VERSION 5.8 ;
BUSBITCHARS "[]" ;
DIVIDERCHAR "/" ;
UNITS
    DATABASE MICRONS 1000 ;
END UNITS

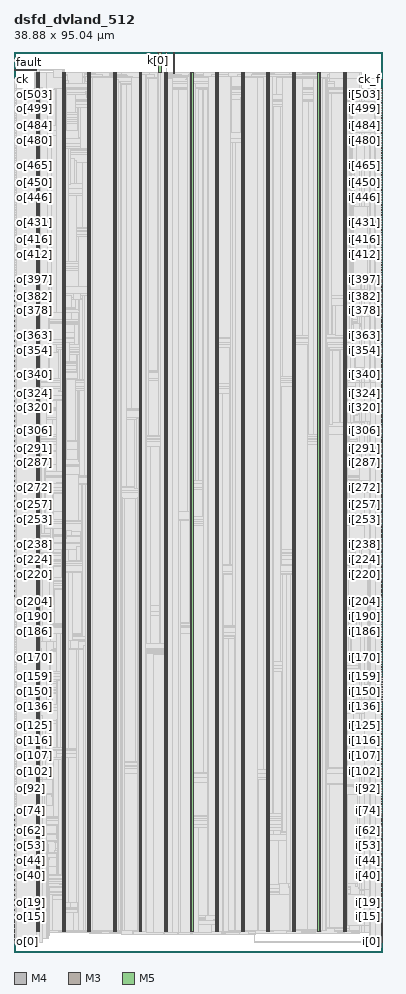
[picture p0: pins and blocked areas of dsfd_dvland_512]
MACRO dsfd_dvland_512
  FOREIGN dsfd_dvland_512 0 0 ;
  CLASS BLOCK ;
  SIZE 38.88 BY 95.04 ;
  PIN ck
    DIRECTION INPUT ;
    USE SIGNAL ;
    PORT
      LAYER M4 ;
        RECT  0 92.112 0.084 92.136 ;
    END
  END ck
  PIN ck_f
    DIRECTION INPUT ;
    USE SIGNAL ;
    PORT
      LAYER M4 ;
        RECT  38.796 92.112 38.88 92.136 ;
    END
  END ck_f
  PIN fault
    DIRECTION OUTPUT ;
    USE SIGNAL ;
    PORT
      LAYER M4 ;
        RECT  0 93.12 0.084 93.144 ;
    END
    PORT
      LAYER M4 ;
        RECT  0.06 93.12 2.408 93.144 ;
    END
  END fault
  PIN i[0]
    DIRECTION INPUT ;
    USE SIGNAL ;
    PORT
      LAYER M4 ;
        RECT  38.796 1.056 38.88 1.08 ;
    END
  END i[0]
  PIN i[100]
    DIRECTION INPUT ;
    USE SIGNAL ;
    PORT
      LAYER M4 ;
        RECT  38.796 18.72 38.88 18.744 ;
    END
  END i[100]
  PIN i[101]
    DIRECTION INPUT ;
    USE SIGNAL ;
    PORT
      LAYER M4 ;
        RECT  38.796 18.864 38.88 18.888 ;
    END
  END i[101]
  PIN i[102]
    DIRECTION INPUT ;
    USE SIGNAL ;
    PORT
      LAYER M4 ;
        RECT  38.796 19.056 38.88 19.08 ;
    END
  END i[102]
  PIN i[103]
    DIRECTION INPUT ;
    USE SIGNAL ;
    PORT
      LAYER M4 ;
        RECT  38.796 19.248 38.88 19.272 ;
    END
  END i[103]
  PIN i[104]
    DIRECTION INPUT ;
    USE SIGNAL ;
    PORT
      LAYER M4 ;
        RECT  38.796 19.392 38.88 19.416 ;
    END
  END i[104]
  PIN i[105]
    DIRECTION INPUT ;
    USE SIGNAL ;
    PORT
      LAYER M4 ;
        RECT  38.796 19.584 38.88 19.608 ;
    END
  END i[105]
  PIN i[106]
    DIRECTION INPUT ;
    USE SIGNAL ;
    PORT
      LAYER M4 ;
        RECT  38.796 19.776 38.88 19.8 ;
    END
  END i[106]
  PIN i[107]
    DIRECTION INPUT ;
    USE SIGNAL ;
    PORT
      LAYER M4 ;
        RECT  38.796 19.92 38.88 19.944 ;
    END
  END i[107]
  PIN i[108]
    DIRECTION INPUT ;
    USE SIGNAL ;
    PORT
      LAYER M4 ;
        RECT  38.796 20.112 38.88 20.136 ;
    END
  END i[108]
  PIN i[109]
    DIRECTION INPUT ;
    USE SIGNAL ;
    PORT
      LAYER M4 ;
        RECT  38.796 20.304 38.88 20.328 ;
    END
  END i[109]
  PIN i[10]
    DIRECTION INPUT ;
    USE SIGNAL ;
    PORT
      LAYER M4 ;
        RECT  38.796 2.832 38.88 2.856 ;
    END
  END i[10]
  PIN i[110]
    DIRECTION INPUT ;
    USE SIGNAL ;
    PORT
      LAYER M4 ;
        RECT  38.796 20.448 38.88 20.472 ;
    END
  END i[110]
  PIN i[111]
    DIRECTION INPUT ;
    USE SIGNAL ;
    PORT
      LAYER M4 ;
        RECT  38.796 20.64 38.88 20.664 ;
    END
  END i[111]
  PIN i[112]
    DIRECTION INPUT ;
    USE SIGNAL ;
    PORT
      LAYER M4 ;
        RECT  38.796 20.832 38.88 20.856 ;
    END
  END i[112]
  PIN i[113]
    DIRECTION INPUT ;
    USE SIGNAL ;
    PORT
      LAYER M4 ;
        RECT  38.796 20.976 38.88 21 ;
    END
  END i[113]
  PIN i[114]
    DIRECTION INPUT ;
    USE SIGNAL ;
    PORT
      LAYER M4 ;
        RECT  38.796 21.168 38.88 21.192 ;
    END
  END i[114]
  PIN i[115]
    DIRECTION INPUT ;
    USE SIGNAL ;
    PORT
      LAYER M4 ;
        RECT  38.796 21.36 38.88 21.384 ;
    END
  END i[115]
  PIN i[116]
    DIRECTION INPUT ;
    USE SIGNAL ;
    PORT
      LAYER M4 ;
        RECT  38.796 21.504 38.88 21.528 ;
    END
  END i[116]
  PIN i[117]
    DIRECTION INPUT ;
    USE SIGNAL ;
    PORT
      LAYER M4 ;
        RECT  38.796 21.696 38.88 21.72 ;
    END
  END i[117]
  PIN i[118]
    DIRECTION INPUT ;
    USE SIGNAL ;
    PORT
      LAYER M4 ;
        RECT  38.796 21.888 38.88 21.912 ;
    END
  END i[118]
  PIN i[119]
    DIRECTION INPUT ;
    USE SIGNAL ;
    PORT
      LAYER M4 ;
        RECT  38.796 22.032 38.88 22.056 ;
    END
  END i[119]
  PIN i[11]
    DIRECTION INPUT ;
    USE SIGNAL ;
    PORT
      LAYER M4 ;
        RECT  38.796 3.024 38.88 3.048 ;
    END
  END i[11]
  PIN i[120]
    DIRECTION INPUT ;
    USE SIGNAL ;
    PORT
      LAYER M4 ;
        RECT  38.796 22.224 38.88 22.248 ;
    END
  END i[120]
  PIN i[121]
    DIRECTION INPUT ;
    USE SIGNAL ;
    PORT
      LAYER M4 ;
        RECT  38.796 22.416 38.88 22.44 ;
    END
  END i[121]
  PIN i[122]
    DIRECTION INPUT ;
    USE SIGNAL ;
    PORT
      LAYER M4 ;
        RECT  38.796 22.56 38.88 22.584 ;
    END
  END i[122]
  PIN i[123]
    DIRECTION INPUT ;
    USE SIGNAL ;
    PORT
      LAYER M4 ;
        RECT  38.796 22.752 38.88 22.776 ;
    END
  END i[123]
  PIN i[124]
    DIRECTION INPUT ;
    USE SIGNAL ;
    PORT
      LAYER M4 ;
        RECT  38.796 22.944 38.88 22.968 ;
    END
  END i[124]
  PIN i[125]
    DIRECTION INPUT ;
    USE SIGNAL ;
    PORT
      LAYER M4 ;
        RECT  38.796 23.088 38.88 23.112 ;
    END
  END i[125]
  PIN i[126]
    DIRECTION INPUT ;
    USE SIGNAL ;
    PORT
      LAYER M4 ;
        RECT  38.796 23.28 38.88 23.304 ;
    END
  END i[126]
  PIN i[127]
    DIRECTION INPUT ;
    USE SIGNAL ;
    PORT
      LAYER M4 ;
        RECT  38.796 23.472 38.88 23.496 ;
    END
  END i[127]
  PIN i[128]
    DIRECTION INPUT ;
    USE SIGNAL ;
    PORT
      LAYER M4 ;
        RECT  38.796 23.616 38.88 23.64 ;
    END
  END i[128]
  PIN i[129]
    DIRECTION INPUT ;
    USE SIGNAL ;
    PORT
      LAYER M4 ;
        RECT  38.796 23.808 38.88 23.832 ;
    END
  END i[129]
  PIN i[12]
    DIRECTION INPUT ;
    USE SIGNAL ;
    PORT
      LAYER M4 ;
        RECT  38.796 3.168 38.88 3.192 ;
    END
  END i[12]
  PIN i[130]
    DIRECTION INPUT ;
    USE SIGNAL ;
    PORT
      LAYER M4 ;
        RECT  38.796 24 38.88 24.024 ;
    END
  END i[130]
  PIN i[131]
    DIRECTION INPUT ;
    USE SIGNAL ;
    PORT
      LAYER M4 ;
        RECT  38.796 24.144 38.88 24.168 ;
    END
  END i[131]
  PIN i[132]
    DIRECTION INPUT ;
    USE SIGNAL ;
    PORT
      LAYER M4 ;
        RECT  38.796 24.336 38.88 24.36 ;
    END
  END i[132]
  PIN i[133]
    DIRECTION INPUT ;
    USE SIGNAL ;
    PORT
      LAYER M4 ;
        RECT  38.796 24.528 38.88 24.552 ;
    END
  END i[133]
  PIN i[134]
    DIRECTION INPUT ;
    USE SIGNAL ;
    PORT
      LAYER M4 ;
        RECT  38.796 24.672 38.88 24.696 ;
    END
  END i[134]
  PIN i[135]
    DIRECTION INPUT ;
    USE SIGNAL ;
    PORT
      LAYER M4 ;
        RECT  38.796 24.864 38.88 24.888 ;
    END
  END i[135]
  PIN i[136]
    DIRECTION INPUT ;
    USE SIGNAL ;
    PORT
      LAYER M4 ;
        RECT  38.796 25.056 38.88 25.08 ;
    END
  END i[136]
  PIN i[137]
    DIRECTION INPUT ;
    USE SIGNAL ;
    PORT
      LAYER M4 ;
        RECT  38.796 25.2 38.88 25.224 ;
    END
  END i[137]
  PIN i[138]
    DIRECTION INPUT ;
    USE SIGNAL ;
    PORT
      LAYER M4 ;
        RECT  38.796 25.392 38.88 25.416 ;
    END
  END i[138]
  PIN i[139]
    DIRECTION INPUT ;
    USE SIGNAL ;
    PORT
      LAYER M4 ;
        RECT  38.796 25.584 38.88 25.608 ;
    END
  END i[139]
  PIN i[13]
    DIRECTION INPUT ;
    USE SIGNAL ;
    PORT
      LAYER M4 ;
        RECT  38.796 3.36 38.88 3.384 ;
    END
  END i[13]
  PIN i[140]
    DIRECTION INPUT ;
    USE SIGNAL ;
    PORT
      LAYER M4 ;
        RECT  38.796 25.728 38.88 25.752 ;
    END
  END i[140]
  PIN i[141]
    DIRECTION INPUT ;
    USE SIGNAL ;
    PORT
      LAYER M4 ;
        RECT  38.796 25.92 38.88 25.944 ;
    END
  END i[141]
  PIN i[142]
    DIRECTION INPUT ;
    USE SIGNAL ;
    PORT
      LAYER M4 ;
        RECT  38.796 26.112 38.88 26.136 ;
    END
  END i[142]
  PIN i[143]
    DIRECTION INPUT ;
    USE SIGNAL ;
    PORT
      LAYER M4 ;
        RECT  38.796 26.304 38.88 26.328 ;
    END
  END i[143]
  PIN i[144]
    DIRECTION INPUT ;
    USE SIGNAL ;
    PORT
      LAYER M4 ;
        RECT  38.796 26.448 38.88 26.472 ;
    END
  END i[144]
  PIN i[145]
    DIRECTION INPUT ;
    USE SIGNAL ;
    PORT
      LAYER M4 ;
        RECT  38.796 26.64 38.88 26.664 ;
    END
  END i[145]
  PIN i[146]
    DIRECTION INPUT ;
    USE SIGNAL ;
    PORT
      LAYER M4 ;
        RECT  38.796 26.832 38.88 26.856 ;
    END
  END i[146]
  PIN i[147]
    DIRECTION INPUT ;
    USE SIGNAL ;
    PORT
      LAYER M4 ;
        RECT  38.796 26.976 38.88 27 ;
    END
  END i[147]
  PIN i[148]
    DIRECTION INPUT ;
    USE SIGNAL ;
    PORT
      LAYER M4 ;
        RECT  38.796 27.168 38.88 27.192 ;
    END
  END i[148]
  PIN i[149]
    DIRECTION INPUT ;
    USE SIGNAL ;
    PORT
      LAYER M4 ;
        RECT  38.796 27.36 38.88 27.384 ;
    END
  END i[149]
  PIN i[14]
    DIRECTION INPUT ;
    USE SIGNAL ;
    PORT
      LAYER M4 ;
        RECT  38.796 3.552 38.88 3.576 ;
    END
  END i[14]
  PIN i[150]
    DIRECTION INPUT ;
    USE SIGNAL ;
    PORT
      LAYER M4 ;
        RECT  38.796 27.504 38.88 27.528 ;
    END
  END i[150]
  PIN i[151]
    DIRECTION INPUT ;
    USE SIGNAL ;
    PORT
      LAYER M4 ;
        RECT  38.796 27.696 38.88 27.72 ;
    END
  END i[151]
  PIN i[152]
    DIRECTION INPUT ;
    USE SIGNAL ;
    PORT
      LAYER M4 ;
        RECT  38.796 27.888 38.88 27.912 ;
    END
  END i[152]
  PIN i[153]
    DIRECTION INPUT ;
    USE SIGNAL ;
    PORT
      LAYER M4 ;
        RECT  38.796 28.032 38.88 28.056 ;
    END
  END i[153]
  PIN i[154]
    DIRECTION INPUT ;
    USE SIGNAL ;
    PORT
      LAYER M4 ;
        RECT  38.796 28.224 38.88 28.248 ;
    END
  END i[154]
  PIN i[155]
    DIRECTION INPUT ;
    USE SIGNAL ;
    PORT
      LAYER M4 ;
        RECT  38.796 28.416 38.88 28.44 ;
    END
  END i[155]
  PIN i[156]
    DIRECTION INPUT ;
    USE SIGNAL ;
    PORT
      LAYER M4 ;
        RECT  38.796 28.56 38.88 28.584 ;
    END
  END i[156]
  PIN i[157]
    DIRECTION INPUT ;
    USE SIGNAL ;
    PORT
      LAYER M4 ;
        RECT  38.796 28.752 38.88 28.776 ;
    END
  END i[157]
  PIN i[158]
    DIRECTION INPUT ;
    USE SIGNAL ;
    PORT
      LAYER M4 ;
        RECT  38.796 28.944 38.88 28.968 ;
    END
  END i[158]
  PIN i[159]
    DIRECTION INPUT ;
    USE SIGNAL ;
    PORT
      LAYER M4 ;
        RECT  38.796 29.088 38.88 29.112 ;
    END
  END i[159]
  PIN i[15]
    DIRECTION INPUT ;
    USE SIGNAL ;
    PORT
      LAYER M4 ;
        RECT  38.796 3.744 38.88 3.768 ;
    END
  END i[15]
  PIN i[160]
    DIRECTION INPUT ;
    USE SIGNAL ;
    PORT
      LAYER M4 ;
        RECT  38.796 29.28 38.88 29.304 ;
    END
  END i[160]
  PIN i[161]
    DIRECTION INPUT ;
    USE SIGNAL ;
    PORT
      LAYER M4 ;
        RECT  38.796 29.472 38.88 29.496 ;
    END
  END i[161]
  PIN i[162]
    DIRECTION INPUT ;
    USE SIGNAL ;
    PORT
      LAYER M4 ;
        RECT  38.796 29.616 38.88 29.64 ;
    END
  END i[162]
  PIN i[163]
    DIRECTION INPUT ;
    USE SIGNAL ;
    PORT
      LAYER M4 ;
        RECT  38.796 29.808 38.88 29.832 ;
    END
  END i[163]
  PIN i[164]
    DIRECTION INPUT ;
    USE SIGNAL ;
    PORT
      LAYER M4 ;
        RECT  38.796 30 38.88 30.024 ;
    END
  END i[164]
  PIN i[165]
    DIRECTION INPUT ;
    USE SIGNAL ;
    PORT
      LAYER M4 ;
        RECT  38.796 30.144 38.88 30.168 ;
    END
  END i[165]
  PIN i[166]
    DIRECTION INPUT ;
    USE SIGNAL ;
    PORT
      LAYER M4 ;
        RECT  38.796 30.336 38.88 30.36 ;
    END
  END i[166]
  PIN i[167]
    DIRECTION INPUT ;
    USE SIGNAL ;
    PORT
      LAYER M4 ;
        RECT  38.796 30.528 38.88 30.552 ;
    END
  END i[167]
  PIN i[168]
    DIRECTION INPUT ;
    USE SIGNAL ;
    PORT
      LAYER M4 ;
        RECT  38.796 30.672 38.88 30.696 ;
    END
  END i[168]
  PIN i[169]
    DIRECTION INPUT ;
    USE SIGNAL ;
    PORT
      LAYER M4 ;
        RECT  38.796 30.864 38.88 30.888 ;
    END
  END i[169]
  PIN i[16]
    DIRECTION INPUT ;
    USE SIGNAL ;
    PORT
      LAYER M4 ;
        RECT  38.796 3.888 38.88 3.912 ;
    END
  END i[16]
  PIN i[170]
    DIRECTION INPUT ;
    USE SIGNAL ;
    PORT
      LAYER M4 ;
        RECT  38.796 31.056 38.88 31.08 ;
    END
  END i[170]
  PIN i[171]
    DIRECTION INPUT ;
    USE SIGNAL ;
    PORT
      LAYER M4 ;
        RECT  38.796 31.2 38.88 31.224 ;
    END
  END i[171]
  PIN i[172]
    DIRECTION INPUT ;
    USE SIGNAL ;
    PORT
      LAYER M4 ;
        RECT  38.796 31.392 38.88 31.416 ;
    END
  END i[172]
  PIN i[173]
    DIRECTION INPUT ;
    USE SIGNAL ;
    PORT
      LAYER M4 ;
        RECT  38.796 31.584 38.88 31.608 ;
    END
  END i[173]
  PIN i[174]
    DIRECTION INPUT ;
    USE SIGNAL ;
    PORT
      LAYER M4 ;
        RECT  38.796 31.728 38.88 31.752 ;
    END
  END i[174]
  PIN i[175]
    DIRECTION INPUT ;
    USE SIGNAL ;
    PORT
      LAYER M4 ;
        RECT  38.796 31.92 38.88 31.944 ;
    END
  END i[175]
  PIN i[176]
    DIRECTION INPUT ;
    USE SIGNAL ;
    PORT
      LAYER M4 ;
        RECT  38.796 32.112 38.88 32.136 ;
    END
  END i[176]
  PIN i[177]
    DIRECTION INPUT ;
    USE SIGNAL ;
    PORT
      LAYER M4 ;
        RECT  38.796 32.256 38.88 32.28 ;
    END
  END i[177]
  PIN i[178]
    DIRECTION INPUT ;
    USE SIGNAL ;
    PORT
      LAYER M4 ;
        RECT  38.796 32.448 38.88 32.472 ;
    END
  END i[178]
  PIN i[179]
    DIRECTION INPUT ;
    USE SIGNAL ;
    PORT
      LAYER M4 ;
        RECT  38.796 32.64 38.88 32.664 ;
    END
  END i[179]
  PIN i[17]
    DIRECTION INPUT ;
    USE SIGNAL ;
    PORT
      LAYER M4 ;
        RECT  38.796 4.08 38.88 4.104 ;
    END
  END i[17]
  PIN i[180]
    DIRECTION INPUT ;
    USE SIGNAL ;
    PORT
      LAYER M4 ;
        RECT  38.796 32.784 38.88 32.808 ;
    END
  END i[180]
  PIN i[181]
    DIRECTION INPUT ;
    USE SIGNAL ;
    PORT
      LAYER M4 ;
        RECT  38.796 32.976 38.88 33 ;
    END
  END i[181]
  PIN i[182]
    DIRECTION INPUT ;
    USE SIGNAL ;
    PORT
      LAYER M4 ;
        RECT  38.796 33.168 38.88 33.192 ;
    END
  END i[182]
  PIN i[183]
    DIRECTION INPUT ;
    USE SIGNAL ;
    PORT
      LAYER M4 ;
        RECT  38.796 33.312 38.88 33.336 ;
    END
  END i[183]
  PIN i[184]
    DIRECTION INPUT ;
    USE SIGNAL ;
    PORT
      LAYER M4 ;
        RECT  38.796 33.504 38.88 33.528 ;
    END
  END i[184]
  PIN i[185]
    DIRECTION INPUT ;
    USE SIGNAL ;
    PORT
      LAYER M4 ;
        RECT  38.796 33.696 38.88 33.72 ;
    END
  END i[185]
  PIN i[186]
    DIRECTION INPUT ;
    USE SIGNAL ;
    PORT
      LAYER M4 ;
        RECT  38.796 33.84 38.88 33.864 ;
    END
  END i[186]
  PIN i[187]
    DIRECTION INPUT ;
    USE SIGNAL ;
    PORT
      LAYER M4 ;
        RECT  38.796 34.032 38.88 34.056 ;
    END
  END i[187]
  PIN i[188]
    DIRECTION INPUT ;
    USE SIGNAL ;
    PORT
      LAYER M4 ;
        RECT  38.796 34.224 38.88 34.248 ;
    END
  END i[188]
  PIN i[189]
    DIRECTION INPUT ;
    USE SIGNAL ;
    PORT
      LAYER M4 ;
        RECT  38.796 34.368 38.88 34.392 ;
    END
  END i[189]
  PIN i[18]
    DIRECTION INPUT ;
    USE SIGNAL ;
    PORT
      LAYER M4 ;
        RECT  38.796 4.272 38.88 4.296 ;
    END
  END i[18]
  PIN i[190]
    DIRECTION INPUT ;
    USE SIGNAL ;
    PORT
      LAYER M4 ;
        RECT  38.796 34.56 38.88 34.584 ;
    END
  END i[190]
  PIN i[191]
    DIRECTION INPUT ;
    USE SIGNAL ;
    PORT
      LAYER M4 ;
        RECT  38.796 34.752 38.88 34.776 ;
    END
  END i[191]
  PIN i[192]
    DIRECTION INPUT ;
    USE SIGNAL ;
    PORT
      LAYER M4 ;
        RECT  38.796 34.896 38.88 34.92 ;
    END
  END i[192]
  PIN i[193]
    DIRECTION INPUT ;
    USE SIGNAL ;
    PORT
      LAYER M4 ;
        RECT  38.796 35.088 38.88 35.112 ;
    END
  END i[193]
  PIN i[194]
    DIRECTION INPUT ;
    USE SIGNAL ;
    PORT
      LAYER M4 ;
        RECT  38.796 35.28 38.88 35.304 ;
    END
  END i[194]
  PIN i[195]
    DIRECTION INPUT ;
    USE SIGNAL ;
    PORT
      LAYER M4 ;
        RECT  38.796 35.424 38.88 35.448 ;
    END
  END i[195]
  PIN i[196]
    DIRECTION INPUT ;
    USE SIGNAL ;
    PORT
      LAYER M4 ;
        RECT  38.796 35.616 38.88 35.64 ;
    END
  END i[196]
  PIN i[197]
    DIRECTION INPUT ;
    USE SIGNAL ;
    PORT
      LAYER M4 ;
        RECT  38.796 35.808 38.88 35.832 ;
    END
  END i[197]
  PIN i[198]
    DIRECTION INPUT ;
    USE SIGNAL ;
    PORT
      LAYER M4 ;
        RECT  38.796 35.952 38.88 35.976 ;
    END
  END i[198]
  PIN i[199]
    DIRECTION INPUT ;
    USE SIGNAL ;
    PORT
      LAYER M4 ;
        RECT  38.796 36.144 38.88 36.168 ;
    END
  END i[199]
  PIN i[19]
    DIRECTION INPUT ;
    USE SIGNAL ;
    PORT
      LAYER M4 ;
        RECT  38.796 4.416 38.88 4.44 ;
    END
  END i[19]
  PIN i[1]
    DIRECTION INPUT ;
    USE SIGNAL ;
    PORT
      LAYER M4 ;
        RECT  38.796 1.248 38.88 1.272 ;
    END
  END i[1]
  PIN i[200]
    DIRECTION INPUT ;
    USE SIGNAL ;
    PORT
      LAYER M4 ;
        RECT  38.796 36.336 38.88 36.36 ;
    END
  END i[200]
  PIN i[201]
    DIRECTION INPUT ;
    USE SIGNAL ;
    PORT
      LAYER M4 ;
        RECT  38.796 36.48 38.88 36.504 ;
    END
  END i[201]
  PIN i[202]
    DIRECTION INPUT ;
    USE SIGNAL ;
    PORT
      LAYER M4 ;
        RECT  38.796 36.672 38.88 36.696 ;
    END
  END i[202]
  PIN i[203]
    DIRECTION INPUT ;
    USE SIGNAL ;
    PORT
      LAYER M4 ;
        RECT  38.796 36.864 38.88 36.888 ;
    END
  END i[203]
  PIN i[204]
    DIRECTION INPUT ;
    USE SIGNAL ;
    PORT
      LAYER M4 ;
        RECT  38.796 37.008 38.88 37.032 ;
    END
  END i[204]
  PIN i[205]
    DIRECTION INPUT ;
    USE SIGNAL ;
    PORT
      LAYER M4 ;
        RECT  38.796 37.2 38.88 37.224 ;
    END
  END i[205]
  PIN i[206]
    DIRECTION INPUT ;
    USE SIGNAL ;
    PORT
      LAYER M4 ;
        RECT  38.796 37.392 38.88 37.416 ;
    END
  END i[206]
  PIN i[207]
    DIRECTION INPUT ;
    USE SIGNAL ;
    PORT
      LAYER M4 ;
        RECT  38.796 37.584 38.88 37.608 ;
    END
  END i[207]
  PIN i[208]
    DIRECTION INPUT ;
    USE SIGNAL ;
    PORT
      LAYER M4 ;
        RECT  38.796 37.728 38.88 37.752 ;
    END
  END i[208]
  PIN i[209]
    DIRECTION INPUT ;
    USE SIGNAL ;
    PORT
      LAYER M4 ;
        RECT  38.796 37.92 38.88 37.944 ;
    END
  END i[209]
  PIN i[20]
    DIRECTION INPUT ;
    USE SIGNAL ;
    PORT
      LAYER M4 ;
        RECT  38.796 4.608 38.88 4.632 ;
    END
  END i[20]
  PIN i[210]
    DIRECTION INPUT ;
    USE SIGNAL ;
    PORT
      LAYER M4 ;
        RECT  38.796 38.112 38.88 38.136 ;
    END
  END i[210]
  PIN i[211]
    DIRECTION INPUT ;
    USE SIGNAL ;
    PORT
      LAYER M4 ;
        RECT  38.796 38.256 38.88 38.28 ;
    END
  END i[211]
  PIN i[212]
    DIRECTION INPUT ;
    USE SIGNAL ;
    PORT
      LAYER M4 ;
        RECT  38.796 38.448 38.88 38.472 ;
    END
  END i[212]
  PIN i[213]
    DIRECTION INPUT ;
    USE SIGNAL ;
    PORT
      LAYER M4 ;
        RECT  38.796 38.64 38.88 38.664 ;
    END
  END i[213]
  PIN i[214]
    DIRECTION INPUT ;
    USE SIGNAL ;
    PORT
      LAYER M4 ;
        RECT  38.796 38.784 38.88 38.808 ;
    END
  END i[214]
  PIN i[215]
    DIRECTION INPUT ;
    USE SIGNAL ;
    PORT
      LAYER M4 ;
        RECT  38.796 38.976 38.88 39 ;
    END
  END i[215]
  PIN i[216]
    DIRECTION INPUT ;
    USE SIGNAL ;
    PORT
      LAYER M4 ;
        RECT  38.796 39.168 38.88 39.192 ;
    END
  END i[216]
  PIN i[217]
    DIRECTION INPUT ;
    USE SIGNAL ;
    PORT
      LAYER M4 ;
        RECT  38.796 39.312 38.88 39.336 ;
    END
  END i[217]
  PIN i[218]
    DIRECTION INPUT ;
    USE SIGNAL ;
    PORT
      LAYER M4 ;
        RECT  38.796 39.504 38.88 39.528 ;
    END
  END i[218]
  PIN i[219]
    DIRECTION INPUT ;
    USE SIGNAL ;
    PORT
      LAYER M4 ;
        RECT  38.796 39.696 38.88 39.72 ;
    END
  END i[219]
  PIN i[21]
    DIRECTION INPUT ;
    USE SIGNAL ;
    PORT
      LAYER M4 ;
        RECT  38.796 4.8 38.88 4.824 ;
    END
  END i[21]
  PIN i[220]
    DIRECTION INPUT ;
    USE SIGNAL ;
    PORT
      LAYER M4 ;
        RECT  38.796 39.84 38.88 39.864 ;
    END
  END i[220]
  PIN i[221]
    DIRECTION INPUT ;
    USE SIGNAL ;
    PORT
      LAYER M4 ;
        RECT  38.796 40.032 38.88 40.056 ;
    END
  END i[221]
  PIN i[222]
    DIRECTION INPUT ;
    USE SIGNAL ;
    PORT
      LAYER M4 ;
        RECT  38.796 40.224 38.88 40.248 ;
    END
  END i[222]
  PIN i[223]
    DIRECTION INPUT ;
    USE SIGNAL ;
    PORT
      LAYER M4 ;
        RECT  38.796 40.368 38.88 40.392 ;
    END
  END i[223]
  PIN i[224]
    DIRECTION INPUT ;
    USE SIGNAL ;
    PORT
      LAYER M4 ;
        RECT  38.796 40.56 38.88 40.584 ;
    END
  END i[224]
  PIN i[225]
    DIRECTION INPUT ;
    USE SIGNAL ;
    PORT
      LAYER M4 ;
        RECT  38.796 40.752 38.88 40.776 ;
    END
  END i[225]
  PIN i[226]
    DIRECTION INPUT ;
    USE SIGNAL ;
    PORT
      LAYER M4 ;
        RECT  38.796 40.896 38.88 40.92 ;
    END
  END i[226]
  PIN i[227]
    DIRECTION INPUT ;
    USE SIGNAL ;
    PORT
      LAYER M4 ;
        RECT  38.796 41.088 38.88 41.112 ;
    END
  END i[227]
  PIN i[228]
    DIRECTION INPUT ;
    USE SIGNAL ;
    PORT
      LAYER M4 ;
        RECT  38.796 41.28 38.88 41.304 ;
    END
  END i[228]
  PIN i[229]
    DIRECTION INPUT ;
    USE SIGNAL ;
    PORT
      LAYER M4 ;
        RECT  38.796 41.424 38.88 41.448 ;
    END
  END i[229]
  PIN i[22]
    DIRECTION INPUT ;
    USE SIGNAL ;
    PORT
      LAYER M4 ;
        RECT  38.796 4.944 38.88 4.968 ;
    END
  END i[22]
  PIN i[230]
    DIRECTION INPUT ;
    USE SIGNAL ;
    PORT
      LAYER M4 ;
        RECT  38.796 41.616 38.88 41.64 ;
    END
  END i[230]
  PIN i[231]
    DIRECTION INPUT ;
    USE SIGNAL ;
    PORT
      LAYER M4 ;
        RECT  38.796 41.808 38.88 41.832 ;
    END
  END i[231]
  PIN i[232]
    DIRECTION INPUT ;
    USE SIGNAL ;
    PORT
      LAYER M4 ;
        RECT  38.796 41.952 38.88 41.976 ;
    END
  END i[232]
  PIN i[233]
    DIRECTION INPUT ;
    USE SIGNAL ;
    PORT
      LAYER M4 ;
        RECT  38.796 42.144 38.88 42.168 ;
    END
  END i[233]
  PIN i[234]
    DIRECTION INPUT ;
    USE SIGNAL ;
    PORT
      LAYER M4 ;
        RECT  38.796 42.336 38.88 42.36 ;
    END
  END i[234]
  PIN i[235]
    DIRECTION INPUT ;
    USE SIGNAL ;
    PORT
      LAYER M4 ;
        RECT  38.796 42.48 38.88 42.504 ;
    END
  END i[235]
  PIN i[236]
    DIRECTION INPUT ;
    USE SIGNAL ;
    PORT
      LAYER M4 ;
        RECT  38.796 42.672 38.88 42.696 ;
    END
  END i[236]
  PIN i[237]
    DIRECTION INPUT ;
    USE SIGNAL ;
    PORT
      LAYER M4 ;
        RECT  38.796 42.864 38.88 42.888 ;
    END
  END i[237]
  PIN i[238]
    DIRECTION INPUT ;
    USE SIGNAL ;
    PORT
      LAYER M4 ;
        RECT  38.796 43.008 38.88 43.032 ;
    END
  END i[238]
  PIN i[239]
    DIRECTION INPUT ;
    USE SIGNAL ;
    PORT
      LAYER M4 ;
        RECT  38.796 43.2 38.88 43.224 ;
    END
  END i[239]
  PIN i[23]
    DIRECTION INPUT ;
    USE SIGNAL ;
    PORT
      LAYER M4 ;
        RECT  38.796 5.136 38.88 5.16 ;
    END
  END i[23]
  PIN i[240]
    DIRECTION INPUT ;
    USE SIGNAL ;
    PORT
      LAYER M4 ;
        RECT  38.796 43.392 38.88 43.416 ;
    END
  END i[240]
  PIN i[241]
    DIRECTION INPUT ;
    USE SIGNAL ;
    PORT
      LAYER M4 ;
        RECT  38.796 43.536 38.88 43.56 ;
    END
  END i[241]
  PIN i[242]
    DIRECTION INPUT ;
    USE SIGNAL ;
    PORT
      LAYER M4 ;
        RECT  38.796 43.728 38.88 43.752 ;
    END
  END i[242]
  PIN i[243]
    DIRECTION INPUT ;
    USE SIGNAL ;
    PORT
      LAYER M4 ;
        RECT  38.796 43.92 38.88 43.944 ;
    END
  END i[243]
  PIN i[244]
    DIRECTION INPUT ;
    USE SIGNAL ;
    PORT
      LAYER M4 ;
        RECT  38.796 44.064 38.88 44.088 ;
    END
  END i[244]
  PIN i[245]
    DIRECTION INPUT ;
    USE SIGNAL ;
    PORT
      LAYER M4 ;
        RECT  38.796 44.256 38.88 44.28 ;
    END
  END i[245]
  PIN i[246]
    DIRECTION INPUT ;
    USE SIGNAL ;
    PORT
      LAYER M4 ;
        RECT  38.796 44.448 38.88 44.472 ;
    END
  END i[246]
  PIN i[247]
    DIRECTION INPUT ;
    USE SIGNAL ;
    PORT
      LAYER M4 ;
        RECT  38.796 44.592 38.88 44.616 ;
    END
  END i[247]
  PIN i[248]
    DIRECTION INPUT ;
    USE SIGNAL ;
    PORT
      LAYER M4 ;
        RECT  38.796 44.784 38.88 44.808 ;
    END
  END i[248]
  PIN i[249]
    DIRECTION INPUT ;
    USE SIGNAL ;
    PORT
      LAYER M4 ;
        RECT  38.796 44.976 38.88 45 ;
    END
  END i[249]
  PIN i[24]
    DIRECTION INPUT ;
    USE SIGNAL ;
    PORT
      LAYER M4 ;
        RECT  38.796 5.328 38.88 5.352 ;
    END
  END i[24]
  PIN i[250]
    DIRECTION INPUT ;
    USE SIGNAL ;
    PORT
      LAYER M4 ;
        RECT  38.796 45.12 38.88 45.144 ;
    END
  END i[250]
  PIN i[251]
    DIRECTION INPUT ;
    USE SIGNAL ;
    PORT
      LAYER M4 ;
        RECT  38.796 45.312 38.88 45.336 ;
    END
  END i[251]
  PIN i[252]
    DIRECTION INPUT ;
    USE SIGNAL ;
    PORT
      LAYER M4 ;
        RECT  38.796 45.504 38.88 45.528 ;
    END
  END i[252]
  PIN i[253]
    DIRECTION INPUT ;
    USE SIGNAL ;
    PORT
      LAYER M4 ;
        RECT  38.796 45.648 38.88 45.672 ;
    END
  END i[253]
  PIN i[254]
    DIRECTION INPUT ;
    USE SIGNAL ;
    PORT
      LAYER M4 ;
        RECT  38.796 45.84 38.88 45.864 ;
    END
  END i[254]
  PIN i[255]
    DIRECTION INPUT ;
    USE SIGNAL ;
    PORT
      LAYER M4 ;
        RECT  38.796 46.032 38.88 46.056 ;
    END
  END i[255]
  PIN i[256]
    DIRECTION INPUT ;
    USE SIGNAL ;
    PORT
      LAYER M4 ;
        RECT  38.796 46.176 38.88 46.2 ;
    END
  END i[256]
  PIN i[257]
    DIRECTION INPUT ;
    USE SIGNAL ;
    PORT
      LAYER M4 ;
        RECT  38.796 46.368 38.88 46.392 ;
    END
  END i[257]
  PIN i[258]
    DIRECTION INPUT ;
    USE SIGNAL ;
    PORT
      LAYER M4 ;
        RECT  38.796 46.56 38.88 46.584 ;
    END
  END i[258]
  PIN i[259]
    DIRECTION INPUT ;
    USE SIGNAL ;
    PORT
      LAYER M4 ;
        RECT  38.796 46.704 38.88 46.728 ;
    END
  END i[259]
  PIN i[25]
    DIRECTION INPUT ;
    USE SIGNAL ;
    PORT
      LAYER M4 ;
        RECT  38.796 5.472 38.88 5.496 ;
    END
  END i[25]
  PIN i[260]
    DIRECTION INPUT ;
    USE SIGNAL ;
    PORT
      LAYER M4 ;
        RECT  38.796 46.896 38.88 46.92 ;
    END
  END i[260]
  PIN i[261]
    DIRECTION INPUT ;
    USE SIGNAL ;
    PORT
      LAYER M4 ;
        RECT  38.796 47.088 38.88 47.112 ;
    END
  END i[261]
  PIN i[262]
    DIRECTION INPUT ;
    USE SIGNAL ;
    PORT
      LAYER M4 ;
        RECT  38.796 47.232 38.88 47.256 ;
    END
  END i[262]
  PIN i[263]
    DIRECTION INPUT ;
    USE SIGNAL ;
    PORT
      LAYER M4 ;
        RECT  38.796 47.424 38.88 47.448 ;
    END
  END i[263]
  PIN i[264]
    DIRECTION INPUT ;
    USE SIGNAL ;
    PORT
      LAYER M4 ;
        RECT  38.796 47.616 38.88 47.64 ;
    END
  END i[264]
  PIN i[265]
    DIRECTION INPUT ;
    USE SIGNAL ;
    PORT
      LAYER M4 ;
        RECT  38.796 47.76 38.88 47.784 ;
    END
  END i[265]
  PIN i[266]
    DIRECTION INPUT ;
    USE SIGNAL ;
    PORT
      LAYER M4 ;
        RECT  38.796 47.952 38.88 47.976 ;
    END
  END i[266]
  PIN i[267]
    DIRECTION INPUT ;
    USE SIGNAL ;
    PORT
      LAYER M4 ;
        RECT  38.796 48.144 38.88 48.168 ;
    END
  END i[267]
  PIN i[268]
    DIRECTION INPUT ;
    USE SIGNAL ;
    PORT
      LAYER M4 ;
        RECT  38.796 48.288 38.88 48.312 ;
    END
  END i[268]
  PIN i[269]
    DIRECTION INPUT ;
    USE SIGNAL ;
    PORT
      LAYER M4 ;
        RECT  38.796 48.48 38.88 48.504 ;
    END
  END i[269]
  PIN i[26]
    DIRECTION INPUT ;
    USE SIGNAL ;
    PORT
      LAYER M4 ;
        RECT  38.796 5.664 38.88 5.688 ;
    END
  END i[26]
  PIN i[270]
    DIRECTION INPUT ;
    USE SIGNAL ;
    PORT
      LAYER M4 ;
        RECT  38.796 48.672 38.88 48.696 ;
    END
  END i[270]
  PIN i[271]
    DIRECTION INPUT ;
    USE SIGNAL ;
    PORT
      LAYER M4 ;
        RECT  38.796 48.864 38.88 48.888 ;
    END
  END i[271]
  PIN i[272]
    DIRECTION INPUT ;
    USE SIGNAL ;
    PORT
      LAYER M4 ;
        RECT  38.796 49.008 38.88 49.032 ;
    END
  END i[272]
  PIN i[273]
    DIRECTION INPUT ;
    USE SIGNAL ;
    PORT
      LAYER M4 ;
        RECT  38.796 49.2 38.88 49.224 ;
    END
  END i[273]
  PIN i[274]
    DIRECTION INPUT ;
    USE SIGNAL ;
    PORT
      LAYER M4 ;
        RECT  38.796 49.392 38.88 49.416 ;
    END
  END i[274]
  PIN i[275]
    DIRECTION INPUT ;
    USE SIGNAL ;
    PORT
      LAYER M4 ;
        RECT  38.796 49.536 38.88 49.56 ;
    END
  END i[275]
  PIN i[276]
    DIRECTION INPUT ;
    USE SIGNAL ;
    PORT
      LAYER M4 ;
        RECT  38.796 49.728 38.88 49.752 ;
    END
  END i[276]
  PIN i[277]
    DIRECTION INPUT ;
    USE SIGNAL ;
    PORT
      LAYER M4 ;
        RECT  38.796 49.92 38.88 49.944 ;
    END
  END i[277]
  PIN i[278]
    DIRECTION INPUT ;
    USE SIGNAL ;
    PORT
      LAYER M4 ;
        RECT  38.796 50.064 38.88 50.088 ;
    END
  END i[278]
  PIN i[279]
    DIRECTION INPUT ;
    USE SIGNAL ;
    PORT
      LAYER M4 ;
        RECT  38.796 50.256 38.88 50.28 ;
    END
  END i[279]
  PIN i[27]
    DIRECTION INPUT ;
    USE SIGNAL ;
    PORT
      LAYER M4 ;
        RECT  38.796 5.856 38.88 5.88 ;
    END
  END i[27]
  PIN i[280]
    DIRECTION INPUT ;
    USE SIGNAL ;
    PORT
      LAYER M4 ;
        RECT  38.796 50.448 38.88 50.472 ;
    END
  END i[280]
  PIN i[281]
    DIRECTION INPUT ;
    USE SIGNAL ;
    PORT
      LAYER M4 ;
        RECT  38.796 50.592 38.88 50.616 ;
    END
  END i[281]
  PIN i[282]
    DIRECTION INPUT ;
    USE SIGNAL ;
    PORT
      LAYER M4 ;
        RECT  38.796 50.784 38.88 50.808 ;
    END
  END i[282]
  PIN i[283]
    DIRECTION INPUT ;
    USE SIGNAL ;
    PORT
      LAYER M4 ;
        RECT  38.796 50.976 38.88 51 ;
    END
  END i[283]
  PIN i[284]
    DIRECTION INPUT ;
    USE SIGNAL ;
    PORT
      LAYER M4 ;
        RECT  38.796 51.12 38.88 51.144 ;
    END
  END i[284]
  PIN i[285]
    DIRECTION INPUT ;
    USE SIGNAL ;
    PORT
      LAYER M4 ;
        RECT  38.796 51.312 38.88 51.336 ;
    END
  END i[285]
  PIN i[286]
    DIRECTION INPUT ;
    USE SIGNAL ;
    PORT
      LAYER M4 ;
        RECT  38.796 51.504 38.88 51.528 ;
    END
  END i[286]
  PIN i[287]
    DIRECTION INPUT ;
    USE SIGNAL ;
    PORT
      LAYER M4 ;
        RECT  38.796 51.648 38.88 51.672 ;
    END
  END i[287]
  PIN i[288]
    DIRECTION INPUT ;
    USE SIGNAL ;
    PORT
      LAYER M4 ;
        RECT  38.796 51.84 38.88 51.864 ;
    END
  END i[288]
  PIN i[289]
    DIRECTION INPUT ;
    USE SIGNAL ;
    PORT
      LAYER M4 ;
        RECT  38.796 52.032 38.88 52.056 ;
    END
  END i[289]
  PIN i[28]
    DIRECTION INPUT ;
    USE SIGNAL ;
    PORT
      LAYER M4 ;
        RECT  38.796 6 38.88 6.024 ;
    END
  END i[28]
  PIN i[290]
    DIRECTION INPUT ;
    USE SIGNAL ;
    PORT
      LAYER M4 ;
        RECT  38.796 52.176 38.88 52.2 ;
    END
  END i[290]
  PIN i[291]
    DIRECTION INPUT ;
    USE SIGNAL ;
    PORT
      LAYER M4 ;
        RECT  38.796 52.368 38.88 52.392 ;
    END
  END i[291]
  PIN i[292]
    DIRECTION INPUT ;
    USE SIGNAL ;
    PORT
      LAYER M4 ;
        RECT  38.796 52.56 38.88 52.584 ;
    END
  END i[292]
  PIN i[293]
    DIRECTION INPUT ;
    USE SIGNAL ;
    PORT
      LAYER M4 ;
        RECT  38.796 52.704 38.88 52.728 ;
    END
  END i[293]
  PIN i[294]
    DIRECTION INPUT ;
    USE SIGNAL ;
    PORT
      LAYER M4 ;
        RECT  38.796 52.896 38.88 52.92 ;
    END
  END i[294]
  PIN i[295]
    DIRECTION INPUT ;
    USE SIGNAL ;
    PORT
      LAYER M4 ;
        RECT  38.796 53.088 38.88 53.112 ;
    END
  END i[295]
  PIN i[296]
    DIRECTION INPUT ;
    USE SIGNAL ;
    PORT
      LAYER M4 ;
        RECT  38.796 53.232 38.88 53.256 ;
    END
  END i[296]
  PIN i[297]
    DIRECTION INPUT ;
    USE SIGNAL ;
    PORT
      LAYER M4 ;
        RECT  38.796 53.424 38.88 53.448 ;
    END
  END i[297]
  PIN i[298]
    DIRECTION INPUT ;
    USE SIGNAL ;
    PORT
      LAYER M4 ;
        RECT  38.796 53.616 38.88 53.64 ;
    END
  END i[298]
  PIN i[299]
    DIRECTION INPUT ;
    USE SIGNAL ;
    PORT
      LAYER M4 ;
        RECT  38.796 53.76 38.88 53.784 ;
    END
  END i[299]
  PIN i[29]
    DIRECTION INPUT ;
    USE SIGNAL ;
    PORT
      LAYER M4 ;
        RECT  38.796 6.192 38.88 6.216 ;
    END
  END i[29]
  PIN i[2]
    DIRECTION INPUT ;
    USE SIGNAL ;
    PORT
      LAYER M4 ;
        RECT  38.796 1.44 38.88 1.464 ;
    END
  END i[2]
  PIN i[300]
    DIRECTION INPUT ;
    USE SIGNAL ;
    PORT
      LAYER M4 ;
        RECT  38.796 53.952 38.88 53.976 ;
    END
  END i[300]
  PIN i[301]
    DIRECTION INPUT ;
    USE SIGNAL ;
    PORT
      LAYER M4 ;
        RECT  38.796 54.144 38.88 54.168 ;
    END
  END i[301]
  PIN i[302]
    DIRECTION INPUT ;
    USE SIGNAL ;
    PORT
      LAYER M4 ;
        RECT  38.796 54.288 38.88 54.312 ;
    END
  END i[302]
  PIN i[303]
    DIRECTION INPUT ;
    USE SIGNAL ;
    PORT
      LAYER M4 ;
        RECT  38.796 54.48 38.88 54.504 ;
    END
  END i[303]
  PIN i[304]
    DIRECTION INPUT ;
    USE SIGNAL ;
    PORT
      LAYER M4 ;
        RECT  38.796 54.672 38.88 54.696 ;
    END
  END i[304]
  PIN i[305]
    DIRECTION INPUT ;
    USE SIGNAL ;
    PORT
      LAYER M4 ;
        RECT  38.796 54.816 38.88 54.84 ;
    END
  END i[305]
  PIN i[306]
    DIRECTION INPUT ;
    USE SIGNAL ;
    PORT
      LAYER M4 ;
        RECT  38.796 55.008 38.88 55.032 ;
    END
  END i[306]
  PIN i[307]
    DIRECTION INPUT ;
    USE SIGNAL ;
    PORT
      LAYER M4 ;
        RECT  38.796 55.2 38.88 55.224 ;
    END
  END i[307]
  PIN i[308]
    DIRECTION INPUT ;
    USE SIGNAL ;
    PORT
      LAYER M4 ;
        RECT  38.796 55.344 38.88 55.368 ;
    END
  END i[308]
  PIN i[309]
    DIRECTION INPUT ;
    USE SIGNAL ;
    PORT
      LAYER M4 ;
        RECT  38.796 55.536 38.88 55.56 ;
    END
  END i[309]
  PIN i[30]
    DIRECTION INPUT ;
    USE SIGNAL ;
    PORT
      LAYER M4 ;
        RECT  38.796 6.384 38.88 6.408 ;
    END
  END i[30]
  PIN i[310]
    DIRECTION INPUT ;
    USE SIGNAL ;
    PORT
      LAYER M4 ;
        RECT  38.796 55.728 38.88 55.752 ;
    END
  END i[310]
  PIN i[311]
    DIRECTION INPUT ;
    USE SIGNAL ;
    PORT
      LAYER M4 ;
        RECT  38.796 55.872 38.88 55.896 ;
    END
  END i[311]
  PIN i[312]
    DIRECTION INPUT ;
    USE SIGNAL ;
    PORT
      LAYER M4 ;
        RECT  38.796 56.064 38.88 56.088 ;
    END
  END i[312]
  PIN i[313]
    DIRECTION INPUT ;
    USE SIGNAL ;
    PORT
      LAYER M4 ;
        RECT  38.796 56.256 38.88 56.28 ;
    END
  END i[313]
  PIN i[314]
    DIRECTION INPUT ;
    USE SIGNAL ;
    PORT
      LAYER M4 ;
        RECT  38.796 56.4 38.88 56.424 ;
    END
  END i[314]
  PIN i[315]
    DIRECTION INPUT ;
    USE SIGNAL ;
    PORT
      LAYER M4 ;
        RECT  38.796 56.592 38.88 56.616 ;
    END
  END i[315]
  PIN i[316]
    DIRECTION INPUT ;
    USE SIGNAL ;
    PORT
      LAYER M4 ;
        RECT  38.796 56.784 38.88 56.808 ;
    END
  END i[316]
  PIN i[317]
    DIRECTION INPUT ;
    USE SIGNAL ;
    PORT
      LAYER M4 ;
        RECT  38.796 56.928 38.88 56.952 ;
    END
  END i[317]
  PIN i[318]
    DIRECTION INPUT ;
    USE SIGNAL ;
    PORT
      LAYER M4 ;
        RECT  38.796 57.12 38.88 57.144 ;
    END
  END i[318]
  PIN i[319]
    DIRECTION INPUT ;
    USE SIGNAL ;
    PORT
      LAYER M4 ;
        RECT  38.796 57.312 38.88 57.336 ;
    END
  END i[319]
  PIN i[31]
    DIRECTION INPUT ;
    USE SIGNAL ;
    PORT
      LAYER M4 ;
        RECT  38.796 6.528 38.88 6.552 ;
    END
  END i[31]
  PIN i[320]
    DIRECTION INPUT ;
    USE SIGNAL ;
    PORT
      LAYER M4 ;
        RECT  38.796 57.456 38.88 57.48 ;
    END
  END i[320]
  PIN i[321]
    DIRECTION INPUT ;
    USE SIGNAL ;
    PORT
      LAYER M4 ;
        RECT  38.796 57.648 38.88 57.672 ;
    END
  END i[321]
  PIN i[322]
    DIRECTION INPUT ;
    USE SIGNAL ;
    PORT
      LAYER M4 ;
        RECT  38.796 57.84 38.88 57.864 ;
    END
  END i[322]
  PIN i[323]
    DIRECTION INPUT ;
    USE SIGNAL ;
    PORT
      LAYER M4 ;
        RECT  38.796 57.984 38.88 58.008 ;
    END
  END i[323]
  PIN i[324]
    DIRECTION INPUT ;
    USE SIGNAL ;
    PORT
      LAYER M4 ;
        RECT  38.796 58.176 38.88 58.2 ;
    END
  END i[324]
  PIN i[325]
    DIRECTION INPUT ;
    USE SIGNAL ;
    PORT
      LAYER M4 ;
        RECT  38.796 58.368 38.88 58.392 ;
    END
  END i[325]
  PIN i[326]
    DIRECTION INPUT ;
    USE SIGNAL ;
    PORT
      LAYER M4 ;
        RECT  38.796 58.512 38.88 58.536 ;
    END
  END i[326]
  PIN i[327]
    DIRECTION INPUT ;
    USE SIGNAL ;
    PORT
      LAYER M4 ;
        RECT  38.796 58.704 38.88 58.728 ;
    END
  END i[327]
  PIN i[328]
    DIRECTION INPUT ;
    USE SIGNAL ;
    PORT
      LAYER M4 ;
        RECT  38.796 58.896 38.88 58.92 ;
    END
  END i[328]
  PIN i[329]
    DIRECTION INPUT ;
    USE SIGNAL ;
    PORT
      LAYER M4 ;
        RECT  38.796 59.04 38.88 59.064 ;
    END
  END i[329]
  PIN i[32]
    DIRECTION INPUT ;
    USE SIGNAL ;
    PORT
      LAYER M4 ;
        RECT  38.796 6.72 38.88 6.744 ;
    END
  END i[32]
  PIN i[330]
    DIRECTION INPUT ;
    USE SIGNAL ;
    PORT
      LAYER M4 ;
        RECT  38.796 59.232 38.88 59.256 ;
    END
  END i[330]
  PIN i[331]
    DIRECTION INPUT ;
    USE SIGNAL ;
    PORT
      LAYER M4 ;
        RECT  38.796 59.424 38.88 59.448 ;
    END
  END i[331]
  PIN i[332]
    DIRECTION INPUT ;
    USE SIGNAL ;
    PORT
      LAYER M4 ;
        RECT  38.796 59.568 38.88 59.592 ;
    END
  END i[332]
  PIN i[333]
    DIRECTION INPUT ;
    USE SIGNAL ;
    PORT
      LAYER M4 ;
        RECT  38.796 59.76 38.88 59.784 ;
    END
  END i[333]
  PIN i[334]
    DIRECTION INPUT ;
    USE SIGNAL ;
    PORT
      LAYER M4 ;
        RECT  38.796 59.952 38.88 59.976 ;
    END
  END i[334]
  PIN i[335]
    DIRECTION INPUT ;
    USE SIGNAL ;
    PORT
      LAYER M4 ;
        RECT  38.796 60.144 38.88 60.168 ;
    END
  END i[335]
  PIN i[336]
    DIRECTION INPUT ;
    USE SIGNAL ;
    PORT
      LAYER M4 ;
        RECT  38.796 60.288 38.88 60.312 ;
    END
  END i[336]
  PIN i[337]
    DIRECTION INPUT ;
    USE SIGNAL ;
    PORT
      LAYER M4 ;
        RECT  38.796 60.48 38.88 60.504 ;
    END
  END i[337]
  PIN i[338]
    DIRECTION INPUT ;
    USE SIGNAL ;
    PORT
      LAYER M4 ;
        RECT  38.796 60.672 38.88 60.696 ;
    END
  END i[338]
  PIN i[339]
    DIRECTION INPUT ;
    USE SIGNAL ;
    PORT
      LAYER M4 ;
        RECT  38.796 60.816 38.88 60.84 ;
    END
  END i[339]
  PIN i[33]
    DIRECTION INPUT ;
    USE SIGNAL ;
    PORT
      LAYER M4 ;
        RECT  38.796 6.912 38.88 6.936 ;
    END
  END i[33]
  PIN i[340]
    DIRECTION INPUT ;
    USE SIGNAL ;
    PORT
      LAYER M4 ;
        RECT  38.796 61.008 38.88 61.032 ;
    END
  END i[340]
  PIN i[341]
    DIRECTION INPUT ;
    USE SIGNAL ;
    PORT
      LAYER M4 ;
        RECT  38.796 61.2 38.88 61.224 ;
    END
  END i[341]
  PIN i[342]
    DIRECTION INPUT ;
    USE SIGNAL ;
    PORT
      LAYER M4 ;
        RECT  38.796 61.344 38.88 61.368 ;
    END
  END i[342]
  PIN i[343]
    DIRECTION INPUT ;
    USE SIGNAL ;
    PORT
      LAYER M4 ;
        RECT  38.796 61.536 38.88 61.56 ;
    END
  END i[343]
  PIN i[344]
    DIRECTION INPUT ;
    USE SIGNAL ;
    PORT
      LAYER M4 ;
        RECT  38.796 61.728 38.88 61.752 ;
    END
  END i[344]
  PIN i[345]
    DIRECTION INPUT ;
    USE SIGNAL ;
    PORT
      LAYER M4 ;
        RECT  38.796 61.872 38.88 61.896 ;
    END
  END i[345]
  PIN i[346]
    DIRECTION INPUT ;
    USE SIGNAL ;
    PORT
      LAYER M4 ;
        RECT  38.796 62.064 38.88 62.088 ;
    END
  END i[346]
  PIN i[347]
    DIRECTION INPUT ;
    USE SIGNAL ;
    PORT
      LAYER M4 ;
        RECT  38.796 62.256 38.88 62.28 ;
    END
  END i[347]
  PIN i[348]
    DIRECTION INPUT ;
    USE SIGNAL ;
    PORT
      LAYER M4 ;
        RECT  38.796 62.4 38.88 62.424 ;
    END
  END i[348]
  PIN i[349]
    DIRECTION INPUT ;
    USE SIGNAL ;
    PORT
      LAYER M4 ;
        RECT  38.796 62.592 38.88 62.616 ;
    END
  END i[349]
  PIN i[34]
    DIRECTION INPUT ;
    USE SIGNAL ;
    PORT
      LAYER M4 ;
        RECT  38.796 7.056 38.88 7.08 ;
    END
  END i[34]
  PIN i[350]
    DIRECTION INPUT ;
    USE SIGNAL ;
    PORT
      LAYER M4 ;
        RECT  38.796 62.784 38.88 62.808 ;
    END
  END i[350]
  PIN i[351]
    DIRECTION INPUT ;
    USE SIGNAL ;
    PORT
      LAYER M4 ;
        RECT  38.796 62.928 38.88 62.952 ;
    END
  END i[351]
  PIN i[352]
    DIRECTION INPUT ;
    USE SIGNAL ;
    PORT
      LAYER M4 ;
        RECT  38.796 63.12 38.88 63.144 ;
    END
  END i[352]
  PIN i[353]
    DIRECTION INPUT ;
    USE SIGNAL ;
    PORT
      LAYER M4 ;
        RECT  38.796 63.312 38.88 63.336 ;
    END
  END i[353]
  PIN i[354]
    DIRECTION INPUT ;
    USE SIGNAL ;
    PORT
      LAYER M4 ;
        RECT  38.796 63.456 38.88 63.48 ;
    END
  END i[354]
  PIN i[355]
    DIRECTION INPUT ;
    USE SIGNAL ;
    PORT
      LAYER M4 ;
        RECT  38.796 63.648 38.88 63.672 ;
    END
  END i[355]
  PIN i[356]
    DIRECTION INPUT ;
    USE SIGNAL ;
    PORT
      LAYER M4 ;
        RECT  38.796 63.84 38.88 63.864 ;
    END
  END i[356]
  PIN i[357]
    DIRECTION INPUT ;
    USE SIGNAL ;
    PORT
      LAYER M4 ;
        RECT  38.796 63.984 38.88 64.008 ;
    END
  END i[357]
  PIN i[358]
    DIRECTION INPUT ;
    USE SIGNAL ;
    PORT
      LAYER M4 ;
        RECT  38.796 64.176 38.88 64.2 ;
    END
  END i[358]
  PIN i[359]
    DIRECTION INPUT ;
    USE SIGNAL ;
    PORT
      LAYER M4 ;
        RECT  38.796 64.368 38.88 64.392 ;
    END
  END i[359]
  PIN i[35]
    DIRECTION INPUT ;
    USE SIGNAL ;
    PORT
      LAYER M4 ;
        RECT  38.796 7.248 38.88 7.272 ;
    END
  END i[35]
  PIN i[360]
    DIRECTION INPUT ;
    USE SIGNAL ;
    PORT
      LAYER M4 ;
        RECT  38.796 64.512 38.88 64.536 ;
    END
  END i[360]
  PIN i[361]
    DIRECTION INPUT ;
    USE SIGNAL ;
    PORT
      LAYER M4 ;
        RECT  38.796 64.704 38.88 64.728 ;
    END
  END i[361]
  PIN i[362]
    DIRECTION INPUT ;
    USE SIGNAL ;
    PORT
      LAYER M4 ;
        RECT  38.796 64.896 38.88 64.92 ;
    END
  END i[362]
  PIN i[363]
    DIRECTION INPUT ;
    USE SIGNAL ;
    PORT
      LAYER M4 ;
        RECT  38.796 65.04 38.88 65.064 ;
    END
  END i[363]
  PIN i[364]
    DIRECTION INPUT ;
    USE SIGNAL ;
    PORT
      LAYER M4 ;
        RECT  38.796 65.232 38.88 65.256 ;
    END
  END i[364]
  PIN i[365]
    DIRECTION INPUT ;
    USE SIGNAL ;
    PORT
      LAYER M4 ;
        RECT  38.796 65.424 38.88 65.448 ;
    END
  END i[365]
  PIN i[366]
    DIRECTION INPUT ;
    USE SIGNAL ;
    PORT
      LAYER M4 ;
        RECT  38.796 65.568 38.88 65.592 ;
    END
  END i[366]
  PIN i[367]
    DIRECTION INPUT ;
    USE SIGNAL ;
    PORT
      LAYER M4 ;
        RECT  38.796 65.76 38.88 65.784 ;
    END
  END i[367]
  PIN i[368]
    DIRECTION INPUT ;
    USE SIGNAL ;
    PORT
      LAYER M4 ;
        RECT  38.796 65.952 38.88 65.976 ;
    END
  END i[368]
  PIN i[369]
    DIRECTION INPUT ;
    USE SIGNAL ;
    PORT
      LAYER M4 ;
        RECT  38.796 66.096 38.88 66.12 ;
    END
  END i[369]
  PIN i[36]
    DIRECTION INPUT ;
    USE SIGNAL ;
    PORT
      LAYER M4 ;
        RECT  38.796 7.44 38.88 7.464 ;
    END
  END i[36]
  PIN i[370]
    DIRECTION INPUT ;
    USE SIGNAL ;
    PORT
      LAYER M4 ;
        RECT  38.796 66.288 38.88 66.312 ;
    END
  END i[370]
  PIN i[371]
    DIRECTION INPUT ;
    USE SIGNAL ;
    PORT
      LAYER M4 ;
        RECT  38.796 66.48 38.88 66.504 ;
    END
  END i[371]
  PIN i[372]
    DIRECTION INPUT ;
    USE SIGNAL ;
    PORT
      LAYER M4 ;
        RECT  38.796 66.624 38.88 66.648 ;
    END
  END i[372]
  PIN i[373]
    DIRECTION INPUT ;
    USE SIGNAL ;
    PORT
      LAYER M4 ;
        RECT  38.796 66.816 38.88 66.84 ;
    END
  END i[373]
  PIN i[374]
    DIRECTION INPUT ;
    USE SIGNAL ;
    PORT
      LAYER M4 ;
        RECT  38.796 67.008 38.88 67.032 ;
    END
  END i[374]
  PIN i[375]
    DIRECTION INPUT ;
    USE SIGNAL ;
    PORT
      LAYER M4 ;
        RECT  38.796 67.152 38.88 67.176 ;
    END
  END i[375]
  PIN i[376]
    DIRECTION INPUT ;
    USE SIGNAL ;
    PORT
      LAYER M4 ;
        RECT  38.796 67.344 38.88 67.368 ;
    END
  END i[376]
  PIN i[377]
    DIRECTION INPUT ;
    USE SIGNAL ;
    PORT
      LAYER M4 ;
        RECT  38.796 67.536 38.88 67.56 ;
    END
  END i[377]
  PIN i[378]
    DIRECTION INPUT ;
    USE SIGNAL ;
    PORT
      LAYER M4 ;
        RECT  38.796 67.68 38.88 67.704 ;
    END
  END i[378]
  PIN i[379]
    DIRECTION INPUT ;
    USE SIGNAL ;
    PORT
      LAYER M4 ;
        RECT  38.796 67.872 38.88 67.896 ;
    END
  END i[379]
  PIN i[37]
    DIRECTION INPUT ;
    USE SIGNAL ;
    PORT
      LAYER M4 ;
        RECT  38.796 7.584 38.88 7.608 ;
    END
  END i[37]
  PIN i[380]
    DIRECTION INPUT ;
    USE SIGNAL ;
    PORT
      LAYER M4 ;
        RECT  38.796 68.064 38.88 68.088 ;
    END
  END i[380]
  PIN i[381]
    DIRECTION INPUT ;
    USE SIGNAL ;
    PORT
      LAYER M4 ;
        RECT  38.796 68.208 38.88 68.232 ;
    END
  END i[381]
  PIN i[382]
    DIRECTION INPUT ;
    USE SIGNAL ;
    PORT
      LAYER M4 ;
        RECT  38.796 68.4 38.88 68.424 ;
    END
  END i[382]
  PIN i[383]
    DIRECTION INPUT ;
    USE SIGNAL ;
    PORT
      LAYER M4 ;
        RECT  38.796 68.592 38.88 68.616 ;
    END
  END i[383]
  PIN i[384]
    DIRECTION INPUT ;
    USE SIGNAL ;
    PORT
      LAYER M4 ;
        RECT  38.796 68.736 38.88 68.76 ;
    END
  END i[384]
  PIN i[385]
    DIRECTION INPUT ;
    USE SIGNAL ;
    PORT
      LAYER M4 ;
        RECT  38.796 68.928 38.88 68.952 ;
    END
  END i[385]
  PIN i[386]
    DIRECTION INPUT ;
    USE SIGNAL ;
    PORT
      LAYER M4 ;
        RECT  38.796 69.12 38.88 69.144 ;
    END
  END i[386]
  PIN i[387]
    DIRECTION INPUT ;
    USE SIGNAL ;
    PORT
      LAYER M4 ;
        RECT  38.796 69.264 38.88 69.288 ;
    END
  END i[387]
  PIN i[388]
    DIRECTION INPUT ;
    USE SIGNAL ;
    PORT
      LAYER M4 ;
        RECT  38.796 69.456 38.88 69.48 ;
    END
  END i[388]
  PIN i[389]
    DIRECTION INPUT ;
    USE SIGNAL ;
    PORT
      LAYER M4 ;
        RECT  38.796 69.648 38.88 69.672 ;
    END
  END i[389]
  PIN i[38]
    DIRECTION INPUT ;
    USE SIGNAL ;
    PORT
      LAYER M4 ;
        RECT  38.796 7.776 38.88 7.8 ;
    END
  END i[38]
  PIN i[390]
    DIRECTION INPUT ;
    USE SIGNAL ;
    PORT
      LAYER M4 ;
        RECT  38.796 69.792 38.88 69.816 ;
    END
  END i[390]
  PIN i[391]
    DIRECTION INPUT ;
    USE SIGNAL ;
    PORT
      LAYER M4 ;
        RECT  38.796 69.984 38.88 70.008 ;
    END
  END i[391]
  PIN i[392]
    DIRECTION INPUT ;
    USE SIGNAL ;
    PORT
      LAYER M4 ;
        RECT  38.796 70.176 38.88 70.2 ;
    END
  END i[392]
  PIN i[393]
    DIRECTION INPUT ;
    USE SIGNAL ;
    PORT
      LAYER M4 ;
        RECT  38.796 70.32 38.88 70.344 ;
    END
  END i[393]
  PIN i[394]
    DIRECTION INPUT ;
    USE SIGNAL ;
    PORT
      LAYER M4 ;
        RECT  38.796 70.512 38.88 70.536 ;
    END
  END i[394]
  PIN i[395]
    DIRECTION INPUT ;
    USE SIGNAL ;
    PORT
      LAYER M4 ;
        RECT  38.796 70.704 38.88 70.728 ;
    END
  END i[395]
  PIN i[396]
    DIRECTION INPUT ;
    USE SIGNAL ;
    PORT
      LAYER M4 ;
        RECT  38.796 70.848 38.88 70.872 ;
    END
  END i[396]
  PIN i[397]
    DIRECTION INPUT ;
    USE SIGNAL ;
    PORT
      LAYER M4 ;
        RECT  38.796 71.04 38.88 71.064 ;
    END
  END i[397]
  PIN i[398]
    DIRECTION INPUT ;
    USE SIGNAL ;
    PORT
      LAYER M4 ;
        RECT  38.796 71.232 38.88 71.256 ;
    END
  END i[398]
  PIN i[399]
    DIRECTION INPUT ;
    USE SIGNAL ;
    PORT
      LAYER M4 ;
        RECT  38.796 71.424 38.88 71.448 ;
    END
  END i[399]
  PIN i[39]
    DIRECTION INPUT ;
    USE SIGNAL ;
    PORT
      LAYER M4 ;
        RECT  38.796 7.968 38.88 7.992 ;
    END
  END i[39]
  PIN i[3]
    DIRECTION INPUT ;
    USE SIGNAL ;
    PORT
      LAYER M4 ;
        RECT  38.796 1.584 38.88 1.608 ;
    END
  END i[3]
  PIN i[400]
    DIRECTION INPUT ;
    USE SIGNAL ;
    PORT
      LAYER M4 ;
        RECT  38.796 71.568 38.88 71.592 ;
    END
  END i[400]
  PIN i[401]
    DIRECTION INPUT ;
    USE SIGNAL ;
    PORT
      LAYER M4 ;
        RECT  38.796 71.76 38.88 71.784 ;
    END
  END i[401]
  PIN i[402]
    DIRECTION INPUT ;
    USE SIGNAL ;
    PORT
      LAYER M4 ;
        RECT  38.796 71.952 38.88 71.976 ;
    END
  END i[402]
  PIN i[403]
    DIRECTION INPUT ;
    USE SIGNAL ;
    PORT
      LAYER M4 ;
        RECT  38.796 72.096 38.88 72.12 ;
    END
  END i[403]
  PIN i[404]
    DIRECTION INPUT ;
    USE SIGNAL ;
    PORT
      LAYER M4 ;
        RECT  38.796 72.288 38.88 72.312 ;
    END
  END i[404]
  PIN i[405]
    DIRECTION INPUT ;
    USE SIGNAL ;
    PORT
      LAYER M4 ;
        RECT  38.796 72.48 38.88 72.504 ;
    END
  END i[405]
  PIN i[406]
    DIRECTION INPUT ;
    USE SIGNAL ;
    PORT
      LAYER M4 ;
        RECT  38.796 72.624 38.88 72.648 ;
    END
  END i[406]
  PIN i[407]
    DIRECTION INPUT ;
    USE SIGNAL ;
    PORT
      LAYER M4 ;
        RECT  38.796 72.816 38.88 72.84 ;
    END
  END i[407]
  PIN i[408]
    DIRECTION INPUT ;
    USE SIGNAL ;
    PORT
      LAYER M4 ;
        RECT  38.796 73.008 38.88 73.032 ;
    END
  END i[408]
  PIN i[409]
    DIRECTION INPUT ;
    USE SIGNAL ;
    PORT
      LAYER M4 ;
        RECT  38.796 73.152 38.88 73.176 ;
    END
  END i[409]
  PIN i[40]
    DIRECTION INPUT ;
    USE SIGNAL ;
    PORT
      LAYER M4 ;
        RECT  38.796 8.112 38.88 8.136 ;
    END
  END i[40]
  PIN i[410]
    DIRECTION INPUT ;
    USE SIGNAL ;
    PORT
      LAYER M4 ;
        RECT  38.796 73.344 38.88 73.368 ;
    END
  END i[410]
  PIN i[411]
    DIRECTION INPUT ;
    USE SIGNAL ;
    PORT
      LAYER M4 ;
        RECT  38.796 73.536 38.88 73.56 ;
    END
  END i[411]
  PIN i[412]
    DIRECTION INPUT ;
    USE SIGNAL ;
    PORT
      LAYER M4 ;
        RECT  38.796 73.68 38.88 73.704 ;
    END
  END i[412]
  PIN i[413]
    DIRECTION INPUT ;
    USE SIGNAL ;
    PORT
      LAYER M4 ;
        RECT  38.796 73.872 38.88 73.896 ;
    END
  END i[413]
  PIN i[414]
    DIRECTION INPUT ;
    USE SIGNAL ;
    PORT
      LAYER M4 ;
        RECT  38.796 74.064 38.88 74.088 ;
    END
  END i[414]
  PIN i[415]
    DIRECTION INPUT ;
    USE SIGNAL ;
    PORT
      LAYER M4 ;
        RECT  38.796 74.208 38.88 74.232 ;
    END
  END i[415]
  PIN i[416]
    DIRECTION INPUT ;
    USE SIGNAL ;
    PORT
      LAYER M4 ;
        RECT  38.796 74.4 38.88 74.424 ;
    END
  END i[416]
  PIN i[417]
    DIRECTION INPUT ;
    USE SIGNAL ;
    PORT
      LAYER M4 ;
        RECT  38.796 74.592 38.88 74.616 ;
    END
  END i[417]
  PIN i[418]
    DIRECTION INPUT ;
    USE SIGNAL ;
    PORT
      LAYER M4 ;
        RECT  38.796 74.736 38.88 74.76 ;
    END
  END i[418]
  PIN i[419]
    DIRECTION INPUT ;
    USE SIGNAL ;
    PORT
      LAYER M4 ;
        RECT  38.796 74.928 38.88 74.952 ;
    END
  END i[419]
  PIN i[41]
    DIRECTION INPUT ;
    USE SIGNAL ;
    PORT
      LAYER M4 ;
        RECT  38.796 8.304 38.88 8.328 ;
    END
  END i[41]
  PIN i[420]
    DIRECTION INPUT ;
    USE SIGNAL ;
    PORT
      LAYER M4 ;
        RECT  38.796 75.12 38.88 75.144 ;
    END
  END i[420]
  PIN i[421]
    DIRECTION INPUT ;
    USE SIGNAL ;
    PORT
      LAYER M4 ;
        RECT  38.796 75.264 38.88 75.288 ;
    END
  END i[421]
  PIN i[422]
    DIRECTION INPUT ;
    USE SIGNAL ;
    PORT
      LAYER M4 ;
        RECT  38.796 75.456 38.88 75.48 ;
    END
  END i[422]
  PIN i[423]
    DIRECTION INPUT ;
    USE SIGNAL ;
    PORT
      LAYER M4 ;
        RECT  38.796 75.648 38.88 75.672 ;
    END
  END i[423]
  PIN i[424]
    DIRECTION INPUT ;
    USE SIGNAL ;
    PORT
      LAYER M4 ;
        RECT  38.796 75.792 38.88 75.816 ;
    END
  END i[424]
  PIN i[425]
    DIRECTION INPUT ;
    USE SIGNAL ;
    PORT
      LAYER M4 ;
        RECT  38.796 75.984 38.88 76.008 ;
    END
  END i[425]
  PIN i[426]
    DIRECTION INPUT ;
    USE SIGNAL ;
    PORT
      LAYER M4 ;
        RECT  38.796 76.176 38.88 76.2 ;
    END
  END i[426]
  PIN i[427]
    DIRECTION INPUT ;
    USE SIGNAL ;
    PORT
      LAYER M4 ;
        RECT  38.796 76.32 38.88 76.344 ;
    END
  END i[427]
  PIN i[428]
    DIRECTION INPUT ;
    USE SIGNAL ;
    PORT
      LAYER M4 ;
        RECT  38.796 76.512 38.88 76.536 ;
    END
  END i[428]
  PIN i[429]
    DIRECTION INPUT ;
    USE SIGNAL ;
    PORT
      LAYER M4 ;
        RECT  38.796 76.704 38.88 76.728 ;
    END
  END i[429]
  PIN i[42]
    DIRECTION INPUT ;
    USE SIGNAL ;
    PORT
      LAYER M4 ;
        RECT  38.796 8.496 38.88 8.52 ;
    END
  END i[42]
  PIN i[430]
    DIRECTION INPUT ;
    USE SIGNAL ;
    PORT
      LAYER M4 ;
        RECT  38.796 76.848 38.88 76.872 ;
    END
  END i[430]
  PIN i[431]
    DIRECTION INPUT ;
    USE SIGNAL ;
    PORT
      LAYER M4 ;
        RECT  38.796 77.04 38.88 77.064 ;
    END
  END i[431]
  PIN i[432]
    DIRECTION INPUT ;
    USE SIGNAL ;
    PORT
      LAYER M4 ;
        RECT  38.796 77.232 38.88 77.256 ;
    END
  END i[432]
  PIN i[433]
    DIRECTION INPUT ;
    USE SIGNAL ;
    PORT
      LAYER M4 ;
        RECT  38.796 77.376 38.88 77.4 ;
    END
  END i[433]
  PIN i[434]
    DIRECTION INPUT ;
    USE SIGNAL ;
    PORT
      LAYER M4 ;
        RECT  38.796 77.568 38.88 77.592 ;
    END
  END i[434]
  PIN i[435]
    DIRECTION INPUT ;
    USE SIGNAL ;
    PORT
      LAYER M4 ;
        RECT  38.796 77.76 38.88 77.784 ;
    END
  END i[435]
  PIN i[436]
    DIRECTION INPUT ;
    USE SIGNAL ;
    PORT
      LAYER M4 ;
        RECT  38.796 77.904 38.88 77.928 ;
    END
  END i[436]
  PIN i[437]
    DIRECTION INPUT ;
    USE SIGNAL ;
    PORT
      LAYER M4 ;
        RECT  38.796 78.096 38.88 78.12 ;
    END
  END i[437]
  PIN i[438]
    DIRECTION INPUT ;
    USE SIGNAL ;
    PORT
      LAYER M4 ;
        RECT  38.796 78.288 38.88 78.312 ;
    END
  END i[438]
  PIN i[439]
    DIRECTION INPUT ;
    USE SIGNAL ;
    PORT
      LAYER M4 ;
        RECT  38.796 78.432 38.88 78.456 ;
    END
  END i[439]
  PIN i[43]
    DIRECTION INPUT ;
    USE SIGNAL ;
    PORT
      LAYER M4 ;
        RECT  38.796 8.64 38.88 8.664 ;
    END
  END i[43]
  PIN i[440]
    DIRECTION INPUT ;
    USE SIGNAL ;
    PORT
      LAYER M4 ;
        RECT  38.796 78.624 38.88 78.648 ;
    END
  END i[440]
  PIN i[441]
    DIRECTION INPUT ;
    USE SIGNAL ;
    PORT
      LAYER M4 ;
        RECT  38.796 78.816 38.88 78.84 ;
    END
  END i[441]
  PIN i[442]
    DIRECTION INPUT ;
    USE SIGNAL ;
    PORT
      LAYER M4 ;
        RECT  38.796 78.96 38.88 78.984 ;
    END
  END i[442]
  PIN i[443]
    DIRECTION INPUT ;
    USE SIGNAL ;
    PORT
      LAYER M4 ;
        RECT  38.796 79.152 38.88 79.176 ;
    END
  END i[443]
  PIN i[444]
    DIRECTION INPUT ;
    USE SIGNAL ;
    PORT
      LAYER M4 ;
        RECT  38.796 79.344 38.88 79.368 ;
    END
  END i[444]
  PIN i[445]
    DIRECTION INPUT ;
    USE SIGNAL ;
    PORT
      LAYER M4 ;
        RECT  38.796 79.488 38.88 79.512 ;
    END
  END i[445]
  PIN i[446]
    DIRECTION INPUT ;
    USE SIGNAL ;
    PORT
      LAYER M4 ;
        RECT  38.796 79.68 38.88 79.704 ;
    END
  END i[446]
  PIN i[447]
    DIRECTION INPUT ;
    USE SIGNAL ;
    PORT
      LAYER M4 ;
        RECT  38.796 79.872 38.88 79.896 ;
    END
  END i[447]
  PIN i[448]
    DIRECTION INPUT ;
    USE SIGNAL ;
    PORT
      LAYER M4 ;
        RECT  38.796 80.016 38.88 80.04 ;
    END
  END i[448]
  PIN i[449]
    DIRECTION INPUT ;
    USE SIGNAL ;
    PORT
      LAYER M4 ;
        RECT  38.796 80.208 38.88 80.232 ;
    END
  END i[449]
  PIN i[44]
    DIRECTION INPUT ;
    USE SIGNAL ;
    PORT
      LAYER M4 ;
        RECT  38.796 8.832 38.88 8.856 ;
    END
  END i[44]
  PIN i[450]
    DIRECTION INPUT ;
    USE SIGNAL ;
    PORT
      LAYER M4 ;
        RECT  38.796 80.4 38.88 80.424 ;
    END
  END i[450]
  PIN i[451]
    DIRECTION INPUT ;
    USE SIGNAL ;
    PORT
      LAYER M4 ;
        RECT  38.796 80.544 38.88 80.568 ;
    END
  END i[451]
  PIN i[452]
    DIRECTION INPUT ;
    USE SIGNAL ;
    PORT
      LAYER M4 ;
        RECT  38.796 80.736 38.88 80.76 ;
    END
  END i[452]
  PIN i[453]
    DIRECTION INPUT ;
    USE SIGNAL ;
    PORT
      LAYER M4 ;
        RECT  38.796 80.928 38.88 80.952 ;
    END
  END i[453]
  PIN i[454]
    DIRECTION INPUT ;
    USE SIGNAL ;
    PORT
      LAYER M4 ;
        RECT  38.796 81.072 38.88 81.096 ;
    END
  END i[454]
  PIN i[455]
    DIRECTION INPUT ;
    USE SIGNAL ;
    PORT
      LAYER M4 ;
        RECT  38.796 81.264 38.88 81.288 ;
    END
  END i[455]
  PIN i[456]
    DIRECTION INPUT ;
    USE SIGNAL ;
    PORT
      LAYER M4 ;
        RECT  38.796 81.456 38.88 81.48 ;
    END
  END i[456]
  PIN i[457]
    DIRECTION INPUT ;
    USE SIGNAL ;
    PORT
      LAYER M4 ;
        RECT  38.796 81.6 38.88 81.624 ;
    END
  END i[457]
  PIN i[458]
    DIRECTION INPUT ;
    USE SIGNAL ;
    PORT
      LAYER M4 ;
        RECT  38.796 81.792 38.88 81.816 ;
    END
  END i[458]
  PIN i[459]
    DIRECTION INPUT ;
    USE SIGNAL ;
    PORT
      LAYER M4 ;
        RECT  38.796 81.984 38.88 82.008 ;
    END
  END i[459]
  PIN i[45]
    DIRECTION INPUT ;
    USE SIGNAL ;
    PORT
      LAYER M4 ;
        RECT  38.796 9.024 38.88 9.048 ;
    END
  END i[45]
  PIN i[460]
    DIRECTION INPUT ;
    USE SIGNAL ;
    PORT
      LAYER M4 ;
        RECT  38.796 82.128 38.88 82.152 ;
    END
  END i[460]
  PIN i[461]
    DIRECTION INPUT ;
    USE SIGNAL ;
    PORT
      LAYER M4 ;
        RECT  38.796 82.32 38.88 82.344 ;
    END
  END i[461]
  PIN i[462]
    DIRECTION INPUT ;
    USE SIGNAL ;
    PORT
      LAYER M4 ;
        RECT  38.796 82.512 38.88 82.536 ;
    END
  END i[462]
  PIN i[463]
    DIRECTION INPUT ;
    USE SIGNAL ;
    PORT
      LAYER M4 ;
        RECT  38.796 82.704 38.88 82.728 ;
    END
  END i[463]
  PIN i[464]
    DIRECTION INPUT ;
    USE SIGNAL ;
    PORT
      LAYER M4 ;
        RECT  38.796 82.848 38.88 82.872 ;
    END
  END i[464]
  PIN i[465]
    DIRECTION INPUT ;
    USE SIGNAL ;
    PORT
      LAYER M4 ;
        RECT  38.796 83.04 38.88 83.064 ;
    END
  END i[465]
  PIN i[466]
    DIRECTION INPUT ;
    USE SIGNAL ;
    PORT
      LAYER M4 ;
        RECT  38.796 83.232 38.88 83.256 ;
    END
  END i[466]
  PIN i[467]
    DIRECTION INPUT ;
    USE SIGNAL ;
    PORT
      LAYER M4 ;
        RECT  38.796 83.376 38.88 83.4 ;
    END
  END i[467]
  PIN i[468]
    DIRECTION INPUT ;
    USE SIGNAL ;
    PORT
      LAYER M4 ;
        RECT  38.796 83.568 38.88 83.592 ;
    END
  END i[468]
  PIN i[469]
    DIRECTION INPUT ;
    USE SIGNAL ;
    PORT
      LAYER M4 ;
        RECT  38.796 83.76 38.88 83.784 ;
    END
  END i[469]
  PIN i[46]
    DIRECTION INPUT ;
    USE SIGNAL ;
    PORT
      LAYER M4 ;
        RECT  38.796 9.168 38.88 9.192 ;
    END
  END i[46]
  PIN i[470]
    DIRECTION INPUT ;
    USE SIGNAL ;
    PORT
      LAYER M4 ;
        RECT  38.796 83.904 38.88 83.928 ;
    END
  END i[470]
  PIN i[471]
    DIRECTION INPUT ;
    USE SIGNAL ;
    PORT
      LAYER M4 ;
        RECT  38.796 84.096 38.88 84.12 ;
    END
  END i[471]
  PIN i[472]
    DIRECTION INPUT ;
    USE SIGNAL ;
    PORT
      LAYER M4 ;
        RECT  38.796 84.288 38.88 84.312 ;
    END
  END i[472]
  PIN i[473]
    DIRECTION INPUT ;
    USE SIGNAL ;
    PORT
      LAYER M4 ;
        RECT  38.796 84.432 38.88 84.456 ;
    END
  END i[473]
  PIN i[474]
    DIRECTION INPUT ;
    USE SIGNAL ;
    PORT
      LAYER M4 ;
        RECT  38.796 84.624 38.88 84.648 ;
    END
  END i[474]
  PIN i[475]
    DIRECTION INPUT ;
    USE SIGNAL ;
    PORT
      LAYER M4 ;
        RECT  38.796 84.816 38.88 84.84 ;
    END
  END i[475]
  PIN i[476]
    DIRECTION INPUT ;
    USE SIGNAL ;
    PORT
      LAYER M4 ;
        RECT  38.796 84.96 38.88 84.984 ;
    END
  END i[476]
  PIN i[477]
    DIRECTION INPUT ;
    USE SIGNAL ;
    PORT
      LAYER M4 ;
        RECT  38.796 85.152 38.88 85.176 ;
    END
  END i[477]
  PIN i[478]
    DIRECTION INPUT ;
    USE SIGNAL ;
    PORT
      LAYER M4 ;
        RECT  38.796 85.344 38.88 85.368 ;
    END
  END i[478]
  PIN i[479]
    DIRECTION INPUT ;
    USE SIGNAL ;
    PORT
      LAYER M4 ;
        RECT  38.796 85.488 38.88 85.512 ;
    END
  END i[479]
  PIN i[47]
    DIRECTION INPUT ;
    USE SIGNAL ;
    PORT
      LAYER M4 ;
        RECT  38.796 9.36 38.88 9.384 ;
    END
  END i[47]
  PIN i[480]
    DIRECTION INPUT ;
    USE SIGNAL ;
    PORT
      LAYER M4 ;
        RECT  38.796 85.68 38.88 85.704 ;
    END
  END i[480]
  PIN i[481]
    DIRECTION INPUT ;
    USE SIGNAL ;
    PORT
      LAYER M4 ;
        RECT  38.796 85.872 38.88 85.896 ;
    END
  END i[481]
  PIN i[482]
    DIRECTION INPUT ;
    USE SIGNAL ;
    PORT
      LAYER M4 ;
        RECT  38.796 86.016 38.88 86.04 ;
    END
  END i[482]
  PIN i[483]
    DIRECTION INPUT ;
    USE SIGNAL ;
    PORT
      LAYER M4 ;
        RECT  38.796 86.208 38.88 86.232 ;
    END
  END i[483]
  PIN i[484]
    DIRECTION INPUT ;
    USE SIGNAL ;
    PORT
      LAYER M4 ;
        RECT  38.796 86.4 38.88 86.424 ;
    END
  END i[484]
  PIN i[485]
    DIRECTION INPUT ;
    USE SIGNAL ;
    PORT
      LAYER M4 ;
        RECT  38.796 86.544 38.88 86.568 ;
    END
  END i[485]
  PIN i[486]
    DIRECTION INPUT ;
    USE SIGNAL ;
    PORT
      LAYER M4 ;
        RECT  38.796 86.736 38.88 86.76 ;
    END
  END i[486]
  PIN i[487]
    DIRECTION INPUT ;
    USE SIGNAL ;
    PORT
      LAYER M4 ;
        RECT  38.796 86.928 38.88 86.952 ;
    END
  END i[487]
  PIN i[488]
    DIRECTION INPUT ;
    USE SIGNAL ;
    PORT
      LAYER M4 ;
        RECT  38.796 87.072 38.88 87.096 ;
    END
  END i[488]
  PIN i[489]
    DIRECTION INPUT ;
    USE SIGNAL ;
    PORT
      LAYER M4 ;
        RECT  38.796 87.264 38.88 87.288 ;
    END
  END i[489]
  PIN i[48]
    DIRECTION INPUT ;
    USE SIGNAL ;
    PORT
      LAYER M4 ;
        RECT  38.796 9.552 38.88 9.576 ;
    END
  END i[48]
  PIN i[490]
    DIRECTION INPUT ;
    USE SIGNAL ;
    PORT
      LAYER M4 ;
        RECT  38.796 87.456 38.88 87.48 ;
    END
  END i[490]
  PIN i[491]
    DIRECTION INPUT ;
    USE SIGNAL ;
    PORT
      LAYER M4 ;
        RECT  38.796 87.6 38.88 87.624 ;
    END
  END i[491]
  PIN i[492]
    DIRECTION INPUT ;
    USE SIGNAL ;
    PORT
      LAYER M4 ;
        RECT  38.796 87.792 38.88 87.816 ;
    END
  END i[492]
  PIN i[493]
    DIRECTION INPUT ;
    USE SIGNAL ;
    PORT
      LAYER M4 ;
        RECT  38.796 87.984 38.88 88.008 ;
    END
  END i[493]
  PIN i[494]
    DIRECTION INPUT ;
    USE SIGNAL ;
    PORT
      LAYER M4 ;
        RECT  38.796 88.128 38.88 88.152 ;
    END
  END i[494]
  PIN i[495]
    DIRECTION INPUT ;
    USE SIGNAL ;
    PORT
      LAYER M4 ;
        RECT  38.796 88.32 38.88 88.344 ;
    END
  END i[495]
  PIN i[496]
    DIRECTION INPUT ;
    USE SIGNAL ;
    PORT
      LAYER M4 ;
        RECT  38.796 88.512 38.88 88.536 ;
    END
  END i[496]
  PIN i[497]
    DIRECTION INPUT ;
    USE SIGNAL ;
    PORT
      LAYER M4 ;
        RECT  38.796 88.656 38.88 88.68 ;
    END
  END i[497]
  PIN i[498]
    DIRECTION INPUT ;
    USE SIGNAL ;
    PORT
      LAYER M4 ;
        RECT  38.796 88.848 38.88 88.872 ;
    END
  END i[498]
  PIN i[499]
    DIRECTION INPUT ;
    USE SIGNAL ;
    PORT
      LAYER M4 ;
        RECT  38.796 89.04 38.88 89.064 ;
    END
  END i[499]
  PIN i[49]
    DIRECTION INPUT ;
    USE SIGNAL ;
    PORT
      LAYER M4 ;
        RECT  38.796 9.696 38.88 9.72 ;
    END
  END i[49]
  PIN i[4]
    DIRECTION INPUT ;
    USE SIGNAL ;
    PORT
      LAYER M4 ;
        RECT  38.796 1.776 38.88 1.8 ;
    END
  END i[4]
  PIN i[500]
    DIRECTION INPUT ;
    USE SIGNAL ;
    PORT
      LAYER M4 ;
        RECT  38.796 89.184 38.88 89.208 ;
    END
  END i[500]
  PIN i[501]
    DIRECTION INPUT ;
    USE SIGNAL ;
    PORT
      LAYER M4 ;
        RECT  38.796 89.376 38.88 89.4 ;
    END
  END i[501]
  PIN i[502]
    DIRECTION INPUT ;
    USE SIGNAL ;
    PORT
      LAYER M4 ;
        RECT  38.796 89.568 38.88 89.592 ;
    END
  END i[502]
  PIN i[503]
    DIRECTION INPUT ;
    USE SIGNAL ;
    PORT
      LAYER M4 ;
        RECT  38.796 89.712 38.88 89.736 ;
    END
  END i[503]
  PIN i[504]
    DIRECTION INPUT ;
    USE SIGNAL ;
    PORT
      LAYER M4 ;
        RECT  38.796 89.904 38.88 89.928 ;
    END
  END i[504]
  PIN i[505]
    DIRECTION INPUT ;
    USE SIGNAL ;
    PORT
      LAYER M4 ;
        RECT  38.796 90.096 38.88 90.12 ;
    END
  END i[505]
  PIN i[506]
    DIRECTION INPUT ;
    USE SIGNAL ;
    PORT
      LAYER M4 ;
        RECT  38.796 90.24 38.88 90.264 ;
    END
  END i[506]
  PIN i[507]
    DIRECTION INPUT ;
    USE SIGNAL ;
    PORT
      LAYER M4 ;
        RECT  38.796 90.432 38.88 90.456 ;
    END
  END i[507]
  PIN i[508]
    DIRECTION INPUT ;
    USE SIGNAL ;
    PORT
      LAYER M4 ;
        RECT  38.796 90.624 38.88 90.648 ;
    END
  END i[508]
  PIN i[509]
    DIRECTION INPUT ;
    USE SIGNAL ;
    PORT
      LAYER M4 ;
        RECT  38.796 90.768 38.88 90.792 ;
    END
  END i[509]
  PIN i[50]
    DIRECTION INPUT ;
    USE SIGNAL ;
    PORT
      LAYER M4 ;
        RECT  38.796 9.888 38.88 9.912 ;
    END
  END i[50]
  PIN i[510]
    DIRECTION INPUT ;
    USE SIGNAL ;
    PORT
      LAYER M4 ;
        RECT  38.796 90.96 38.88 90.984 ;
    END
  END i[510]
  PIN i[511]
    DIRECTION INPUT ;
    USE SIGNAL ;
    PORT
      LAYER M4 ;
        RECT  38.796 91.152 38.88 91.176 ;
    END
  END i[511]
  PIN i[51]
    DIRECTION INPUT ;
    USE SIGNAL ;
    PORT
      LAYER M4 ;
        RECT  38.796 10.08 38.88 10.104 ;
    END
  END i[51]
  PIN i[52]
    DIRECTION INPUT ;
    USE SIGNAL ;
    PORT
      LAYER M4 ;
        RECT  38.796 10.224 38.88 10.248 ;
    END
  END i[52]
  PIN i[53]
    DIRECTION INPUT ;
    USE SIGNAL ;
    PORT
      LAYER M4 ;
        RECT  38.796 10.416 38.88 10.44 ;
    END
  END i[53]
  PIN i[54]
    DIRECTION INPUT ;
    USE SIGNAL ;
    PORT
      LAYER M4 ;
        RECT  38.796 10.608 38.88 10.632 ;
    END
  END i[54]
  PIN i[55]
    DIRECTION INPUT ;
    USE SIGNAL ;
    PORT
      LAYER M4 ;
        RECT  38.796 10.752 38.88 10.776 ;
    END
  END i[55]
  PIN i[56]
    DIRECTION INPUT ;
    USE SIGNAL ;
    PORT
      LAYER M4 ;
        RECT  38.796 10.944 38.88 10.968 ;
    END
  END i[56]
  PIN i[57]
    DIRECTION INPUT ;
    USE SIGNAL ;
    PORT
      LAYER M4 ;
        RECT  38.796 11.136 38.88 11.16 ;
    END
  END i[57]
  PIN i[58]
    DIRECTION INPUT ;
    USE SIGNAL ;
    PORT
      LAYER M4 ;
        RECT  38.796 11.28 38.88 11.304 ;
    END
  END i[58]
  PIN i[59]
    DIRECTION INPUT ;
    USE SIGNAL ;
    PORT
      LAYER M4 ;
        RECT  38.796 11.472 38.88 11.496 ;
    END
  END i[59]
  PIN i[5]
    DIRECTION INPUT ;
    USE SIGNAL ;
    PORT
      LAYER M4 ;
        RECT  38.796 1.968 38.88 1.992 ;
    END
  END i[5]
  PIN i[60]
    DIRECTION INPUT ;
    USE SIGNAL ;
    PORT
      LAYER M4 ;
        RECT  38.796 11.664 38.88 11.688 ;
    END
  END i[60]
  PIN i[61]
    DIRECTION INPUT ;
    USE SIGNAL ;
    PORT
      LAYER M4 ;
        RECT  38.796 11.808 38.88 11.832 ;
    END
  END i[61]
  PIN i[62]
    DIRECTION INPUT ;
    USE SIGNAL ;
    PORT
      LAYER M4 ;
        RECT  38.796 12 38.88 12.024 ;
    END
  END i[62]
  PIN i[63]
    DIRECTION INPUT ;
    USE SIGNAL ;
    PORT
      LAYER M4 ;
        RECT  38.796 12.192 38.88 12.216 ;
    END
  END i[63]
  PIN i[64]
    DIRECTION INPUT ;
    USE SIGNAL ;
    PORT
      LAYER M4 ;
        RECT  38.796 12.336 38.88 12.36 ;
    END
  END i[64]
  PIN i[65]
    DIRECTION INPUT ;
    USE SIGNAL ;
    PORT
      LAYER M4 ;
        RECT  38.796 12.528 38.88 12.552 ;
    END
  END i[65]
  PIN i[66]
    DIRECTION INPUT ;
    USE SIGNAL ;
    PORT
      LAYER M4 ;
        RECT  38.796 12.72 38.88 12.744 ;
    END
  END i[66]
  PIN i[67]
    DIRECTION INPUT ;
    USE SIGNAL ;
    PORT
      LAYER M4 ;
        RECT  38.796 12.864 38.88 12.888 ;
    END
  END i[67]
  PIN i[68]
    DIRECTION INPUT ;
    USE SIGNAL ;
    PORT
      LAYER M4 ;
        RECT  38.796 13.056 38.88 13.08 ;
    END
  END i[68]
  PIN i[69]
    DIRECTION INPUT ;
    USE SIGNAL ;
    PORT
      LAYER M4 ;
        RECT  38.796 13.248 38.88 13.272 ;
    END
  END i[69]
  PIN i[6]
    DIRECTION INPUT ;
    USE SIGNAL ;
    PORT
      LAYER M4 ;
        RECT  38.796 2.112 38.88 2.136 ;
    END
  END i[6]
  PIN i[70]
    DIRECTION INPUT ;
    USE SIGNAL ;
    PORT
      LAYER M4 ;
        RECT  38.796 13.392 38.88 13.416 ;
    END
  END i[70]
  PIN i[71]
    DIRECTION INPUT ;
    USE SIGNAL ;
    PORT
      LAYER M4 ;
        RECT  38.796 13.584 38.88 13.608 ;
    END
  END i[71]
  PIN i[72]
    DIRECTION INPUT ;
    USE SIGNAL ;
    PORT
      LAYER M4 ;
        RECT  38.796 13.776 38.88 13.8 ;
    END
  END i[72]
  PIN i[73]
    DIRECTION INPUT ;
    USE SIGNAL ;
    PORT
      LAYER M4 ;
        RECT  38.796 13.92 38.88 13.944 ;
    END
  END i[73]
  PIN i[74]
    DIRECTION INPUT ;
    USE SIGNAL ;
    PORT
      LAYER M4 ;
        RECT  38.796 14.112 38.88 14.136 ;
    END
  END i[74]
  PIN i[75]
    DIRECTION INPUT ;
    USE SIGNAL ;
    PORT
      LAYER M4 ;
        RECT  38.796 14.304 38.88 14.328 ;
    END
  END i[75]
  PIN i[76]
    DIRECTION INPUT ;
    USE SIGNAL ;
    PORT
      LAYER M4 ;
        RECT  38.796 14.448 38.88 14.472 ;
    END
  END i[76]
  PIN i[77]
    DIRECTION INPUT ;
    USE SIGNAL ;
    PORT
      LAYER M4 ;
        RECT  38.796 14.64 38.88 14.664 ;
    END
  END i[77]
  PIN i[78]
    DIRECTION INPUT ;
    USE SIGNAL ;
    PORT
      LAYER M4 ;
        RECT  38.796 14.832 38.88 14.856 ;
    END
  END i[78]
  PIN i[79]
    DIRECTION INPUT ;
    USE SIGNAL ;
    PORT
      LAYER M4 ;
        RECT  38.796 15.024 38.88 15.048 ;
    END
  END i[79]
  PIN i[7]
    DIRECTION INPUT ;
    USE SIGNAL ;
    PORT
      LAYER M4 ;
        RECT  38.796 2.304 38.88 2.328 ;
    END
  END i[7]
  PIN i[80]
    DIRECTION INPUT ;
    USE SIGNAL ;
    PORT
      LAYER M4 ;
        RECT  38.796 15.168 38.88 15.192 ;
    END
  END i[80]
  PIN i[81]
    DIRECTION INPUT ;
    USE SIGNAL ;
    PORT
      LAYER M4 ;
        RECT  38.796 15.36 38.88 15.384 ;
    END
  END i[81]
  PIN i[82]
    DIRECTION INPUT ;
    USE SIGNAL ;
    PORT
      LAYER M4 ;
        RECT  38.796 15.552 38.88 15.576 ;
    END
  END i[82]
  PIN i[83]
    DIRECTION INPUT ;
    USE SIGNAL ;
    PORT
      LAYER M4 ;
        RECT  38.796 15.696 38.88 15.72 ;
    END
  END i[83]
  PIN i[84]
    DIRECTION INPUT ;
    USE SIGNAL ;
    PORT
      LAYER M4 ;
        RECT  38.796 15.888 38.88 15.912 ;
    END
  END i[84]
  PIN i[85]
    DIRECTION INPUT ;
    USE SIGNAL ;
    PORT
      LAYER M4 ;
        RECT  38.796 16.08 38.88 16.104 ;
    END
  END i[85]
  PIN i[86]
    DIRECTION INPUT ;
    USE SIGNAL ;
    PORT
      LAYER M4 ;
        RECT  38.796 16.224 38.88 16.248 ;
    END
  END i[86]
  PIN i[87]
    DIRECTION INPUT ;
    USE SIGNAL ;
    PORT
      LAYER M4 ;
        RECT  38.796 16.416 38.88 16.44 ;
    END
  END i[87]
  PIN i[88]
    DIRECTION INPUT ;
    USE SIGNAL ;
    PORT
      LAYER M4 ;
        RECT  38.796 16.608 38.88 16.632 ;
    END
  END i[88]
  PIN i[89]
    DIRECTION INPUT ;
    USE SIGNAL ;
    PORT
      LAYER M4 ;
        RECT  38.796 16.752 38.88 16.776 ;
    END
  END i[89]
  PIN i[8]
    DIRECTION INPUT ;
    USE SIGNAL ;
    PORT
      LAYER M4 ;
        RECT  38.796 2.496 38.88 2.52 ;
    END
  END i[8]
  PIN i[90]
    DIRECTION INPUT ;
    USE SIGNAL ;
    PORT
      LAYER M4 ;
        RECT  38.796 16.944 38.88 16.968 ;
    END
  END i[90]
  PIN i[91]
    DIRECTION INPUT ;
    USE SIGNAL ;
    PORT
      LAYER M4 ;
        RECT  38.796 17.136 38.88 17.16 ;
    END
  END i[91]
  PIN i[92]
    DIRECTION INPUT ;
    USE SIGNAL ;
    PORT
      LAYER M4 ;
        RECT  38.796 17.28 38.88 17.304 ;
    END
  END i[92]
  PIN i[93]
    DIRECTION INPUT ;
    USE SIGNAL ;
    PORT
      LAYER M4 ;
        RECT  38.796 17.472 38.88 17.496 ;
    END
  END i[93]
  PIN i[94]
    DIRECTION INPUT ;
    USE SIGNAL ;
    PORT
      LAYER M4 ;
        RECT  38.796 17.664 38.88 17.688 ;
    END
  END i[94]
  PIN i[95]
    DIRECTION INPUT ;
    USE SIGNAL ;
    PORT
      LAYER M4 ;
        RECT  38.796 17.808 38.88 17.832 ;
    END
  END i[95]
  PIN i[96]
    DIRECTION INPUT ;
    USE SIGNAL ;
    PORT
      LAYER M4 ;
        RECT  38.796 18 38.88 18.024 ;
    END
  END i[96]
  PIN i[97]
    DIRECTION INPUT ;
    USE SIGNAL ;
    PORT
      LAYER M4 ;
        RECT  38.796 18.192 38.88 18.216 ;
    END
  END i[97]
  PIN i[98]
    DIRECTION INPUT ;
    USE SIGNAL ;
    PORT
      LAYER M4 ;
        RECT  38.796 18.336 38.88 18.36 ;
    END
  END i[98]
  PIN i[99]
    DIRECTION INPUT ;
    USE SIGNAL ;
    PORT
      LAYER M4 ;
        RECT  38.796 18.528 38.88 18.552 ;
    END
  END i[99]
  PIN i[9]
    DIRECTION INPUT ;
    USE SIGNAL ;
    PORT
      LAYER M4 ;
        RECT  38.796 2.64 38.88 2.664 ;
    END
  END i[9]
  PIN k[0]
    DIRECTION INPUT ;
    USE SIGNAL ;
    PORT
      LAYER M3 ;
        RECT  15.192 95.002 15.21 95.04 ;
    END
    PORT
      LAYER M3 ;
        RECT  15.192 94.939 15.21 95.021 ;
    END
  END k[0]
  PIN k[1]
    DIRECTION INPUT ;
    USE SIGNAL ;
    PORT
      LAYER M5 ;
        RECT  15.6 94.956 15.624 95.04 ;
    END
    PORT
      LAYER M5 ;
        RECT  15.216 92.903 15.624 94.979 ;
    END
    PORT
      LAYER M5 ;
        RECT  15.6 94.979 15.624 94.992 ;
    END
  END k[1]
  PIN k[2]
    DIRECTION INPUT ;
    USE SIGNAL ;
    PORT
      LAYER M3 ;
        RECT  15.984 95.002 16.002 95.04 ;
    END
    PORT
      LAYER M3 ;
        RECT  15.984 94.981 16.074 95.009 ;
    END
    PORT
      LAYER M3 ;
        RECT  15.984 95.009 16.002 95.021 ;
    END
  END k[2]
  PIN o[0]
    DIRECTION OUTPUT ;
    USE SIGNAL ;
    PORT
      LAYER M4 ;
        RECT  0 1.056 0.084 1.08 ;
    END
  END o[0]
  PIN o[100]
    DIRECTION OUTPUT ;
    USE SIGNAL ;
    PORT
      LAYER M4 ;
        RECT  0 18.72 0.084 18.744 ;
    END
  END o[100]
  PIN o[101]
    DIRECTION OUTPUT ;
    USE SIGNAL ;
    PORT
      LAYER M4 ;
        RECT  0 18.864 0.084 18.888 ;
    END
  END o[101]
  PIN o[102]
    DIRECTION OUTPUT ;
    USE SIGNAL ;
    PORT
      LAYER M4 ;
        RECT  0 19.056 0.084 19.08 ;
    END
  END o[102]
  PIN o[103]
    DIRECTION OUTPUT ;
    USE SIGNAL ;
    PORT
      LAYER M4 ;
        RECT  0 19.248 0.084 19.272 ;
    END
  END o[103]
  PIN o[104]
    DIRECTION OUTPUT ;
    USE SIGNAL ;
    PORT
      LAYER M4 ;
        RECT  0 19.392 0.084 19.416 ;
    END
  END o[104]
  PIN o[105]
    DIRECTION OUTPUT ;
    USE SIGNAL ;
    PORT
      LAYER M4 ;
        RECT  0 19.584 0.084 19.608 ;
    END
  END o[105]
  PIN o[106]
    DIRECTION OUTPUT ;
    USE SIGNAL ;
    PORT
      LAYER M4 ;
        RECT  0 19.776 0.084 19.8 ;
    END
  END o[106]
  PIN o[107]
    DIRECTION OUTPUT ;
    USE SIGNAL ;
    PORT
      LAYER M4 ;
        RECT  0 19.92 0.084 19.944 ;
    END
  END o[107]
  PIN o[108]
    DIRECTION OUTPUT ;
    USE SIGNAL ;
    PORT
      LAYER M4 ;
        RECT  0 20.112 0.084 20.136 ;
    END
  END o[108]
  PIN o[109]
    DIRECTION OUTPUT ;
    USE SIGNAL ;
    PORT
      LAYER M4 ;
        RECT  0 20.304 0.084 20.328 ;
    END
  END o[109]
  PIN o[10]
    DIRECTION OUTPUT ;
    USE SIGNAL ;
    PORT
      LAYER M4 ;
        RECT  0 2.832 0.084 2.856 ;
    END
  END o[10]
  PIN o[110]
    DIRECTION OUTPUT ;
    USE SIGNAL ;
    PORT
      LAYER M4 ;
        RECT  0 20.448 0.084 20.472 ;
    END
  END o[110]
  PIN o[111]
    DIRECTION OUTPUT ;
    USE SIGNAL ;
    PORT
      LAYER M4 ;
        RECT  0 20.64 0.084 20.664 ;
    END
  END o[111]
  PIN o[112]
    DIRECTION OUTPUT ;
    USE SIGNAL ;
    PORT
      LAYER M4 ;
        RECT  0 20.832 0.084 20.856 ;
    END
  END o[112]
  PIN o[113]
    DIRECTION OUTPUT ;
    USE SIGNAL ;
    PORT
      LAYER M4 ;
        RECT  0 20.976 0.084 21 ;
    END
  END o[113]
  PIN o[114]
    DIRECTION OUTPUT ;
    USE SIGNAL ;
    PORT
      LAYER M4 ;
        RECT  0 21.168 0.084 21.192 ;
    END
  END o[114]
  PIN o[115]
    DIRECTION OUTPUT ;
    USE SIGNAL ;
    PORT
      LAYER M4 ;
        RECT  0 21.36 0.084 21.384 ;
    END
  END o[115]
  PIN o[116]
    DIRECTION OUTPUT ;
    USE SIGNAL ;
    PORT
      LAYER M4 ;
        RECT  0 21.504 0.084 21.528 ;
    END
  END o[116]
  PIN o[117]
    DIRECTION OUTPUT ;
    USE SIGNAL ;
    PORT
      LAYER M4 ;
        RECT  0 21.696 0.084 21.72 ;
    END
  END o[117]
  PIN o[118]
    DIRECTION OUTPUT ;
    USE SIGNAL ;
    PORT
      LAYER M4 ;
        RECT  0 21.888 0.084 21.912 ;
    END
  END o[118]
  PIN o[119]
    DIRECTION OUTPUT ;
    USE SIGNAL ;
    PORT
      LAYER M4 ;
        RECT  0 22.032 0.084 22.056 ;
    END
  END o[119]
  PIN o[11]
    DIRECTION OUTPUT ;
    USE SIGNAL ;
    PORT
      LAYER M4 ;
        RECT  0 3.024 0.084 3.048 ;
    END
  END o[11]
  PIN o[120]
    DIRECTION OUTPUT ;
    USE SIGNAL ;
    PORT
      LAYER M4 ;
        RECT  0 22.224 0.084 22.248 ;
    END
  END o[120]
  PIN o[121]
    DIRECTION OUTPUT ;
    USE SIGNAL ;
    PORT
      LAYER M4 ;
        RECT  0 22.416 0.084 22.44 ;
    END
  END o[121]
  PIN o[122]
    DIRECTION OUTPUT ;
    USE SIGNAL ;
    PORT
      LAYER M4 ;
        RECT  0 22.56 0.084 22.584 ;
    END
  END o[122]
  PIN o[123]
    DIRECTION OUTPUT ;
    USE SIGNAL ;
    PORT
      LAYER M4 ;
        RECT  0 22.752 0.084 22.776 ;
    END
  END o[123]
  PIN o[124]
    DIRECTION OUTPUT ;
    USE SIGNAL ;
    PORT
      LAYER M4 ;
        RECT  0 22.944 0.084 22.968 ;
    END
  END o[124]
  PIN o[125]
    DIRECTION OUTPUT ;
    USE SIGNAL ;
    PORT
      LAYER M4 ;
        RECT  0 23.088 0.084 23.112 ;
    END
  END o[125]
  PIN o[126]
    DIRECTION OUTPUT ;
    USE SIGNAL ;
    PORT
      LAYER M4 ;
        RECT  0 23.28 0.084 23.304 ;
    END
  END o[126]
  PIN o[127]
    DIRECTION OUTPUT ;
    USE SIGNAL ;
    PORT
      LAYER M4 ;
        RECT  0 23.472 0.084 23.496 ;
    END
  END o[127]
  PIN o[128]
    DIRECTION OUTPUT ;
    USE SIGNAL ;
    PORT
      LAYER M4 ;
        RECT  0 23.616 0.084 23.64 ;
    END
  END o[128]
  PIN o[129]
    DIRECTION OUTPUT ;
    USE SIGNAL ;
    PORT
      LAYER M4 ;
        RECT  0 23.808 0.084 23.832 ;
    END
  END o[129]
  PIN o[12]
    DIRECTION OUTPUT ;
    USE SIGNAL ;
    PORT
      LAYER M4 ;
        RECT  0 3.168 0.084 3.192 ;
    END
  END o[12]
  PIN o[130]
    DIRECTION OUTPUT ;
    USE SIGNAL ;
    PORT
      LAYER M4 ;
        RECT  0 24 0.084 24.024 ;
    END
  END o[130]
  PIN o[131]
    DIRECTION OUTPUT ;
    USE SIGNAL ;
    PORT
      LAYER M4 ;
        RECT  0 24.144 0.084 24.168 ;
    END
  END o[131]
  PIN o[132]
    DIRECTION OUTPUT ;
    USE SIGNAL ;
    PORT
      LAYER M4 ;
        RECT  0 24.336 0.084 24.36 ;
    END
  END o[132]
  PIN o[133]
    DIRECTION OUTPUT ;
    USE SIGNAL ;
    PORT
      LAYER M4 ;
        RECT  0 24.528 0.084 24.552 ;
    END
  END o[133]
  PIN o[134]
    DIRECTION OUTPUT ;
    USE SIGNAL ;
    PORT
      LAYER M4 ;
        RECT  0 24.672 0.084 24.696 ;
    END
  END o[134]
  PIN o[135]
    DIRECTION OUTPUT ;
    USE SIGNAL ;
    PORT
      LAYER M4 ;
        RECT  0 24.864 0.084 24.888 ;
    END
  END o[135]
  PIN o[136]
    DIRECTION OUTPUT ;
    USE SIGNAL ;
    PORT
      LAYER M4 ;
        RECT  0 25.056 0.084 25.08 ;
    END
  END o[136]
  PIN o[137]
    DIRECTION OUTPUT ;
    USE SIGNAL ;
    PORT
      LAYER M4 ;
        RECT  0 25.2 0.084 25.224 ;
    END
  END o[137]
  PIN o[138]
    DIRECTION OUTPUT ;
    USE SIGNAL ;
    PORT
      LAYER M4 ;
        RECT  0 25.392 0.084 25.416 ;
    END
  END o[138]
  PIN o[139]
    DIRECTION OUTPUT ;
    USE SIGNAL ;
    PORT
      LAYER M4 ;
        RECT  0 25.584 0.084 25.608 ;
    END
  END o[139]
  PIN o[13]
    DIRECTION OUTPUT ;
    USE SIGNAL ;
    PORT
      LAYER M4 ;
        RECT  0 3.36 0.084 3.384 ;
    END
  END o[13]
  PIN o[140]
    DIRECTION OUTPUT ;
    USE SIGNAL ;
    PORT
      LAYER M4 ;
        RECT  0 25.728 0.084 25.752 ;
    END
  END o[140]
  PIN o[141]
    DIRECTION OUTPUT ;
    USE SIGNAL ;
    PORT
      LAYER M4 ;
        RECT  0 25.92 0.084 25.944 ;
    END
  END o[141]
  PIN o[142]
    DIRECTION OUTPUT ;
    USE SIGNAL ;
    PORT
      LAYER M4 ;
        RECT  0 26.112 0.084 26.136 ;
    END
  END o[142]
  PIN o[143]
    DIRECTION OUTPUT ;
    USE SIGNAL ;
    PORT
      LAYER M4 ;
        RECT  0 26.304 0.084 26.328 ;
    END
  END o[143]
  PIN o[144]
    DIRECTION OUTPUT ;
    USE SIGNAL ;
    PORT
      LAYER M4 ;
        RECT  0 26.448 0.084 26.472 ;
    END
  END o[144]
  PIN o[145]
    DIRECTION OUTPUT ;
    USE SIGNAL ;
    PORT
      LAYER M4 ;
        RECT  0 26.64 0.084 26.664 ;
    END
  END o[145]
  PIN o[146]
    DIRECTION OUTPUT ;
    USE SIGNAL ;
    PORT
      LAYER M4 ;
        RECT  0 26.832 0.084 26.856 ;
    END
  END o[146]
  PIN o[147]
    DIRECTION OUTPUT ;
    USE SIGNAL ;
    PORT
      LAYER M4 ;
        RECT  0 26.976 0.084 27 ;
    END
  END o[147]
  PIN o[148]
    DIRECTION OUTPUT ;
    USE SIGNAL ;
    PORT
      LAYER M4 ;
        RECT  0 27.168 0.084 27.192 ;
    END
  END o[148]
  PIN o[149]
    DIRECTION OUTPUT ;
    USE SIGNAL ;
    PORT
      LAYER M4 ;
        RECT  0 27.36 0.084 27.384 ;
    END
  END o[149]
  PIN o[14]
    DIRECTION OUTPUT ;
    USE SIGNAL ;
    PORT
      LAYER M4 ;
        RECT  0 3.552 0.084 3.576 ;
    END
  END o[14]
  PIN o[150]
    DIRECTION OUTPUT ;
    USE SIGNAL ;
    PORT
      LAYER M4 ;
        RECT  0 27.504 0.084 27.528 ;
    END
  END o[150]
  PIN o[151]
    DIRECTION OUTPUT ;
    USE SIGNAL ;
    PORT
      LAYER M4 ;
        RECT  0 27.696 0.084 27.72 ;
    END
  END o[151]
  PIN o[152]
    DIRECTION OUTPUT ;
    USE SIGNAL ;
    PORT
      LAYER M4 ;
        RECT  0 27.888 0.084 27.912 ;
    END
  END o[152]
  PIN o[153]
    DIRECTION OUTPUT ;
    USE SIGNAL ;
    PORT
      LAYER M4 ;
        RECT  0 28.032 0.084 28.056 ;
    END
  END o[153]
  PIN o[154]
    DIRECTION OUTPUT ;
    USE SIGNAL ;
    PORT
      LAYER M4 ;
        RECT  0 28.224 0.084 28.248 ;
    END
  END o[154]
  PIN o[155]
    DIRECTION OUTPUT ;
    USE SIGNAL ;
    PORT
      LAYER M4 ;
        RECT  0 28.416 0.084 28.44 ;
    END
  END o[155]
  PIN o[156]
    DIRECTION OUTPUT ;
    USE SIGNAL ;
    PORT
      LAYER M4 ;
        RECT  0 28.56 0.084 28.584 ;
    END
  END o[156]
  PIN o[157]
    DIRECTION OUTPUT ;
    USE SIGNAL ;
    PORT
      LAYER M4 ;
        RECT  0 28.752 0.084 28.776 ;
    END
  END o[157]
  PIN o[158]
    DIRECTION OUTPUT ;
    USE SIGNAL ;
    PORT
      LAYER M4 ;
        RECT  0 28.944 0.084 28.968 ;
    END
  END o[158]
  PIN o[159]
    DIRECTION OUTPUT ;
    USE SIGNAL ;
    PORT
      LAYER M4 ;
        RECT  0 29.088 0.084 29.112 ;
    END
  END o[159]
  PIN o[15]
    DIRECTION OUTPUT ;
    USE SIGNAL ;
    PORT
      LAYER M4 ;
        RECT  0 3.744 0.084 3.768 ;
    END
  END o[15]
  PIN o[160]
    DIRECTION OUTPUT ;
    USE SIGNAL ;
    PORT
      LAYER M4 ;
        RECT  0 29.28 0.084 29.304 ;
    END
  END o[160]
  PIN o[161]
    DIRECTION OUTPUT ;
    USE SIGNAL ;
    PORT
      LAYER M4 ;
        RECT  0 29.472 0.084 29.496 ;
    END
  END o[161]
  PIN o[162]
    DIRECTION OUTPUT ;
    USE SIGNAL ;
    PORT
      LAYER M4 ;
        RECT  0 29.616 0.084 29.64 ;
    END
  END o[162]
  PIN o[163]
    DIRECTION OUTPUT ;
    USE SIGNAL ;
    PORT
      LAYER M4 ;
        RECT  0 29.808 0.084 29.832 ;
    END
  END o[163]
  PIN o[164]
    DIRECTION OUTPUT ;
    USE SIGNAL ;
    PORT
      LAYER M4 ;
        RECT  0 30 0.084 30.024 ;
    END
  END o[164]
  PIN o[165]
    DIRECTION OUTPUT ;
    USE SIGNAL ;
    PORT
      LAYER M4 ;
        RECT  0 30.144 0.084 30.168 ;
    END
  END o[165]
  PIN o[166]
    DIRECTION OUTPUT ;
    USE SIGNAL ;
    PORT
      LAYER M4 ;
        RECT  0 30.336 0.084 30.36 ;
    END
  END o[166]
  PIN o[167]
    DIRECTION OUTPUT ;
    USE SIGNAL ;
    PORT
      LAYER M4 ;
        RECT  0 30.528 0.084 30.552 ;
    END
  END o[167]
  PIN o[168]
    DIRECTION OUTPUT ;
    USE SIGNAL ;
    PORT
      LAYER M4 ;
        RECT  0 30.672 0.084 30.696 ;
    END
  END o[168]
  PIN o[169]
    DIRECTION OUTPUT ;
    USE SIGNAL ;
    PORT
      LAYER M4 ;
        RECT  0 30.864 0.084 30.888 ;
    END
  END o[169]
  PIN o[16]
    DIRECTION OUTPUT ;
    USE SIGNAL ;
    PORT
      LAYER M4 ;
        RECT  0 3.888 0.084 3.912 ;
    END
  END o[16]
  PIN o[170]
    DIRECTION OUTPUT ;
    USE SIGNAL ;
    PORT
      LAYER M4 ;
        RECT  0 31.056 0.084 31.08 ;
    END
  END o[170]
  PIN o[171]
    DIRECTION OUTPUT ;
    USE SIGNAL ;
    PORT
      LAYER M4 ;
        RECT  0 31.2 0.084 31.224 ;
    END
  END o[171]
  PIN o[172]
    DIRECTION OUTPUT ;
    USE SIGNAL ;
    PORT
      LAYER M4 ;
        RECT  0 31.392 0.084 31.416 ;
    END
  END o[172]
  PIN o[173]
    DIRECTION OUTPUT ;
    USE SIGNAL ;
    PORT
      LAYER M4 ;
        RECT  0 31.584 0.084 31.608 ;
    END
  END o[173]
  PIN o[174]
    DIRECTION OUTPUT ;
    USE SIGNAL ;
    PORT
      LAYER M4 ;
        RECT  0 31.728 0.084 31.752 ;
    END
  END o[174]
  PIN o[175]
    DIRECTION OUTPUT ;
    USE SIGNAL ;
    PORT
      LAYER M4 ;
        RECT  0 31.92 0.084 31.944 ;
    END
  END o[175]
  PIN o[176]
    DIRECTION OUTPUT ;
    USE SIGNAL ;
    PORT
      LAYER M4 ;
        RECT  0 32.112 0.084 32.136 ;
    END
  END o[176]
  PIN o[177]
    DIRECTION OUTPUT ;
    USE SIGNAL ;
    PORT
      LAYER M4 ;
        RECT  0 32.256 0.084 32.28 ;
    END
  END o[177]
  PIN o[178]
    DIRECTION OUTPUT ;
    USE SIGNAL ;
    PORT
      LAYER M4 ;
        RECT  0 32.448 0.084 32.472 ;
    END
  END o[178]
  PIN o[179]
    DIRECTION OUTPUT ;
    USE SIGNAL ;
    PORT
      LAYER M4 ;
        RECT  0 32.64 0.084 32.664 ;
    END
  END o[179]
  PIN o[17]
    DIRECTION OUTPUT ;
    USE SIGNAL ;
    PORT
      LAYER M4 ;
        RECT  0 4.08 0.084 4.104 ;
    END
  END o[17]
  PIN o[180]
    DIRECTION OUTPUT ;
    USE SIGNAL ;
    PORT
      LAYER M4 ;
        RECT  0 32.784 0.084 32.808 ;
    END
  END o[180]
  PIN o[181]
    DIRECTION OUTPUT ;
    USE SIGNAL ;
    PORT
      LAYER M4 ;
        RECT  0 32.976 0.084 33 ;
    END
  END o[181]
  PIN o[182]
    DIRECTION OUTPUT ;
    USE SIGNAL ;
    PORT
      LAYER M4 ;
        RECT  0 33.168 0.084 33.192 ;
    END
  END o[182]
  PIN o[183]
    DIRECTION OUTPUT ;
    USE SIGNAL ;
    PORT
      LAYER M4 ;
        RECT  0 33.312 0.084 33.336 ;
    END
  END o[183]
  PIN o[184]
    DIRECTION OUTPUT ;
    USE SIGNAL ;
    PORT
      LAYER M4 ;
        RECT  0 33.504 0.084 33.528 ;
    END
  END o[184]
  PIN o[185]
    DIRECTION OUTPUT ;
    USE SIGNAL ;
    PORT
      LAYER M4 ;
        RECT  0 33.696 0.084 33.72 ;
    END
  END o[185]
  PIN o[186]
    DIRECTION OUTPUT ;
    USE SIGNAL ;
    PORT
      LAYER M4 ;
        RECT  0 33.84 0.084 33.864 ;
    END
  END o[186]
  PIN o[187]
    DIRECTION OUTPUT ;
    USE SIGNAL ;
    PORT
      LAYER M4 ;
        RECT  0 34.032 0.084 34.056 ;
    END
  END o[187]
  PIN o[188]
    DIRECTION OUTPUT ;
    USE SIGNAL ;
    PORT
      LAYER M4 ;
        RECT  0 34.224 0.084 34.248 ;
    END
  END o[188]
  PIN o[189]
    DIRECTION OUTPUT ;
    USE SIGNAL ;
    PORT
      LAYER M4 ;
        RECT  0 34.368 0.084 34.392 ;
    END
  END o[189]
  PIN o[18]
    DIRECTION OUTPUT ;
    USE SIGNAL ;
    PORT
      LAYER M4 ;
        RECT  0 4.272 0.084 4.296 ;
    END
  END o[18]
  PIN o[190]
    DIRECTION OUTPUT ;
    USE SIGNAL ;
    PORT
      LAYER M4 ;
        RECT  0 34.56 0.084 34.584 ;
    END
  END o[190]
  PIN o[191]
    DIRECTION OUTPUT ;
    USE SIGNAL ;
    PORT
      LAYER M4 ;
        RECT  0 34.752 0.084 34.776 ;
    END
  END o[191]
  PIN o[192]
    DIRECTION OUTPUT ;
    USE SIGNAL ;
    PORT
      LAYER M4 ;
        RECT  0 34.896 0.084 34.92 ;
    END
  END o[192]
  PIN o[193]
    DIRECTION OUTPUT ;
    USE SIGNAL ;
    PORT
      LAYER M4 ;
        RECT  0 35.088 0.084 35.112 ;
    END
  END o[193]
  PIN o[194]
    DIRECTION OUTPUT ;
    USE SIGNAL ;
    PORT
      LAYER M4 ;
        RECT  0 35.28 0.084 35.304 ;
    END
  END o[194]
  PIN o[195]
    DIRECTION OUTPUT ;
    USE SIGNAL ;
    PORT
      LAYER M4 ;
        RECT  0 35.424 0.084 35.448 ;
    END
  END o[195]
  PIN o[196]
    DIRECTION OUTPUT ;
    USE SIGNAL ;
    PORT
      LAYER M4 ;
        RECT  0 35.616 0.084 35.64 ;
    END
  END o[196]
  PIN o[197]
    DIRECTION OUTPUT ;
    USE SIGNAL ;
    PORT
      LAYER M4 ;
        RECT  0 35.808 0.084 35.832 ;
    END
  END o[197]
  PIN o[198]
    DIRECTION OUTPUT ;
    USE SIGNAL ;
    PORT
      LAYER M4 ;
        RECT  0 35.952 0.084 35.976 ;
    END
  END o[198]
  PIN o[199]
    DIRECTION OUTPUT ;
    USE SIGNAL ;
    PORT
      LAYER M4 ;
        RECT  0 36.144 0.084 36.168 ;
    END
  END o[199]
  PIN o[19]
    DIRECTION OUTPUT ;
    USE SIGNAL ;
    PORT
      LAYER M4 ;
        RECT  0 4.416 0.084 4.44 ;
    END
  END o[19]
  PIN o[1]
    DIRECTION OUTPUT ;
    USE SIGNAL ;
    PORT
      LAYER M4 ;
        RECT  0 1.248 0.084 1.272 ;
    END
  END o[1]
  PIN o[200]
    DIRECTION OUTPUT ;
    USE SIGNAL ;
    PORT
      LAYER M4 ;
        RECT  0 36.336 0.084 36.36 ;
    END
  END o[200]
  PIN o[201]
    DIRECTION OUTPUT ;
    USE SIGNAL ;
    PORT
      LAYER M4 ;
        RECT  0 36.48 0.084 36.504 ;
    END
  END o[201]
  PIN o[202]
    DIRECTION OUTPUT ;
    USE SIGNAL ;
    PORT
      LAYER M4 ;
        RECT  0 36.672 0.084 36.696 ;
    END
  END o[202]
  PIN o[203]
    DIRECTION OUTPUT ;
    USE SIGNAL ;
    PORT
      LAYER M4 ;
        RECT  0 36.864 0.084 36.888 ;
    END
  END o[203]
  PIN o[204]
    DIRECTION OUTPUT ;
    USE SIGNAL ;
    PORT
      LAYER M4 ;
        RECT  0 37.008 0.084 37.032 ;
    END
  END o[204]
  PIN o[205]
    DIRECTION OUTPUT ;
    USE SIGNAL ;
    PORT
      LAYER M4 ;
        RECT  0 37.2 0.084 37.224 ;
    END
  END o[205]
  PIN o[206]
    DIRECTION OUTPUT ;
    USE SIGNAL ;
    PORT
      LAYER M4 ;
        RECT  0 37.392 0.084 37.416 ;
    END
  END o[206]
  PIN o[207]
    DIRECTION OUTPUT ;
    USE SIGNAL ;
    PORT
      LAYER M4 ;
        RECT  0 37.584 0.084 37.608 ;
    END
  END o[207]
  PIN o[208]
    DIRECTION OUTPUT ;
    USE SIGNAL ;
    PORT
      LAYER M4 ;
        RECT  0 37.728 0.084 37.752 ;
    END
  END o[208]
  PIN o[209]
    DIRECTION OUTPUT ;
    USE SIGNAL ;
    PORT
      LAYER M4 ;
        RECT  0 37.92 0.084 37.944 ;
    END
  END o[209]
  PIN o[20]
    DIRECTION OUTPUT ;
    USE SIGNAL ;
    PORT
      LAYER M4 ;
        RECT  0 4.608 0.084 4.632 ;
    END
  END o[20]
  PIN o[210]
    DIRECTION OUTPUT ;
    USE SIGNAL ;
    PORT
      LAYER M4 ;
        RECT  0 38.112 0.084 38.136 ;
    END
  END o[210]
  PIN o[211]
    DIRECTION OUTPUT ;
    USE SIGNAL ;
    PORT
      LAYER M4 ;
        RECT  0 38.256 0.084 38.28 ;
    END
  END o[211]
  PIN o[212]
    DIRECTION OUTPUT ;
    USE SIGNAL ;
    PORT
      LAYER M4 ;
        RECT  0 38.448 0.084 38.472 ;
    END
  END o[212]
  PIN o[213]
    DIRECTION OUTPUT ;
    USE SIGNAL ;
    PORT
      LAYER M4 ;
        RECT  0 38.64 0.084 38.664 ;
    END
  END o[213]
  PIN o[214]
    DIRECTION OUTPUT ;
    USE SIGNAL ;
    PORT
      LAYER M4 ;
        RECT  0 38.784 0.084 38.808 ;
    END
  END o[214]
  PIN o[215]
    DIRECTION OUTPUT ;
    USE SIGNAL ;
    PORT
      LAYER M4 ;
        RECT  0 38.976 0.084 39 ;
    END
  END o[215]
  PIN o[216]
    DIRECTION OUTPUT ;
    USE SIGNAL ;
    PORT
      LAYER M4 ;
        RECT  0 39.168 0.084 39.192 ;
    END
  END o[216]
  PIN o[217]
    DIRECTION OUTPUT ;
    USE SIGNAL ;
    PORT
      LAYER M4 ;
        RECT  0 39.312 0.084 39.336 ;
    END
  END o[217]
  PIN o[218]
    DIRECTION OUTPUT ;
    USE SIGNAL ;
    PORT
      LAYER M4 ;
        RECT  0 39.504 0.084 39.528 ;
    END
  END o[218]
  PIN o[219]
    DIRECTION OUTPUT ;
    USE SIGNAL ;
    PORT
      LAYER M4 ;
        RECT  0 39.696 0.084 39.72 ;
    END
  END o[219]
  PIN o[21]
    DIRECTION OUTPUT ;
    USE SIGNAL ;
    PORT
      LAYER M4 ;
        RECT  0 4.8 0.084 4.824 ;
    END
  END o[21]
  PIN o[220]
    DIRECTION OUTPUT ;
    USE SIGNAL ;
    PORT
      LAYER M4 ;
        RECT  0 39.84 0.084 39.864 ;
    END
  END o[220]
  PIN o[221]
    DIRECTION OUTPUT ;
    USE SIGNAL ;
    PORT
      LAYER M4 ;
        RECT  0 40.032 0.084 40.056 ;
    END
  END o[221]
  PIN o[222]
    DIRECTION OUTPUT ;
    USE SIGNAL ;
    PORT
      LAYER M4 ;
        RECT  0 40.224 0.084 40.248 ;
    END
  END o[222]
  PIN o[223]
    DIRECTION OUTPUT ;
    USE SIGNAL ;
    PORT
      LAYER M4 ;
        RECT  0 40.368 0.084 40.392 ;
    END
  END o[223]
  PIN o[224]
    DIRECTION OUTPUT ;
    USE SIGNAL ;
    PORT
      LAYER M4 ;
        RECT  0 40.56 0.084 40.584 ;
    END
  END o[224]
  PIN o[225]
    DIRECTION OUTPUT ;
    USE SIGNAL ;
    PORT
      LAYER M4 ;
        RECT  0 40.752 0.084 40.776 ;
    END
  END o[225]
  PIN o[226]
    DIRECTION OUTPUT ;
    USE SIGNAL ;
    PORT
      LAYER M4 ;
        RECT  0 40.896 0.084 40.92 ;
    END
  END o[226]
  PIN o[227]
    DIRECTION OUTPUT ;
    USE SIGNAL ;
    PORT
      LAYER M4 ;
        RECT  0 41.088 0.084 41.112 ;
    END
  END o[227]
  PIN o[228]
    DIRECTION OUTPUT ;
    USE SIGNAL ;
    PORT
      LAYER M4 ;
        RECT  0 41.28 0.084 41.304 ;
    END
  END o[228]
  PIN o[229]
    DIRECTION OUTPUT ;
    USE SIGNAL ;
    PORT
      LAYER M4 ;
        RECT  0 41.424 0.084 41.448 ;
    END
  END o[229]
  PIN o[22]
    DIRECTION OUTPUT ;
    USE SIGNAL ;
    PORT
      LAYER M4 ;
        RECT  0 4.944 0.084 4.968 ;
    END
  END o[22]
  PIN o[230]
    DIRECTION OUTPUT ;
    USE SIGNAL ;
    PORT
      LAYER M4 ;
        RECT  0 41.616 0.084 41.64 ;
    END
  END o[230]
  PIN o[231]
    DIRECTION OUTPUT ;
    USE SIGNAL ;
    PORT
      LAYER M4 ;
        RECT  0 41.808 0.084 41.832 ;
    END
  END o[231]
  PIN o[232]
    DIRECTION OUTPUT ;
    USE SIGNAL ;
    PORT
      LAYER M4 ;
        RECT  0 41.952 0.084 41.976 ;
    END
  END o[232]
  PIN o[233]
    DIRECTION OUTPUT ;
    USE SIGNAL ;
    PORT
      LAYER M4 ;
        RECT  0 42.144 0.084 42.168 ;
    END
  END o[233]
  PIN o[234]
    DIRECTION OUTPUT ;
    USE SIGNAL ;
    PORT
      LAYER M4 ;
        RECT  0 42.336 0.084 42.36 ;
    END
  END o[234]
  PIN o[235]
    DIRECTION OUTPUT ;
    USE SIGNAL ;
    PORT
      LAYER M4 ;
        RECT  0 42.48 0.084 42.504 ;
    END
  END o[235]
  PIN o[236]
    DIRECTION OUTPUT ;
    USE SIGNAL ;
    PORT
      LAYER M4 ;
        RECT  0 42.672 0.084 42.696 ;
    END
  END o[236]
  PIN o[237]
    DIRECTION OUTPUT ;
    USE SIGNAL ;
    PORT
      LAYER M4 ;
        RECT  0 42.864 0.084 42.888 ;
    END
  END o[237]
  PIN o[238]
    DIRECTION OUTPUT ;
    USE SIGNAL ;
    PORT
      LAYER M4 ;
        RECT  0 43.008 0.084 43.032 ;
    END
  END o[238]
  PIN o[239]
    DIRECTION OUTPUT ;
    USE SIGNAL ;
    PORT
      LAYER M4 ;
        RECT  0 43.2 0.084 43.224 ;
    END
  END o[239]
  PIN o[23]
    DIRECTION OUTPUT ;
    USE SIGNAL ;
    PORT
      LAYER M4 ;
        RECT  0 5.136 0.084 5.16 ;
    END
  END o[23]
  PIN o[240]
    DIRECTION OUTPUT ;
    USE SIGNAL ;
    PORT
      LAYER M4 ;
        RECT  0 43.392 0.084 43.416 ;
    END
  END o[240]
  PIN o[241]
    DIRECTION OUTPUT ;
    USE SIGNAL ;
    PORT
      LAYER M4 ;
        RECT  0 43.536 0.084 43.56 ;
    END
  END o[241]
  PIN o[242]
    DIRECTION OUTPUT ;
    USE SIGNAL ;
    PORT
      LAYER M4 ;
        RECT  0 43.728 0.084 43.752 ;
    END
  END o[242]
  PIN o[243]
    DIRECTION OUTPUT ;
    USE SIGNAL ;
    PORT
      LAYER M4 ;
        RECT  0 43.92 0.084 43.944 ;
    END
  END o[243]
  PIN o[244]
    DIRECTION OUTPUT ;
    USE SIGNAL ;
    PORT
      LAYER M4 ;
        RECT  0 44.064 0.084 44.088 ;
    END
  END o[244]
  PIN o[245]
    DIRECTION OUTPUT ;
    USE SIGNAL ;
    PORT
      LAYER M4 ;
        RECT  0 44.256 0.084 44.28 ;
    END
  END o[245]
  PIN o[246]
    DIRECTION OUTPUT ;
    USE SIGNAL ;
    PORT
      LAYER M4 ;
        RECT  0 44.448 0.084 44.472 ;
    END
  END o[246]
  PIN o[247]
    DIRECTION OUTPUT ;
    USE SIGNAL ;
    PORT
      LAYER M4 ;
        RECT  0 44.592 0.084 44.616 ;
    END
  END o[247]
  PIN o[248]
    DIRECTION OUTPUT ;
    USE SIGNAL ;
    PORT
      LAYER M4 ;
        RECT  0 44.784 0.084 44.808 ;
    END
  END o[248]
  PIN o[249]
    DIRECTION OUTPUT ;
    USE SIGNAL ;
    PORT
      LAYER M4 ;
        RECT  0 44.976 0.084 45 ;
    END
  END o[249]
  PIN o[24]
    DIRECTION OUTPUT ;
    USE SIGNAL ;
    PORT
      LAYER M4 ;
        RECT  0 5.328 0.084 5.352 ;
    END
  END o[24]
  PIN o[250]
    DIRECTION OUTPUT ;
    USE SIGNAL ;
    PORT
      LAYER M4 ;
        RECT  0 45.12 0.084 45.144 ;
    END
  END o[250]
  PIN o[251]
    DIRECTION OUTPUT ;
    USE SIGNAL ;
    PORT
      LAYER M4 ;
        RECT  0 45.312 0.084 45.336 ;
    END
  END o[251]
  PIN o[252]
    DIRECTION OUTPUT ;
    USE SIGNAL ;
    PORT
      LAYER M4 ;
        RECT  0 45.504 0.084 45.528 ;
    END
  END o[252]
  PIN o[253]
    DIRECTION OUTPUT ;
    USE SIGNAL ;
    PORT
      LAYER M4 ;
        RECT  0 45.648 0.084 45.672 ;
    END
  END o[253]
  PIN o[254]
    DIRECTION OUTPUT ;
    USE SIGNAL ;
    PORT
      LAYER M4 ;
        RECT  0 45.84 0.084 45.864 ;
    END
  END o[254]
  PIN o[255]
    DIRECTION OUTPUT ;
    USE SIGNAL ;
    PORT
      LAYER M4 ;
        RECT  0 46.032 0.084 46.056 ;
    END
  END o[255]
  PIN o[256]
    DIRECTION OUTPUT ;
    USE SIGNAL ;
    PORT
      LAYER M4 ;
        RECT  0 46.176 0.084 46.2 ;
    END
  END o[256]
  PIN o[257]
    DIRECTION OUTPUT ;
    USE SIGNAL ;
    PORT
      LAYER M4 ;
        RECT  0 46.368 0.084 46.392 ;
    END
  END o[257]
  PIN o[258]
    DIRECTION OUTPUT ;
    USE SIGNAL ;
    PORT
      LAYER M4 ;
        RECT  0 46.56 0.084 46.584 ;
    END
  END o[258]
  PIN o[259]
    DIRECTION OUTPUT ;
    USE SIGNAL ;
    PORT
      LAYER M4 ;
        RECT  0 46.704 0.084 46.728 ;
    END
  END o[259]
  PIN o[25]
    DIRECTION OUTPUT ;
    USE SIGNAL ;
    PORT
      LAYER M4 ;
        RECT  0 5.472 0.084 5.496 ;
    END
  END o[25]
  PIN o[260]
    DIRECTION OUTPUT ;
    USE SIGNAL ;
    PORT
      LAYER M4 ;
        RECT  0 46.896 0.084 46.92 ;
    END
  END o[260]
  PIN o[261]
    DIRECTION OUTPUT ;
    USE SIGNAL ;
    PORT
      LAYER M4 ;
        RECT  0 47.088 0.084 47.112 ;
    END
  END o[261]
  PIN o[262]
    DIRECTION OUTPUT ;
    USE SIGNAL ;
    PORT
      LAYER M4 ;
        RECT  0 47.232 0.084 47.256 ;
    END
  END o[262]
  PIN o[263]
    DIRECTION OUTPUT ;
    USE SIGNAL ;
    PORT
      LAYER M4 ;
        RECT  0 47.424 0.084 47.448 ;
    END
  END o[263]
  PIN o[264]
    DIRECTION OUTPUT ;
    USE SIGNAL ;
    PORT
      LAYER M4 ;
        RECT  0 47.616 0.084 47.64 ;
    END
  END o[264]
  PIN o[265]
    DIRECTION OUTPUT ;
    USE SIGNAL ;
    PORT
      LAYER M4 ;
        RECT  0 47.76 0.084 47.784 ;
    END
  END o[265]
  PIN o[266]
    DIRECTION OUTPUT ;
    USE SIGNAL ;
    PORT
      LAYER M4 ;
        RECT  0 47.952 0.084 47.976 ;
    END
  END o[266]
  PIN o[267]
    DIRECTION OUTPUT ;
    USE SIGNAL ;
    PORT
      LAYER M4 ;
        RECT  0 48.144 0.084 48.168 ;
    END
  END o[267]
  PIN o[268]
    DIRECTION OUTPUT ;
    USE SIGNAL ;
    PORT
      LAYER M4 ;
        RECT  0 48.288 0.084 48.312 ;
    END
  END o[268]
  PIN o[269]
    DIRECTION OUTPUT ;
    USE SIGNAL ;
    PORT
      LAYER M4 ;
        RECT  0 48.48 0.084 48.504 ;
    END
  END o[269]
  PIN o[26]
    DIRECTION OUTPUT ;
    USE SIGNAL ;
    PORT
      LAYER M4 ;
        RECT  0 5.664 0.084 5.688 ;
    END
  END o[26]
  PIN o[270]
    DIRECTION OUTPUT ;
    USE SIGNAL ;
    PORT
      LAYER M4 ;
        RECT  0 48.672 0.084 48.696 ;
    END
  END o[270]
  PIN o[271]
    DIRECTION OUTPUT ;
    USE SIGNAL ;
    PORT
      LAYER M4 ;
        RECT  0 48.864 0.084 48.888 ;
    END
  END o[271]
  PIN o[272]
    DIRECTION OUTPUT ;
    USE SIGNAL ;
    PORT
      LAYER M4 ;
        RECT  0 49.008 0.084 49.032 ;
    END
  END o[272]
  PIN o[273]
    DIRECTION OUTPUT ;
    USE SIGNAL ;
    PORT
      LAYER M4 ;
        RECT  0 49.2 0.084 49.224 ;
    END
  END o[273]
  PIN o[274]
    DIRECTION OUTPUT ;
    USE SIGNAL ;
    PORT
      LAYER M4 ;
        RECT  0 49.392 0.084 49.416 ;
    END
  END o[274]
  PIN o[275]
    DIRECTION OUTPUT ;
    USE SIGNAL ;
    PORT
      LAYER M4 ;
        RECT  0 49.536 0.084 49.56 ;
    END
  END o[275]
  PIN o[276]
    DIRECTION OUTPUT ;
    USE SIGNAL ;
    PORT
      LAYER M4 ;
        RECT  0 49.728 0.084 49.752 ;
    END
  END o[276]
  PIN o[277]
    DIRECTION OUTPUT ;
    USE SIGNAL ;
    PORT
      LAYER M4 ;
        RECT  0 49.92 0.084 49.944 ;
    END
  END o[277]
  PIN o[278]
    DIRECTION OUTPUT ;
    USE SIGNAL ;
    PORT
      LAYER M4 ;
        RECT  0 50.064 0.084 50.088 ;
    END
  END o[278]
  PIN o[279]
    DIRECTION OUTPUT ;
    USE SIGNAL ;
    PORT
      LAYER M4 ;
        RECT  0 50.256 0.084 50.28 ;
    END
  END o[279]
  PIN o[27]
    DIRECTION OUTPUT ;
    USE SIGNAL ;
    PORT
      LAYER M4 ;
        RECT  0 5.856 0.084 5.88 ;
    END
  END o[27]
  PIN o[280]
    DIRECTION OUTPUT ;
    USE SIGNAL ;
    PORT
      LAYER M4 ;
        RECT  0 50.448 0.084 50.472 ;
    END
  END o[280]
  PIN o[281]
    DIRECTION OUTPUT ;
    USE SIGNAL ;
    PORT
      LAYER M4 ;
        RECT  0 50.592 0.084 50.616 ;
    END
  END o[281]
  PIN o[282]
    DIRECTION OUTPUT ;
    USE SIGNAL ;
    PORT
      LAYER M4 ;
        RECT  0 50.784 0.084 50.808 ;
    END
  END o[282]
  PIN o[283]
    DIRECTION OUTPUT ;
    USE SIGNAL ;
    PORT
      LAYER M4 ;
        RECT  0 50.976 0.084 51 ;
    END
  END o[283]
  PIN o[284]
    DIRECTION OUTPUT ;
    USE SIGNAL ;
    PORT
      LAYER M4 ;
        RECT  0 51.12 0.084 51.144 ;
    END
  END o[284]
  PIN o[285]
    DIRECTION OUTPUT ;
    USE SIGNAL ;
    PORT
      LAYER M4 ;
        RECT  0 51.312 0.084 51.336 ;
    END
  END o[285]
  PIN o[286]
    DIRECTION OUTPUT ;
    USE SIGNAL ;
    PORT
      LAYER M4 ;
        RECT  0 51.504 0.084 51.528 ;
    END
  END o[286]
  PIN o[287]
    DIRECTION OUTPUT ;
    USE SIGNAL ;
    PORT
      LAYER M4 ;
        RECT  0 51.648 0.084 51.672 ;
    END
  END o[287]
  PIN o[288]
    DIRECTION OUTPUT ;
    USE SIGNAL ;
    PORT
      LAYER M4 ;
        RECT  0 51.84 0.084 51.864 ;
    END
  END o[288]
  PIN o[289]
    DIRECTION OUTPUT ;
    USE SIGNAL ;
    PORT
      LAYER M4 ;
        RECT  0 52.032 0.084 52.056 ;
    END
  END o[289]
  PIN o[28]
    DIRECTION OUTPUT ;
    USE SIGNAL ;
    PORT
      LAYER M4 ;
        RECT  0 6 0.084 6.024 ;
    END
  END o[28]
  PIN o[290]
    DIRECTION OUTPUT ;
    USE SIGNAL ;
    PORT
      LAYER M4 ;
        RECT  0 52.176 0.084 52.2 ;
    END
  END o[290]
  PIN o[291]
    DIRECTION OUTPUT ;
    USE SIGNAL ;
    PORT
      LAYER M4 ;
        RECT  0 52.368 0.084 52.392 ;
    END
  END o[291]
  PIN o[292]
    DIRECTION OUTPUT ;
    USE SIGNAL ;
    PORT
      LAYER M4 ;
        RECT  0 52.56 0.084 52.584 ;
    END
  END o[292]
  PIN o[293]
    DIRECTION OUTPUT ;
    USE SIGNAL ;
    PORT
      LAYER M4 ;
        RECT  0 52.704 0.084 52.728 ;
    END
  END o[293]
  PIN o[294]
    DIRECTION OUTPUT ;
    USE SIGNAL ;
    PORT
      LAYER M4 ;
        RECT  0 52.896 0.084 52.92 ;
    END
  END o[294]
  PIN o[295]
    DIRECTION OUTPUT ;
    USE SIGNAL ;
    PORT
      LAYER M4 ;
        RECT  0 53.088 0.084 53.112 ;
    END
  END o[295]
  PIN o[296]
    DIRECTION OUTPUT ;
    USE SIGNAL ;
    PORT
      LAYER M4 ;
        RECT  0 53.232 0.084 53.256 ;
    END
  END o[296]
  PIN o[297]
    DIRECTION OUTPUT ;
    USE SIGNAL ;
    PORT
      LAYER M4 ;
        RECT  0 53.424 0.084 53.448 ;
    END
  END o[297]
  PIN o[298]
    DIRECTION OUTPUT ;
    USE SIGNAL ;
    PORT
      LAYER M4 ;
        RECT  0 53.616 0.084 53.64 ;
    END
  END o[298]
  PIN o[299]
    DIRECTION OUTPUT ;
    USE SIGNAL ;
    PORT
      LAYER M4 ;
        RECT  0 53.76 0.084 53.784 ;
    END
  END o[299]
  PIN o[29]
    DIRECTION OUTPUT ;
    USE SIGNAL ;
    PORT
      LAYER M4 ;
        RECT  0 6.192 0.084 6.216 ;
    END
  END o[29]
  PIN o[2]
    DIRECTION OUTPUT ;
    USE SIGNAL ;
    PORT
      LAYER M4 ;
        RECT  0 1.44 0.084 1.464 ;
    END
  END o[2]
  PIN o[300]
    DIRECTION OUTPUT ;
    USE SIGNAL ;
    PORT
      LAYER M4 ;
        RECT  0 53.952 0.084 53.976 ;
    END
  END o[300]
  PIN o[301]
    DIRECTION OUTPUT ;
    USE SIGNAL ;
    PORT
      LAYER M4 ;
        RECT  0 54.144 0.084 54.168 ;
    END
  END o[301]
  PIN o[302]
    DIRECTION OUTPUT ;
    USE SIGNAL ;
    PORT
      LAYER M4 ;
        RECT  0 54.288 0.084 54.312 ;
    END
  END o[302]
  PIN o[303]
    DIRECTION OUTPUT ;
    USE SIGNAL ;
    PORT
      LAYER M4 ;
        RECT  0 54.48 0.084 54.504 ;
    END
  END o[303]
  PIN o[304]
    DIRECTION OUTPUT ;
    USE SIGNAL ;
    PORT
      LAYER M4 ;
        RECT  0 54.672 0.084 54.696 ;
    END
  END o[304]
  PIN o[305]
    DIRECTION OUTPUT ;
    USE SIGNAL ;
    PORT
      LAYER M4 ;
        RECT  0 54.816 0.084 54.84 ;
    END
  END o[305]
  PIN o[306]
    DIRECTION OUTPUT ;
    USE SIGNAL ;
    PORT
      LAYER M4 ;
        RECT  0 55.008 0.084 55.032 ;
    END
  END o[306]
  PIN o[307]
    DIRECTION OUTPUT ;
    USE SIGNAL ;
    PORT
      LAYER M4 ;
        RECT  0 55.2 0.084 55.224 ;
    END
  END o[307]
  PIN o[308]
    DIRECTION OUTPUT ;
    USE SIGNAL ;
    PORT
      LAYER M4 ;
        RECT  0 55.344 0.084 55.368 ;
    END
  END o[308]
  PIN o[309]
    DIRECTION OUTPUT ;
    USE SIGNAL ;
    PORT
      LAYER M4 ;
        RECT  0 55.536 0.084 55.56 ;
    END
  END o[309]
  PIN o[30]
    DIRECTION OUTPUT ;
    USE SIGNAL ;
    PORT
      LAYER M4 ;
        RECT  0 6.384 0.084 6.408 ;
    END
  END o[30]
  PIN o[310]
    DIRECTION OUTPUT ;
    USE SIGNAL ;
    PORT
      LAYER M4 ;
        RECT  0 55.728 0.084 55.752 ;
    END
  END o[310]
  PIN o[311]
    DIRECTION OUTPUT ;
    USE SIGNAL ;
    PORT
      LAYER M4 ;
        RECT  0 55.872 0.084 55.896 ;
    END
  END o[311]
  PIN o[312]
    DIRECTION OUTPUT ;
    USE SIGNAL ;
    PORT
      LAYER M4 ;
        RECT  0 56.064 0.084 56.088 ;
    END
  END o[312]
  PIN o[313]
    DIRECTION OUTPUT ;
    USE SIGNAL ;
    PORT
      LAYER M4 ;
        RECT  0 56.256 0.084 56.28 ;
    END
  END o[313]
  PIN o[314]
    DIRECTION OUTPUT ;
    USE SIGNAL ;
    PORT
      LAYER M4 ;
        RECT  0 56.4 0.084 56.424 ;
    END
  END o[314]
  PIN o[315]
    DIRECTION OUTPUT ;
    USE SIGNAL ;
    PORT
      LAYER M4 ;
        RECT  0 56.592 0.084 56.616 ;
    END
  END o[315]
  PIN o[316]
    DIRECTION OUTPUT ;
    USE SIGNAL ;
    PORT
      LAYER M4 ;
        RECT  0 56.784 0.084 56.808 ;
    END
  END o[316]
  PIN o[317]
    DIRECTION OUTPUT ;
    USE SIGNAL ;
    PORT
      LAYER M4 ;
        RECT  0 56.928 0.084 56.952 ;
    END
  END o[317]
  PIN o[318]
    DIRECTION OUTPUT ;
    USE SIGNAL ;
    PORT
      LAYER M4 ;
        RECT  0 57.12 0.084 57.144 ;
    END
  END o[318]
  PIN o[319]
    DIRECTION OUTPUT ;
    USE SIGNAL ;
    PORT
      LAYER M4 ;
        RECT  0 57.312 0.084 57.336 ;
    END
  END o[319]
  PIN o[31]
    DIRECTION OUTPUT ;
    USE SIGNAL ;
    PORT
      LAYER M4 ;
        RECT  0 6.528 0.084 6.552 ;
    END
  END o[31]
  PIN o[320]
    DIRECTION OUTPUT ;
    USE SIGNAL ;
    PORT
      LAYER M4 ;
        RECT  0 57.456 0.084 57.48 ;
    END
  END o[320]
  PIN o[321]
    DIRECTION OUTPUT ;
    USE SIGNAL ;
    PORT
      LAYER M4 ;
        RECT  0 57.648 0.084 57.672 ;
    END
  END o[321]
  PIN o[322]
    DIRECTION OUTPUT ;
    USE SIGNAL ;
    PORT
      LAYER M4 ;
        RECT  0 57.84 0.084 57.864 ;
    END
  END o[322]
  PIN o[323]
    DIRECTION OUTPUT ;
    USE SIGNAL ;
    PORT
      LAYER M4 ;
        RECT  0 57.984 0.084 58.008 ;
    END
  END o[323]
  PIN o[324]
    DIRECTION OUTPUT ;
    USE SIGNAL ;
    PORT
      LAYER M4 ;
        RECT  0 58.176 0.084 58.2 ;
    END
  END o[324]
  PIN o[325]
    DIRECTION OUTPUT ;
    USE SIGNAL ;
    PORT
      LAYER M4 ;
        RECT  0 58.368 0.084 58.392 ;
    END
  END o[325]
  PIN o[326]
    DIRECTION OUTPUT ;
    USE SIGNAL ;
    PORT
      LAYER M4 ;
        RECT  0 58.512 0.084 58.536 ;
    END
  END o[326]
  PIN o[327]
    DIRECTION OUTPUT ;
    USE SIGNAL ;
    PORT
      LAYER M4 ;
        RECT  0 58.704 0.084 58.728 ;
    END
  END o[327]
  PIN o[328]
    DIRECTION OUTPUT ;
    USE SIGNAL ;
    PORT
      LAYER M4 ;
        RECT  0 58.896 0.084 58.92 ;
    END
  END o[328]
  PIN o[329]
    DIRECTION OUTPUT ;
    USE SIGNAL ;
    PORT
      LAYER M4 ;
        RECT  0 59.04 0.084 59.064 ;
    END
  END o[329]
  PIN o[32]
    DIRECTION OUTPUT ;
    USE SIGNAL ;
    PORT
      LAYER M4 ;
        RECT  0 6.72 0.084 6.744 ;
    END
  END o[32]
  PIN o[330]
    DIRECTION OUTPUT ;
    USE SIGNAL ;
    PORT
      LAYER M4 ;
        RECT  0 59.232 0.084 59.256 ;
    END
  END o[330]
  PIN o[331]
    DIRECTION OUTPUT ;
    USE SIGNAL ;
    PORT
      LAYER M4 ;
        RECT  0 59.424 0.084 59.448 ;
    END
  END o[331]
  PIN o[332]
    DIRECTION OUTPUT ;
    USE SIGNAL ;
    PORT
      LAYER M4 ;
        RECT  0 59.568 0.084 59.592 ;
    END
  END o[332]
  PIN o[333]
    DIRECTION OUTPUT ;
    USE SIGNAL ;
    PORT
      LAYER M4 ;
        RECT  0 59.76 0.084 59.784 ;
    END
  END o[333]
  PIN o[334]
    DIRECTION OUTPUT ;
    USE SIGNAL ;
    PORT
      LAYER M4 ;
        RECT  0 59.952 0.084 59.976 ;
    END
  END o[334]
  PIN o[335]
    DIRECTION OUTPUT ;
    USE SIGNAL ;
    PORT
      LAYER M4 ;
        RECT  0 60.144 0.084 60.168 ;
    END
  END o[335]
  PIN o[336]
    DIRECTION OUTPUT ;
    USE SIGNAL ;
    PORT
      LAYER M4 ;
        RECT  0 60.288 0.084 60.312 ;
    END
  END o[336]
  PIN o[337]
    DIRECTION OUTPUT ;
    USE SIGNAL ;
    PORT
      LAYER M4 ;
        RECT  0 60.48 0.084 60.504 ;
    END
  END o[337]
  PIN o[338]
    DIRECTION OUTPUT ;
    USE SIGNAL ;
    PORT
      LAYER M4 ;
        RECT  0 60.672 0.084 60.696 ;
    END
  END o[338]
  PIN o[339]
    DIRECTION OUTPUT ;
    USE SIGNAL ;
    PORT
      LAYER M4 ;
        RECT  0 60.816 0.084 60.84 ;
    END
  END o[339]
  PIN o[33]
    DIRECTION OUTPUT ;
    USE SIGNAL ;
    PORT
      LAYER M4 ;
        RECT  0 6.912 0.084 6.936 ;
    END
  END o[33]
  PIN o[340]
    DIRECTION OUTPUT ;
    USE SIGNAL ;
    PORT
      LAYER M4 ;
        RECT  0 61.008 0.084 61.032 ;
    END
  END o[340]
  PIN o[341]
    DIRECTION OUTPUT ;
    USE SIGNAL ;
    PORT
      LAYER M4 ;
        RECT  0 61.2 0.084 61.224 ;
    END
  END o[341]
  PIN o[342]
    DIRECTION OUTPUT ;
    USE SIGNAL ;
    PORT
      LAYER M4 ;
        RECT  0 61.344 0.084 61.368 ;
    END
  END o[342]
  PIN o[343]
    DIRECTION OUTPUT ;
    USE SIGNAL ;
    PORT
      LAYER M4 ;
        RECT  0 61.536 0.084 61.56 ;
    END
  END o[343]
  PIN o[344]
    DIRECTION OUTPUT ;
    USE SIGNAL ;
    PORT
      LAYER M4 ;
        RECT  0 61.728 0.084 61.752 ;
    END
  END o[344]
  PIN o[345]
    DIRECTION OUTPUT ;
    USE SIGNAL ;
    PORT
      LAYER M4 ;
        RECT  0 61.872 0.084 61.896 ;
    END
  END o[345]
  PIN o[346]
    DIRECTION OUTPUT ;
    USE SIGNAL ;
    PORT
      LAYER M4 ;
        RECT  0 62.064 0.084 62.088 ;
    END
  END o[346]
  PIN o[347]
    DIRECTION OUTPUT ;
    USE SIGNAL ;
    PORT
      LAYER M4 ;
        RECT  0 62.256 0.084 62.28 ;
    END
  END o[347]
  PIN o[348]
    DIRECTION OUTPUT ;
    USE SIGNAL ;
    PORT
      LAYER M4 ;
        RECT  0 62.4 0.084 62.424 ;
    END
  END o[348]
  PIN o[349]
    DIRECTION OUTPUT ;
    USE SIGNAL ;
    PORT
      LAYER M4 ;
        RECT  0 62.592 0.084 62.616 ;
    END
  END o[349]
  PIN o[34]
    DIRECTION OUTPUT ;
    USE SIGNAL ;
    PORT
      LAYER M4 ;
        RECT  0 7.056 0.084 7.08 ;
    END
  END o[34]
  PIN o[350]
    DIRECTION OUTPUT ;
    USE SIGNAL ;
    PORT
      LAYER M4 ;
        RECT  0 62.784 0.084 62.808 ;
    END
  END o[350]
  PIN o[351]
    DIRECTION OUTPUT ;
    USE SIGNAL ;
    PORT
      LAYER M4 ;
        RECT  0 62.928 0.084 62.952 ;
    END
  END o[351]
  PIN o[352]
    DIRECTION OUTPUT ;
    USE SIGNAL ;
    PORT
      LAYER M4 ;
        RECT  0 63.12 0.084 63.144 ;
    END
  END o[352]
  PIN o[353]
    DIRECTION OUTPUT ;
    USE SIGNAL ;
    PORT
      LAYER M4 ;
        RECT  0 63.312 0.084 63.336 ;
    END
  END o[353]
  PIN o[354]
    DIRECTION OUTPUT ;
    USE SIGNAL ;
    PORT
      LAYER M4 ;
        RECT  0 63.456 0.084 63.48 ;
    END
  END o[354]
  PIN o[355]
    DIRECTION OUTPUT ;
    USE SIGNAL ;
    PORT
      LAYER M4 ;
        RECT  0 63.648 0.084 63.672 ;
    END
  END o[355]
  PIN o[356]
    DIRECTION OUTPUT ;
    USE SIGNAL ;
    PORT
      LAYER M4 ;
        RECT  0 63.84 0.084 63.864 ;
    END
  END o[356]
  PIN o[357]
    DIRECTION OUTPUT ;
    USE SIGNAL ;
    PORT
      LAYER M4 ;
        RECT  0 63.984 0.084 64.008 ;
    END
  END o[357]
  PIN o[358]
    DIRECTION OUTPUT ;
    USE SIGNAL ;
    PORT
      LAYER M4 ;
        RECT  0 64.176 0.084 64.2 ;
    END
  END o[358]
  PIN o[359]
    DIRECTION OUTPUT ;
    USE SIGNAL ;
    PORT
      LAYER M4 ;
        RECT  0 64.368 0.084 64.392 ;
    END
  END o[359]
  PIN o[35]
    DIRECTION OUTPUT ;
    USE SIGNAL ;
    PORT
      LAYER M4 ;
        RECT  0 7.248 0.084 7.272 ;
    END
  END o[35]
  PIN o[360]
    DIRECTION OUTPUT ;
    USE SIGNAL ;
    PORT
      LAYER M4 ;
        RECT  0 64.512 0.084 64.536 ;
    END
  END o[360]
  PIN o[361]
    DIRECTION OUTPUT ;
    USE SIGNAL ;
    PORT
      LAYER M4 ;
        RECT  0 64.704 0.084 64.728 ;
    END
  END o[361]
  PIN o[362]
    DIRECTION OUTPUT ;
    USE SIGNAL ;
    PORT
      LAYER M4 ;
        RECT  0 64.896 0.084 64.92 ;
    END
  END o[362]
  PIN o[363]
    DIRECTION OUTPUT ;
    USE SIGNAL ;
    PORT
      LAYER M4 ;
        RECT  0 65.04 0.084 65.064 ;
    END
  END o[363]
  PIN o[364]
    DIRECTION OUTPUT ;
    USE SIGNAL ;
    PORT
      LAYER M4 ;
        RECT  0 65.232 0.084 65.256 ;
    END
  END o[364]
  PIN o[365]
    DIRECTION OUTPUT ;
    USE SIGNAL ;
    PORT
      LAYER M4 ;
        RECT  0 65.424 0.084 65.448 ;
    END
  END o[365]
  PIN o[366]
    DIRECTION OUTPUT ;
    USE SIGNAL ;
    PORT
      LAYER M4 ;
        RECT  0 65.568 0.084 65.592 ;
    END
  END o[366]
  PIN o[367]
    DIRECTION OUTPUT ;
    USE SIGNAL ;
    PORT
      LAYER M4 ;
        RECT  0 65.76 0.084 65.784 ;
    END
  END o[367]
  PIN o[368]
    DIRECTION OUTPUT ;
    USE SIGNAL ;
    PORT
      LAYER M4 ;
        RECT  0 65.952 0.084 65.976 ;
    END
  END o[368]
  PIN o[369]
    DIRECTION OUTPUT ;
    USE SIGNAL ;
    PORT
      LAYER M4 ;
        RECT  0 66.096 0.084 66.12 ;
    END
  END o[369]
  PIN o[36]
    DIRECTION OUTPUT ;
    USE SIGNAL ;
    PORT
      LAYER M4 ;
        RECT  0 7.44 0.084 7.464 ;
    END
  END o[36]
  PIN o[370]
    DIRECTION OUTPUT ;
    USE SIGNAL ;
    PORT
      LAYER M4 ;
        RECT  0 66.288 0.084 66.312 ;
    END
  END o[370]
  PIN o[371]
    DIRECTION OUTPUT ;
    USE SIGNAL ;
    PORT
      LAYER M4 ;
        RECT  0 66.48 0.084 66.504 ;
    END
  END o[371]
  PIN o[372]
    DIRECTION OUTPUT ;
    USE SIGNAL ;
    PORT
      LAYER M4 ;
        RECT  0 66.624 0.084 66.648 ;
    END
  END o[372]
  PIN o[373]
    DIRECTION OUTPUT ;
    USE SIGNAL ;
    PORT
      LAYER M4 ;
        RECT  0 66.816 0.084 66.84 ;
    END
  END o[373]
  PIN o[374]
    DIRECTION OUTPUT ;
    USE SIGNAL ;
    PORT
      LAYER M4 ;
        RECT  0 67.008 0.084 67.032 ;
    END
  END o[374]
  PIN o[375]
    DIRECTION OUTPUT ;
    USE SIGNAL ;
    PORT
      LAYER M4 ;
        RECT  0 67.152 0.084 67.176 ;
    END
  END o[375]
  PIN o[376]
    DIRECTION OUTPUT ;
    USE SIGNAL ;
    PORT
      LAYER M4 ;
        RECT  0 67.344 0.084 67.368 ;
    END
  END o[376]
  PIN o[377]
    DIRECTION OUTPUT ;
    USE SIGNAL ;
    PORT
      LAYER M4 ;
        RECT  0 67.536 0.084 67.56 ;
    END
  END o[377]
  PIN o[378]
    DIRECTION OUTPUT ;
    USE SIGNAL ;
    PORT
      LAYER M4 ;
        RECT  0 67.68 0.084 67.704 ;
    END
  END o[378]
  PIN o[379]
    DIRECTION OUTPUT ;
    USE SIGNAL ;
    PORT
      LAYER M4 ;
        RECT  0 67.872 0.084 67.896 ;
    END
  END o[379]
  PIN o[37]
    DIRECTION OUTPUT ;
    USE SIGNAL ;
    PORT
      LAYER M4 ;
        RECT  0 7.584 0.084 7.608 ;
    END
  END o[37]
  PIN o[380]
    DIRECTION OUTPUT ;
    USE SIGNAL ;
    PORT
      LAYER M4 ;
        RECT  0 68.064 0.084 68.088 ;
    END
  END o[380]
  PIN o[381]
    DIRECTION OUTPUT ;
    USE SIGNAL ;
    PORT
      LAYER M4 ;
        RECT  0 68.208 0.084 68.232 ;
    END
  END o[381]
  PIN o[382]
    DIRECTION OUTPUT ;
    USE SIGNAL ;
    PORT
      LAYER M4 ;
        RECT  0 68.4 0.084 68.424 ;
    END
  END o[382]
  PIN o[383]
    DIRECTION OUTPUT ;
    USE SIGNAL ;
    PORT
      LAYER M4 ;
        RECT  0 68.592 0.084 68.616 ;
    END
  END o[383]
  PIN o[384]
    DIRECTION OUTPUT ;
    USE SIGNAL ;
    PORT
      LAYER M4 ;
        RECT  0 68.736 0.084 68.76 ;
    END
  END o[384]
  PIN o[385]
    DIRECTION OUTPUT ;
    USE SIGNAL ;
    PORT
      LAYER M4 ;
        RECT  0 68.928 0.084 68.952 ;
    END
  END o[385]
  PIN o[386]
    DIRECTION OUTPUT ;
    USE SIGNAL ;
    PORT
      LAYER M4 ;
        RECT  0 69.12 0.084 69.144 ;
    END
  END o[386]
  PIN o[387]
    DIRECTION OUTPUT ;
    USE SIGNAL ;
    PORT
      LAYER M4 ;
        RECT  0 69.264 0.084 69.288 ;
    END
  END o[387]
  PIN o[388]
    DIRECTION OUTPUT ;
    USE SIGNAL ;
    PORT
      LAYER M4 ;
        RECT  0 69.456 0.084 69.48 ;
    END
  END o[388]
  PIN o[389]
    DIRECTION OUTPUT ;
    USE SIGNAL ;
    PORT
      LAYER M4 ;
        RECT  0 69.648 0.084 69.672 ;
    END
  END o[389]
  PIN o[38]
    DIRECTION OUTPUT ;
    USE SIGNAL ;
    PORT
      LAYER M4 ;
        RECT  0 7.776 0.084 7.8 ;
    END
  END o[38]
  PIN o[390]
    DIRECTION OUTPUT ;
    USE SIGNAL ;
    PORT
      LAYER M4 ;
        RECT  0 69.792 0.084 69.816 ;
    END
  END o[390]
  PIN o[391]
    DIRECTION OUTPUT ;
    USE SIGNAL ;
    PORT
      LAYER M4 ;
        RECT  0 69.984 0.084 70.008 ;
    END
  END o[391]
  PIN o[392]
    DIRECTION OUTPUT ;
    USE SIGNAL ;
    PORT
      LAYER M4 ;
        RECT  0 70.176 0.084 70.2 ;
    END
  END o[392]
  PIN o[393]
    DIRECTION OUTPUT ;
    USE SIGNAL ;
    PORT
      LAYER M4 ;
        RECT  0 70.32 0.084 70.344 ;
    END
  END o[393]
  PIN o[394]
    DIRECTION OUTPUT ;
    USE SIGNAL ;
    PORT
      LAYER M4 ;
        RECT  0 70.512 0.084 70.536 ;
    END
  END o[394]
  PIN o[395]
    DIRECTION OUTPUT ;
    USE SIGNAL ;
    PORT
      LAYER M4 ;
        RECT  0 70.704 0.084 70.728 ;
    END
  END o[395]
  PIN o[396]
    DIRECTION OUTPUT ;
    USE SIGNAL ;
    PORT
      LAYER M4 ;
        RECT  0 70.848 0.084 70.872 ;
    END
  END o[396]
  PIN o[397]
    DIRECTION OUTPUT ;
    USE SIGNAL ;
    PORT
      LAYER M4 ;
        RECT  0 71.04 0.084 71.064 ;
    END
  END o[397]
  PIN o[398]
    DIRECTION OUTPUT ;
    USE SIGNAL ;
    PORT
      LAYER M4 ;
        RECT  0 71.232 0.084 71.256 ;
    END
  END o[398]
  PIN o[399]
    DIRECTION OUTPUT ;
    USE SIGNAL ;
    PORT
      LAYER M4 ;
        RECT  0 71.424 0.084 71.448 ;
    END
  END o[399]
  PIN o[39]
    DIRECTION OUTPUT ;
    USE SIGNAL ;
    PORT
      LAYER M4 ;
        RECT  0 7.968 0.084 7.992 ;
    END
  END o[39]
  PIN o[3]
    DIRECTION OUTPUT ;
    USE SIGNAL ;
    PORT
      LAYER M4 ;
        RECT  0 1.584 0.084 1.608 ;
    END
  END o[3]
  PIN o[400]
    DIRECTION OUTPUT ;
    USE SIGNAL ;
    PORT
      LAYER M4 ;
        RECT  0 71.568 0.084 71.592 ;
    END
  END o[400]
  PIN o[401]
    DIRECTION OUTPUT ;
    USE SIGNAL ;
    PORT
      LAYER M4 ;
        RECT  0 71.76 0.084 71.784 ;
    END
  END o[401]
  PIN o[402]
    DIRECTION OUTPUT ;
    USE SIGNAL ;
    PORT
      LAYER M4 ;
        RECT  0 71.952 0.084 71.976 ;
    END
  END o[402]
  PIN o[403]
    DIRECTION OUTPUT ;
    USE SIGNAL ;
    PORT
      LAYER M4 ;
        RECT  0 72.096 0.084 72.12 ;
    END
  END o[403]
  PIN o[404]
    DIRECTION OUTPUT ;
    USE SIGNAL ;
    PORT
      LAYER M4 ;
        RECT  0 72.288 0.084 72.312 ;
    END
  END o[404]
  PIN o[405]
    DIRECTION OUTPUT ;
    USE SIGNAL ;
    PORT
      LAYER M4 ;
        RECT  0 72.48 0.084 72.504 ;
    END
  END o[405]
  PIN o[406]
    DIRECTION OUTPUT ;
    USE SIGNAL ;
    PORT
      LAYER M4 ;
        RECT  0 72.624 0.084 72.648 ;
    END
  END o[406]
  PIN o[407]
    DIRECTION OUTPUT ;
    USE SIGNAL ;
    PORT
      LAYER M4 ;
        RECT  0 72.816 0.084 72.84 ;
    END
  END o[407]
  PIN o[408]
    DIRECTION OUTPUT ;
    USE SIGNAL ;
    PORT
      LAYER M4 ;
        RECT  0 73.008 0.084 73.032 ;
    END
  END o[408]
  PIN o[409]
    DIRECTION OUTPUT ;
    USE SIGNAL ;
    PORT
      LAYER M4 ;
        RECT  0 73.152 0.084 73.176 ;
    END
  END o[409]
  PIN o[40]
    DIRECTION OUTPUT ;
    USE SIGNAL ;
    PORT
      LAYER M4 ;
        RECT  0 8.112 0.084 8.136 ;
    END
  END o[40]
  PIN o[410]
    DIRECTION OUTPUT ;
    USE SIGNAL ;
    PORT
      LAYER M4 ;
        RECT  0 73.344 0.084 73.368 ;
    END
  END o[410]
  PIN o[411]
    DIRECTION OUTPUT ;
    USE SIGNAL ;
    PORT
      LAYER M4 ;
        RECT  0 73.536 0.084 73.56 ;
    END
  END o[411]
  PIN o[412]
    DIRECTION OUTPUT ;
    USE SIGNAL ;
    PORT
      LAYER M4 ;
        RECT  0 73.68 0.084 73.704 ;
    END
  END o[412]
  PIN o[413]
    DIRECTION OUTPUT ;
    USE SIGNAL ;
    PORT
      LAYER M4 ;
        RECT  0 73.872 0.084 73.896 ;
    END
  END o[413]
  PIN o[414]
    DIRECTION OUTPUT ;
    USE SIGNAL ;
    PORT
      LAYER M4 ;
        RECT  0 74.064 0.084 74.088 ;
    END
  END o[414]
  PIN o[415]
    DIRECTION OUTPUT ;
    USE SIGNAL ;
    PORT
      LAYER M4 ;
        RECT  0 74.208 0.084 74.232 ;
    END
  END o[415]
  PIN o[416]
    DIRECTION OUTPUT ;
    USE SIGNAL ;
    PORT
      LAYER M4 ;
        RECT  0 74.4 0.084 74.424 ;
    END
  END o[416]
  PIN o[417]
    DIRECTION OUTPUT ;
    USE SIGNAL ;
    PORT
      LAYER M4 ;
        RECT  0 74.592 0.084 74.616 ;
    END
  END o[417]
  PIN o[418]
    DIRECTION OUTPUT ;
    USE SIGNAL ;
    PORT
      LAYER M4 ;
        RECT  0 74.736 0.084 74.76 ;
    END
  END o[418]
  PIN o[419]
    DIRECTION OUTPUT ;
    USE SIGNAL ;
    PORT
      LAYER M4 ;
        RECT  0 74.928 0.084 74.952 ;
    END
  END o[419]
  PIN o[41]
    DIRECTION OUTPUT ;
    USE SIGNAL ;
    PORT
      LAYER M4 ;
        RECT  0 8.304 0.084 8.328 ;
    END
  END o[41]
  PIN o[420]
    DIRECTION OUTPUT ;
    USE SIGNAL ;
    PORT
      LAYER M4 ;
        RECT  0 75.12 0.084 75.144 ;
    END
  END o[420]
  PIN o[421]
    DIRECTION OUTPUT ;
    USE SIGNAL ;
    PORT
      LAYER M4 ;
        RECT  0 75.264 0.084 75.288 ;
    END
  END o[421]
  PIN o[422]
    DIRECTION OUTPUT ;
    USE SIGNAL ;
    PORT
      LAYER M4 ;
        RECT  0 75.456 0.084 75.48 ;
    END
  END o[422]
  PIN o[423]
    DIRECTION OUTPUT ;
    USE SIGNAL ;
    PORT
      LAYER M4 ;
        RECT  0 75.648 0.084 75.672 ;
    END
  END o[423]
  PIN o[424]
    DIRECTION OUTPUT ;
    USE SIGNAL ;
    PORT
      LAYER M4 ;
        RECT  0 75.792 0.084 75.816 ;
    END
  END o[424]
  PIN o[425]
    DIRECTION OUTPUT ;
    USE SIGNAL ;
    PORT
      LAYER M4 ;
        RECT  0 75.984 0.084 76.008 ;
    END
  END o[425]
  PIN o[426]
    DIRECTION OUTPUT ;
    USE SIGNAL ;
    PORT
      LAYER M4 ;
        RECT  0 76.176 0.084 76.2 ;
    END
  END o[426]
  PIN o[427]
    DIRECTION OUTPUT ;
    USE SIGNAL ;
    PORT
      LAYER M4 ;
        RECT  0 76.32 0.084 76.344 ;
    END
  END o[427]
  PIN o[428]
    DIRECTION OUTPUT ;
    USE SIGNAL ;
    PORT
      LAYER M4 ;
        RECT  0 76.512 0.084 76.536 ;
    END
  END o[428]
  PIN o[429]
    DIRECTION OUTPUT ;
    USE SIGNAL ;
    PORT
      LAYER M4 ;
        RECT  0 76.704 0.084 76.728 ;
    END
  END o[429]
  PIN o[42]
    DIRECTION OUTPUT ;
    USE SIGNAL ;
    PORT
      LAYER M4 ;
        RECT  0 8.496 0.084 8.52 ;
    END
  END o[42]
  PIN o[430]
    DIRECTION OUTPUT ;
    USE SIGNAL ;
    PORT
      LAYER M4 ;
        RECT  0 76.848 0.084 76.872 ;
    END
  END o[430]
  PIN o[431]
    DIRECTION OUTPUT ;
    USE SIGNAL ;
    PORT
      LAYER M4 ;
        RECT  0 77.04 0.084 77.064 ;
    END
  END o[431]
  PIN o[432]
    DIRECTION OUTPUT ;
    USE SIGNAL ;
    PORT
      LAYER M4 ;
        RECT  0 77.232 0.084 77.256 ;
    END
  END o[432]
  PIN o[433]
    DIRECTION OUTPUT ;
    USE SIGNAL ;
    PORT
      LAYER M4 ;
        RECT  0 77.376 0.084 77.4 ;
    END
  END o[433]
  PIN o[434]
    DIRECTION OUTPUT ;
    USE SIGNAL ;
    PORT
      LAYER M4 ;
        RECT  0 77.568 0.084 77.592 ;
    END
  END o[434]
  PIN o[435]
    DIRECTION OUTPUT ;
    USE SIGNAL ;
    PORT
      LAYER M4 ;
        RECT  0 77.76 0.084 77.784 ;
    END
  END o[435]
  PIN o[436]
    DIRECTION OUTPUT ;
    USE SIGNAL ;
    PORT
      LAYER M4 ;
        RECT  0 77.904 0.084 77.928 ;
    END
  END o[436]
  PIN o[437]
    DIRECTION OUTPUT ;
    USE SIGNAL ;
    PORT
      LAYER M4 ;
        RECT  0 78.096 0.084 78.12 ;
    END
  END o[437]
  PIN o[438]
    DIRECTION OUTPUT ;
    USE SIGNAL ;
    PORT
      LAYER M4 ;
        RECT  0 78.288 0.084 78.312 ;
    END
  END o[438]
  PIN o[439]
    DIRECTION OUTPUT ;
    USE SIGNAL ;
    PORT
      LAYER M4 ;
        RECT  0 78.432 0.084 78.456 ;
    END
  END o[439]
  PIN o[43]
    DIRECTION OUTPUT ;
    USE SIGNAL ;
    PORT
      LAYER M4 ;
        RECT  0 8.64 0.084 8.664 ;
    END
  END o[43]
  PIN o[440]
    DIRECTION OUTPUT ;
    USE SIGNAL ;
    PORT
      LAYER M4 ;
        RECT  0 78.624 0.084 78.648 ;
    END
  END o[440]
  PIN o[441]
    DIRECTION OUTPUT ;
    USE SIGNAL ;
    PORT
      LAYER M4 ;
        RECT  0 78.816 0.084 78.84 ;
    END
  END o[441]
  PIN o[442]
    DIRECTION OUTPUT ;
    USE SIGNAL ;
    PORT
      LAYER M4 ;
        RECT  0 78.96 0.084 78.984 ;
    END
  END o[442]
  PIN o[443]
    DIRECTION OUTPUT ;
    USE SIGNAL ;
    PORT
      LAYER M4 ;
        RECT  0 79.152 0.084 79.176 ;
    END
  END o[443]
  PIN o[444]
    DIRECTION OUTPUT ;
    USE SIGNAL ;
    PORT
      LAYER M4 ;
        RECT  0 79.344 0.084 79.368 ;
    END
  END o[444]
  PIN o[445]
    DIRECTION OUTPUT ;
    USE SIGNAL ;
    PORT
      LAYER M4 ;
        RECT  0 79.488 0.084 79.512 ;
    END
  END o[445]
  PIN o[446]
    DIRECTION OUTPUT ;
    USE SIGNAL ;
    PORT
      LAYER M4 ;
        RECT  0 79.68 0.084 79.704 ;
    END
  END o[446]
  PIN o[447]
    DIRECTION OUTPUT ;
    USE SIGNAL ;
    PORT
      LAYER M4 ;
        RECT  0 79.872 0.084 79.896 ;
    END
  END o[447]
  PIN o[448]
    DIRECTION OUTPUT ;
    USE SIGNAL ;
    PORT
      LAYER M4 ;
        RECT  0 80.016 0.084 80.04 ;
    END
  END o[448]
  PIN o[449]
    DIRECTION OUTPUT ;
    USE SIGNAL ;
    PORT
      LAYER M4 ;
        RECT  0 80.208 0.084 80.232 ;
    END
  END o[449]
  PIN o[44]
    DIRECTION OUTPUT ;
    USE SIGNAL ;
    PORT
      LAYER M4 ;
        RECT  0 8.832 0.084 8.856 ;
    END
  END o[44]
  PIN o[450]
    DIRECTION OUTPUT ;
    USE SIGNAL ;
    PORT
      LAYER M4 ;
        RECT  0 80.4 0.084 80.424 ;
    END
  END o[450]
  PIN o[451]
    DIRECTION OUTPUT ;
    USE SIGNAL ;
    PORT
      LAYER M4 ;
        RECT  0 80.544 0.084 80.568 ;
    END
  END o[451]
  PIN o[452]
    DIRECTION OUTPUT ;
    USE SIGNAL ;
    PORT
      LAYER M4 ;
        RECT  0 80.736 0.084 80.76 ;
    END
  END o[452]
  PIN o[453]
    DIRECTION OUTPUT ;
    USE SIGNAL ;
    PORT
      LAYER M4 ;
        RECT  0 80.928 0.084 80.952 ;
    END
  END o[453]
  PIN o[454]
    DIRECTION OUTPUT ;
    USE SIGNAL ;
    PORT
      LAYER M4 ;
        RECT  0 81.072 0.084 81.096 ;
    END
  END o[454]
  PIN o[455]
    DIRECTION OUTPUT ;
    USE SIGNAL ;
    PORT
      LAYER M4 ;
        RECT  0 81.264 0.084 81.288 ;
    END
  END o[455]
  PIN o[456]
    DIRECTION OUTPUT ;
    USE SIGNAL ;
    PORT
      LAYER M4 ;
        RECT  0 81.456 0.084 81.48 ;
    END
  END o[456]
  PIN o[457]
    DIRECTION OUTPUT ;
    USE SIGNAL ;
    PORT
      LAYER M4 ;
        RECT  0 81.6 0.084 81.624 ;
    END
  END o[457]
  PIN o[458]
    DIRECTION OUTPUT ;
    USE SIGNAL ;
    PORT
      LAYER M4 ;
        RECT  0 81.792 0.084 81.816 ;
    END
  END o[458]
  PIN o[459]
    DIRECTION OUTPUT ;
    USE SIGNAL ;
    PORT
      LAYER M4 ;
        RECT  0 81.984 0.084 82.008 ;
    END
  END o[459]
  PIN o[45]
    DIRECTION OUTPUT ;
    USE SIGNAL ;
    PORT
      LAYER M4 ;
        RECT  0 9.024 0.084 9.048 ;
    END
  END o[45]
  PIN o[460]
    DIRECTION OUTPUT ;
    USE SIGNAL ;
    PORT
      LAYER M4 ;
        RECT  0 82.128 0.084 82.152 ;
    END
  END o[460]
  PIN o[461]
    DIRECTION OUTPUT ;
    USE SIGNAL ;
    PORT
      LAYER M4 ;
        RECT  0 82.32 0.084 82.344 ;
    END
  END o[461]
  PIN o[462]
    DIRECTION OUTPUT ;
    USE SIGNAL ;
    PORT
      LAYER M4 ;
        RECT  0 82.512 0.084 82.536 ;
    END
  END o[462]
  PIN o[463]
    DIRECTION OUTPUT ;
    USE SIGNAL ;
    PORT
      LAYER M4 ;
        RECT  0 82.704 0.084 82.728 ;
    END
  END o[463]
  PIN o[464]
    DIRECTION OUTPUT ;
    USE SIGNAL ;
    PORT
      LAYER M4 ;
        RECT  0 82.848 0.084 82.872 ;
    END
  END o[464]
  PIN o[465]
    DIRECTION OUTPUT ;
    USE SIGNAL ;
    PORT
      LAYER M4 ;
        RECT  0 83.04 0.084 83.064 ;
    END
  END o[465]
  PIN o[466]
    DIRECTION OUTPUT ;
    USE SIGNAL ;
    PORT
      LAYER M4 ;
        RECT  0 83.232 0.084 83.256 ;
    END
  END o[466]
  PIN o[467]
    DIRECTION OUTPUT ;
    USE SIGNAL ;
    PORT
      LAYER M4 ;
        RECT  0 83.376 0.084 83.4 ;
    END
  END o[467]
  PIN o[468]
    DIRECTION OUTPUT ;
    USE SIGNAL ;
    PORT
      LAYER M4 ;
        RECT  0 83.568 0.084 83.592 ;
    END
  END o[468]
  PIN o[469]
    DIRECTION OUTPUT ;
    USE SIGNAL ;
    PORT
      LAYER M4 ;
        RECT  0 83.76 0.084 83.784 ;
    END
  END o[469]
  PIN o[46]
    DIRECTION OUTPUT ;
    USE SIGNAL ;
    PORT
      LAYER M4 ;
        RECT  0 9.168 0.084 9.192 ;
    END
  END o[46]
  PIN o[470]
    DIRECTION OUTPUT ;
    USE SIGNAL ;
    PORT
      LAYER M4 ;
        RECT  0 83.904 0.084 83.928 ;
    END
  END o[470]
  PIN o[471]
    DIRECTION OUTPUT ;
    USE SIGNAL ;
    PORT
      LAYER M4 ;
        RECT  0 84.096 0.084 84.12 ;
    END
  END o[471]
  PIN o[472]
    DIRECTION OUTPUT ;
    USE SIGNAL ;
    PORT
      LAYER M4 ;
        RECT  0 84.288 0.084 84.312 ;
    END
  END o[472]
  PIN o[473]
    DIRECTION OUTPUT ;
    USE SIGNAL ;
    PORT
      LAYER M4 ;
        RECT  0 84.432 0.084 84.456 ;
    END
  END o[473]
  PIN o[474]
    DIRECTION OUTPUT ;
    USE SIGNAL ;
    PORT
      LAYER M4 ;
        RECT  0 84.624 0.084 84.648 ;
    END
  END o[474]
  PIN o[475]
    DIRECTION OUTPUT ;
    USE SIGNAL ;
    PORT
      LAYER M4 ;
        RECT  0 84.816 0.084 84.84 ;
    END
  END o[475]
  PIN o[476]
    DIRECTION OUTPUT ;
    USE SIGNAL ;
    PORT
      LAYER M4 ;
        RECT  0 84.96 0.084 84.984 ;
    END
  END o[476]
  PIN o[477]
    DIRECTION OUTPUT ;
    USE SIGNAL ;
    PORT
      LAYER M4 ;
        RECT  0 85.152 0.084 85.176 ;
    END
  END o[477]
  PIN o[478]
    DIRECTION OUTPUT ;
    USE SIGNAL ;
    PORT
      LAYER M4 ;
        RECT  0 85.344 0.084 85.368 ;
    END
  END o[478]
  PIN o[479]
    DIRECTION OUTPUT ;
    USE SIGNAL ;
    PORT
      LAYER M4 ;
        RECT  0 85.488 0.084 85.512 ;
    END
  END o[479]
  PIN o[47]
    DIRECTION OUTPUT ;
    USE SIGNAL ;
    PORT
      LAYER M4 ;
        RECT  0 9.36 0.084 9.384 ;
    END
  END o[47]
  PIN o[480]
    DIRECTION OUTPUT ;
    USE SIGNAL ;
    PORT
      LAYER M4 ;
        RECT  0 85.68 0.084 85.704 ;
    END
  END o[480]
  PIN o[481]
    DIRECTION OUTPUT ;
    USE SIGNAL ;
    PORT
      LAYER M4 ;
        RECT  0 85.872 0.084 85.896 ;
    END
  END o[481]
  PIN o[482]
    DIRECTION OUTPUT ;
    USE SIGNAL ;
    PORT
      LAYER M4 ;
        RECT  0 86.016 0.084 86.04 ;
    END
  END o[482]
  PIN o[483]
    DIRECTION OUTPUT ;
    USE SIGNAL ;
    PORT
      LAYER M4 ;
        RECT  0 86.208 0.084 86.232 ;
    END
  END o[483]
  PIN o[484]
    DIRECTION OUTPUT ;
    USE SIGNAL ;
    PORT
      LAYER M4 ;
        RECT  0 86.4 0.084 86.424 ;
    END
  END o[484]
  PIN o[485]
    DIRECTION OUTPUT ;
    USE SIGNAL ;
    PORT
      LAYER M4 ;
        RECT  0 86.544 0.084 86.568 ;
    END
  END o[485]
  PIN o[486]
    DIRECTION OUTPUT ;
    USE SIGNAL ;
    PORT
      LAYER M4 ;
        RECT  0 86.736 0.084 86.76 ;
    END
  END o[486]
  PIN o[487]
    DIRECTION OUTPUT ;
    USE SIGNAL ;
    PORT
      LAYER M4 ;
        RECT  0 86.928 0.084 86.952 ;
    END
  END o[487]
  PIN o[488]
    DIRECTION OUTPUT ;
    USE SIGNAL ;
    PORT
      LAYER M4 ;
        RECT  0 87.072 0.084 87.096 ;
    END
  END o[488]
  PIN o[489]
    DIRECTION OUTPUT ;
    USE SIGNAL ;
    PORT
      LAYER M4 ;
        RECT  0 87.264 0.084 87.288 ;
    END
  END o[489]
  PIN o[48]
    DIRECTION OUTPUT ;
    USE SIGNAL ;
    PORT
      LAYER M4 ;
        RECT  0 9.552 0.084 9.576 ;
    END
  END o[48]
  PIN o[490]
    DIRECTION OUTPUT ;
    USE SIGNAL ;
    PORT
      LAYER M4 ;
        RECT  0 87.456 0.084 87.48 ;
    END
  END o[490]
  PIN o[491]
    DIRECTION OUTPUT ;
    USE SIGNAL ;
    PORT
      LAYER M4 ;
        RECT  0 87.6 0.084 87.624 ;
    END
  END o[491]
  PIN o[492]
    DIRECTION OUTPUT ;
    USE SIGNAL ;
    PORT
      LAYER M4 ;
        RECT  0 87.792 0.084 87.816 ;
    END
  END o[492]
  PIN o[493]
    DIRECTION OUTPUT ;
    USE SIGNAL ;
    PORT
      LAYER M4 ;
        RECT  0 87.984 0.084 88.008 ;
    END
  END o[493]
  PIN o[494]
    DIRECTION OUTPUT ;
    USE SIGNAL ;
    PORT
      LAYER M4 ;
        RECT  0 88.128 0.084 88.152 ;
    END
  END o[494]
  PIN o[495]
    DIRECTION OUTPUT ;
    USE SIGNAL ;
    PORT
      LAYER M4 ;
        RECT  0 88.32 0.084 88.344 ;
    END
  END o[495]
  PIN o[496]
    DIRECTION OUTPUT ;
    USE SIGNAL ;
    PORT
      LAYER M4 ;
        RECT  0 88.512 0.084 88.536 ;
    END
  END o[496]
  PIN o[497]
    DIRECTION OUTPUT ;
    USE SIGNAL ;
    PORT
      LAYER M4 ;
        RECT  0 88.656 0.084 88.68 ;
    END
  END o[497]
  PIN o[498]
    DIRECTION OUTPUT ;
    USE SIGNAL ;
    PORT
      LAYER M4 ;
        RECT  0 88.848 0.084 88.872 ;
    END
  END o[498]
  PIN o[499]
    DIRECTION OUTPUT ;
    USE SIGNAL ;
    PORT
      LAYER M4 ;
        RECT  0 89.04 0.084 89.064 ;
    END
  END o[499]
  PIN o[49]
    DIRECTION OUTPUT ;
    USE SIGNAL ;
    PORT
      LAYER M4 ;
        RECT  0 9.696 0.084 9.72 ;
    END
  END o[49]
  PIN o[4]
    DIRECTION OUTPUT ;
    USE SIGNAL ;
    PORT
      LAYER M4 ;
        RECT  0 1.776 0.084 1.8 ;
    END
  END o[4]
  PIN o[500]
    DIRECTION OUTPUT ;
    USE SIGNAL ;
    PORT
      LAYER M4 ;
        RECT  0 89.184 0.084 89.208 ;
    END
  END o[500]
  PIN o[501]
    DIRECTION OUTPUT ;
    USE SIGNAL ;
    PORT
      LAYER M4 ;
        RECT  0 89.376 0.084 89.4 ;
    END
  END o[501]
  PIN o[502]
    DIRECTION OUTPUT ;
    USE SIGNAL ;
    PORT
      LAYER M4 ;
        RECT  0 89.568 0.084 89.592 ;
    END
  END o[502]
  PIN o[503]
    DIRECTION OUTPUT ;
    USE SIGNAL ;
    PORT
      LAYER M4 ;
        RECT  0 89.712 0.084 89.736 ;
    END
  END o[503]
  PIN o[504]
    DIRECTION OUTPUT ;
    USE SIGNAL ;
    PORT
      LAYER M4 ;
        RECT  0 89.904 0.084 89.928 ;
    END
  END o[504]
  PIN o[505]
    DIRECTION OUTPUT ;
    USE SIGNAL ;
    PORT
      LAYER M4 ;
        RECT  0 90.096 0.084 90.12 ;
    END
  END o[505]
  PIN o[506]
    DIRECTION OUTPUT ;
    USE SIGNAL ;
    PORT
      LAYER M4 ;
        RECT  0 90.24 0.084 90.264 ;
    END
  END o[506]
  PIN o[507]
    DIRECTION OUTPUT ;
    USE SIGNAL ;
    PORT
      LAYER M4 ;
        RECT  0 90.432 0.084 90.456 ;
    END
  END o[507]
  PIN o[508]
    DIRECTION OUTPUT ;
    USE SIGNAL ;
    PORT
      LAYER M4 ;
        RECT  0 90.624 0.084 90.648 ;
    END
  END o[508]
  PIN o[509]
    DIRECTION OUTPUT ;
    USE SIGNAL ;
    PORT
      LAYER M4 ;
        RECT  0 90.768 0.084 90.792 ;
    END
  END o[509]
  PIN o[50]
    DIRECTION OUTPUT ;
    USE SIGNAL ;
    PORT
      LAYER M4 ;
        RECT  0 9.888 0.084 9.912 ;
    END
  END o[50]
  PIN o[510]
    DIRECTION OUTPUT ;
    USE SIGNAL ;
    PORT
      LAYER M4 ;
        RECT  0 90.96 0.084 90.984 ;
    END
  END o[510]
  PIN o[511]
    DIRECTION OUTPUT ;
    USE SIGNAL ;
    PORT
      LAYER M4 ;
        RECT  0 91.152 0.084 91.176 ;
    END
  END o[511]
  PIN o[51]
    DIRECTION OUTPUT ;
    USE SIGNAL ;
    PORT
      LAYER M4 ;
        RECT  0 10.08 0.084 10.104 ;
    END
  END o[51]
  PIN o[52]
    DIRECTION OUTPUT ;
    USE SIGNAL ;
    PORT
      LAYER M4 ;
        RECT  0 10.224 0.084 10.248 ;
    END
  END o[52]
  PIN o[53]
    DIRECTION OUTPUT ;
    USE SIGNAL ;
    PORT
      LAYER M4 ;
        RECT  0 10.416 0.084 10.44 ;
    END
  END o[53]
  PIN o[54]
    DIRECTION OUTPUT ;
    USE SIGNAL ;
    PORT
      LAYER M4 ;
        RECT  0 10.608 0.084 10.632 ;
    END
  END o[54]
  PIN o[55]
    DIRECTION OUTPUT ;
    USE SIGNAL ;
    PORT
      LAYER M4 ;
        RECT  0 10.752 0.084 10.776 ;
    END
  END o[55]
  PIN o[56]
    DIRECTION OUTPUT ;
    USE SIGNAL ;
    PORT
      LAYER M4 ;
        RECT  0 10.944 0.084 10.968 ;
    END
  END o[56]
  PIN o[57]
    DIRECTION OUTPUT ;
    USE SIGNAL ;
    PORT
      LAYER M4 ;
        RECT  0 11.136 0.084 11.16 ;
    END
  END o[57]
  PIN o[58]
    DIRECTION OUTPUT ;
    USE SIGNAL ;
    PORT
      LAYER M4 ;
        RECT  0 11.28 0.084 11.304 ;
    END
  END o[58]
  PIN o[59]
    DIRECTION OUTPUT ;
    USE SIGNAL ;
    PORT
      LAYER M4 ;
        RECT  0 11.472 0.084 11.496 ;
    END
  END o[59]
  PIN o[5]
    DIRECTION OUTPUT ;
    USE SIGNAL ;
    PORT
      LAYER M4 ;
        RECT  0 1.968 0.084 1.992 ;
    END
  END o[5]
  PIN o[60]
    DIRECTION OUTPUT ;
    USE SIGNAL ;
    PORT
      LAYER M4 ;
        RECT  0 11.664 0.084 11.688 ;
    END
  END o[60]
  PIN o[61]
    DIRECTION OUTPUT ;
    USE SIGNAL ;
    PORT
      LAYER M4 ;
        RECT  0 11.808 0.084 11.832 ;
    END
  END o[61]
  PIN o[62]
    DIRECTION OUTPUT ;
    USE SIGNAL ;
    PORT
      LAYER M4 ;
        RECT  0 12 0.084 12.024 ;
    END
  END o[62]
  PIN o[63]
    DIRECTION OUTPUT ;
    USE SIGNAL ;
    PORT
      LAYER M4 ;
        RECT  0 12.192 0.084 12.216 ;
    END
  END o[63]
  PIN o[64]
    DIRECTION OUTPUT ;
    USE SIGNAL ;
    PORT
      LAYER M4 ;
        RECT  0 12.336 0.084 12.36 ;
    END
  END o[64]
  PIN o[65]
    DIRECTION OUTPUT ;
    USE SIGNAL ;
    PORT
      LAYER M4 ;
        RECT  0 12.528 0.084 12.552 ;
    END
  END o[65]
  PIN o[66]
    DIRECTION OUTPUT ;
    USE SIGNAL ;
    PORT
      LAYER M4 ;
        RECT  0 12.72 0.084 12.744 ;
    END
  END o[66]
  PIN o[67]
    DIRECTION OUTPUT ;
    USE SIGNAL ;
    PORT
      LAYER M4 ;
        RECT  0 12.864 0.084 12.888 ;
    END
  END o[67]
  PIN o[68]
    DIRECTION OUTPUT ;
    USE SIGNAL ;
    PORT
      LAYER M4 ;
        RECT  0 13.056 0.084 13.08 ;
    END
  END o[68]
  PIN o[69]
    DIRECTION OUTPUT ;
    USE SIGNAL ;
    PORT
      LAYER M4 ;
        RECT  0 13.248 0.084 13.272 ;
    END
  END o[69]
  PIN o[6]
    DIRECTION OUTPUT ;
    USE SIGNAL ;
    PORT
      LAYER M4 ;
        RECT  0 2.112 0.084 2.136 ;
    END
  END o[6]
  PIN o[70]
    DIRECTION OUTPUT ;
    USE SIGNAL ;
    PORT
      LAYER M4 ;
        RECT  0 13.392 0.084 13.416 ;
    END
  END o[70]
  PIN o[71]
    DIRECTION OUTPUT ;
    USE SIGNAL ;
    PORT
      LAYER M4 ;
        RECT  0 13.584 0.084 13.608 ;
    END
  END o[71]
  PIN o[72]
    DIRECTION OUTPUT ;
    USE SIGNAL ;
    PORT
      LAYER M4 ;
        RECT  0 13.776 0.084 13.8 ;
    END
  END o[72]
  PIN o[73]
    DIRECTION OUTPUT ;
    USE SIGNAL ;
    PORT
      LAYER M4 ;
        RECT  0 13.92 0.084 13.944 ;
    END
  END o[73]
  PIN o[74]
    DIRECTION OUTPUT ;
    USE SIGNAL ;
    PORT
      LAYER M4 ;
        RECT  0 14.112 0.084 14.136 ;
    END
  END o[74]
  PIN o[75]
    DIRECTION OUTPUT ;
    USE SIGNAL ;
    PORT
      LAYER M4 ;
        RECT  0 14.304 0.084 14.328 ;
    END
  END o[75]
  PIN o[76]
    DIRECTION OUTPUT ;
    USE SIGNAL ;
    PORT
      LAYER M4 ;
        RECT  0 14.448 0.084 14.472 ;
    END
  END o[76]
  PIN o[77]
    DIRECTION OUTPUT ;
    USE SIGNAL ;
    PORT
      LAYER M4 ;
        RECT  0 14.64 0.084 14.664 ;
    END
  END o[77]
  PIN o[78]
    DIRECTION OUTPUT ;
    USE SIGNAL ;
    PORT
      LAYER M4 ;
        RECT  0 14.832 0.084 14.856 ;
    END
  END o[78]
  PIN o[79]
    DIRECTION OUTPUT ;
    USE SIGNAL ;
    PORT
      LAYER M4 ;
        RECT  0 15.024 0.084 15.048 ;
    END
  END o[79]
  PIN o[7]
    DIRECTION OUTPUT ;
    USE SIGNAL ;
    PORT
      LAYER M4 ;
        RECT  0 2.304 0.084 2.328 ;
    END
  END o[7]
  PIN o[80]
    DIRECTION OUTPUT ;
    USE SIGNAL ;
    PORT
      LAYER M4 ;
        RECT  0 15.168 0.084 15.192 ;
    END
  END o[80]
  PIN o[81]
    DIRECTION OUTPUT ;
    USE SIGNAL ;
    PORT
      LAYER M4 ;
        RECT  0 15.36 0.084 15.384 ;
    END
  END o[81]
  PIN o[82]
    DIRECTION OUTPUT ;
    USE SIGNAL ;
    PORT
      LAYER M4 ;
        RECT  0 15.552 0.084 15.576 ;
    END
  END o[82]
  PIN o[83]
    DIRECTION OUTPUT ;
    USE SIGNAL ;
    PORT
      LAYER M4 ;
        RECT  0 15.696 0.084 15.72 ;
    END
  END o[83]
  PIN o[84]
    DIRECTION OUTPUT ;
    USE SIGNAL ;
    PORT
      LAYER M4 ;
        RECT  0 15.888 0.084 15.912 ;
    END
  END o[84]
  PIN o[85]
    DIRECTION OUTPUT ;
    USE SIGNAL ;
    PORT
      LAYER M4 ;
        RECT  0 16.08 0.084 16.104 ;
    END
  END o[85]
  PIN o[86]
    DIRECTION OUTPUT ;
    USE SIGNAL ;
    PORT
      LAYER M4 ;
        RECT  0 16.224 0.084 16.248 ;
    END
  END o[86]
  PIN o[87]
    DIRECTION OUTPUT ;
    USE SIGNAL ;
    PORT
      LAYER M4 ;
        RECT  0 16.416 0.084 16.44 ;
    END
  END o[87]
  PIN o[88]
    DIRECTION OUTPUT ;
    USE SIGNAL ;
    PORT
      LAYER M4 ;
        RECT  0 16.608 0.084 16.632 ;
    END
  END o[88]
  PIN o[89]
    DIRECTION OUTPUT ;
    USE SIGNAL ;
    PORT
      LAYER M4 ;
        RECT  0 16.752 0.084 16.776 ;
    END
  END o[89]
  PIN o[8]
    DIRECTION OUTPUT ;
    USE SIGNAL ;
    PORT
      LAYER M4 ;
        RECT  0 2.496 0.084 2.52 ;
    END
  END o[8]
  PIN o[90]
    DIRECTION OUTPUT ;
    USE SIGNAL ;
    PORT
      LAYER M4 ;
        RECT  0 16.944 0.084 16.968 ;
    END
  END o[90]
  PIN o[91]
    DIRECTION OUTPUT ;
    USE SIGNAL ;
    PORT
      LAYER M4 ;
        RECT  0 17.136 0.084 17.16 ;
    END
  END o[91]
  PIN o[92]
    DIRECTION OUTPUT ;
    USE SIGNAL ;
    PORT
      LAYER M4 ;
        RECT  0 17.28 0.084 17.304 ;
    END
  END o[92]
  PIN o[93]
    DIRECTION OUTPUT ;
    USE SIGNAL ;
    PORT
      LAYER M4 ;
        RECT  0 17.472 0.084 17.496 ;
    END
  END o[93]
  PIN o[94]
    DIRECTION OUTPUT ;
    USE SIGNAL ;
    PORT
      LAYER M4 ;
        RECT  0 17.664 0.084 17.688 ;
    END
  END o[94]
  PIN o[95]
    DIRECTION OUTPUT ;
    USE SIGNAL ;
    PORT
      LAYER M4 ;
        RECT  0 17.808 0.084 17.832 ;
    END
  END o[95]
  PIN o[96]
    DIRECTION OUTPUT ;
    USE SIGNAL ;
    PORT
      LAYER M4 ;
        RECT  0 18 0.084 18.024 ;
    END
  END o[96]
  PIN o[97]
    DIRECTION OUTPUT ;
    USE SIGNAL ;
    PORT
      LAYER M4 ;
        RECT  0 18.192 0.084 18.216 ;
    END
  END o[97]
  PIN o[98]
    DIRECTION OUTPUT ;
    USE SIGNAL ;
    PORT
      LAYER M4 ;
        RECT  0 18.336 0.084 18.36 ;
    END
  END o[98]
  PIN o[99]
    DIRECTION OUTPUT ;
    USE SIGNAL ;
    PORT
      LAYER M4 ;
        RECT  0 18.528 0.084 18.552 ;
    END
  END o[99]
  PIN o[9]
    DIRECTION OUTPUT ;
    USE SIGNAL ;
    PORT
      LAYER M4 ;
        RECT  0 2.64 0.084 2.664 ;
    END
  END o[9]
  PIN rs
    DIRECTION INPUT ;
    USE SIGNAL ;
    PORT
      LAYER M3 ;
        RECT  16.884 95.002 16.902 95.04 ;
    END
    PORT
      LAYER M3 ;
        RECT  16.884 92.741 16.902 95.021 ;
    END
  END rs
  PIN VDD
    DIRECTION INOUT ;
    USE POWER ;
    PORT
      LAYER M5 ;
        RECT  34.992 2.151 35.112 92.889 ;
        RECT  32.292 2.151 32.412 92.889 ;
        RECT  29.592 2.151 29.712 92.889 ;
        RECT  26.892 2.151 27.012 92.889 ;
        RECT  24.192 2.151 24.312 92.889 ;
        RECT  21.492 2.151 21.612 92.889 ;
        RECT  18.792 2.151 18.912 92.889 ;
        RECT  16.092 2.151 16.212 92.889 ;
        RECT  13.392 2.151 13.512 92.889 ;
        RECT  10.692 2.151 10.812 92.889 ;
        RECT  7.992 2.151 8.112 92.889 ;
        RECT  5.292 2.151 5.412 92.889 ;
        RECT  2.592 2.151 2.712 92.889 ;
    END
  END VDD
  PIN VSS
    DIRECTION INOUT ;
    USE GROUND ;
    PORT
      LAYER M5 ;
        RECT  34.8 2.137 34.92 92.903 ;
        RECT  32.1 2.137 32.22 92.903 ;
        RECT  29.4 2.137 29.52 92.903 ;
        RECT  26.7 2.137 26.82 92.903 ;
        RECT  24 2.137 24.12 92.903 ;
        RECT  21.3 2.137 21.42 92.903 ;
        RECT  18.6 2.137 18.72 92.903 ;
        RECT  15.9 2.137 16.02 92.903 ;
        RECT  13.2 2.137 13.32 92.903 ;
        RECT  10.5 2.137 10.62 92.903 ;
        RECT  7.8 2.137 7.92 92.903 ;
        RECT  5.1 2.137 5.22 92.903 ;
        RECT  2.4 2.137 2.52 92.903 ;
    END
  END VSS
  # OT_OBS_CLOSED layer=M5 d_um=1.536 added=483
  OBS
    LAYER RVTN ;
     RECT  2.16 2.16 36.72 2.295 ;
     RECT  2.16 2.565 36.72 2.835 ;
     RECT  2.16 3.105 36.72 3.375 ;
     RECT  2.16 3.645 36.72 3.915 ;
     RECT  2.16 4.185 36.72 4.455 ;
     RECT  2.16 4.725 36.72 4.995 ;
     RECT  2.16 5.265 36.72 5.535 ;
     RECT  2.16 5.805 36.72 6.075 ;
     RECT  2.16 6.345 36.72 6.615 ;
     RECT  2.16 6.885 36.72 7.155 ;
     RECT  2.16 7.425 36.72 7.695 ;
     RECT  2.16 7.965 36.72 8.235 ;
     RECT  2.16 8.505 36.72 8.775 ;
     RECT  2.16 9.045 36.72 9.315 ;
     RECT  2.16 9.585 36.72 9.855 ;
     RECT  2.16 10.125 36.72 10.395 ;
     RECT  2.16 10.665 36.72 10.935 ;
     RECT  2.16 11.205 36.72 11.475 ;
     RECT  2.16 11.745 36.72 12.015 ;
     RECT  2.16 12.285 36.72 12.555 ;
     RECT  2.16 12.825 36.72 13.095 ;
     RECT  2.16 13.365 36.72 13.635 ;
     RECT  2.16 13.905 36.72 14.175 ;
     RECT  2.16 14.445 36.72 14.715 ;
     RECT  2.16 14.985 36.72 15.255 ;
     RECT  2.16 15.525 36.72 15.795 ;
     RECT  2.16 16.065 36.72 16.335 ;
     RECT  2.16 16.605 36.72 16.875 ;
     RECT  2.16 17.145 36.72 17.415 ;
     RECT  2.16 17.685 36.72 17.955 ;
     RECT  2.16 18.225 36.72 18.495 ;
     RECT  2.16 18.765 36.72 19.035 ;
     RECT  2.16 19.305 36.72 19.575 ;
     RECT  2.16 19.845 36.72 20.115 ;
     RECT  2.16 20.385 36.72 20.655 ;
     RECT  2.16 20.925 36.72 21.195 ;
     RECT  2.16 21.465 36.72 21.735 ;
     RECT  2.16 22.005 36.72 22.275 ;
     RECT  2.16 22.545 36.72 22.815 ;
     RECT  2.16 23.085 36.72 23.355 ;
     RECT  2.16 23.625 36.72 23.895 ;
     RECT  2.16 24.165 36.72 24.435 ;
     RECT  2.16 24.705 36.72 24.975 ;
     RECT  2.16 25.245 36.72 25.515 ;
     RECT  2.16 25.785 36.72 26.055 ;
     RECT  2.16 26.325 36.72 26.595 ;
     RECT  2.16 26.865 36.72 27.135 ;
     RECT  2.16 27.405 36.72 27.675 ;
     RECT  2.16 27.945 36.72 28.215 ;
     RECT  2.16 28.485 36.72 28.755 ;
     RECT  2.16 29.025 36.72 29.295 ;
     RECT  2.16 29.565 36.72 29.835 ;
     RECT  2.16 30.105 36.72 30.375 ;
     RECT  2.16 30.645 36.72 30.915 ;
     RECT  2.16 31.185 36.72 31.455 ;
     RECT  2.16 31.725 36.72 31.995 ;
     RECT  2.16 32.265 36.72 32.535 ;
     RECT  2.16 32.805 36.72 33.075 ;
     RECT  2.16 33.345 36.72 33.615 ;
     RECT  2.16 33.885 36.72 34.155 ;
     RECT  2.16 34.425 36.72 34.695 ;
     RECT  2.16 34.965 36.72 35.235 ;
     RECT  2.16 35.505 36.72 35.775 ;
     RECT  2.16 36.045 36.72 36.315 ;
     RECT  2.16 36.585 36.72 36.855 ;
     RECT  2.16 37.125 36.72 37.395 ;
     RECT  2.16 37.665 36.72 37.935 ;
     RECT  2.16 38.205 36.72 38.475 ;
     RECT  2.16 38.745 36.72 39.015 ;
     RECT  2.16 39.285 36.72 39.555 ;
     RECT  2.16 39.825 36.72 40.095 ;
     RECT  2.16 40.365 36.72 40.635 ;
     RECT  2.16 40.905 36.72 41.175 ;
     RECT  2.16 41.445 36.72 41.715 ;
     RECT  2.16 41.985 36.72 42.255 ;
     RECT  2.16 42.525 36.72 42.795 ;
     RECT  2.16 43.065 36.72 43.335 ;
     RECT  2.16 43.605 36.72 43.875 ;
     RECT  2.16 44.145 36.72 44.415 ;
     RECT  2.16 44.685 36.72 44.955 ;
     RECT  2.16 45.225 36.72 45.495 ;
     RECT  2.16 45.765 36.72 46.035 ;
     RECT  2.16 46.305 36.72 46.575 ;
     RECT  2.16 46.845 36.72 47.115 ;
     RECT  2.16 47.385 36.72 47.655 ;
     RECT  2.16 47.925 36.72 48.195 ;
     RECT  2.16 48.465 36.72 48.735 ;
     RECT  2.16 49.005 36.72 49.275 ;
     RECT  2.16 49.545 36.72 49.815 ;
     RECT  2.16 50.085 36.72 50.355 ;
     RECT  2.16 50.625 36.72 50.895 ;
     RECT  2.16 51.165 36.72 51.435 ;
     RECT  2.16 51.705 36.72 51.975 ;
     RECT  2.16 52.245 36.72 52.515 ;
     RECT  2.16 52.785 36.72 53.055 ;
     RECT  2.16 53.325 36.72 53.595 ;
     RECT  2.16 53.865 36.72 54.135 ;
     RECT  2.16 54.405 36.72 54.675 ;
     RECT  2.16 54.945 36.72 55.215 ;
     RECT  2.16 55.485 36.72 55.755 ;
     RECT  2.16 56.025 36.72 56.295 ;
     RECT  2.16 56.565 36.72 56.835 ;
     RECT  2.16 57.105 36.72 57.375 ;
     RECT  2.16 57.645 36.72 57.915 ;
     RECT  2.16 58.185 36.72 58.455 ;
     RECT  2.16 58.725 36.72 58.995 ;
     RECT  2.16 59.265 36.72 59.535 ;
     RECT  2.16 59.805 36.72 60.075 ;
     RECT  2.16 60.345 36.72 60.615 ;
     RECT  2.16 60.885 36.72 61.155 ;
     RECT  2.16 61.425 36.72 61.695 ;
     RECT  2.16 61.965 36.72 62.235 ;
     RECT  2.16 62.505 36.72 62.775 ;
     RECT  2.16 63.045 36.72 63.315 ;
     RECT  2.16 63.585 36.72 63.855 ;
     RECT  2.16 64.125 36.72 64.395 ;
     RECT  2.16 64.665 36.72 64.935 ;
     RECT  2.16 65.205 36.72 65.475 ;
     RECT  2.16 65.745 36.72 66.015 ;
     RECT  2.16 66.285 36.72 66.555 ;
     RECT  2.16 66.825 36.72 67.095 ;
     RECT  2.16 67.365 36.72 67.635 ;
     RECT  2.16 67.905 36.72 68.175 ;
     RECT  2.16 68.445 36.72 68.715 ;
     RECT  2.16 68.985 36.72 69.255 ;
     RECT  2.16 69.525 36.72 69.795 ;
     RECT  2.16 70.065 36.72 70.335 ;
     RECT  2.16 70.605 36.72 70.875 ;
     RECT  2.16 71.145 36.72 71.415 ;
     RECT  2.16 71.685 36.72 71.955 ;
     RECT  2.16 72.225 36.72 72.495 ;
     RECT  2.16 72.765 36.72 73.035 ;
     RECT  2.16 73.305 36.72 73.575 ;
     RECT  2.16 73.845 36.72 74.115 ;
     RECT  2.16 74.385 36.72 74.655 ;
     RECT  2.16 74.925 36.72 75.195 ;
     RECT  2.16 75.465 36.72 75.735 ;
     RECT  2.16 76.005 36.72 76.275 ;
     RECT  2.16 76.545 36.72 76.815 ;
     RECT  2.16 77.085 36.72 77.355 ;
     RECT  2.16 77.625 36.72 77.895 ;
     RECT  2.16 78.165 36.72 78.435 ;
     RECT  2.16 78.705 36.72 78.975 ;
     RECT  2.16 79.245 36.72 79.515 ;
     RECT  2.16 79.785 36.72 80.055 ;
     RECT  2.16 80.325 36.72 80.595 ;
     RECT  2.16 80.865 36.72 81.135 ;
     RECT  2.16 81.405 36.72 81.675 ;
     RECT  2.16 81.945 36.72 82.215 ;
     RECT  2.16 82.485 36.72 82.755 ;
     RECT  2.16 83.025 36.72 83.295 ;
     RECT  2.16 83.565 36.72 83.835 ;
     RECT  2.16 84.105 36.72 84.375 ;
     RECT  2.16 84.645 36.72 84.915 ;
     RECT  2.16 85.185 36.72 85.455 ;
     RECT  2.16 85.725 36.72 85.995 ;
     RECT  2.16 86.265 36.72 86.535 ;
     RECT  2.16 86.805 36.72 87.075 ;
     RECT  2.16 87.345 36.72 87.615 ;
     RECT  2.16 87.885 36.72 88.155 ;
     RECT  2.16 88.425 36.72 88.695 ;
     RECT  2.16 88.965 36.72 89.235 ;
     RECT  2.16 89.505 36.72 89.775 ;
     RECT  2.16 90.045 36.72 90.315 ;
     RECT  2.16 90.585 36.72 90.855 ;
     RECT  2.16 91.125 36.72 91.395 ;
     RECT  2.16 91.665 36.72 91.935 ;
     RECT  2.16 92.205 36.72 92.475 ;
     RECT  2.16 92.745 36.72 92.88 ;
    LAYER RVTP ;
     RECT  2.16 2.295 36.72 2.565 ;
     RECT  2.16 2.835 36.72 3.105 ;
     RECT  2.16 3.375 36.72 3.645 ;
     RECT  2.16 3.915 36.72 4.185 ;
     RECT  2.16 4.455 36.72 4.725 ;
     RECT  2.16 4.995 36.72 5.265 ;
     RECT  2.16 5.535 36.72 5.805 ;
     RECT  2.16 6.075 36.72 6.345 ;
     RECT  2.16 6.615 36.72 6.885 ;
     RECT  2.16 7.155 36.72 7.425 ;
     RECT  2.16 7.695 36.72 7.965 ;
     RECT  2.16 8.235 36.72 8.505 ;
     RECT  2.16 8.775 36.72 9.045 ;
     RECT  2.16 9.315 36.72 9.585 ;
     RECT  2.16 9.855 36.72 10.125 ;
     RECT  2.16 10.395 36.72 10.665 ;
     RECT  2.16 10.935 36.72 11.205 ;
     RECT  2.16 11.475 36.72 11.745 ;
     RECT  2.16 12.015 36.72 12.285 ;
     RECT  2.16 12.555 36.72 12.825 ;
     RECT  2.16 13.095 36.72 13.365 ;
     RECT  2.16 13.635 36.72 13.905 ;
     RECT  2.16 14.175 36.72 14.445 ;
     RECT  2.16 14.715 36.72 14.985 ;
     RECT  2.16 15.255 36.72 15.525 ;
     RECT  2.16 15.795 36.72 16.065 ;
     RECT  2.16 16.335 36.72 16.605 ;
     RECT  2.16 16.875 36.72 17.145 ;
     RECT  2.16 17.415 36.72 17.685 ;
     RECT  2.16 17.955 36.72 18.225 ;
     RECT  2.16 18.495 36.72 18.765 ;
     RECT  2.16 19.035 36.72 19.305 ;
     RECT  2.16 19.575 36.72 19.845 ;
     RECT  2.16 20.115 36.72 20.385 ;
     RECT  2.16 20.655 36.72 20.925 ;
     RECT  2.16 21.195 36.72 21.465 ;
     RECT  2.16 21.735 36.72 22.005 ;
     RECT  2.16 22.275 36.72 22.545 ;
     RECT  2.16 22.815 36.72 23.085 ;
     RECT  2.16 23.355 36.72 23.625 ;
     RECT  2.16 23.895 36.72 24.165 ;
     RECT  2.16 24.435 36.72 24.705 ;
     RECT  2.16 24.975 36.72 25.245 ;
     RECT  2.16 25.515 36.72 25.785 ;
     RECT  2.16 26.055 36.72 26.325 ;
     RECT  2.16 26.595 36.72 26.865 ;
     RECT  2.16 27.135 36.72 27.405 ;
     RECT  2.16 27.675 36.72 27.945 ;
     RECT  2.16 28.215 36.72 28.485 ;
     RECT  2.16 28.755 36.72 29.025 ;
     RECT  2.16 29.295 36.72 29.565 ;
     RECT  2.16 29.835 36.72 30.105 ;
     RECT  2.16 30.375 36.72 30.645 ;
     RECT  2.16 30.915 36.72 31.185 ;
     RECT  2.16 31.455 36.72 31.725 ;
     RECT  2.16 31.995 36.72 32.265 ;
     RECT  2.16 32.535 36.72 32.805 ;
     RECT  2.16 33.075 36.72 33.345 ;
     RECT  2.16 33.615 36.72 33.885 ;
     RECT  2.16 34.155 36.72 34.425 ;
     RECT  2.16 34.695 36.72 34.965 ;
     RECT  2.16 35.235 36.72 35.505 ;
     RECT  2.16 35.775 36.72 36.045 ;
     RECT  2.16 36.315 36.72 36.585 ;
     RECT  2.16 36.855 36.72 37.125 ;
     RECT  2.16 37.395 36.72 37.665 ;
     RECT  2.16 37.935 36.72 38.205 ;
     RECT  2.16 38.475 36.72 38.745 ;
     RECT  2.16 39.015 36.72 39.285 ;
     RECT  2.16 39.555 36.72 39.825 ;
     RECT  2.16 40.095 36.72 40.365 ;
     RECT  2.16 40.635 36.72 40.905 ;
     RECT  2.16 41.175 36.72 41.445 ;
     RECT  2.16 41.715 36.72 41.985 ;
     RECT  2.16 42.255 36.72 42.525 ;
     RECT  2.16 42.795 36.72 43.065 ;
     RECT  2.16 43.335 36.72 43.605 ;
     RECT  2.16 43.875 36.72 44.145 ;
     RECT  2.16 44.415 36.72 44.685 ;
     RECT  2.16 44.955 36.72 45.225 ;
     RECT  2.16 45.495 36.72 45.765 ;
     RECT  2.16 46.035 36.72 46.305 ;
     RECT  2.16 46.575 36.72 46.845 ;
     RECT  2.16 47.115 36.72 47.385 ;
     RECT  2.16 47.655 36.72 47.925 ;
     RECT  2.16 48.195 36.72 48.465 ;
     RECT  2.16 48.735 36.72 49.005 ;
     RECT  2.16 49.275 36.72 49.545 ;
     RECT  2.16 49.815 36.72 50.085 ;
     RECT  2.16 50.355 36.72 50.625 ;
     RECT  2.16 50.895 36.72 51.165 ;
     RECT  2.16 51.435 36.72 51.705 ;
     RECT  2.16 51.975 36.72 52.245 ;
     RECT  2.16 52.515 36.72 52.785 ;
     RECT  2.16 53.055 36.72 53.325 ;
     RECT  2.16 53.595 36.72 53.865 ;
     RECT  2.16 54.135 36.72 54.405 ;
     RECT  2.16 54.675 36.72 54.945 ;
     RECT  2.16 55.215 36.72 55.485 ;
     RECT  2.16 55.755 36.72 56.025 ;
     RECT  2.16 56.295 36.72 56.565 ;
     RECT  2.16 56.835 36.72 57.105 ;
     RECT  2.16 57.375 36.72 57.645 ;
     RECT  2.16 57.915 36.72 58.185 ;
     RECT  2.16 58.455 36.72 58.725 ;
     RECT  2.16 58.995 36.72 59.265 ;
     RECT  2.16 59.535 36.72 59.805 ;
     RECT  2.16 60.075 36.72 60.345 ;
     RECT  2.16 60.615 36.72 60.885 ;
     RECT  2.16 61.155 36.72 61.425 ;
     RECT  2.16 61.695 36.72 61.965 ;
     RECT  2.16 62.235 36.72 62.505 ;
     RECT  2.16 62.775 36.72 63.045 ;
     RECT  2.16 63.315 36.72 63.585 ;
     RECT  2.16 63.855 36.72 64.125 ;
     RECT  2.16 64.395 36.72 64.665 ;
     RECT  2.16 64.935 36.72 65.205 ;
     RECT  2.16 65.475 36.72 65.745 ;
     RECT  2.16 66.015 36.72 66.285 ;
     RECT  2.16 66.555 36.72 66.825 ;
     RECT  2.16 67.095 36.72 67.365 ;
     RECT  2.16 67.635 36.72 67.905 ;
     RECT  2.16 68.175 36.72 68.445 ;
     RECT  2.16 68.715 36.72 68.985 ;
     RECT  2.16 69.255 36.72 69.525 ;
     RECT  2.16 69.795 36.72 70.065 ;
     RECT  2.16 70.335 36.72 70.605 ;
     RECT  2.16 70.875 36.72 71.145 ;
     RECT  2.16 71.415 36.72 71.685 ;
     RECT  2.16 71.955 36.72 72.225 ;
     RECT  2.16 72.495 36.72 72.765 ;
     RECT  2.16 73.035 36.72 73.305 ;
     RECT  2.16 73.575 36.72 73.845 ;
     RECT  2.16 74.115 36.72 74.385 ;
     RECT  2.16 74.655 36.72 74.925 ;
     RECT  2.16 75.195 36.72 75.465 ;
     RECT  2.16 75.735 36.72 76.005 ;
     RECT  2.16 76.275 36.72 76.545 ;
     RECT  2.16 76.815 36.72 77.085 ;
     RECT  2.16 77.355 36.72 77.625 ;
     RECT  2.16 77.895 36.72 78.165 ;
     RECT  2.16 78.435 36.72 78.705 ;
     RECT  2.16 78.975 36.72 79.245 ;
     RECT  2.16 79.515 36.72 79.785 ;
     RECT  2.16 80.055 36.72 80.325 ;
     RECT  2.16 80.595 36.72 80.865 ;
     RECT  2.16 81.135 36.72 81.405 ;
     RECT  2.16 81.675 36.72 81.945 ;
     RECT  2.16 82.215 36.72 82.485 ;
     RECT  2.16 82.755 36.72 83.025 ;
     RECT  2.16 83.295 36.72 83.565 ;
     RECT  2.16 83.835 36.72 84.105 ;
     RECT  2.16 84.375 36.72 84.645 ;
     RECT  2.16 84.915 36.72 85.185 ;
     RECT  2.16 85.455 36.72 85.725 ;
     RECT  2.16 85.995 36.72 86.265 ;
     RECT  2.16 86.535 36.72 86.805 ;
     RECT  2.16 87.075 36.72 87.345 ;
     RECT  2.16 87.615 36.72 87.885 ;
     RECT  2.16 88.155 36.72 88.425 ;
     RECT  2.16 88.695 36.72 88.965 ;
     RECT  2.16 89.235 36.72 89.505 ;
     RECT  2.16 89.775 36.72 90.045 ;
     RECT  2.16 90.315 36.72 90.585 ;
     RECT  2.16 90.855 36.72 91.125 ;
     RECT  2.16 91.395 36.72 91.665 ;
     RECT  2.16 91.935 36.72 92.205 ;
     RECT  2.16 92.475 36.72 92.745 ;
    LAYER M1 ;
     RECT  2.16 2.151 36.72 92.889 ;
    LAYER M2 ;
     RECT  0.103 74.736 0.175 74.754 ;
     RECT  0.175 74.628 0.203 74.754 ;
     RECT  0.203 74.628 0.275 74.646 ;
     RECT  0.103 13.266 0.535 13.284 ;
     RECT  0.103 26.496 0.535 26.514 ;
     RECT  0.103 27.306 0.535 27.324 ;
     RECT  0.103 36.396 0.535 36.414 ;
     RECT  0.103 53.496 0.535 53.514 ;
     RECT  0.103 57.546 0.535 57.564 ;
     RECT  1.975 71.226 2.011 71.244 ;
     RECT  1.723 2.196 2.16 2.214 ;
     RECT  0.535 11.376 2.16 11.934 ;
     RECT  0.535 13.266 2.16 13.626 ;
     RECT  0.535 16.848 2.16 16.866 ;
     RECT  0.535 18.126 2.16 18.144 ;
     RECT  0.103 21.636 2.16 22.194 ;
     RECT  0.535 23.256 2.16 23.274 ;
     RECT  0.103 24.336 2.16 24.354 ;
     RECT  0.535 26.136 2.16 26.514 ;
     RECT  0.535 27.306 2.16 27.936 ;
     RECT  0.535 30.186 2.16 30.204 ;
     RECT  0.103 31.896 2.16 31.914 ;
     RECT  0.535 36.396 2.16 36.954 ;
     RECT  0.103 40.032 2.16 40.05 ;
     RECT  0.535 43.308 2.16 43.326 ;
     RECT  0.535 47.286 2.16 47.304 ;
     RECT  0.103 50.706 2.16 50.724 ;
     RECT  0.535 51.516 2.16 51.534 ;
     RECT  0.535 52.866 2.16 53.514 ;
     RECT  0.535 57.348 2.16 57.564 ;
     RECT  0.535 60.966 2.16 60.984 ;
     RECT  0.535 64.296 2.16 64.314 ;
     RECT  0.103 65.376 2.16 65.394 ;
     RECT  2.011 71.19 2.16 71.244 ;
     RECT  0.535 72.846 2.16 73.494 ;
     RECT  0.103 76.212 2.16 76.23 ;
     RECT  1.147 80.91 2.16 80.928 ;
     RECT  0.103 86.238 2.16 86.256 ;
     RECT  1.975 87.858 2.16 87.876 ;
     RECT  2.16 2.151 2.299 92.889 ;
     RECT  2.299 2.106 3.415 92.889 ;
     RECT  3.415 2.034 7.187 92.889 ;
     RECT  7.187 2.07 8.023 92.889 ;
     RECT  8.023 1.998 8.383 92.889 ;
     RECT  8.383 1.926 11.371 92.889 ;
     RECT  15.979 94.986 16.079 95.004 ;
     RECT  11.371 1.836 25.547 92.889 ;
     RECT  25.547 1.962 34.843 92.889 ;
     RECT  34.843 1.926 36.527 92.889 ;
     RECT  36.527 2.034 36.72 92.889 ;
     RECT  36.72 12.798 36.995 31.446 ;
     RECT  36.72 50.328 36.995 50.652 ;
     RECT  36.72 2.034 37.031 11.97 ;
     RECT  36.72 57.924 37.031 74.484 ;
     RECT  36.72 77.058 37.031 91.188 ;
     RECT  36.72 51.408 37.103 56.934 ;
     RECT  36.72 32.31 37.427 35.568 ;
     RECT  37.427 32.436 37.499 35.568 ;
     RECT  37.031 77.058 37.499 84.168 ;
     RECT  36.72 43.308 37.535 49.572 ;
     RECT  37.031 4.698 37.571 9.072 ;
     RECT  36.995 12.798 37.571 13.05 ;
     RECT  36.995 13.95 37.571 31.446 ;
     RECT  36.72 36.324 37.571 38.304 ;
     RECT  36.72 39.096 37.571 42.552 ;
     RECT  37.031 57.924 37.571 58.716 ;
     RECT  37.031 59.508 37.571 74.484 ;
     RECT  37.031 2.034 37.607 3.906 ;
     RECT  37.571 4.698 37.607 7.956 ;
     RECT  37.571 9.018 37.607 9.072 ;
     RECT  37.571 13.95 37.607 31.014 ;
     RECT  37.499 32.436 37.607 35.496 ;
     RECT  37.571 36.324 37.607 37.188 ;
     RECT  37.535 43.308 37.607 43.974 ;
     RECT  37.103 51.408 37.607 53.928 ;
     RECT  37.103 54.756 37.607 56.934 ;
     RECT  37.571 59.58 37.607 71.244 ;
     RECT  37.499 77.058 37.607 83.79 ;
     RECT  37.031 85.536 37.607 88.218 ;
     RECT  37.607 17.658 37.643 30.168 ;
     RECT  36.72 75.276 37.643 76.23 ;
     RECT  37.607 2.034 38.219 2.826 ;
     RECT  37.607 6.318 38.219 7.758 ;
     RECT  37.607 15.498 38.219 16.704 ;
     RECT  37.643 20.97 38.219 30.168 ;
     RECT  37.607 32.436 38.219 34.254 ;
     RECT  37.607 36.558 38.219 37.188 ;
     RECT  37.571 37.98 38.219 38.304 ;
     RECT  37.571 39.096 38.219 40.734 ;
     RECT  37.571 41.526 38.219 42.552 ;
     RECT  37.607 43.416 38.219 43.974 ;
     RECT  37.535 44.766 38.219 46.368 ;
     RECT  37.535 47.16 38.219 49.572 ;
     RECT  37.607 54.756 38.219 55.314 ;
     RECT  37.607 56.106 38.219 56.934 ;
     RECT  37.571 57.924 38.219 58.284 ;
     RECT  37.607 59.58 38.219 62.226 ;
     RECT  37.607 63.054 38.219 67.428 ;
     RECT  37.607 68.256 38.219 71.244 ;
     RECT  37.571 72 38.219 74.484 ;
     RECT  37.643 75.276 38.219 76.032 ;
     RECT  37.607 77.094 38.219 82.512 ;
     RECT  37.607 85.536 38.219 86.634 ;
     RECT  37.031 89.244 38.219 91.188 ;
     RECT  37.031 9.828 38.255 11.97 ;
     RECT  38.219 22.356 38.255 23.994 ;
     RECT  38.219 27.036 38.255 27.432 ;
     RECT  38.219 33.156 38.255 33.174 ;
     RECT  38.219 36.558 38.255 37.116 ;
     RECT  38.219 41.688 38.255 42.516 ;
     RECT  38.219 47.934 38.255 49.572 ;
     RECT  37.607 52.596 38.255 53.694 ;
     RECT  38.219 57.924 38.255 58.212 ;
     RECT  38.219 64.098 38.255 65.034 ;
     RECT  38.219 65.79 38.255 67.428 ;
     RECT  38.219 68.724 38.255 70.254 ;
     RECT  38.219 78.948 38.255 78.966 ;
     RECT  38.219 89.28 38.255 91.116 ;
     RECT  38.255 41.796 38.291 42.516 ;
     RECT  38.255 48.168 38.291 49.572 ;
     RECT  38.219 86.274 38.291 86.634 ;
     RECT  38.255 52.794 38.327 53.658 ;
     RECT  38.327 52.794 38.363 53.154 ;
     RECT  38.255 66.834 38.623 67.428 ;
     RECT  38.219 81.306 38.623 82.512 ;
     RECT  37.607 83.304 38.623 83.79 ;
     RECT  38.219 2.034 38.687 2.664 ;
     RECT  37.643 17.766 38.687 20.106 ;
     RECT  38.219 75.276 38.687 75.564 ;
     RECT  38.291 48.816 38.695 49.572 ;
     RECT  36.995 50.4 38.695 50.652 ;
     RECT  38.687 2.07 38.723 2.664 ;
     RECT  38.255 9.828 38.723 10.116 ;
     RECT  37.607 13.95 38.723 14.544 ;
     RECT  38.219 15.498 38.723 16.092 ;
     RECT  38.219 28.188 38.723 29.016 ;
     RECT  38.219 30.114 38.723 30.168 ;
     RECT  37.607 30.924 38.723 31.014 ;
     RECT  37.607 35.244 38.723 35.496 ;
     RECT  38.255 36.558 38.723 36.576 ;
     RECT  38.219 44.766 38.723 44.784 ;
     RECT  38.219 46.116 38.723 46.296 ;
     RECT  38.255 64.098 38.723 64.188 ;
     RECT  38.687 75.438 38.723 75.564 ;
     RECT  38.623 81.306 38.723 83.79 ;
     RECT  38.723 2.106 38.759 2.664 ;
     RECT  38.219 6.318 38.759 6.372 ;
     RECT  38.219 7.326 38.759 7.758 ;
     RECT  38.255 10.908 38.759 11.97 ;
     RECT  38.723 13.986 38.759 14.544 ;
     RECT  38.687 17.766 38.759 19.872 ;
     RECT  38.219 20.97 38.759 21.024 ;
     RECT  38.723 30.114 38.759 30.132 ;
     RECT  38.723 30.96 38.759 31.014 ;
     RECT  38.623 32.274 38.759 32.292 ;
     RECT  38.219 39.258 38.759 39.618 ;
     RECT  38.219 56.844 38.759 56.934 ;
     RECT  38.219 59.58 38.759 59.634 ;
     RECT  38.219 60.588 38.759 61.254 ;
     RECT  38.219 62.046 38.759 62.226 ;
     RECT  38.623 66.834 38.759 67.698 ;
     RECT  38.219 74.016 38.759 74.106 ;
     RECT  38.723 75.51 38.759 75.564 ;
     RECT  38.723 81.756 38.759 83.79 ;
     RECT  38.255 89.28 38.759 90.576 ;
     RECT  38.759 2.106 38.795 2.124 ;
     RECT  38.759 6.354 38.795 6.372 ;
     RECT  38.759 7.326 38.795 7.344 ;
     RECT  37.607 9.054 38.795 9.072 ;
     RECT  38.723 9.828 38.795 9.846 ;
     RECT  38.759 10.944 38.795 11.97 ;
     RECT  37.571 13.032 38.795 13.05 ;
     RECT  38.759 13.986 38.795 14.004 ;
     RECT  38.723 15.84 38.795 16.092 ;
     RECT  38.759 17.766 38.795 17.784 ;
     RECT  38.759 18.54 38.795 19.296 ;
     RECT  38.759 20.97 38.795 20.988 ;
     RECT  38.255 22.356 38.795 23.886 ;
     RECT  38.219 24.984 38.795 25.002 ;
     RECT  38.255 27.414 38.795 27.432 ;
     RECT  38.723 28.422 38.795 29.016 ;
     RECT  38.759 30.996 38.795 31.014 ;
     RECT  38.723 35.244 38.795 35.262 ;
     RECT  38.759 39.6 38.795 39.618 ;
     RECT  38.219 40.446 38.795 40.734 ;
     RECT  38.291 42.066 38.795 42.084 ;
     RECT  38.723 46.116 38.795 46.134 ;
     RECT  38.219 47.16 38.795 47.178 ;
     RECT  38.695 48.816 38.795 50.652 ;
     RECT  37.607 51.75 38.795 51.768 ;
     RECT  38.363 52.794 38.795 52.974 ;
     RECT  38.219 55.224 38.795 55.242 ;
     RECT  38.759 56.844 38.795 56.862 ;
     RECT  38.255 57.924 38.795 57.942 ;
     RECT  38.759 59.616 38.795 59.634 ;
     RECT  38.759 60.588 38.795 60.606 ;
     RECT  38.759 62.208 38.795 62.226 ;
     RECT  38.219 63.054 38.795 63.072 ;
     RECT  38.723 64.17 38.795 64.188 ;
     RECT  38.255 65.016 38.795 65.034 ;
     RECT  38.759 67.338 38.795 67.356 ;
     RECT  38.255 69.57 38.795 69.588 ;
     RECT  38.219 71.226 38.795 71.244 ;
     RECT  38.219 72 38.795 72.486 ;
     RECT  38.759 74.016 38.795 74.034 ;
     RECT  38.759 75.51 38.795 75.528 ;
     RECT  38.219 77.598 38.795 78.192 ;
     RECT  38.219 80.406 38.795 80.424 ;
     RECT  38.759 81.756 38.795 82.512 ;
     RECT  38.759 83.304 38.795 83.79 ;
     RECT  38.291 86.616 38.795 86.634 ;
     RECT  37.607 87.624 38.795 88.218 ;
     RECT  38.759 90.018 38.795 90.504 ;
     RECT  38.795 28.998 38.867 29.016 ;
    LAYER M3 ;
     RECT  3.024 1.051 3.042 1.435 ;
     RECT  38.772 1.243 38.79 1.435 ;
     RECT  38.736 1.435 38.79 1.579 ;
     RECT  3.024 1.435 3.618 1.771 ;
     RECT  25.416 1.051 25.434 1.831 ;
     RECT  18.828 1.876 18.846 1.921 ;
     RECT  21.924 1.876 21.942 1.921 ;
     RECT  25.416 1.831 25.542 1.921 ;
     RECT  18.756 1.921 18.846 1.957 ;
     RECT  36.504 1.921 36.522 1.957 ;
     RECT  3.024 1.771 3.726 1.963 ;
     RECT  38.7 1.579 38.79 1.963 ;
     RECT  8.388 1.921 8.406 1.993 ;
     RECT  36 1.957 36.522 1.993 ;
     RECT  8.028 1.993 8.406 2.029 ;
     RECT  11.376 1.831 11.394 2.029 ;
     RECT  18.612 1.957 18.846 2.065 ;
     RECT  34.848 1.921 34.866 2.065 ;
     RECT  1.728 1.243 1.746 2.101 ;
     RECT  2.916 1.963 3.726 2.101 ;
     RECT  6.408 2.065 6.426 2.101 ;
     RECT  13.968 2.059 13.986 2.101 ;
     RECT  15.84 1.876 15.858 2.101 ;
     RECT  21.924 1.921 22.302 2.101 ;
     RECT  23.796 1.876 23.814 2.101 ;
     RECT  35.748 1.993 36.522 2.101 ;
     RECT  37.584 1.771 37.602 2.107 ;
     RECT  38.664 1.963 38.79 2.129 ;
     RECT  4.68 2.101 4.698 2.143 ;
     RECT  7.164 2.029 7.182 2.143 ;
     RECT  8.028 2.029 9.198 2.143 ;
     RECT  12.564 1.957 12.582 2.143 ;
     RECT  13.968 2.101 14.238 2.143 ;
     RECT  15.732 2.101 15.858 2.143 ;
     RECT  20.844 2.059 20.862 2.143 ;
     RECT  21.924 2.101 23.886 2.143 ;
     RECT  24.732 1.921 25.542 2.143 ;
     RECT  28.764 2.065 28.782 2.143 ;
     RECT  30.312 2.101 31.842 2.143 ;
     RECT  34.2 2.065 34.866 2.143 ;
     RECT  35.604 2.101 36.522 2.143 ;
     RECT  4.68 2.143 5.205 2.191 ;
     RECT  5.976 2.101 6.426 2.191 ;
     RECT  7.164 2.143 9.198 2.191 ;
     RECT  10.08 2.029 11.394 2.191 ;
     RECT  15.732 2.143 16.005 2.191 ;
     RECT  18.576 2.065 18.846 2.191 ;
     RECT  26.715 2.143 26.805 2.191 ;
     RECT  30.312 2.143 32.205 2.191 ;
     RECT  34.2 2.143 36.522 2.191 ;
     RECT  1.728 2.101 3.726 2.219 ;
     RECT  17.316 1.993 17.334 2.227 ;
     RECT  20.844 2.143 25.542 2.227 ;
     RECT  30.312 2.191 32.454 2.227 ;
     RECT  12.564 2.143 14.238 2.251 ;
     RECT  15.048 2.191 16.005 2.251 ;
     RECT  33.804 2.191 36.522 2.255 ;
     RECT  2.304 2.219 3.726 2.263 ;
     RECT  4.68 2.191 11.394 2.263 ;
     RECT  18.576 2.191 18.954 2.263 ;
     RECT  20.844 2.227 25.866 2.263 ;
     RECT  26.715 2.191 27.378 2.263 ;
     RECT  28.764 2.143 29.505 2.263 ;
     RECT  30.276 2.227 32.886 2.263 ;
     RECT  12.564 2.251 16.005 2.299 ;
     RECT  18.468 2.263 18.954 2.299 ;
     RECT  20.844 2.263 27.378 2.335 ;
     RECT  16.74 2.227 17.334 2.347 ;
     RECT  18.468 2.299 19.458 2.347 ;
     RECT  2.304 2.263 11.394 2.371 ;
     RECT  12.276 2.299 16.005 2.371 ;
     RECT  16.74 2.347 19.458 2.371 ;
     RECT  37.548 2.107 37.602 2.371 ;
     RECT  38.664 2.129 38.754 2.371 ;
     RECT  2.304 2.371 11.466 2.461 ;
     RECT  12.204 2.371 19.458 2.461 ;
     RECT  36.504 2.255 36.522 2.489 ;
     RECT  28.764 2.263 32.994 2.497 ;
     RECT  33.804 2.255 35.478 2.497 ;
     RECT  37.548 2.371 38.754 2.561 ;
     RECT  2.304 2.461 19.674 2.569 ;
     RECT  20.844 2.335 27.954 2.569 ;
     RECT  2.304 2.569 27.954 2.633 ;
     RECT  0.144 2.539 0.162 2.669 ;
     RECT  37.584 2.561 38.754 2.669 ;
     RECT  28.764 2.497 35.478 2.759 ;
     RECT  2.304 2.633 27.882 2.795 ;
     RECT  37.584 2.669 38.61 2.861 ;
     RECT  28.764 2.759 35.37 2.875 ;
     RECT  7.38 2.795 27.882 2.903 ;
     RECT  28.62 2.875 35.37 3.029 ;
     RECT  28.728 3.029 35.37 3.137 ;
     RECT  36.468 3.019 36.486 3.173 ;
     RECT  7.38 2.903 27.846 3.299 ;
     RECT  38.592 2.861 38.61 3.389 ;
     RECT  21.096 3.299 27.846 3.407 ;
     RECT  28.836 3.137 35.37 3.437 ;
     RECT  7.38 3.299 20.25 3.479 ;
     RECT  7.524 3.479 20.25 3.533 ;
     RECT  2.304 2.795 6.606 3.547 ;
     RECT  7.56 3.533 20.25 3.569 ;
     RECT  28.872 3.437 35.37 3.569 ;
     RECT  7.812 3.569 20.25 3.605 ;
     RECT  2.304 3.547 6.642 3.685 ;
     RECT  37.584 2.861 37.602 3.739 ;
     RECT  29.088 3.569 35.37 3.811 ;
     RECT  21.315 3.407 27.846 3.883 ;
     RECT  21.315 3.883 28.062 3.983 ;
     RECT  7.815 3.605 20.25 4.153 ;
     RECT  1.152 4.075 1.17 4.205 ;
     RECT  7.815 4.153 20.394 4.261 ;
     RECT  21.315 3.983 27.99 4.261 ;
     RECT  29.088 3.811 35.982 4.289 ;
     RECT  37.008 3.739 37.602 4.451 ;
     RECT  2.304 3.685 6.678 4.495 ;
     RECT  2.304 4.495 6.822 4.559 ;
     RECT  37.368 4.451 37.602 4.637 ;
     RECT  3.492 4.559 6.822 4.693 ;
     RECT  7.815 4.261 27.99 4.693 ;
     RECT  3.492 4.693 27.99 4.721 ;
     RECT  0.108 4.603 0.126 4.733 ;
     RECT  3.492 4.721 5.922 4.733 ;
     RECT  6.696 4.721 27.99 4.801 ;
     RECT  29.088 4.289 35.838 4.801 ;
     RECT  1.26 4.795 1.278 4.939 ;
     RECT  1.152 4.939 1.278 4.973 ;
     RECT  1.152 4.973 1.17 5.069 ;
     RECT  6.696 4.801 35.838 5.161 ;
     RECT  37.548 4.637 37.602 5.261 ;
     RECT  6.696 5.161 36.198 5.309 ;
     RECT  21.315 5.309 36.198 5.357 ;
     RECT  21.315 5.357 35.478 5.369 ;
     RECT  2.304 4.559 2.697 5.459 ;
     RECT  3.744 4.733 5.922 5.467 ;
     RECT  6.696 5.309 20.394 5.467 ;
     RECT  21.315 5.369 35.406 5.639 ;
     RECT  36.216 5.467 36.234 5.639 ;
     RECT  21.315 5.639 28.278 5.885 ;
     RECT  21.315 5.885 28.206 5.909 ;
     RECT  2.415 5.459 2.697 5.971 ;
     RECT  3.708 5.467 20.394 5.971 ;
     RECT  38.772 5.851 38.79 5.995 ;
     RECT  2.415 5.971 20.394 6.107 ;
     RECT  29.052 5.639 35.406 6.151 ;
     RECT  2.415 6.107 2.826 6.187 ;
     RECT  21.315 5.909 28.062 6.269 ;
     RECT  3.636 6.107 20.394 6.277 ;
     RECT  3.636 6.277 20.466 6.341 ;
     RECT  12.852 6.341 20.466 6.421 ;
     RECT  21.315 6.269 27.99 6.421 ;
     RECT  36.504 6.421 36.522 6.523 ;
     RECT  37.584 5.261 37.602 6.523 ;
     RECT  36.504 6.523 37.602 6.611 ;
     RECT  29.052 6.151 35.55 6.619 ;
     RECT  37.584 6.611 37.602 6.619 ;
     RECT  38.736 5.995 38.79 6.619 ;
     RECT  12.852 6.421 27.99 6.683 ;
     RECT  36.504 6.611 36.522 6.691 ;
     RECT  37.584 6.619 38.79 6.749 ;
     RECT  12.852 6.683 20.394 6.809 ;
     RECT  36.36 6.691 36.522 6.809 ;
     RECT  36.36 6.809 36.378 6.845 ;
     RECT  29.052 6.619 35.586 6.853 ;
     RECT  3.636 6.341 12.006 6.859 ;
     RECT  29.016 6.853 35.586 6.953 ;
     RECT  2.304 6.187 2.826 6.961 ;
     RECT  3.564 6.859 12.006 6.961 ;
     RECT  21.204 6.683 27.99 7.195 ;
     RECT  2.304 6.961 12.006 7.231 ;
     RECT  12.852 6.809 20.214 7.231 ;
     RECT  36.036 6.961 36.234 7.259 ;
     RECT  36.036 7.259 36.054 7.349 ;
     RECT  2.304 7.231 20.214 7.465 ;
     RECT  21.204 7.195 28.17 7.465 ;
     RECT  2.268 7.465 20.214 7.613 ;
     RECT  21.096 7.465 28.17 7.627 ;
     RECT  29.016 6.953 35.118 7.627 ;
     RECT  2.304 7.613 20.214 7.735 ;
     RECT  21.096 7.627 35.118 7.735 ;
     RECT  2.304 7.735 35.118 7.771 ;
     RECT  37.584 6.749 37.602 7.771 ;
     RECT  37.044 7.771 37.602 7.997 ;
     RECT  38.736 6.749 38.79 8.011 ;
     RECT  2.304 7.771 35.622 8.131 ;
     RECT  38.7 8.011 38.79 8.141 ;
     RECT  0.108 8.203 0.126 8.333 ;
     RECT  2.304 8.131 36.234 8.339 ;
     RECT  2.304 8.339 20.358 8.699 ;
     RECT  21.096 8.339 36.234 8.815 ;
     RECT  21.096 8.815 36.522 8.851 ;
     RECT  4.536 8.699 20.358 9.005 ;
     RECT  21.096 8.851 36.594 9.019 ;
     RECT  37.548 7.997 37.602 9.019 ;
     RECT  21.096 9.019 37.602 9.041 ;
     RECT  21.096 9.041 37.026 9.113 ;
     RECT  4.536 9.005 5.778 9.149 ;
     RECT  21.096 9.113 36.99 9.239 ;
     RECT  36.972 9.239 36.99 9.581 ;
     RECT  2.304 8.699 3.618 9.691 ;
     RECT  38.772 8.141 38.79 9.691 ;
     RECT  2.268 9.691 3.618 9.751 ;
     RECT  21.096 9.239 35.982 9.779 ;
     RECT  2.268 9.751 3.726 9.851 ;
     RECT  38.196 9.691 38.79 9.851 ;
     RECT  6.552 9.005 20.358 9.859 ;
     RECT  21.096 9.779 35.946 9.859 ;
     RECT  6.552 9.859 35.946 9.923 ;
     RECT  6.552 9.923 35.478 9.931 ;
     RECT  2.304 9.851 3.726 10.021 ;
     RECT  4.536 9.149 5.598 10.021 ;
     RECT  6.516 9.931 35.478 10.021 ;
     RECT  38.196 9.851 38.718 10.411 ;
     RECT  2.304 10.021 35.478 10.499 ;
     RECT  37.584 10.411 38.718 10.603 ;
     RECT  4.248 10.499 35.478 10.685 ;
     RECT  4.248 10.685 35.226 10.733 ;
     RECT  37.584 10.603 38.79 10.733 ;
     RECT  36.432 10.699 36.45 10.769 ;
     RECT  4.428 10.733 35.226 10.931 ;
     RECT  37.548 11.131 37.566 11.201 ;
     RECT  2.304 10.499 3.402 11.365 ;
     RECT  4.428 10.931 35.118 11.551 ;
     RECT  2.304 11.365 3.582 11.641 ;
     RECT  4.32 11.551 35.118 11.641 ;
     RECT  36.144 11.551 36.162 11.741 ;
     RECT  2.304 11.641 35.118 11.785 ;
     RECT  38.7 10.733 38.79 11.789 ;
     RECT  37.584 11.785 37.602 11.837 ;
     RECT  0.54 11.371 0.558 12.029 ;
     RECT  38.772 11.789 38.79 12.029 ;
     RECT  2.304 11.785 35.334 12.389 ;
     RECT  28.152 12.389 35.334 12.595 ;
     RECT  36.504 12.187 36.522 12.811 ;
     RECT  37.548 12.523 37.566 12.821 ;
     RECT  36.288 12.811 36.522 12.929 ;
     RECT  38.772 12.859 38.79 13.051 ;
     RECT  2.304 12.389 27.414 13.147 ;
     RECT  28.152 12.595 35.55 13.147 ;
     RECT  0.108 13.243 0.126 13.289 ;
     RECT  36.936 13.243 36.99 13.361 ;
     RECT  2.304 13.147 35.55 13.469 ;
     RECT  0.54 13.603 0.558 13.805 ;
     RECT  2.415 13.469 35.55 13.873 ;
     RECT  38.736 13.051 38.79 13.915 ;
     RECT  38.7 13.915 38.79 13.973 ;
     RECT  38.736 13.973 38.79 14.009 ;
     RECT  36.936 13.361 36.954 14.107 ;
     RECT  2.415 13.873 35.622 14.135 ;
     RECT  2.415 14.135 12.078 14.207 ;
     RECT  36.504 14.107 36.954 14.243 ;
     RECT  12.852 14.135 35.622 14.341 ;
     RECT  2.415 14.207 12.042 14.443 ;
     RECT  2.376 14.443 12.042 14.485 ;
     RECT  38.736 14.009 38.754 14.549 ;
     RECT  36.972 14.299 36.99 14.635 ;
     RECT  12.852 14.341 35.802 14.717 ;
     RECT  28.116 14.717 35.802 14.819 ;
     RECT  2.304 14.485 12.042 14.953 ;
     RECT  12.852 14.717 27.342 14.953 ;
     RECT  36.972 14.635 37.602 14.981 ;
     RECT  28.8 14.819 35.802 15.019 ;
     RECT  28.8 15.019 36.522 15.179 ;
     RECT  35.964 15.179 36.522 15.287 ;
     RECT  38.772 15.163 38.79 15.355 ;
     RECT  2.304 14.953 27.342 15.449 ;
     RECT  35.964 15.287 35.982 15.557 ;
     RECT  37.584 14.981 37.602 15.581 ;
     RECT  28.8 15.179 35.097 15.763 ;
     RECT  0.108 15.259 0.126 15.917 ;
     RECT  4.104 15.449 27.342 15.997 ;
     RECT  28.764 15.763 35.097 16.075 ;
     RECT  4.104 15.997 27.378 16.105 ;
     RECT  38.7 15.355 38.79 16.109 ;
     RECT  4.104 16.105 27.702 16.141 ;
     RECT  28.764 16.075 35.118 16.141 ;
     RECT  36.504 16.219 36.522 16.303 ;
     RECT  4.104 16.141 35.118 16.411 ;
     RECT  36.504 16.303 37.062 16.445 ;
     RECT  2.304 15.449 3.186 16.681 ;
     RECT  3.996 16.411 35.118 16.681 ;
     RECT  38.196 16.681 38.214 16.747 ;
     RECT  0.108 16.747 0.126 16.843 ;
     RECT  0.108 16.843 0.558 16.877 ;
     RECT  36.504 16.445 36.522 16.915 ;
     RECT  36.432 16.915 36.522 16.951 ;
     RECT  0.54 16.877 0.558 17.165 ;
     RECT  37.584 16.747 38.214 17.165 ;
     RECT  36.36 16.951 36.522 17.383 ;
     RECT  35.892 17.383 36.522 17.467 ;
     RECT  37.584 17.165 37.638 17.467 ;
     RECT  2.304 16.681 35.154 17.491 ;
     RECT  35.892 17.467 37.638 17.491 ;
     RECT  2.304 17.491 37.638 17.519 ;
     RECT  2.304 17.519 36.45 17.609 ;
     RECT  2.415 17.609 35.802 17.645 ;
     RECT  37.62 17.519 37.638 17.693 ;
     RECT  2.415 17.645 35.154 17.789 ;
     RECT  38.736 17.275 38.79 17.789 ;
     RECT  0.144 17.707 0.162 17.837 ;
     RECT  38.736 17.789 38.754 17.995 ;
     RECT  38.7 17.995 38.754 18.157 ;
     RECT  0.54 18.121 0.558 18.365 ;
     RECT  2.415 17.789 2.97 18.419 ;
     RECT  3.924 17.789 26.997 18.419 ;
     RECT  38.196 18.157 38.754 18.523 ;
     RECT  4.032 18.419 26.997 18.805 ;
     RECT  27.72 17.789 35.154 18.805 ;
     RECT  2.415 18.419 2.934 18.859 ;
     RECT  38.196 18.523 38.79 19.085 ;
     RECT  4.032 18.805 35.154 19.337 ;
     RECT  2.304 18.859 2.934 19.499 ;
     RECT  2.415 19.499 2.934 19.543 ;
     RECT  37.368 19.435 37.386 19.613 ;
     RECT  4.356 19.337 35.154 19.627 ;
     RECT  4.356 19.627 35.442 19.651 ;
     RECT  2.415 19.543 3.186 19.723 ;
     RECT  0.144 19.819 0.162 19.949 ;
     RECT  4.356 19.651 36.018 20.011 ;
     RECT  2.415 19.723 3.582 20.191 ;
     RECT  4.356 20.011 36.198 20.191 ;
     RECT  2.415 20.191 36.198 20.281 ;
     RECT  2.304 20.281 36.198 20.309 ;
     RECT  2.304 20.309 35.694 20.333 ;
     RECT  38.664 19.085 38.79 20.333 ;
     RECT  37.008 19.885 37.026 20.353 ;
     RECT  37.008 20.353 37.638 20.477 ;
     RECT  2.304 20.333 35.442 20.489 ;
     RECT  2.304 20.489 3.438 20.579 ;
     RECT  4.464 20.489 35.442 20.579 ;
     RECT  37.044 20.477 37.638 20.669 ;
     RECT  37.044 20.669 37.386 20.861 ;
     RECT  4.464 20.579 35.37 20.921 ;
     RECT  34.815 20.921 35.37 21.191 ;
     RECT  37.044 20.861 37.062 21.197 ;
     RECT  38.736 20.333 38.79 21.235 ;
     RECT  4.464 20.921 33.858 21.271 ;
     RECT  2.304 20.579 3.402 21.361 ;
     RECT  4.176 21.271 33.858 21.361 ;
     RECT  2.304 21.361 33.858 21.811 ;
     RECT  2.304 21.811 34.038 21.929 ;
     RECT  34.815 21.191 35.226 22.009 ;
     RECT  13.104 21.929 34.038 22.073 ;
     RECT  2.304 21.929 12.294 22.109 ;
     RECT  13.176 22.073 34.038 22.171 ;
     RECT  34.815 22.009 35.262 22.171 ;
     RECT  0.108 21.631 0.126 22.445 ;
     RECT  37.368 22.315 37.386 22.445 ;
     RECT  13.176 22.171 35.262 22.469 ;
     RECT  13.176 22.469 35.19 22.891 ;
     RECT  13.14 22.891 35.19 23.08 ;
     RECT  2.415 22.109 12.294 23.161 ;
     RECT  13.104 23.08 35.19 23.161 ;
     RECT  2.304 23.161 35.19 23.431 ;
     RECT  0.54 23.251 0.558 23.501 ;
     RECT  2.304 23.431 35.442 23.803 ;
     RECT  38.196 21.235 38.79 23.891 ;
     RECT  38.196 23.891 38.754 23.933 ;
     RECT  2.268 23.803 35.442 24.089 ;
     RECT  36.18 23.935 36.198 24.089 ;
     RECT  0.144 23.995 0.162 24.125 ;
     RECT  37.044 24.133 37.062 24.173 ;
     RECT  2.304 24.089 35.442 24.475 ;
     RECT  38.196 23.933 38.25 24.859 ;
     RECT  38.196 24.859 38.79 25.007 ;
     RECT  0.108 24.331 0.126 25.085 ;
     RECT  37.008 24.331 37.026 25.085 ;
     RECT  2.304 24.475 35.874 25.519 ;
     RECT  2.304 25.519 36.522 25.853 ;
     RECT  2.304 25.853 35.91 26.249 ;
     RECT  38.196 25.007 38.214 26.293 ;
     RECT  0.54 26.131 0.558 26.333 ;
     RECT  37.584 26.293 38.214 26.333 ;
     RECT  38.196 26.333 38.214 26.443 ;
     RECT  38.196 26.443 38.79 26.539 ;
     RECT  2.304 26.249 2.697 27.031 ;
     RECT  2.304 27.031 2.826 27.059 ;
     RECT  2.415 27.059 2.826 27.211 ;
     RECT  3.672 26.249 35.91 27.211 ;
     RECT  2.415 27.211 36.378 27.401 ;
     RECT  2.415 27.401 35.946 27.437 ;
     RECT  0.108 26.491 0.126 27.533 ;
     RECT  2.415 27.437 35.874 27.599 ;
     RECT  38.196 26.539 38.862 27.679 ;
     RECT  2.415 27.599 35.838 27.725 ;
     RECT  37.584 27.679 38.862 27.725 ;
     RECT  38.196 27.725 38.862 27.917 ;
     RECT  2.415 27.725 35.694 27.941 ;
     RECT  0.54 27.913 0.558 28.061 ;
     RECT  38.7 27.917 38.862 28.211 ;
     RECT  38.772 28.211 38.862 28.445 ;
     RECT  2.415 27.941 2.826 28.555 ;
     RECT  3.96 27.941 35.694 28.561 ;
     RECT  3.96 28.561 35.766 28.603 ;
     RECT  3.96 28.603 36.162 28.759 ;
     RECT  2.304 28.555 2.826 28.795 ;
     RECT  37.008 28.219 37.026 28.795 ;
     RECT  2.304 28.795 3.114 28.831 ;
     RECT  37.008 28.795 37.062 28.973 ;
     RECT  38.844 28.445 38.862 29.021 ;
     RECT  3.924 28.759 36.162 29.065 ;
     RECT  37.008 28.973 37.026 29.065 ;
     RECT  3.924 29.065 37.026 29.357 ;
     RECT  38.772 29.275 38.79 29.371 ;
     RECT  2.304 28.831 3.186 29.605 ;
     RECT  3.924 29.357 36.594 29.605 ;
     RECT  38.196 29.371 38.79 29.645 ;
     RECT  2.304 29.605 36.594 29.903 ;
     RECT  38.7 29.645 38.79 30.173 ;
     RECT  2.304 29.903 36.414 30.209 ;
     RECT  0.54 30.181 0.558 30.365 ;
     RECT  37.62 30.073 37.638 30.365 ;
     RECT  36.396 30.209 36.414 30.569 ;
     RECT  38.736 30.173 38.79 30.919 ;
     RECT  38.7 30.919 38.79 31.019 ;
     RECT  2.304 30.209 35.658 31.189 ;
     RECT  37.548 30.523 37.602 31.229 ;
     RECT  37.548 31.229 37.566 31.451 ;
     RECT  2.304 31.189 36.09 31.495 ;
     RECT  2.304 31.495 36.594 31.649 ;
     RECT  3.6 31.649 36.414 31.685 ;
     RECT  3.852 31.685 36.414 31.829 ;
     RECT  3.924 31.829 36.414 31.919 ;
     RECT  0.108 31.891 0.126 31.949 ;
     RECT  3.924 31.919 36.126 31.991 ;
     RECT  2.304 31.649 2.862 32.063 ;
     RECT  4.212 31.991 36.126 32.063 ;
     RECT  38.7 31.019 38.718 32.107 ;
     RECT  38.556 32.107 38.718 32.251 ;
     RECT  2.304 32.063 2.79 32.297 ;
     RECT  38.556 32.251 38.754 32.297 ;
     RECT  37.404 31.915 37.422 32.333 ;
     RECT  38.556 32.297 38.646 32.333 ;
     RECT  38.196 32.431 38.214 32.635 ;
     RECT  6.804 32.063 36.126 32.765 ;
     RECT  4.212 32.063 5.958 32.845 ;
     RECT  6.804 32.765 35.766 32.845 ;
     RECT  4.212 32.845 35.766 32.999 ;
     RECT  4.212 32.999 35.73 33.043 ;
     RECT  37.584 32.635 38.214 33.071 ;
     RECT  2.304 32.297 2.697 33.151 ;
     RECT  38.196 33.071 38.214 33.151 ;
     RECT  36.504 32.971 36.522 33.304 ;
     RECT  3.672 33.043 35.73 33.305 ;
     RECT  3.672 33.305 14.526 33.341 ;
     RECT  36.504 33.304 37.026 33.341 ;
     RECT  15.372 33.305 35.73 33.413 ;
     RECT  3.672 33.341 14.454 33.421 ;
     RECT  15.804 33.413 35.73 33.449 ;
     RECT  38.196 33.151 38.25 33.499 ;
     RECT  2.304 33.151 2.79 33.511 ;
     RECT  3.6 33.421 14.454 33.511 ;
     RECT  2.304 33.511 14.454 33.611 ;
     RECT  0.108 33.499 0.126 33.629 ;
     RECT  19.656 33.449 35.73 33.781 ;
     RECT  36.504 33.341 36.522 33.781 ;
     RECT  37.368 34.027 37.386 34.187 ;
     RECT  3.6 33.611 14.454 34.231 ;
     RECT  15.804 33.449 18.897 34.231 ;
     RECT  19.656 33.781 36.522 34.231 ;
     RECT  3.6 34.231 14.49 34.357 ;
     RECT  0.324 34.219 0.342 34.363 ;
     RECT  15.588 34.231 36.522 34.385 ;
     RECT  0.108 34.363 0.342 34.397 ;
     RECT  38.196 33.499 38.79 34.397 ;
     RECT  3.6 34.357 14.526 34.429 ;
     RECT  15.588 34.385 36.126 34.429 ;
     RECT  2.304 33.611 2.862 34.465 ;
     RECT  3.6 34.429 14.562 34.465 ;
     RECT  0.108 34.397 0.126 34.493 ;
     RECT  2.304 34.465 14.562 34.501 ;
     RECT  2.304 34.501 14.598 34.555 ;
     RECT  2.268 34.555 14.598 34.735 ;
     RECT  15.48 34.429 36.126 34.735 ;
     RECT  37.548 34.555 37.602 34.781 ;
     RECT  37.548 34.781 37.566 34.961 ;
     RECT  2.268 34.735 36.126 35.159 ;
     RECT  38.736 34.397 38.79 35.267 ;
     RECT  2.304 35.159 36.126 35.269 ;
     RECT  37.476 35.419 37.494 35.573 ;
     RECT  2.304 35.269 36.522 36.005 ;
     RECT  37.512 35.947 37.53 36.319 ;
     RECT  38.7 35.473 38.718 36.475 ;
     RECT  38.7 36.475 38.79 36.605 ;
     RECT  37.512 36.319 37.602 36.652 ;
     RECT  2.304 36.005 36.162 36.653 ;
     RECT  0.108 36.391 0.126 36.701 ;
     RECT  2.304 36.653 36.126 36.779 ;
     RECT  37.476 36.652 37.602 36.859 ;
     RECT  38.7 36.605 38.718 36.859 ;
     RECT  2.412 36.779 36.126 37.049 ;
     RECT  37.476 36.859 38.718 37.057 ;
     RECT  36.972 37.057 38.718 37.193 ;
     RECT  0.54 36.931 0.558 37.229 ;
     RECT  37.548 37.193 38.718 37.463 ;
     RECT  2.415 37.049 36.126 37.741 ;
     RECT  0.144 37.627 0.162 37.757 ;
     RECT  2.415 37.741 36.594 37.931 ;
     RECT  2.415 37.931 36.522 38.107 ;
     RECT  37.584 37.463 38.718 38.201 ;
     RECT  38.088 38.201 38.718 38.251 ;
     RECT  2.304 38.107 36.522 38.399 ;
     RECT  38.088 38.251 38.79 38.669 ;
     RECT  2.415 38.399 36.522 38.677 ;
     RECT  2.415 38.677 36.594 38.939 ;
     RECT  2.415 38.939 36.522 39.163 ;
     RECT  2.304 39.163 36.522 39.209 ;
     RECT  2.415 39.209 36.522 39.245 ;
     RECT  2.415 39.245 35.55 39.893 ;
     RECT  36.504 39.245 36.522 39.893 ;
     RECT  2.415 39.893 35.478 40.019 ;
     RECT  0.108 40.027 0.126 40.064 ;
     RECT  2.415 40.019 35.442 40.219 ;
     RECT  38.196 38.669 38.79 40.253 ;
     RECT  2.304 40.219 35.442 40.801 ;
     RECT  37.476 40.363 37.494 40.973 ;
     RECT  2.304 40.801 35.514 40.981 ;
     RECT  37.548 41.083 37.566 41.171 ;
     RECT  2.304 40.981 35.73 41.251 ;
     RECT  2.304 41.251 35.838 41.341 ;
     RECT  38.592 40.253 38.79 41.419 ;
     RECT  2.304 41.341 35.982 41.485 ;
     RECT  37.584 41.419 38.79 41.837 ;
     RECT  2.304 41.485 36.378 41.909 ;
     RECT  2.304 41.909 36.018 42.061 ;
     RECT  2.268 42.061 36.018 42.173 ;
     RECT  2.304 42.173 36.018 43.099 ;
     RECT  2.268 43.099 36.018 43.141 ;
     RECT  38.196 41.837 38.79 43.195 ;
     RECT  2.268 43.141 36.45 43.229 ;
     RECT  2.304 43.229 36.45 43.259 ;
     RECT  0.54 43.303 0.558 43.565 ;
     RECT  37.584 43.195 38.79 43.661 ;
     RECT  2.304 43.259 35.838 43.835 ;
     RECT  37.584 43.661 38.214 43.915 ;
     RECT  2.304 43.835 35.802 43.979 ;
     RECT  37.512 43.915 38.214 44.213 ;
     RECT  37.548 44.213 38.214 44.285 ;
     RECT  18.576 43.979 35.802 44.375 ;
     RECT  0.108 44.251 0.126 44.381 ;
     RECT  26.316 44.375 35.802 44.609 ;
     RECT  36.576 44.419 36.594 44.609 ;
     RECT  38.592 44.443 38.79 44.717 ;
     RECT  38.592 44.717 38.718 45.005 ;
     RECT  37.548 44.285 37.566 45.031 ;
     RECT  37.548 45.031 38.214 45.221 ;
     RECT  2.304 43.979 17.838 45.229 ;
     RECT  18.576 44.375 25.542 45.229 ;
     RECT  2.304 45.229 25.542 45.301 ;
     RECT  26.316 44.609 35.658 45.301 ;
     RECT  37.008 45.265 37.026 45.341 ;
     RECT  2.304 45.301 35.658 45.491 ;
     RECT  2.304 45.491 35.586 45.689 ;
     RECT  0.108 45.643 0.126 45.773 ;
     RECT  38.196 45.221 38.214 45.835 ;
     RECT  38.196 45.835 38.79 46.397 ;
     RECT  37.512 46.555 37.53 46.643 ;
     RECT  2.304 45.689 35.55 46.651 ;
     RECT  36.324 46.309 36.342 46.651 ;
     RECT  2.304 46.651 36.342 46.913 ;
     RECT  3.564 46.913 36.342 47.119 ;
     RECT  38.772 46.397 38.79 47.183 ;
     RECT  0.144 47.083 0.162 47.213 ;
     RECT  3.564 47.119 36.414 47.309 ;
     RECT  37.548 47.227 37.566 47.381 ;
     RECT  0.54 47.281 0.558 47.453 ;
     RECT  37.584 47.416 37.602 47.453 ;
     RECT  38.196 47.551 38.718 47.789 ;
     RECT  2.304 46.913 2.79 47.803 ;
     RECT  3.564 47.309 36.126 47.803 ;
     RECT  2.304 47.803 36.126 47.849 ;
     RECT  2.415 47.849 36.126 47.885 ;
     RECT  2.415 47.885 35.91 48.569 ;
     RECT  2.415 48.569 3.258 48.667 ;
     RECT  38.196 47.789 38.286 48.667 ;
     RECT  3.996 48.569 35.91 48.775 ;
     RECT  38.196 48.667 38.79 48.859 ;
     RECT  3.996 48.775 36.198 49.045 ;
     RECT  37.584 48.859 38.79 49.229 ;
     RECT  2.304 48.667 3.258 49.441 ;
     RECT  3.996 49.045 36.45 49.441 ;
     RECT  37.584 49.229 37.602 49.541 ;
     RECT  2.304 49.441 36.45 50.059 ;
     RECT  2.304 50.059 36.522 50.251 ;
     RECT  2.304 50.251 36.99 50.288 ;
     RECT  2.415 50.288 36.99 50.351 ;
     RECT  38.7 49.229 38.79 50.395 ;
     RECT  38.196 50.395 38.79 50.621 ;
     RECT  0.108 50.701 0.126 50.813 ;
     RECT  2.415 50.351 36.522 51.245 ;
     RECT  22.5 51.245 36.522 51.269 ;
     RECT  2.415 51.245 21.726 51.307 ;
     RECT  2.304 51.307 21.726 51.359 ;
     RECT  37.584 50.971 37.602 51.431 ;
     RECT  4.536 51.359 21.726 51.467 ;
     RECT  36.504 51.269 36.522 51.499 ;
     RECT  38.772 50.621 38.79 51.691 ;
     RECT  36.504 51.499 36.99 51.701 ;
     RECT  36.504 51.701 36.522 52.007 ;
     RECT  0.54 51.511 0.558 52.061 ;
     RECT  4.536 51.467 21.69 52.213 ;
     RECT  22.5 51.269 35.766 52.213 ;
     RECT  37.584 52.171 37.602 52.313 ;
     RECT  4.536 52.213 35.766 52.321 ;
     RECT  4.536 52.321 35.946 52.411 ;
     RECT  38.7 51.691 38.79 52.591 ;
     RECT  4.464 52.411 35.946 52.745 ;
     RECT  2.304 51.359 3.69 52.753 ;
     RECT  2.268 52.753 3.69 52.861 ;
     RECT  4.464 52.745 35.838 52.861 ;
     RECT  2.268 52.861 35.838 52.925 ;
     RECT  2.304 52.925 35.838 52.979 ;
     RECT  38.232 52.591 38.79 52.979 ;
     RECT  38.232 52.979 38.358 53.059 ;
     RECT  38.196 53.059 38.358 53.083 ;
     RECT  0.54 52.861 0.558 53.117 ;
     RECT  37.584 53.083 38.358 53.419 ;
     RECT  37.368 53.419 38.358 53.549 ;
     RECT  0.108 53.491 0.126 53.645 ;
     RECT  37.584 53.549 38.358 53.933 ;
     RECT  2.304 52.979 35.298 53.941 ;
     RECT  38.232 53.933 38.358 53.981 ;
     RECT  2.304 53.941 36.234 54.095 ;
     RECT  2.304 54.095 35.406 54.221 ;
     RECT  36.216 54.095 36.234 54.239 ;
     RECT  2.304 54.221 35.298 54.437 ;
     RECT  36.504 54.283 36.522 54.437 ;
     RECT  37.08 54.445 37.098 54.509 ;
     RECT  38.304 53.981 38.358 54.751 ;
     RECT  38.196 54.751 38.358 55.003 ;
     RECT  38.196 55.003 38.79 55.373 ;
     RECT  2.304 54.437 35.262 55.525 ;
     RECT  37.008 55.183 37.026 55.76 ;
     RECT  2.304 55.525 35.658 55.921 ;
     RECT  37.584 55.867 37.602 56.021 ;
     RECT  2.304 55.921 35.73 56.065 ;
     RECT  38.34 55.373 38.79 56.101 ;
     RECT  2.304 56.065 35.91 56.263 ;
     RECT  2.304 56.263 35.982 56.399 ;
     RECT  37.62 56.101 38.79 56.621 ;
     RECT  18.504 56.399 35.982 56.641 ;
     RECT  18.504 56.641 36.234 56.731 ;
     RECT  38.196 56.621 38.79 56.867 ;
     RECT  38.196 56.867 38.754 56.957 ;
     RECT  2.304 56.399 17.73 57.181 ;
     RECT  18.504 56.731 36.342 57.181 ;
     RECT  2.304 57.181 36.342 57.307 ;
     RECT  2.304 57.307 36.522 57.443 ;
     RECT  0.54 57.343 0.558 57.541 ;
     RECT  2.304 57.443 36.306 57.839 ;
     RECT  0.108 57.541 0.558 57.869 ;
     RECT  38.772 57.643 38.79 57.947 ;
     RECT  37.512 57.835 37.53 57.979 ;
     RECT  2.412 57.839 36.306 58.145 ;
     RECT  37.512 57.979 37.566 58.189 ;
     RECT  0.144 57.869 0.558 58.205 ;
     RECT  2.412 58.145 35.946 58.379 ;
     RECT  0.144 58.205 0.162 58.397 ;
     RECT  37.512 58.189 38.25 58.531 ;
     RECT  37.044 58.531 38.25 58.541 ;
     RECT  2.412 58.379 35.91 58.733 ;
     RECT  2.412 58.733 2.862 58.891 ;
     RECT  37.044 58.541 37.566 59.224 ;
     RECT  37.008 59.224 37.566 59.261 ;
     RECT  2.304 58.891 2.862 59.467 ;
     RECT  3.6 58.733 35.91 59.467 ;
     RECT  37.548 59.261 37.566 59.531 ;
     RECT  38.772 59.563 38.79 59.575 ;
     RECT  38.736 59.575 38.79 59.639 ;
     RECT  2.304 59.467 35.91 59.701 ;
     RECT  38.736 59.639 38.754 59.947 ;
     RECT  2.304 59.701 36.018 60.139 ;
     RECT  0.324 60.139 0.342 60.283 ;
     RECT  2.304 60.139 36.522 60.341 ;
     RECT  0.108 60.283 0.342 60.413 ;
     RECT  38.196 59.947 38.754 60.475 ;
     RECT  2.304 60.341 32.994 60.539 ;
     RECT  33.768 60.341 36.522 60.683 ;
     RECT  0.54 60.961 0.558 61.037 ;
     RECT  33.768 60.683 35.982 61.087 ;
     RECT  2.412 60.539 32.994 61.159 ;
     RECT  33.732 61.087 35.982 61.159 ;
     RECT  2.412 61.159 35.982 61.321 ;
     RECT  2.304 61.321 35.982 61.465 ;
     RECT  37.044 61.429 37.062 61.465 ;
     RECT  2.304 61.465 37.062 61.933 ;
     RECT  38.196 60.475 38.79 61.933 ;
     RECT  1.152 61.867 1.17 61.997 ;
     RECT  2.304 61.933 38.79 62.159 ;
     RECT  2.412 62.159 38.79 62.231 ;
     RECT  2.412 62.231 38.214 62.303 ;
     RECT  2.412 62.303 36.378 62.429 ;
     RECT  0.108 62.491 0.126 62.621 ;
     RECT  37.512 62.303 38.214 62.717 ;
     RECT  2.412 62.429 36.342 62.923 ;
     RECT  37.512 62.717 37.602 63.113 ;
     RECT  38.772 63.049 38.79 63.149 ;
     RECT  2.304 62.923 36.342 63.293 ;
     RECT  4.464 63.293 36.342 63.391 ;
     RECT  4.464 63.391 36.378 63.653 ;
     RECT  37.584 63.113 37.602 63.751 ;
     RECT  38.7 63.643 38.718 63.751 ;
     RECT  4.464 63.653 36.09 63.821 ;
     RECT  37.584 63.751 38.718 63.979 ;
     RECT  2.304 63.293 3.654 64.049 ;
     RECT  2.415 64.049 3.654 64.165 ;
     RECT  4.464 63.821 35.766 64.165 ;
     RECT  37.584 63.979 38.79 64.171 ;
     RECT  37.512 64.171 38.79 64.193 ;
     RECT  2.415 64.165 35.766 64.391 ;
     RECT  0.54 64.291 0.558 64.541 ;
     RECT  37.512 64.193 38.25 64.733 ;
     RECT  2.415 64.391 2.97 64.781 ;
     RECT  2.415 64.781 2.934 64.831 ;
     RECT  3.708 64.391 35.766 64.831 ;
     RECT  37.512 64.733 37.53 64.891 ;
     RECT  3.708 64.831 35.91 64.925 ;
     RECT  36.972 64.891 37.53 64.931 ;
     RECT  37.08 64.931 37.53 65.069 ;
     RECT  37.512 65.069 37.53 65.273 ;
     RECT  2.304 64.831 2.934 65.309 ;
     RECT  2.415 65.309 2.934 65.551 ;
     RECT  3.708 64.925 35.802 65.551 ;
     RECT  0.108 65.371 0.126 65.597 ;
     RECT  37.62 65.515 37.638 65.597 ;
     RECT  38.772 65.011 38.79 65.713 ;
     RECT  2.415 65.551 35.802 65.741 ;
     RECT  0.144 65.995 0.162 66.125 ;
     RECT  36.576 66.091 36.594 66.253 ;
     RECT  3.672 65.741 35.802 66.325 ;
     RECT  36.576 66.253 36.666 66.325 ;
     RECT  3.672 66.325 36.666 66.389 ;
     RECT  2.415 65.741 2.934 66.475 ;
     RECT  3.672 66.389 36.234 66.475 ;
     RECT  38.196 65.713 38.79 66.475 ;
     RECT  2.415 66.475 36.234 66.619 ;
     RECT  37.512 66.475 38.79 66.623 ;
     RECT  2.304 66.619 36.234 66.749 ;
     RECT  38.124 66.623 38.79 67.361 ;
     RECT  38.124 67.361 38.754 67.433 ;
     RECT  2.304 66.749 6.03 67.531 ;
     RECT  6.84 66.749 36.234 67.531 ;
     RECT  38.556 67.433 38.754 67.712 ;
     RECT  2.304 67.531 36.522 67.829 ;
     RECT  2.304 67.829 36.054 67.973 ;
     RECT  38.556 67.712 38.718 68.189 ;
     RECT  37.584 67.864 37.602 68.251 ;
     RECT  2.304 67.973 35.946 68.279 ;
     RECT  2.304 68.279 6.246 68.405 ;
     RECT  37.584 68.251 38.25 68.587 ;
     RECT  0.144 68.683 0.162 68.957 ;
     RECT  7.056 68.279 35.946 69.061 ;
     RECT  2.304 68.405 3.042 69.151 ;
     RECT  3.78 68.405 6.246 69.151 ;
     RECT  6.984 69.061 35.946 69.295 ;
     RECT  37.548 68.587 38.25 69.307 ;
     RECT  37.548 69.307 38.718 69.521 ;
     RECT  2.304 69.151 6.246 69.565 ;
     RECT  6.984 69.295 36.63 69.565 ;
     RECT  38.196 69.521 38.718 69.565 ;
     RECT  2.304 69.565 36.63 70.507 ;
     RECT  1.98 70.507 36.63 70.799 ;
     RECT  37.368 70.699 37.386 70.907 ;
     RECT  38.196 69.565 38.79 70.915 ;
     RECT  37.512 70.915 38.79 71.069 ;
     RECT  1.98 70.799 35.946 71.249 ;
     RECT  2.016 71.249 35.946 71.261 ;
     RECT  37.512 71.069 37.638 71.453 ;
     RECT  2.415 71.261 35.946 71.617 ;
     RECT  2.415 71.617 36.342 72.149 ;
     RECT  0.108 71.659 0.126 72.317 ;
     RECT  2.415 72.149 36.234 72.419 ;
     RECT  2.415 72.419 3.258 72.475 ;
     RECT  38.772 71.069 38.79 72.509 ;
     RECT  37.512 71.453 37.53 72.535 ;
     RECT  4.068 72.419 36.234 72.689 ;
     RECT  0.144 72.619 0.162 72.841 ;
     RECT  37.512 72.535 38.214 73.103 ;
     RECT  4.068 72.689 35.91 73.201 ;
     RECT  0.144 72.841 0.558 73.325 ;
     RECT  37.584 73.103 38.214 73.373 ;
     RECT  2.304 72.475 3.258 73.381 ;
     RECT  4.032 73.201 35.91 73.381 ;
     RECT  0.54 73.325 0.558 73.565 ;
     RECT  2.304 73.381 35.91 73.651 ;
     RECT  2.304 73.651 36.594 73.841 ;
     RECT  37.584 73.373 37.602 74.191 ;
     RECT  38.736 73.867 38.79 74.191 ;
     RECT  37.584 74.191 38.79 74.381 ;
     RECT  0.18 74.587 0.198 74.623 ;
     RECT  0.18 74.623 0.27 74.669 ;
     RECT  0.18 74.669 0.198 74.731 ;
     RECT  2.304 73.841 36.162 74.731 ;
     RECT  0.108 74.731 0.198 74.759 ;
     RECT  38.196 74.381 38.79 74.765 ;
     RECT  0.108 74.759 0.126 74.768 ;
     RECT  2.304 74.731 36.594 74.993 ;
     RECT  2.304 74.993 5.634 75.119 ;
     RECT  38.664 74.765 38.79 75.533 ;
     RECT  38.664 75.533 38.754 75.569 ;
     RECT  37.584 75.643 37.602 75.803 ;
     RECT  6.516 74.993 35.874 75.811 ;
     RECT  2.304 75.119 3.726 75.901 ;
     RECT  4.536 75.119 5.634 75.901 ;
     RECT  2.304 75.901 5.634 75.929 ;
     RECT  38.664 75.569 38.682 76.009 ;
     RECT  37.62 76.009 38.682 76.013 ;
     RECT  6.516 75.811 35.91 76.045 ;
     RECT  2.415 75.929 5.634 76.171 ;
     RECT  6.516 76.045 36.486 76.171 ;
     RECT  37.62 76.013 38.214 76.205 ;
     RECT  0.108 76.171 0.126 76.235 ;
     RECT  37.62 76.205 37.638 76.349 ;
     RECT  2.415 76.171 36.486 76.351 ;
     RECT  2.415 76.351 36.522 76.541 ;
     RECT  2.415 76.541 36.486 76.589 ;
     RECT  2.415 76.589 32.742 76.613 ;
     RECT  33.624 76.589 36.486 76.649 ;
     RECT  33.624 76.649 35.658 76.739 ;
     RECT  36.468 76.649 36.486 76.739 ;
     RECT  0.144 76.699 0.162 76.829 ;
     RECT  2.415 76.613 32.706 76.981 ;
     RECT  37.584 77.035 37.602 77.081 ;
     RECT  38.196 77.089 38.214 77.131 ;
     RECT  2.304 76.981 32.706 77.279 ;
     RECT  2.415 77.279 32.706 77.395 ;
     RECT  33.624 76.739 35.622 77.593 ;
     RECT  2.415 77.395 32.742 77.629 ;
     RECT  33.624 77.593 36.054 77.629 ;
     RECT  2.415 77.629 36.054 77.657 ;
     RECT  3.6 77.657 36.054 77.665 ;
     RECT  0.108 77.659 0.126 77.789 ;
     RECT  3.6 77.665 36.126 77.819 ;
     RECT  38.196 77.131 38.79 77.999 ;
     RECT  38.628 77.999 38.79 78.317 ;
     RECT  2.415 77.657 2.754 78.403 ;
     RECT  3.6 77.819 35.946 78.403 ;
     RECT  1.152 78.283 1.17 78.413 ;
     RECT  2.415 78.403 35.946 78.601 ;
     RECT  2.304 78.601 35.946 78.653 ;
     RECT  38.628 78.317 38.718 78.653 ;
     RECT  37.548 78.427 37.566 78.781 ;
     RECT  38.628 78.653 38.646 78.781 ;
     RECT  37.548 78.781 38.646 78.845 ;
     RECT  3.816 78.653 35.946 78.943 ;
     RECT  2.304 78.653 2.97 79.241 ;
     RECT  3.816 78.943 36.09 79.241 ;
     RECT  37.548 78.845 38.25 79.241 ;
     RECT  3.816 79.241 35.946 79.411 ;
     RECT  37.62 79.241 38.25 80.011 ;
     RECT  2.304 79.241 2.697 80.095 ;
     RECT  3.42 79.411 35.946 80.095 ;
     RECT  0.108 79.675 0.126 80.237 ;
     RECT  1.26 80.395 1.278 80.573 ;
     RECT  2.304 80.095 35.946 80.591 ;
     RECT  37.62 80.011 38.79 80.765 ;
     RECT  1.152 80.905 1.242 81.053 ;
     RECT  5.004 80.591 35.946 81.103 ;
     RECT  5.004 81.103 36.018 81.175 ;
     RECT  1.224 81.053 1.242 81.197 ;
     RECT  37.512 81.067 37.53 81.203 ;
     RECT  2.304 80.591 4.266 81.329 ;
     RECT  5.004 81.175 36.162 81.329 ;
     RECT  38.7 80.765 38.79 81.329 ;
     RECT  2.415 81.329 4.266 81.481 ;
     RECT  5.004 81.329 36.018 81.481 ;
     RECT  2.415 81.481 36.018 81.599 ;
     RECT  0.144 81.787 0.162 81.965 ;
     RECT  2.415 81.599 35.982 82.111 ;
     RECT  37.584 81.949 37.602 82.219 ;
     RECT  38.736 81.329 38.79 82.219 ;
     RECT  0.108 82.315 0.126 82.445 ;
     RECT  37.584 82.219 38.79 82.541 ;
     RECT  2.304 82.111 35.982 82.561 ;
     RECT  37.584 82.541 37.602 82.751 ;
     RECT  2.304 82.561 36.018 82.795 ;
     RECT  2.304 82.795 36.162 82.859 ;
     RECT  2.304 82.859 35.874 83.057 ;
     RECT  2.304 83.057 35.802 83.255 ;
     RECT  38.556 82.541 38.79 83.335 ;
     RECT  38.196 83.335 38.79 83.669 ;
     RECT  38.232 83.669 38.79 83.789 ;
     RECT  1.152 83.227 1.17 83.933 ;
     RECT  38.628 83.789 38.79 83.933 ;
     RECT  37.476 84.091 37.494 84.173 ;
     RECT  2.304 83.255 35.694 84.181 ;
     RECT  2.304 84.181 36.054 84.451 ;
     RECT  2.304 84.451 36.09 84.619 ;
     RECT  2.304 84.619 36.522 84.713 ;
     RECT  2.304 84.713 36.018 85.109 ;
     RECT  38.628 83.933 38.718 85.229 ;
     RECT  2.415 85.109 36.018 85.379 ;
     RECT  36.972 84.811 37.026 85.451 ;
     RECT  0.144 85.339 0.162 85.469 ;
     RECT  37.512 85.483 37.53 85.531 ;
     RECT  2.415 85.379 35.838 85.867 ;
     RECT  2.304 85.867 35.838 85.955 ;
     RECT  37.512 85.531 38.214 86.063 ;
     RECT  0.108 86.011 0.126 86.261 ;
     RECT  38.124 86.063 38.214 86.269 ;
     RECT  38.124 86.269 38.286 86.395 ;
     RECT  38.124 86.395 38.718 86.539 ;
     RECT  38.124 86.539 38.79 86.639 ;
     RECT  38.124 86.639 38.286 86.765 ;
     RECT  2.304 85.955 35.694 86.801 ;
     RECT  37.044 86.845 37.062 86.957 ;
     RECT  38.124 86.765 38.214 87.115 ;
     RECT  2.304 86.801 3.042 87.197 ;
     RECT  3.78 86.801 35.694 87.421 ;
     RECT  2.304 87.197 2.862 87.437 ;
     RECT  0.144 87.451 0.162 87.581 ;
     RECT  37.584 87.115 38.214 87.595 ;
     RECT  2.304 87.437 2.826 87.629 ;
     RECT  3.78 87.421 35.73 87.655 ;
     RECT  2.304 87.629 2.697 87.853 ;
     RECT  3.78 87.655 36.45 87.925 ;
     RECT  1.98 87.853 2.697 88.013 ;
     RECT  37.584 87.595 38.79 88.013 ;
     RECT  3.708 87.925 36.45 88.079 ;
     RECT  3.708 88.079 35.874 88.115 ;
     RECT  37.584 88.013 37.602 88.349 ;
     RECT  3.708 88.115 35.802 88.421 ;
     RECT  2.304 88.013 2.697 88.429 ;
     RECT  2.304 88.429 2.934 88.465 ;
     RECT  3.708 88.421 35.73 88.465 ;
     RECT  2.304 88.465 35.73 88.619 ;
     RECT  0.108 88.747 0.126 88.877 ;
     RECT  37.008 88.735 37.026 88.877 ;
     RECT  2.304 88.619 35.694 88.889 ;
     RECT  2.304 88.889 35.622 88.925 ;
     RECT  38.772 88.013 38.79 89.035 ;
     RECT  38.736 89.035 38.79 89.179 ;
     RECT  3.744 88.925 35.622 89.501 ;
     RECT  36.576 89.581 36.594 89.771 ;
     RECT  2.304 88.925 2.934 89.845 ;
     RECT  3.744 89.501 35.478 89.845 ;
     RECT  2.304 89.845 35.478 89.969 ;
     RECT  2.304 89.969 35.19 90.005 ;
     RECT  38.196 89.179 38.79 90.509 ;
     RECT  2.304 90.005 35.097 90.571 ;
     RECT  38.196 90.509 38.754 90.581 ;
     RECT  38.196 90.581 38.286 90.653 ;
     RECT  1.98 90.571 35.097 90.779 ;
     RECT  37.008 90.895 37.026 90.989 ;
     RECT  3.852 90.779 35.097 91.049 ;
     RECT  1.98 90.779 3.006 91.085 ;
     RECT  3.96 91.049 35.097 91.085 ;
     RECT  4.284 91.085 35.097 91.157 ;
     RECT  38.196 90.653 38.25 91.181 ;
     RECT  4.392 91.157 35.097 91.193 ;
     RECT  38.196 91.181 38.214 91.193 ;
     RECT  2.304 91.085 3.006 91.319 ;
     RECT  5.115 91.193 35.097 91.319 ;
     RECT  34.776 91.319 35.097 91.463 ;
     RECT  5.115 91.319 33.822 91.661 ;
     RECT  7.416 91.661 33.822 91.895 ;
     RECT  5.115 91.661 5.742 92.039 ;
     RECT  38.772 92.107 38.79 92.237 ;
     RECT  7.416 91.895 33.354 92.309 ;
     RECT  7.416 92.309 14.886 92.395 ;
     RECT  7.38 92.395 14.886 92.399 ;
     RECT  15.696 92.309 33.354 92.399 ;
     RECT  7.38 92.399 12.474 92.435 ;
     RECT  15.696 92.399 32.397 92.435 ;
     RECT  4.176 92.347 4.194 92.471 ;
     RECT  20.844 92.435 22.878 92.471 ;
     RECT  23.616 92.435 32.397 92.471 ;
     RECT  5.115 92.039 5.634 92.515 ;
     RECT  10.116 92.435 12.006 92.543 ;
     RECT  15.696 92.435 20.034 92.543 ;
     RECT  5.076 92.515 5.634 92.551 ;
     RECT  2.415 91.319 2.697 92.627 ;
     RECT  23.616 92.471 24.297 92.627 ;
     RECT  25.056 92.471 32.397 92.627 ;
     RECT  34.815 91.463 35.097 92.627 ;
     RECT  4.356 92.551 5.634 92.669 ;
     RECT  7.416 92.435 9.306 92.669 ;
     RECT  10.116 92.543 11.862 92.669 ;
     RECT  13.215 92.399 14.886 92.669 ;
     RECT  15.696 92.543 17.658 92.669 ;
     RECT  18.432 92.543 20.034 92.669 ;
     RECT  20.844 92.471 22.698 92.669 ;
     RECT  23.616 92.627 24.105 92.669 ;
     RECT  25.056 92.627 32.274 92.669 ;
     RECT  33.156 92.399 33.354 92.669 ;
     RECT  13.215 92.669 14.49 92.675 ;
     RECT  5.115 92.669 5.634 92.705 ;
     RECT  14.292 92.675 14.49 92.705 ;
     RECT  25.236 92.669 27.702 92.705 ;
     RECT  28.8 92.669 29.505 92.705 ;
     RECT  30.42 92.669 32.274 92.705 ;
     RECT  14.292 92.705 14.31 92.741 ;
     RECT  15.696 92.669 16.902 92.741 ;
     RECT  18.54 92.669 19.206 92.741 ;
     RECT  23.976 92.669 24.105 92.741 ;
     RECT  4.356 92.669 4.374 92.777 ;
     RECT  7.416 92.669 8.586 92.777 ;
     RECT  10.116 92.669 10.605 92.777 ;
     RECT  25.236 92.705 27.558 92.777 ;
     RECT  33.336 92.669 33.354 92.777 ;
     RECT  7.815 92.777 8.586 92.813 ;
     RECT  13.215 92.675 13.338 92.813 ;
     RECT  20.016 92.669 20.034 92.813 ;
     RECT  25.236 92.777 25.794 92.813 ;
     RECT  26.715 92.777 27.054 92.813 ;
     RECT  30.42 92.705 32.205 92.813 ;
     RECT  10.188 92.777 10.605 92.849 ;
     RECT  18.615 92.741 18.954 92.849 ;
     RECT  21.315 92.669 22.662 92.849 ;
     RECT  29.088 92.705 29.505 92.849 ;
     RECT  31.536 92.813 32.205 92.849 ;
     RECT  15.696 92.741 16.074 92.861 ;
     RECT  2.415 92.627 2.505 92.897 ;
     RECT  5.115 92.705 5.31 92.897 ;
     RECT  7.815 92.813 7.905 92.897 ;
     RECT  10.515 92.849 10.605 92.897 ;
     RECT  13.215 92.813 13.305 92.897 ;
     RECT  15.915 92.861 16.074 92.897 ;
     RECT  18.615 92.849 18.705 92.897 ;
     RECT  21.315 92.849 21.405 92.897 ;
     RECT  24.015 92.741 24.105 92.897 ;
     RECT  26.715 92.813 26.805 92.897 ;
     RECT  29.415 92.849 29.505 92.897 ;
     RECT  32.115 92.849 32.205 92.897 ;
     RECT  34.815 92.627 34.905 92.897 ;
     RECT  5.292 92.897 5.31 93.149 ;
     RECT  16.056 92.897 16.074 94.981 ;
    LAYER M4 ;
     RECT  0.084 1.056 0.227 1.08 ;
     RECT  0.06 1.08 0.227 1.248 ;
     RECT  0.084 1.248 0.227 1.272 ;
     RECT  0.06 1.272 0.227 1.44 ;
     RECT  0.084 1.44 0.227 1.464 ;
     RECT  0.06 1.464 0.227 1.584 ;
     RECT  0.084 1.584 0.227 1.608 ;
     RECT  0.06 1.608 0.227 1.776 ;
     RECT  0.084 1.776 0.227 1.8 ;
     RECT  0.06 1.8 0.227 1.968 ;
     RECT  0.084 1.968 0.227 1.992 ;
     RECT  0.06 1.992 0.227 2.112 ;
     RECT  0.084 2.112 0.227 2.136 ;
     RECT  0.06 2.136 0.227 2.304 ;
     RECT  0.084 2.304 0.227 2.328 ;
     RECT  0.06 2.328 0.227 2.496 ;
     RECT  0.084 2.496 0.227 2.52 ;
     RECT  0.06 2.52 0.227 2.64 ;
     RECT  0.084 2.64 0.227 2.664 ;
     RECT  0.06 2.664 0.227 2.832 ;
     RECT  0.084 2.832 0.227 2.856 ;
     RECT  0.06 2.856 0.227 3.024 ;
     RECT  0.084 3.024 0.227 3.048 ;
     RECT  0.06 3.048 0.227 3.168 ;
     RECT  0.084 3.168 0.227 3.192 ;
     RECT  0.06 3.192 0.227 3.36 ;
     RECT  0.084 3.36 0.227 3.384 ;
     RECT  0.06 3.384 0.227 3.552 ;
     RECT  0.084 3.552 0.227 3.576 ;
     RECT  0.06 3.576 0.227 3.744 ;
     RECT  0.084 3.744 0.227 3.768 ;
     RECT  0.06 3.768 0.227 3.888 ;
     RECT  0.084 3.888 0.227 3.912 ;
     RECT  0.06 3.912 0.227 4.08 ;
     RECT  0.084 4.08 0.227 4.104 ;
     RECT  0.06 4.104 0.227 4.272 ;
     RECT  0.084 4.272 0.227 4.296 ;
     RECT  0.06 4.296 0.227 4.416 ;
     RECT  0.084 4.416 0.227 4.44 ;
     RECT  0.06 4.44 0.227 4.608 ;
     RECT  0.084 4.608 0.227 4.632 ;
     RECT  0.06 4.632 0.227 4.8 ;
     RECT  0.084 4.8 0.227 4.824 ;
     RECT  0.06 4.824 0.227 4.944 ;
     RECT  0.084 4.944 0.227 4.968 ;
     RECT  0.06 4.968 0.227 5.136 ;
     RECT  0.084 5.136 0.227 5.16 ;
     RECT  0.06 5.16 0.227 5.328 ;
     RECT  0.084 5.328 0.227 5.352 ;
     RECT  0.06 5.352 0.227 5.472 ;
     RECT  0.084 5.472 0.227 5.496 ;
     RECT  0.06 5.496 0.227 5.664 ;
     RECT  0.084 5.664 0.227 5.688 ;
     RECT  0.06 5.688 0.227 5.856 ;
     RECT  0.084 5.856 0.227 5.88 ;
     RECT  0.06 5.88 0.227 6 ;
     RECT  0.084 6 0.227 6.024 ;
     RECT  0.06 6.024 0.227 6.192 ;
     RECT  0.084 6.192 0.227 6.216 ;
     RECT  0.06 6.216 0.227 6.384 ;
     RECT  0.084 6.384 0.227 6.408 ;
     RECT  0.06 6.408 0.227 6.528 ;
     RECT  0.084 6.528 0.227 6.552 ;
     RECT  0.06 6.552 0.227 6.72 ;
     RECT  0.084 6.72 0.227 6.744 ;
     RECT  0.06 6.744 0.227 6.912 ;
     RECT  0.084 6.912 0.227 6.936 ;
     RECT  0.06 6.936 0.227 7.056 ;
     RECT  0.084 7.056 0.227 7.08 ;
     RECT  0.06 7.08 0.227 7.248 ;
     RECT  0.084 7.248 0.227 7.272 ;
     RECT  0.06 7.272 0.227 7.44 ;
     RECT  0.084 7.44 0.227 7.464 ;
     RECT  0.06 7.464 0.227 7.584 ;
     RECT  0.084 7.584 0.227 7.608 ;
     RECT  0.06 7.608 0.227 7.776 ;
     RECT  0.084 7.776 0.227 7.8 ;
     RECT  0.06 7.8 0.227 7.968 ;
     RECT  0.084 7.968 0.227 7.992 ;
     RECT  0.06 7.992 0.227 8.112 ;
     RECT  0.084 8.112 0.227 8.136 ;
     RECT  0.06 8.136 0.227 8.304 ;
     RECT  0.084 8.304 0.227 8.328 ;
     RECT  0.06 8.328 0.227 8.496 ;
     RECT  0.084 8.496 0.227 8.52 ;
     RECT  0.06 8.52 0.227 8.64 ;
     RECT  0.084 8.64 0.227 8.664 ;
     RECT  0.06 8.664 0.227 8.832 ;
     RECT  0.084 8.832 0.227 8.856 ;
     RECT  0.06 8.856 0.227 9.024 ;
     RECT  0.084 9.024 0.227 9.048 ;
     RECT  0.06 9.048 0.227 9.168 ;
     RECT  0.084 9.168 0.227 9.192 ;
     RECT  0.06 9.192 0.227 9.36 ;
     RECT  0.084 9.36 0.227 9.384 ;
     RECT  0.06 9.384 0.227 9.552 ;
     RECT  0.084 9.552 0.227 9.576 ;
     RECT  0.06 9.576 0.227 9.696 ;
     RECT  0.084 9.696 0.227 9.72 ;
     RECT  0.06 9.72 0.227 9.888 ;
     RECT  0.084 9.888 0.227 9.912 ;
     RECT  0.06 9.912 0.227 10.08 ;
     RECT  0.084 10.08 0.227 10.104 ;
     RECT  0.06 10.104 0.227 10.224 ;
     RECT  0.084 10.224 0.227 10.248 ;
     RECT  0.06 10.248 0.227 10.416 ;
     RECT  0.084 10.416 0.227 10.44 ;
     RECT  0.06 10.44 0.227 10.608 ;
     RECT  0.084 10.608 0.227 10.632 ;
     RECT  0.06 10.632 0.227 10.752 ;
     RECT  0.084 10.752 0.227 10.776 ;
     RECT  0.06 10.776 0.227 10.944 ;
     RECT  0.084 10.944 0.227 10.968 ;
     RECT  0.06 10.968 0.227 11.136 ;
     RECT  0.084 11.136 0.227 11.16 ;
     RECT  0.06 11.16 0.227 11.28 ;
     RECT  0.084 11.28 0.227 11.304 ;
     RECT  0.06 11.304 0.227 11.472 ;
     RECT  0.084 11.472 0.227 11.496 ;
     RECT  0.06 11.496 0.227 11.664 ;
     RECT  0.084 11.664 0.227 11.688 ;
     RECT  0.06 11.688 0.227 11.808 ;
     RECT  0.084 11.808 0.227 11.832 ;
     RECT  0.06 11.832 0.227 12 ;
     RECT  0.084 12 0.227 12.024 ;
     RECT  0.06 12.024 0.227 12.192 ;
     RECT  0.084 12.192 0.227 12.216 ;
     RECT  0.06 12.216 0.227 12.336 ;
     RECT  0.084 12.336 0.227 12.36 ;
     RECT  0.06 12.36 0.227 12.528 ;
     RECT  0.084 12.528 0.227 12.552 ;
     RECT  0.06 12.552 0.227 12.72 ;
     RECT  0.084 12.72 0.227 12.744 ;
     RECT  0.06 12.744 0.227 12.864 ;
     RECT  0.084 12.864 0.227 12.888 ;
     RECT  0.06 12.888 0.227 13.056 ;
     RECT  0.084 13.056 0.227 13.08 ;
     RECT  0.06 13.08 0.227 13.248 ;
     RECT  0.084 13.248 0.227 13.272 ;
     RECT  0.06 13.272 0.227 13.392 ;
     RECT  0.084 13.392 0.227 13.416 ;
     RECT  0.06 13.416 0.227 13.584 ;
     RECT  0.084 13.584 0.227 13.608 ;
     RECT  0.06 13.608 0.227 13.776 ;
     RECT  0.084 13.776 0.227 13.8 ;
     RECT  0.06 13.8 0.227 13.92 ;
     RECT  0.084 13.92 0.227 13.944 ;
     RECT  0.06 13.944 0.227 14.112 ;
     RECT  0.084 14.112 0.227 14.136 ;
     RECT  0.06 14.136 0.227 14.304 ;
     RECT  0.084 14.304 0.227 14.328 ;
     RECT  0.06 14.328 0.227 14.448 ;
     RECT  0.084 14.448 0.227 14.472 ;
     RECT  0.06 14.472 0.227 14.64 ;
     RECT  0.084 14.64 0.227 14.664 ;
     RECT  0.06 14.664 0.227 14.832 ;
     RECT  0.084 14.832 0.227 14.856 ;
     RECT  0.06 14.856 0.227 15.024 ;
     RECT  0.084 15.024 0.227 15.048 ;
     RECT  0.06 15.048 0.227 15.168 ;
     RECT  0.084 15.168 0.227 15.192 ;
     RECT  0.06 15.192 0.227 15.36 ;
     RECT  0.084 15.36 0.227 15.384 ;
     RECT  0.06 15.384 0.227 15.552 ;
     RECT  0.084 15.552 0.227 15.576 ;
     RECT  0.06 15.576 0.227 15.696 ;
     RECT  0.084 15.696 0.227 15.72 ;
     RECT  0.06 15.72 0.227 15.888 ;
     RECT  0.084 15.888 0.227 15.912 ;
     RECT  0.06 15.912 0.227 16.08 ;
     RECT  0.084 16.08 0.227 16.104 ;
     RECT  0.06 16.104 0.227 16.224 ;
     RECT  0.084 16.224 0.227 16.248 ;
     RECT  0.06 16.248 0.227 16.416 ;
     RECT  0.084 16.416 0.227 16.44 ;
     RECT  0.06 16.44 0.227 16.608 ;
     RECT  0.084 16.608 0.227 16.632 ;
     RECT  0.06 16.632 0.227 16.752 ;
     RECT  0.084 16.752 0.227 16.776 ;
     RECT  0.06 16.776 0.227 16.944 ;
     RECT  0.084 16.944 0.227 16.968 ;
     RECT  0.06 16.968 0.227 17.136 ;
     RECT  0.084 17.136 0.227 17.16 ;
     RECT  0.06 17.16 0.227 17.28 ;
     RECT  0.084 17.28 0.227 17.304 ;
     RECT  0.06 17.304 0.227 17.472 ;
     RECT  0.084 17.472 0.227 17.496 ;
     RECT  0.06 17.496 0.227 17.664 ;
     RECT  0.084 17.664 0.227 17.688 ;
     RECT  0.06 17.688 0.227 17.808 ;
     RECT  0.084 17.808 0.227 17.832 ;
     RECT  0.06 17.832 0.227 18 ;
     RECT  0.084 18 0.227 18.024 ;
     RECT  0.06 18.024 0.227 18.192 ;
     RECT  0.084 18.192 0.227 18.216 ;
     RECT  0.06 18.216 0.227 18.336 ;
     RECT  0.084 18.336 0.227 18.36 ;
     RECT  0.06 18.36 0.227 18.528 ;
     RECT  0.084 18.528 0.227 18.552 ;
     RECT  0.06 18.552 0.227 18.72 ;
     RECT  0.084 18.72 0.227 18.744 ;
     RECT  0.06 18.744 0.227 18.864 ;
     RECT  0.084 18.864 0.227 18.888 ;
     RECT  0.06 18.888 0.227 19.056 ;
     RECT  0.084 19.056 0.227 19.08 ;
     RECT  0.06 19.08 0.227 19.248 ;
     RECT  0.084 19.248 0.227 19.272 ;
     RECT  0.06 19.272 0.227 19.392 ;
     RECT  0.084 19.392 0.227 19.416 ;
     RECT  0.06 19.416 0.227 19.584 ;
     RECT  0.084 19.584 0.227 19.608 ;
     RECT  0.06 19.608 0.227 19.776 ;
     RECT  0.084 19.776 0.227 19.8 ;
     RECT  0.06 19.8 0.227 19.92 ;
     RECT  0.084 19.92 0.227 19.944 ;
     RECT  0.06 19.944 0.227 20.112 ;
     RECT  0.084 20.112 0.227 20.136 ;
     RECT  0.06 20.136 0.227 20.304 ;
     RECT  0.084 20.304 0.227 20.328 ;
     RECT  0.06 20.328 0.227 20.448 ;
     RECT  0.084 20.448 0.227 20.472 ;
     RECT  0.06 20.472 0.227 20.64 ;
     RECT  0.084 20.64 0.227 20.664 ;
     RECT  0.06 20.664 0.227 20.832 ;
     RECT  0.084 20.832 0.227 20.856 ;
     RECT  0.06 20.856 0.227 20.976 ;
     RECT  0.084 20.976 0.227 21 ;
     RECT  0.06 21 0.227 21.168 ;
     RECT  0.084 21.168 0.227 21.192 ;
     RECT  0.06 21.192 0.227 21.36 ;
     RECT  0.084 21.36 0.227 21.384 ;
     RECT  0.06 21.384 0.227 21.504 ;
     RECT  0.084 21.504 0.227 21.528 ;
     RECT  0.06 21.528 0.227 21.696 ;
     RECT  0.084 21.696 0.227 21.72 ;
     RECT  0.06 21.72 0.227 21.888 ;
     RECT  0.084 21.888 0.227 21.912 ;
     RECT  0.06 21.912 0.227 22.032 ;
     RECT  0.084 22.032 0.227 22.056 ;
     RECT  0.06 22.056 0.227 22.224 ;
     RECT  0.084 22.224 0.227 22.248 ;
     RECT  0.06 22.248 0.227 22.416 ;
     RECT  0.084 22.416 0.227 22.44 ;
     RECT  0.06 22.44 0.227 22.56 ;
     RECT  0.084 22.56 0.227 22.584 ;
     RECT  0.06 22.584 0.227 22.752 ;
     RECT  0.084 22.752 0.227 22.776 ;
     RECT  0.06 22.776 0.227 22.944 ;
     RECT  0.084 22.944 0.227 22.968 ;
     RECT  0.06 22.968 0.227 23.088 ;
     RECT  0.084 23.088 0.227 23.112 ;
     RECT  0.06 23.112 0.227 23.28 ;
     RECT  0.084 23.28 0.227 23.304 ;
     RECT  0.06 23.304 0.227 23.472 ;
     RECT  0.084 23.472 0.227 23.496 ;
     RECT  0.06 23.496 0.227 23.616 ;
     RECT  0.084 23.616 0.227 23.64 ;
     RECT  0.06 23.64 0.227 23.808 ;
     RECT  0.084 23.808 0.227 23.832 ;
     RECT  0.06 23.832 0.227 24 ;
     RECT  0.084 24 0.227 24.024 ;
     RECT  0.06 24.024 0.227 24.144 ;
     RECT  0.084 24.144 0.227 24.168 ;
     RECT  0.06 24.168 0.227 24.336 ;
     RECT  0.084 24.336 0.227 24.36 ;
     RECT  0.06 24.36 0.227 24.528 ;
     RECT  0.084 24.528 0.227 24.552 ;
     RECT  0.06 24.552 0.227 24.672 ;
     RECT  0.084 24.672 0.227 24.696 ;
     RECT  0.06 24.696 0.227 24.864 ;
     RECT  0.084 24.864 0.227 24.888 ;
     RECT  0.06 24.888 0.227 25.056 ;
     RECT  0.084 25.056 0.227 25.08 ;
     RECT  0.06 25.08 0.227 25.2 ;
     RECT  0.084 25.2 0.227 25.224 ;
     RECT  0.06 25.224 0.227 25.392 ;
     RECT  0.084 25.392 0.227 25.416 ;
     RECT  0.06 25.416 0.227 25.584 ;
     RECT  0.084 25.584 0.227 25.608 ;
     RECT  0.06 25.608 0.227 25.728 ;
     RECT  0.084 25.728 0.227 25.752 ;
     RECT  0.06 25.752 0.227 25.92 ;
     RECT  0.084 25.92 0.227 25.944 ;
     RECT  0.06 25.944 0.227 26.112 ;
     RECT  0.084 26.112 0.227 26.136 ;
     RECT  0.06 26.136 0.227 26.304 ;
     RECT  0.084 26.304 0.227 26.328 ;
     RECT  0.06 26.328 0.227 26.448 ;
     RECT  0.084 26.448 0.227 26.472 ;
     RECT  0.06 26.472 0.227 26.64 ;
     RECT  0.084 26.64 0.227 26.664 ;
     RECT  0.06 26.664 0.227 26.832 ;
     RECT  0.084 26.832 0.227 26.856 ;
     RECT  0.06 26.856 0.227 26.976 ;
     RECT  0.084 26.976 0.227 27 ;
     RECT  0.06 27 0.227 27.168 ;
     RECT  0.084 27.168 0.227 27.192 ;
     RECT  0.06 27.192 0.227 27.36 ;
     RECT  0.084 27.36 0.227 27.384 ;
     RECT  0.06 27.384 0.227 27.504 ;
     RECT  0.084 27.504 0.227 27.528 ;
     RECT  0.06 27.528 0.227 27.696 ;
     RECT  0.084 27.696 0.227 27.72 ;
     RECT  0.06 27.72 0.227 27.888 ;
     RECT  0.084 27.888 0.227 27.912 ;
     RECT  0.06 27.912 0.227 28.032 ;
     RECT  0.084 28.032 0.227 28.056 ;
     RECT  0.06 28.056 0.227 28.224 ;
     RECT  0.084 28.224 0.227 28.248 ;
     RECT  0.06 28.248 0.227 28.416 ;
     RECT  0.084 28.416 0.227 28.44 ;
     RECT  0.06 28.44 0.227 28.56 ;
     RECT  0.084 28.56 0.227 28.584 ;
     RECT  0.06 28.584 0.227 28.752 ;
     RECT  0.084 28.752 0.227 28.776 ;
     RECT  0.06 28.776 0.227 28.944 ;
     RECT  0.084 28.944 0.227 28.968 ;
     RECT  0.06 28.968 0.227 29.088 ;
     RECT  0.084 29.088 0.227 29.112 ;
     RECT  0.06 29.112 0.227 29.28 ;
     RECT  0.084 29.28 0.227 29.304 ;
     RECT  0.06 29.304 0.227 29.472 ;
     RECT  0.084 29.472 0.227 29.496 ;
     RECT  0.06 29.496 0.227 29.616 ;
     RECT  0.084 29.616 0.227 29.64 ;
     RECT  0.06 29.64 0.227 29.808 ;
     RECT  0.084 29.808 0.227 29.832 ;
     RECT  0.06 29.832 0.227 30 ;
     RECT  0.084 30 0.227 30.024 ;
     RECT  0.06 30.024 0.227 30.144 ;
     RECT  0.084 30.144 0.227 30.168 ;
     RECT  0.06 30.168 0.227 30.336 ;
     RECT  0.084 30.336 0.227 30.36 ;
     RECT  0.06 30.36 0.227 30.528 ;
     RECT  0.084 30.528 0.227 30.552 ;
     RECT  0.06 30.552 0.227 30.672 ;
     RECT  0.084 30.672 0.227 30.696 ;
     RECT  0.06 30.696 0.227 30.864 ;
     RECT  0.084 30.864 0.227 30.888 ;
     RECT  0.06 30.888 0.227 31.056 ;
     RECT  0.084 31.056 0.227 31.08 ;
     RECT  0.06 31.08 0.227 31.2 ;
     RECT  0.084 31.2 0.227 31.224 ;
     RECT  0.06 31.224 0.227 31.392 ;
     RECT  0.084 31.392 0.227 31.416 ;
     RECT  0.06 31.416 0.227 31.584 ;
     RECT  0.084 31.584 0.227 31.608 ;
     RECT  0.06 31.608 0.227 31.728 ;
     RECT  0.084 31.728 0.227 31.752 ;
     RECT  0.06 31.752 0.227 31.92 ;
     RECT  0.084 31.92 0.227 31.944 ;
     RECT  0.06 31.944 0.227 32.112 ;
     RECT  0.084 32.112 0.227 32.136 ;
     RECT  0.06 32.136 0.227 32.256 ;
     RECT  0.084 32.256 0.227 32.28 ;
     RECT  0.06 32.28 0.227 32.448 ;
     RECT  0.084 32.448 0.227 32.472 ;
     RECT  0.06 32.472 0.227 32.64 ;
     RECT  0.084 32.64 0.227 32.664 ;
     RECT  0.06 32.664 0.227 32.784 ;
     RECT  0.084 32.784 0.227 32.808 ;
     RECT  0.06 32.808 0.227 32.976 ;
     RECT  0.084 32.976 0.227 33 ;
     RECT  0.06 33 0.227 33.168 ;
     RECT  0.084 33.168 0.227 33.192 ;
     RECT  0.06 33.192 0.227 33.312 ;
     RECT  0.084 33.312 0.227 33.336 ;
     RECT  0.06 33.336 0.227 33.504 ;
     RECT  0.084 33.504 0.227 33.528 ;
     RECT  0.06 33.528 0.227 33.696 ;
     RECT  0.084 33.696 0.227 33.72 ;
     RECT  0.06 33.72 0.227 33.84 ;
     RECT  0.084 33.84 0.227 33.864 ;
     RECT  0.06 33.864 0.227 34.032 ;
     RECT  0.084 34.032 0.227 34.056 ;
     RECT  0.06 34.056 0.227 34.224 ;
     RECT  0.084 34.224 0.227 34.248 ;
     RECT  0.06 34.248 0.227 34.368 ;
     RECT  0.084 34.368 0.227 34.392 ;
     RECT  0.06 34.392 0.227 34.56 ;
     RECT  0.084 34.56 0.227 34.584 ;
     RECT  0.06 34.584 0.227 34.752 ;
     RECT  0.084 34.752 0.227 34.776 ;
     RECT  0.06 34.776 0.227 34.896 ;
     RECT  0.084 34.896 0.227 34.92 ;
     RECT  0.06 34.92 0.227 35.088 ;
     RECT  0.084 35.088 0.227 35.112 ;
     RECT  0.06 35.112 0.227 35.28 ;
     RECT  0.084 35.28 0.227 35.304 ;
     RECT  0.06 35.304 0.227 35.424 ;
     RECT  0.084 35.424 0.227 35.448 ;
     RECT  0.06 35.448 0.227 35.616 ;
     RECT  0.084 35.616 0.227 35.64 ;
     RECT  0.06 35.64 0.227 35.808 ;
     RECT  0.084 35.808 0.227 35.832 ;
     RECT  0.06 35.832 0.227 35.952 ;
     RECT  0.084 35.952 0.227 35.976 ;
     RECT  0.06 35.976 0.227 36.144 ;
     RECT  0.084 36.144 0.227 36.168 ;
     RECT  0.06 36.168 0.227 36.336 ;
     RECT  0.084 36.336 0.227 36.36 ;
     RECT  0.06 36.36 0.227 36.48 ;
     RECT  0.084 36.48 0.227 36.504 ;
     RECT  0.06 36.504 0.227 36.672 ;
     RECT  0.084 36.672 0.227 36.696 ;
     RECT  0.06 36.696 0.227 36.864 ;
     RECT  0.084 36.864 0.227 36.888 ;
     RECT  0.06 36.888 0.227 37.008 ;
     RECT  0.084 37.008 0.227 37.032 ;
     RECT  0.06 37.032 0.227 37.2 ;
     RECT  0.084 37.2 0.227 37.224 ;
     RECT  0.06 37.224 0.227 37.392 ;
     RECT  0.084 37.392 0.227 37.416 ;
     RECT  0.06 37.416 0.227 37.584 ;
     RECT  0.084 37.584 0.227 37.608 ;
     RECT  0.06 37.608 0.227 37.728 ;
     RECT  0.084 37.728 0.227 37.752 ;
     RECT  0.06 37.752 0.227 37.92 ;
     RECT  0.084 37.92 0.227 37.944 ;
     RECT  0.06 37.944 0.227 38.112 ;
     RECT  0.084 38.112 0.227 38.136 ;
     RECT  0.06 38.136 0.227 38.256 ;
     RECT  0.084 38.256 0.227 38.28 ;
     RECT  0.06 38.28 0.227 38.448 ;
     RECT  0.084 38.448 0.227 38.472 ;
     RECT  0.06 38.472 0.227 38.64 ;
     RECT  0.084 38.64 0.227 38.664 ;
     RECT  0.06 38.664 0.227 38.784 ;
     RECT  0.084 38.784 0.227 38.808 ;
     RECT  0.06 38.808 0.227 38.976 ;
     RECT  0.084 38.976 0.227 39 ;
     RECT  0.06 39 0.227 39.168 ;
     RECT  0.084 39.168 0.227 39.192 ;
     RECT  0.06 39.192 0.227 39.312 ;
     RECT  0.084 39.312 0.227 39.336 ;
     RECT  0.06 39.336 0.227 39.504 ;
     RECT  0.084 39.504 0.227 39.528 ;
     RECT  0.06 39.528 0.227 39.696 ;
     RECT  0.084 39.696 0.227 39.72 ;
     RECT  0.06 39.72 0.227 39.84 ;
     RECT  0.084 39.84 0.227 39.864 ;
     RECT  0.06 39.864 0.227 40.032 ;
     RECT  0.084 40.032 0.227 40.056 ;
     RECT  0.06 40.056 0.227 40.224 ;
     RECT  0.084 40.224 0.227 40.248 ;
     RECT  0.06 40.248 0.227 40.368 ;
     RECT  0.084 40.368 0.227 40.392 ;
     RECT  0.06 40.392 0.227 40.56 ;
     RECT  0.084 40.56 0.227 40.584 ;
     RECT  0.06 40.584 0.227 40.752 ;
     RECT  0.084 40.752 0.227 40.776 ;
     RECT  0.06 40.776 0.227 40.896 ;
     RECT  0.084 40.896 0.227 40.92 ;
     RECT  0.06 40.92 0.227 41.088 ;
     RECT  0.084 41.088 0.227 41.112 ;
     RECT  0.06 41.112 0.227 41.28 ;
     RECT  0.084 41.28 0.227 41.304 ;
     RECT  0.06 41.304 0.227 41.424 ;
     RECT  0.084 41.424 0.227 41.448 ;
     RECT  0.06 41.448 0.227 41.616 ;
     RECT  0.084 41.616 0.227 41.64 ;
     RECT  0.06 41.64 0.227 41.808 ;
     RECT  0.084 41.808 0.227 41.832 ;
     RECT  0.06 41.832 0.227 41.952 ;
     RECT  0.084 41.952 0.227 41.976 ;
     RECT  0.06 41.976 0.227 42.144 ;
     RECT  0.084 42.144 0.227 42.168 ;
     RECT  0.06 42.168 0.227 42.336 ;
     RECT  0.084 42.336 0.227 42.36 ;
     RECT  0.06 42.36 0.227 42.48 ;
     RECT  0.084 42.48 0.227 42.504 ;
     RECT  0.06 42.504 0.227 42.672 ;
     RECT  0.084 42.672 0.227 42.696 ;
     RECT  0.06 42.696 0.227 42.864 ;
     RECT  0.084 42.864 0.227 42.888 ;
     RECT  0.06 42.888 0.227 43.008 ;
     RECT  0.084 43.008 0.227 43.032 ;
     RECT  0.06 43.032 0.227 43.2 ;
     RECT  0.084 43.2 0.227 43.224 ;
     RECT  0.06 43.224 0.227 43.392 ;
     RECT  0.084 43.392 0.227 43.416 ;
     RECT  0.06 43.416 0.227 43.536 ;
     RECT  0.084 43.536 0.227 43.56 ;
     RECT  0.06 43.56 0.227 43.728 ;
     RECT  0.084 43.728 0.227 43.752 ;
     RECT  0.06 43.752 0.227 43.92 ;
     RECT  0.084 43.92 0.227 43.944 ;
     RECT  0.06 43.944 0.227 44.064 ;
     RECT  0.084 44.064 0.227 44.088 ;
     RECT  0.06 44.088 0.227 44.256 ;
     RECT  0.084 44.256 0.227 44.28 ;
     RECT  0.06 44.28 0.227 44.448 ;
     RECT  0.084 44.448 0.227 44.472 ;
     RECT  0.06 44.472 0.227 44.592 ;
     RECT  0.084 44.592 0.227 44.616 ;
     RECT  0.06 44.616 0.227 44.784 ;
     RECT  0.084 44.784 0.227 44.808 ;
     RECT  0.06 44.808 0.227 44.976 ;
     RECT  0.084 44.976 0.227 45 ;
     RECT  0.06 45 0.227 45.12 ;
     RECT  0.084 45.12 0.227 45.144 ;
     RECT  0.06 45.144 0.227 45.312 ;
     RECT  0.084 45.312 0.227 45.336 ;
     RECT  0.06 45.336 0.227 45.504 ;
     RECT  0.084 45.504 0.227 45.528 ;
     RECT  0.06 45.528 0.227 45.648 ;
     RECT  0.084 45.648 0.227 45.672 ;
     RECT  0.06 45.672 0.227 45.84 ;
     RECT  0.084 45.84 0.227 45.864 ;
     RECT  0.06 45.864 0.227 46.032 ;
     RECT  0.084 46.032 0.227 46.056 ;
     RECT  0.06 46.056 0.227 46.176 ;
     RECT  0.084 46.176 0.227 46.2 ;
     RECT  0.06 46.2 0.227 46.368 ;
     RECT  0.084 46.368 0.227 46.392 ;
     RECT  0.06 46.392 0.227 46.56 ;
     RECT  0.084 46.56 0.227 46.584 ;
     RECT  0.06 46.584 0.227 46.704 ;
     RECT  0.084 46.704 0.227 46.728 ;
     RECT  0.06 46.728 0.227 46.896 ;
     RECT  0.084 46.896 0.227 46.92 ;
     RECT  0.06 46.92 0.227 47.088 ;
     RECT  0.084 47.088 0.227 47.112 ;
     RECT  0.06 47.112 0.227 47.232 ;
     RECT  0.084 47.232 0.227 47.256 ;
     RECT  0.06 47.256 0.227 47.424 ;
     RECT  0.084 47.424 0.227 47.448 ;
     RECT  0.06 47.448 0.227 47.616 ;
     RECT  0.084 47.616 0.227 47.64 ;
     RECT  0.06 47.64 0.227 47.76 ;
     RECT  0.084 47.76 0.227 47.784 ;
     RECT  0.06 47.784 0.227 47.952 ;
     RECT  0.084 47.952 0.227 47.976 ;
     RECT  0.06 47.976 0.227 48.144 ;
     RECT  0.084 48.144 0.227 48.168 ;
     RECT  0.06 48.168 0.227 48.288 ;
     RECT  0.084 48.288 0.227 48.312 ;
     RECT  0.06 48.312 0.227 48.48 ;
     RECT  0.084 48.48 0.227 48.504 ;
     RECT  0.06 48.504 0.227 48.672 ;
     RECT  0.084 48.672 0.227 48.696 ;
     RECT  0.06 48.696 0.227 48.864 ;
     RECT  0.084 48.864 0.227 48.888 ;
     RECT  0.06 48.888 0.227 49.008 ;
     RECT  0.084 49.008 0.227 49.032 ;
     RECT  0.06 49.032 0.227 49.2 ;
     RECT  0.084 49.2 0.227 49.224 ;
     RECT  0.06 49.224 0.227 49.392 ;
     RECT  0.084 49.392 0.227 49.416 ;
     RECT  0.06 49.416 0.227 49.536 ;
     RECT  0.084 49.536 0.227 49.56 ;
     RECT  0.06 49.56 0.227 49.728 ;
     RECT  0.084 49.728 0.227 49.752 ;
     RECT  0.06 49.752 0.227 49.92 ;
     RECT  0.084 49.92 0.227 49.944 ;
     RECT  0.06 49.944 0.227 50.064 ;
     RECT  0.084 50.064 0.227 50.088 ;
     RECT  0.06 50.088 0.227 50.256 ;
     RECT  0.084 50.256 0.227 50.28 ;
     RECT  0.06 50.28 0.227 50.448 ;
     RECT  0.084 50.448 0.227 50.472 ;
     RECT  0.06 50.472 0.227 50.592 ;
     RECT  0.084 50.592 0.227 50.616 ;
     RECT  0.06 50.616 0.227 50.784 ;
     RECT  0.084 50.784 0.227 50.808 ;
     RECT  0.06 50.808 0.227 50.976 ;
     RECT  0.084 50.976 0.227 51 ;
     RECT  0.06 51 0.227 51.12 ;
     RECT  0.084 51.12 0.227 51.144 ;
     RECT  0.06 51.144 0.227 51.312 ;
     RECT  0.084 51.312 0.227 51.336 ;
     RECT  0.06 51.336 0.227 51.504 ;
     RECT  0.084 51.504 0.227 51.528 ;
     RECT  0.06 51.528 0.227 51.648 ;
     RECT  0.084 51.648 0.227 51.672 ;
     RECT  0.06 51.672 0.227 51.84 ;
     RECT  0.084 51.84 0.227 51.864 ;
     RECT  0.06 51.864 0.227 52.032 ;
     RECT  0.084 52.032 0.227 52.056 ;
     RECT  0.06 52.056 0.227 52.176 ;
     RECT  0.084 52.176 0.227 52.2 ;
     RECT  0.06 52.2 0.227 52.368 ;
     RECT  0.084 52.368 0.227 52.392 ;
     RECT  0.06 52.392 0.227 52.56 ;
     RECT  0.084 52.56 0.227 52.584 ;
     RECT  0.06 52.584 0.227 52.704 ;
     RECT  0.084 52.704 0.227 52.728 ;
     RECT  0.06 52.728 0.227 52.896 ;
     RECT  0.084 52.896 0.227 52.92 ;
     RECT  0.06 52.92 0.227 53.088 ;
     RECT  0.084 53.088 0.227 53.112 ;
     RECT  0.06 53.112 0.227 53.232 ;
     RECT  0.084 53.232 0.227 53.256 ;
     RECT  0.06 53.256 0.227 53.424 ;
     RECT  0.084 53.424 0.227 53.448 ;
     RECT  0.06 53.448 0.227 53.616 ;
     RECT  0.084 53.616 0.227 53.64 ;
     RECT  0.06 53.64 0.227 53.76 ;
     RECT  0.084 53.76 0.227 53.784 ;
     RECT  0.06 53.784 0.227 53.952 ;
     RECT  0.084 53.952 0.227 53.976 ;
     RECT  0.06 53.976 0.227 54.144 ;
     RECT  0.084 54.144 0.227 54.168 ;
     RECT  0.06 54.168 0.227 54.288 ;
     RECT  0.084 54.288 0.227 54.312 ;
     RECT  0.06 54.312 0.227 54.48 ;
     RECT  0.084 54.48 0.227 54.504 ;
     RECT  0.06 54.504 0.227 54.672 ;
     RECT  0.084 54.672 0.227 54.696 ;
     RECT  0.06 54.696 0.227 54.816 ;
     RECT  0.084 54.816 0.227 54.84 ;
     RECT  0.06 54.84 0.227 55.008 ;
     RECT  0.084 55.008 0.227 55.032 ;
     RECT  0.06 55.032 0.227 55.2 ;
     RECT  0.084 55.2 0.227 55.224 ;
     RECT  0.06 55.224 0.227 55.344 ;
     RECT  0.084 55.344 0.227 55.368 ;
     RECT  0.06 55.368 0.227 55.536 ;
     RECT  0.084 55.536 0.227 55.56 ;
     RECT  0.06 55.56 0.227 55.728 ;
     RECT  0.084 55.728 0.227 55.752 ;
     RECT  0.06 55.752 0.227 55.872 ;
     RECT  0.084 55.872 0.227 55.896 ;
     RECT  0.06 55.896 0.227 56.064 ;
     RECT  0.084 56.064 0.227 56.088 ;
     RECT  0.06 56.088 0.227 56.256 ;
     RECT  0.084 56.256 0.227 56.28 ;
     RECT  0.06 56.28 0.227 56.4 ;
     RECT  0.084 56.4 0.227 56.424 ;
     RECT  0.06 56.424 0.227 56.592 ;
     RECT  0.084 56.592 0.227 56.616 ;
     RECT  0.06 56.616 0.227 56.784 ;
     RECT  0.084 56.784 0.227 56.808 ;
     RECT  0.06 56.808 0.227 56.928 ;
     RECT  0.084 56.928 0.227 56.952 ;
     RECT  0.06 56.952 0.227 57.12 ;
     RECT  0.084 57.12 0.227 57.144 ;
     RECT  0.06 57.144 0.227 57.312 ;
     RECT  0.084 57.312 0.227 57.336 ;
     RECT  0.06 57.336 0.227 57.456 ;
     RECT  0.084 57.456 0.227 57.48 ;
     RECT  0.06 57.48 0.227 57.648 ;
     RECT  0.084 57.648 0.227 57.672 ;
     RECT  0.06 57.672 0.227 57.84 ;
     RECT  0.084 57.84 0.227 57.864 ;
     RECT  0.06 57.864 0.227 57.984 ;
     RECT  0.084 57.984 0.227 58.008 ;
     RECT  0.06 58.008 0.227 58.176 ;
     RECT  0.084 58.176 0.227 58.2 ;
     RECT  0.06 58.2 0.227 58.368 ;
     RECT  0.084 58.368 0.227 58.392 ;
     RECT  0.06 58.392 0.227 58.512 ;
     RECT  0.084 58.512 0.227 58.536 ;
     RECT  0.06 58.536 0.227 58.704 ;
     RECT  0.084 58.704 0.227 58.728 ;
     RECT  0.06 58.728 0.227 58.896 ;
     RECT  0.084 58.896 0.227 58.92 ;
     RECT  0.06 58.92 0.227 59.04 ;
     RECT  0.084 59.04 0.227 59.064 ;
     RECT  0.06 59.064 0.227 59.232 ;
     RECT  0.084 59.232 0.227 59.256 ;
     RECT  0.06 59.256 0.227 59.424 ;
     RECT  0.084 59.424 0.227 59.448 ;
     RECT  0.06 59.448 0.227 59.568 ;
     RECT  0.084 59.568 0.227 59.592 ;
     RECT  0.06 59.592 0.227 59.76 ;
     RECT  0.084 59.76 0.227 59.784 ;
     RECT  0.06 59.784 0.227 59.952 ;
     RECT  0.084 59.952 0.227 59.976 ;
     RECT  0.06 59.976 0.227 60.144 ;
     RECT  0.084 60.144 0.227 60.168 ;
     RECT  0.06 60.168 0.227 60.288 ;
     RECT  0.084 60.288 0.227 60.312 ;
     RECT  0.06 60.312 0.227 60.48 ;
     RECT  0.084 60.48 0.227 60.504 ;
     RECT  0.06 60.504 0.227 60.672 ;
     RECT  0.084 60.672 0.227 60.696 ;
     RECT  0.06 60.696 0.227 60.816 ;
     RECT  0.084 60.816 0.227 60.84 ;
     RECT  0.06 60.84 0.227 61.008 ;
     RECT  0.084 61.008 0.227 61.032 ;
     RECT  0.06 61.032 0.227 61.2 ;
     RECT  0.084 61.2 0.227 61.224 ;
     RECT  0.06 61.224 0.227 61.344 ;
     RECT  0.084 61.344 0.227 61.368 ;
     RECT  0.06 61.368 0.227 61.536 ;
     RECT  0.084 61.536 0.227 61.56 ;
     RECT  0.06 61.56 0.227 61.728 ;
     RECT  0.084 61.728 0.227 61.752 ;
     RECT  0.06 61.752 0.227 61.872 ;
     RECT  0.084 61.872 0.227 61.896 ;
     RECT  0.06 61.896 0.227 62.064 ;
     RECT  0.084 62.064 0.227 62.088 ;
     RECT  0.06 62.088 0.227 62.256 ;
     RECT  0.084 62.256 0.227 62.28 ;
     RECT  0.06 62.28 0.227 62.4 ;
     RECT  0.084 62.4 0.227 62.424 ;
     RECT  0.06 62.424 0.227 62.592 ;
     RECT  0.084 62.592 0.227 62.616 ;
     RECT  0.06 62.616 0.227 62.784 ;
     RECT  0.084 62.784 0.227 62.808 ;
     RECT  0.06 62.808 0.227 62.928 ;
     RECT  0.084 62.928 0.227 62.952 ;
     RECT  0.06 62.952 0.227 63.12 ;
     RECT  0.084 63.12 0.227 63.144 ;
     RECT  0.06 63.144 0.227 63.312 ;
     RECT  0.084 63.312 0.227 63.336 ;
     RECT  0.06 63.336 0.227 63.456 ;
     RECT  0.084 63.456 0.227 63.48 ;
     RECT  0.06 63.48 0.227 63.648 ;
     RECT  0.084 63.648 0.227 63.672 ;
     RECT  0.06 63.672 0.227 63.84 ;
     RECT  0.084 63.84 0.227 63.864 ;
     RECT  0.06 63.864 0.227 63.984 ;
     RECT  0.084 63.984 0.227 64.008 ;
     RECT  0.06 64.008 0.227 64.176 ;
     RECT  0.084 64.176 0.227 64.2 ;
     RECT  0.06 64.2 0.227 64.368 ;
     RECT  0.084 64.368 0.227 64.392 ;
     RECT  0.06 64.392 0.227 64.512 ;
     RECT  0.084 64.512 0.227 64.536 ;
     RECT  0.06 64.536 0.227 64.704 ;
     RECT  0.084 64.704 0.227 64.728 ;
     RECT  0.06 64.728 0.227 64.896 ;
     RECT  0.084 64.896 0.227 64.92 ;
     RECT  0.06 64.92 0.227 65.04 ;
     RECT  0.084 65.04 0.227 65.064 ;
     RECT  0.06 65.064 0.227 65.232 ;
     RECT  0.084 65.232 0.227 65.256 ;
     RECT  0.06 65.256 0.227 65.424 ;
     RECT  0.084 65.424 0.227 65.448 ;
     RECT  0.06 65.448 0.227 65.568 ;
     RECT  0.084 65.568 0.227 65.592 ;
     RECT  0.06 65.592 0.227 65.76 ;
     RECT  0.084 65.76 0.227 65.784 ;
     RECT  0.06 65.784 0.227 65.952 ;
     RECT  0.084 65.952 0.227 65.976 ;
     RECT  0.06 65.976 0.227 66.096 ;
     RECT  0.084 66.096 0.227 66.12 ;
     RECT  0.06 66.12 0.227 66.288 ;
     RECT  0.084 66.288 0.227 66.312 ;
     RECT  0.06 66.312 0.227 66.48 ;
     RECT  0.084 66.48 0.227 66.504 ;
     RECT  0.06 66.504 0.227 66.624 ;
     RECT  0.084 66.624 0.227 66.648 ;
     RECT  0.06 66.648 0.227 66.816 ;
     RECT  0.084 66.816 0.227 66.84 ;
     RECT  0.06 66.84 0.227 67.008 ;
     RECT  0.084 67.008 0.227 67.032 ;
     RECT  0.06 67.032 0.227 67.152 ;
     RECT  0.084 67.152 0.227 67.176 ;
     RECT  0.06 67.176 0.227 67.344 ;
     RECT  0.084 67.344 0.227 67.368 ;
     RECT  0.06 67.368 0.227 67.536 ;
     RECT  0.084 67.536 0.227 67.56 ;
     RECT  0.06 67.56 0.227 67.68 ;
     RECT  0.084 67.68 0.227 67.704 ;
     RECT  0.06 67.704 0.227 67.872 ;
     RECT  0.084 67.872 0.227 67.896 ;
     RECT  0.06 67.896 0.227 68.064 ;
     RECT  0.084 68.064 0.227 68.088 ;
     RECT  0.06 68.088 0.227 68.208 ;
     RECT  0.084 68.208 0.227 68.232 ;
     RECT  0.06 68.232 0.227 68.4 ;
     RECT  0.084 68.4 0.227 68.424 ;
     RECT  0.06 68.424 0.227 68.592 ;
     RECT  0.084 68.592 0.227 68.616 ;
     RECT  0.06 68.616 0.227 68.736 ;
     RECT  0.084 68.736 0.227 68.76 ;
     RECT  0.06 68.76 0.227 68.928 ;
     RECT  0.084 68.928 0.227 68.952 ;
     RECT  0.06 68.952 0.227 69.12 ;
     RECT  0.084 69.12 0.227 69.144 ;
     RECT  0.06 69.144 0.227 69.264 ;
     RECT  0.084 69.264 0.227 69.288 ;
     RECT  0.06 69.288 0.227 69.456 ;
     RECT  0.084 69.456 0.227 69.48 ;
     RECT  0.06 69.48 0.227 69.648 ;
     RECT  0.084 69.648 0.227 69.672 ;
     RECT  0.06 69.672 0.227 69.792 ;
     RECT  0.084 69.792 0.227 69.816 ;
     RECT  0.06 69.816 0.227 69.984 ;
     RECT  0.084 69.984 0.227 70.008 ;
     RECT  0.06 70.008 0.227 70.176 ;
     RECT  0.084 70.176 0.227 70.2 ;
     RECT  0.06 70.2 0.227 70.32 ;
     RECT  0.084 70.32 0.227 70.344 ;
     RECT  0.06 70.344 0.227 70.512 ;
     RECT  0.084 70.512 0.227 70.536 ;
     RECT  0.06 70.536 0.227 70.704 ;
     RECT  0.084 70.704 0.227 70.728 ;
     RECT  0.06 70.728 0.227 70.848 ;
     RECT  0.084 70.848 0.227 70.872 ;
     RECT  0.06 70.872 0.227 71.04 ;
     RECT  0.084 71.04 0.227 71.064 ;
     RECT  0.06 71.064 0.227 71.232 ;
     RECT  0.084 71.232 0.227 71.256 ;
     RECT  0.06 71.256 0.227 71.424 ;
     RECT  0.084 71.424 0.227 71.448 ;
     RECT  0.06 71.448 0.227 71.568 ;
     RECT  0.084 71.568 0.227 71.592 ;
     RECT  0.06 71.592 0.227 71.76 ;
     RECT  0.084 71.76 0.227 71.784 ;
     RECT  0.06 71.784 0.227 71.952 ;
     RECT  0.084 71.952 0.227 71.976 ;
     RECT  0.06 71.976 0.227 72.096 ;
     RECT  0.084 72.096 0.227 72.12 ;
     RECT  0.06 72.12 0.227 72.288 ;
     RECT  0.084 72.288 0.227 72.312 ;
     RECT  0.06 72.312 0.227 72.48 ;
     RECT  0.084 72.48 0.227 72.504 ;
     RECT  0.06 72.504 0.227 72.624 ;
     RECT  0.084 72.624 0.227 72.648 ;
     RECT  0.06 72.648 0.227 72.816 ;
     RECT  0.084 72.816 0.227 72.84 ;
     RECT  0.06 72.84 0.227 73.008 ;
     RECT  0.084 73.008 0.227 73.032 ;
     RECT  0.06 73.032 0.227 73.152 ;
     RECT  0.084 73.152 0.227 73.176 ;
     RECT  0.06 73.176 0.227 73.344 ;
     RECT  0.084 73.344 0.227 73.368 ;
     RECT  0.06 73.368 0.227 73.536 ;
     RECT  0.084 73.536 0.227 73.56 ;
     RECT  0.06 73.56 0.227 73.68 ;
     RECT  0.084 73.68 0.227 73.704 ;
     RECT  0.06 73.704 0.227 73.872 ;
     RECT  0.084 73.872 0.227 73.896 ;
     RECT  0.06 73.896 0.227 74.064 ;
     RECT  0.084 74.064 0.227 74.088 ;
     RECT  0.06 74.088 0.227 74.208 ;
     RECT  0.084 74.208 0.227 74.232 ;
     RECT  0.06 74.232 0.227 74.4 ;
     RECT  0.084 74.4 0.227 74.424 ;
     RECT  0.06 74.424 0.227 74.592 ;
     RECT  0.084 74.592 0.227 74.616 ;
     RECT  0.06 74.616 0.227 74.736 ;
     RECT  0.084 74.736 0.227 74.76 ;
     RECT  0.06 74.76 0.227 74.928 ;
     RECT  0.084 74.928 0.227 74.952 ;
     RECT  0.06 74.952 0.227 75.12 ;
     RECT  0.084 75.12 0.227 75.144 ;
     RECT  0.06 75.144 0.227 75.264 ;
     RECT  0.084 75.264 0.227 75.288 ;
     RECT  0.06 75.288 0.227 75.456 ;
     RECT  0.084 75.456 0.227 75.48 ;
     RECT  0.06 75.48 0.227 75.648 ;
     RECT  0.084 75.648 0.227 75.672 ;
     RECT  0.06 75.672 0.227 75.792 ;
     RECT  0.084 75.792 0.227 75.816 ;
     RECT  0.06 75.816 0.227 75.984 ;
     RECT  0.084 75.984 0.227 76.008 ;
     RECT  0.06 76.008 0.227 76.176 ;
     RECT  0.084 76.176 0.227 76.2 ;
     RECT  0.06 76.2 0.227 76.32 ;
     RECT  0.084 76.32 0.227 76.344 ;
     RECT  0.06 76.344 0.227 76.512 ;
     RECT  0.084 76.512 0.227 76.536 ;
     RECT  0.06 76.536 0.227 76.704 ;
     RECT  0.084 76.704 0.227 76.728 ;
     RECT  0.06 76.728 0.227 76.848 ;
     RECT  0.084 76.848 0.227 76.872 ;
     RECT  0.06 76.872 0.227 77.04 ;
     RECT  0.084 77.04 0.227 77.064 ;
     RECT  0.06 77.064 0.227 77.232 ;
     RECT  0.084 77.232 0.227 77.256 ;
     RECT  0.06 77.256 0.227 77.376 ;
     RECT  0.084 77.376 0.227 77.4 ;
     RECT  0.06 77.4 0.227 77.568 ;
     RECT  0.084 77.568 0.227 77.592 ;
     RECT  0.06 77.592 0.227 77.76 ;
     RECT  0.084 77.76 0.227 77.784 ;
     RECT  0.06 77.784 0.227 77.904 ;
     RECT  0.084 77.904 0.227 77.928 ;
     RECT  0.06 77.928 0.227 78.096 ;
     RECT  0.084 78.096 0.227 78.12 ;
     RECT  0.06 78.12 0.227 78.288 ;
     RECT  0.084 78.288 0.227 78.312 ;
     RECT  0.06 78.312 0.227 78.432 ;
     RECT  0.084 78.432 0.227 78.456 ;
     RECT  0.06 78.456 0.227 78.624 ;
     RECT  0.084 78.624 0.227 78.648 ;
     RECT  0.06 78.648 0.227 78.816 ;
     RECT  0.084 78.816 0.227 78.84 ;
     RECT  0.06 78.84 0.227 78.96 ;
     RECT  0.084 78.96 0.227 78.984 ;
     RECT  0.06 78.984 0.227 79.152 ;
     RECT  0.084 79.152 0.227 79.176 ;
     RECT  0.06 79.176 0.227 79.344 ;
     RECT  0.084 79.344 0.227 79.368 ;
     RECT  0.06 79.368 0.227 79.488 ;
     RECT  0.084 79.488 0.227 79.512 ;
     RECT  0.06 79.512 0.227 79.68 ;
     RECT  0.084 79.68 0.227 79.704 ;
     RECT  0.06 79.704 0.227 79.872 ;
     RECT  0.084 79.872 0.227 79.896 ;
     RECT  0.06 79.896 0.227 80.016 ;
     RECT  0.084 80.016 0.227 80.04 ;
     RECT  0.06 80.04 0.227 80.208 ;
     RECT  0.084 80.208 0.227 80.232 ;
     RECT  0.06 80.232 0.227 80.4 ;
     RECT  0.084 80.4 0.227 80.424 ;
     RECT  0.06 80.424 0.227 80.544 ;
     RECT  0.084 80.544 0.227 80.568 ;
     RECT  0.06 80.568 0.227 80.736 ;
     RECT  0.084 80.736 0.227 80.76 ;
     RECT  0.06 80.76 0.227 80.928 ;
     RECT  0.084 80.928 0.227 80.952 ;
     RECT  0.06 80.952 0.227 81.072 ;
     RECT  0.084 81.072 0.227 81.096 ;
     RECT  0.06 81.096 0.227 81.264 ;
     RECT  0.084 81.264 0.227 81.288 ;
     RECT  0.06 81.288 0.227 81.456 ;
     RECT  0.084 81.456 0.227 81.48 ;
     RECT  0.06 81.48 0.227 81.6 ;
     RECT  0.084 81.6 0.227 81.624 ;
     RECT  0.06 81.624 0.227 81.792 ;
     RECT  0.084 81.792 0.227 81.816 ;
     RECT  0.06 81.816 0.227 81.984 ;
     RECT  0.084 81.984 0.227 82.008 ;
     RECT  0.06 82.008 0.227 82.128 ;
     RECT  0.084 82.128 0.227 82.152 ;
     RECT  0.06 82.152 0.227 82.32 ;
     RECT  0.084 82.32 0.227 82.344 ;
     RECT  0.06 82.344 0.227 82.512 ;
     RECT  0.084 82.512 0.227 82.536 ;
     RECT  0.06 82.536 0.227 82.704 ;
     RECT  0.084 82.704 0.227 82.728 ;
     RECT  0.06 82.728 0.227 82.848 ;
     RECT  0.084 82.848 0.227 82.872 ;
     RECT  0.06 82.872 0.227 83.04 ;
     RECT  0.084 83.04 0.227 83.064 ;
     RECT  0.06 83.064 0.227 83.232 ;
     RECT  0.084 83.232 0.227 83.256 ;
     RECT  0.06 83.256 0.227 83.376 ;
     RECT  0.084 83.376 0.227 83.4 ;
     RECT  0.06 83.4 0.227 83.568 ;
     RECT  0.084 83.568 0.227 83.592 ;
     RECT  0.06 83.592 0.227 83.76 ;
     RECT  0.084 83.76 0.227 83.784 ;
     RECT  0.06 83.784 0.227 83.904 ;
     RECT  0.084 83.904 0.227 83.928 ;
     RECT  0.06 83.928 0.227 84.096 ;
     RECT  0.084 84.096 0.227 84.12 ;
     RECT  0.06 84.12 0.227 84.288 ;
     RECT  0.084 84.288 0.227 84.312 ;
     RECT  0.06 84.312 0.227 84.432 ;
     RECT  0.084 84.432 0.227 84.456 ;
     RECT  0.06 84.456 0.227 84.624 ;
     RECT  0.084 84.624 0.227 84.648 ;
     RECT  0.06 84.648 0.227 84.816 ;
     RECT  0.084 84.816 0.227 84.84 ;
     RECT  0.06 84.84 0.227 84.96 ;
     RECT  0.084 84.96 0.227 84.984 ;
     RECT  0.06 84.984 0.227 85.152 ;
     RECT  0.084 85.152 0.227 85.176 ;
     RECT  0.06 85.176 0.227 85.344 ;
     RECT  0.084 85.344 0.227 85.368 ;
     RECT  0.06 85.368 0.227 85.488 ;
     RECT  0.084 85.488 0.227 85.512 ;
     RECT  0.06 85.512 0.227 85.68 ;
     RECT  0.084 85.68 0.227 85.704 ;
     RECT  0.06 85.704 0.227 85.872 ;
     RECT  0.084 85.872 0.227 85.896 ;
     RECT  0.06 85.896 0.227 86.016 ;
     RECT  0.084 86.016 0.227 86.04 ;
     RECT  0.06 86.04 0.227 86.208 ;
     RECT  0.084 86.208 0.227 86.232 ;
     RECT  0.06 86.232 0.227 86.4 ;
     RECT  0.084 86.4 0.227 86.424 ;
     RECT  0.06 86.424 0.227 86.544 ;
     RECT  0.084 86.544 0.227 86.568 ;
     RECT  0.06 86.568 0.227 86.736 ;
     RECT  0.084 86.736 0.227 86.76 ;
     RECT  0.06 86.76 0.227 86.928 ;
     RECT  0.084 86.928 0.227 86.952 ;
     RECT  0.06 86.952 0.227 87.072 ;
     RECT  0.084 87.072 0.227 87.096 ;
     RECT  0.06 87.096 0.227 87.264 ;
     RECT  0.084 87.264 0.227 87.288 ;
     RECT  0.06 87.288 0.227 87.456 ;
     RECT  0.084 87.456 0.227 87.48 ;
     RECT  0.06 87.48 0.227 87.6 ;
     RECT  0.084 87.6 0.227 87.624 ;
     RECT  0.06 87.624 0.227 87.792 ;
     RECT  0.084 87.792 0.227 87.816 ;
     RECT  0.06 87.816 0.227 87.984 ;
     RECT  0.084 87.984 0.227 88.008 ;
     RECT  0.06 88.008 0.227 88.128 ;
     RECT  0.084 88.128 0.227 88.152 ;
     RECT  0.06 88.152 0.227 88.32 ;
     RECT  0.084 88.32 0.227 88.344 ;
     RECT  0.06 88.344 0.227 88.512 ;
     RECT  0.084 88.512 0.227 88.536 ;
     RECT  0.06 88.536 0.227 88.656 ;
     RECT  0.084 88.656 0.227 88.68 ;
     RECT  0.06 88.68 0.227 88.848 ;
     RECT  0.084 88.848 0.227 88.872 ;
     RECT  0.06 88.872 0.227 89.04 ;
     RECT  0.084 89.04 0.227 89.064 ;
     RECT  0.06 89.064 0.227 89.184 ;
     RECT  0.084 89.184 0.227 89.208 ;
     RECT  0.06 89.208 0.227 89.376 ;
     RECT  0.084 89.376 0.227 89.4 ;
     RECT  0.06 89.4 0.227 89.568 ;
     RECT  0.084 89.568 0.227 89.592 ;
     RECT  0.06 89.592 0.227 89.712 ;
     RECT  0.084 89.712 0.227 89.736 ;
     RECT  0.06 89.736 0.227 89.904 ;
     RECT  0.084 89.904 0.227 89.928 ;
     RECT  0.06 89.928 0.227 90.096 ;
     RECT  0.084 90.096 0.227 90.12 ;
     RECT  0.06 90.12 0.227 90.24 ;
     RECT  0.084 90.24 0.227 90.264 ;
     RECT  0.06 90.264 0.227 90.432 ;
     RECT  0.084 90.432 0.227 90.456 ;
     RECT  0.06 90.456 0.227 90.624 ;
     RECT  0.084 90.624 0.227 90.648 ;
     RECT  0.06 90.648 0.227 90.768 ;
     RECT  0.084 90.768 0.227 90.792 ;
     RECT  0.06 90.792 0.227 90.96 ;
     RECT  0.084 90.96 0.227 90.984 ;
     RECT  0.06 90.984 0.227 91.152 ;
     RECT  0.084 91.152 0.227 91.176 ;
     RECT  0.06 91.176 0.227 92.112 ;
     RECT  0.084 92.112 0.227 92.136 ;
     RECT  0.227 1.056 2.408 91.176 ;
     RECT  2.408 1.056 2.704 93.144 ;
     RECT  2.704 27.168 2.765 91.08 ;
     RECT  2.704 19.584 2.801 26.136 ;
     RECT  2.765 28.224 2.801 43.128 ;
     RECT  2.765 44.208 2.801 91.08 ;
     RECT  2.801 28.224 2.837 31.416 ;
     RECT  2.801 32.784 2.837 43.128 ;
     RECT  2.801 55.536 2.837 70.68 ;
     RECT  2.837 42.48 2.873 42.504 ;
     RECT  2.801 44.208 2.909 53.784 ;
     RECT  2.801 19.584 2.981 24.984 ;
     RECT  2.837 32.784 3.017 41.448 ;
     RECT  2.704 1.056 3.053 18.216 ;
     RECT  2.909 44.208 3.197 51.912 ;
     RECT  2.981 19.584 3.299 24.12 ;
     RECT  3.197 45.744 3.299 51.912 ;
     RECT  2.909 52.944 3.299 53.784 ;
     RECT  2.801 25.968 3.341 26.136 ;
     RECT  3.053 1.44 3.443 15.432 ;
     RECT  2.837 55.536 3.484 58.872 ;
     RECT  2.801 71.664 3.491 91.08 ;
     RECT  3.443 1.44 3.557 11.4 ;
     RECT  3.557 1.44 3.593 9.048 ;
     RECT  3.557 10.416 3.593 11.4 ;
     RECT  3.593 1.44 3.629 6.888 ;
     RECT  2.837 60.24 3.665 70.68 ;
     RECT  3.017 36.96 3.701 41.448 ;
     RECT  3.629 1.776 3.731 6.888 ;
     RECT  3.665 60.24 3.731 63.288 ;
     RECT  3.731 1.776 3.737 6.024 ;
     RECT  3.299 21.504 3.737 24.12 ;
     RECT  3.701 36.96 3.773 40.92 ;
     RECT  3.665 64.704 3.773 70.68 ;
     RECT  2.837 29.616 3.788 31.416 ;
     RECT  3.197 44.208 3.805 44.76 ;
     RECT  3.788 29.616 3.841 31.56 ;
     RECT  3.017 32.784 3.875 35.976 ;
     RECT  3.805 43.296 3.877 44.76 ;
     RECT  3.773 67.536 3.913 70.68 ;
     RECT  3.491 71.664 3.913 86.232 ;
     RECT  3.737 2.304 4.025 6.024 ;
     RECT  3.299 45.744 4.061 49.128 ;
     RECT  3.484 57.456 4.061 58.872 ;
     RECT  3.341 26.112 4.076 26.136 ;
     RECT  3.877 27.264 4.076 27.288 ;
     RECT  3.053 16.752 4.093 18.216 ;
     RECT  3.877 42.528 4.093 44.76 ;
     RECT  3.484 55.536 4.093 56.28 ;
     RECT  3.773 36.96 4.133 40.728 ;
     RECT  4.093 42.192 4.133 44.76 ;
     RECT  4.061 45.744 4.133 48.456 ;
     RECT  2.704 93.12 4.165 93.144 ;
     RECT  3.443 14.352 4.172 15.432 ;
     RECT  4.093 16.512 4.172 18.216 ;
     RECT  4.172 14.352 4.213 18.216 ;
     RECT  3.299 19.584 4.213 20.328 ;
     RECT  3.875 34.656 4.309 35.976 ;
     RECT  4.133 36.96 4.309 38.232 ;
     RECT  3.491 87.312 4.357 91.08 ;
     RECT  3.299 50.784 4.453 51.528 ;
     RECT  3.299 52.944 4.453 53.592 ;
     RECT  3.841 29.616 4.489 31.752 ;
     RECT  3.875 32.784 4.489 33.624 ;
     RECT  4.453 50.784 4.489 53.592 ;
     RECT  4.093 54.672 4.489 56.28 ;
     RECT  4.076 26.112 4.501 27.288 ;
     RECT  4.076 28.368 4.501 28.392 ;
     RECT  3.737 21.648 4.508 24.12 ;
     RECT  3.593 8.208 4.525 9.048 ;
     RECT  3.593 10.416 4.525 10.44 ;
     RECT  3.443 12.528 4.525 13.32 ;
     RECT  4.489 50.784 4.525 56.28 ;
     RECT  4.061 57.456 4.525 58.2 ;
     RECT  3.913 67.536 4.525 86.232 ;
     RECT  4.357 87.312 4.525 91.176 ;
     RECT  4.508 21.648 4.549 24.6 ;
     RECT  4.501 26.112 4.549 28.632 ;
     RECT  4.525 8.208 4.633 10.44 ;
     RECT  4.525 11.952 4.633 13.32 ;
     RECT  3.731 60.528 4.705 63.288 ;
     RECT  4.633 8.208 4.748 13.32 ;
     RECT  4.213 14.352 4.748 20.328 ;
     RECT  4.669 59.232 4.885 59.256 ;
     RECT  4.705 60.528 4.885 63.576 ;
     RECT  4.549 21.648 4.913 28.632 ;
     RECT  4.489 29.616 4.913 33.624 ;
     RECT  4.777 7.104 4.981 7.128 ;
     RECT  4.748 8.208 5.029 20.328 ;
     RECT  4.133 39.6 5.065 40.728 ;
     RECT  4.133 42.192 5.065 42.552 ;
     RECT  4.025 2.304 5.108 5.544 ;
     RECT  4.981 7.104 5.108 7.176 ;
     RECT  5.029 8.208 5.108 20.616 ;
     RECT  4.913 21.648 5.108 33.624 ;
     RECT  4.309 34.656 5.108 38.232 ;
     RECT  5.065 39.6 5.108 42.552 ;
     RECT  4.133 44.064 5.108 44.76 ;
     RECT  4.133 46.56 5.108 48.456 ;
     RECT  4.525 49.584 5.108 49.608 ;
     RECT  4.525 50.784 5.108 58.2 ;
     RECT  4.885 59.232 5.108 63.576 ;
     RECT  3.773 64.704 5.108 66.408 ;
     RECT  4.525 67.536 5.108 91.176 ;
     RECT  4.165 92.352 5.108 93.144 ;
     RECT  5.108 2.148 5.212 93.144 ;
     RECT  5.212 2.304 5.321 93.144 ;
     RECT  5.321 2.304 5.404 92.622 ;
     RECT  5.404 5.184 5.429 40.104 ;
     RECT  5.404 67.872 5.465 69.288 ;
     RECT  5.404 43.632 5.555 44.472 ;
     RECT  5.404 51.984 5.555 60.456 ;
     RECT  5.404 86.736 5.573 90.936 ;
     RECT  5.429 5.184 5.753 20.52 ;
     RECT  5.404 72.96 5.753 84.84 ;
     RECT  5.404 41.232 5.789 42.552 ;
     RECT  5.429 21.504 5.795 40.104 ;
     RECT  5.404 62.352 5.861 64.392 ;
     RECT  5.753 81.072 5.987 84.84 ;
     RECT  5.987 81.168 6.005 84.84 ;
     RECT  5.555 44.016 6.041 44.472 ;
     RECT  5.465 68.064 6.041 69.288 ;
     RECT  5.795 32.928 6.179 40.104 ;
     RECT  5.404 2.304 6.253 4.2 ;
     RECT  6.005 81.168 6.365 83.784 ;
     RECT  5.861 64.176 6.421 64.392 ;
     RECT  5.404 65.424 6.421 66.264 ;
     RECT  5.573 88.656 6.509 90.552 ;
     RECT  5.555 54.048 6.515 60.456 ;
     RECT  6.041 68.064 6.541 68.952 ;
     RECT  5.753 72.96 6.563 79.848 ;
     RECT  5.753 5.232 6.577 20.52 ;
     RECT  5.795 21.504 6.577 31.896 ;
     RECT  6.365 81.168 6.617 83.544 ;
     RECT  5.789 41.376 6.649 42.552 ;
     RECT  5.861 62.352 6.649 63.096 ;
     RECT  5.555 51.984 6.721 53.064 ;
     RECT  6.515 54.048 6.721 59.256 ;
     RECT  6.515 60.432 6.757 60.456 ;
     RECT  6.649 61.44 6.757 63.096 ;
     RECT  5.573 86.736 6.757 87.48 ;
     RECT  6.509 88.656 6.757 89.16 ;
     RECT  5.404 70.32 6.793 71.976 ;
     RECT  6.563 72.96 6.793 75.528 ;
     RECT  6.757 86.736 6.793 89.16 ;
     RECT  5.404 45.552 6.796 50.376 ;
     RECT  6.421 64.176 6.805 66.264 ;
     RECT  6.721 51.984 6.812 59.256 ;
     RECT  6.253 2.256 6.829 4.2 ;
     RECT  6.577 5.232 6.829 31.896 ;
     RECT  6.541 67.824 6.829 68.952 ;
     RECT  6.005 84.816 6.829 84.84 ;
     RECT  6.796 50.352 6.901 50.376 ;
     RECT  6.812 51.792 6.901 59.256 ;
     RECT  6.757 60.432 6.901 63.096 ;
     RECT  6.805 64.176 6.901 66.792 ;
     RECT  6.829 67.776 6.901 68.952 ;
     RECT  6.649 41.376 6.973 42.792 ;
     RECT  6.041 44.016 6.973 44.376 ;
     RECT  6.829 84.816 7.009 84.888 ;
     RECT  6.793 85.968 7.009 89.16 ;
     RECT  6.973 41.376 7.117 44.376 ;
     RECT  6.796 45.552 7.117 49.32 ;
     RECT  6.179 33.6 7.153 40.104 ;
     RECT  7.153 33.312 7.189 40.104 ;
     RECT  7.117 41.376 7.189 49.32 ;
     RECT  6.901 60.432 7.189 68.952 ;
     RECT  6.563 76.512 7.189 79.848 ;
     RECT  6.617 81.168 7.189 83.352 ;
     RECT  6.829 2.256 7.297 31.896 ;
     RECT  6.901 50.352 7.477 59.256 ;
     RECT  7.189 60.432 7.477 69.336 ;
     RECT  7.297 2.256 7.513 32.328 ;
     RECT  7.189 33.312 7.513 49.32 ;
     RECT  7.369 92.4 7.513 92.424 ;
     RECT  6.509 90.528 7.585 90.552 ;
     RECT  7.585 90.528 7.693 90.84 ;
     RECT  7.009 84.816 7.729 89.16 ;
     RECT  7.729 84.528 7.765 89.16 ;
     RECT  7.693 90.288 7.765 90.84 ;
     RECT  7.513 91.968 7.765 92.424 ;
     RECT  7.513 2.256 7.808 49.32 ;
     RECT  7.477 50.352 7.808 69.336 ;
     RECT  6.793 70.32 7.808 75.528 ;
     RECT  7.189 76.512 7.808 83.352 ;
     RECT  7.765 84.528 7.808 92.424 ;
     RECT  7.808 2.148 7.912 92.892 ;
     RECT  7.912 2.256 8.104 92.622 ;
     RECT  8.104 2.256 8.273 92.376 ;
     RECT  8.273 2.304 10.508 92.376 ;
     RECT  10.508 2.148 10.612 92.892 ;
     RECT  10.612 2.304 10.804 92.622 ;
     RECT  10.804 2.304 11.009 92.184 ;
     RECT  11.009 2.304 11.267 91.848 ;
     RECT  11.267 2.304 11.369 91.656 ;
     RECT  11.369 2.304 11.441 48.024 ;
     RECT  11.441 2.304 11.621 47.88 ;
     RECT  11.369 49.2 11.909 91.656 ;
     RECT  11.909 57.408 12.445 91.656 ;
     RECT  11.909 49.2 12.733 56.28 ;
     RECT  11.621 20.112 12.805 47.88 ;
     RECT  12.733 48.96 12.913 56.28 ;
     RECT  12.805 20.112 13.021 47.928 ;
     RECT  11.621 2.304 13.093 18.84 ;
     RECT  13.021 20.112 13.093 47.976 ;
     RECT  13.093 2.304 13.129 47.976 ;
     RECT  12.913 48.96 13.129 56.328 ;
     RECT  13.129 2.304 13.208 56.328 ;
     RECT  12.445 57.408 13.208 92.376 ;
     RECT  13.208 2.148 13.312 92.892 ;
     RECT  13.312 2.148 13.889 92.664 ;
     RECT  13.889 32.592 13.955 92.664 ;
     RECT  13.889 2.148 13.957 31.512 ;
     RECT  13.955 32.592 13.961 92.232 ;
     RECT  13.961 54.528 14.243 92.232 ;
     RECT  13.961 32.592 14.393 53.4 ;
     RECT  13.957 2.064 14.717 31.512 ;
     RECT  14.243 61.392 15.205 92.232 ;
     RECT  14.243 54.528 15.217 60.36 ;
     RECT  15.205 61.392 15.217 92.856 ;
     RECT  15.164 94.944 15.251 94.968 ;
     RECT  14.393 32.592 15.397 35.496 ;
     RECT  14.393 36.624 15.397 53.4 ;
     RECT  15.397 32.592 15.433 53.4 ;
     RECT  15.217 54.528 15.433 92.856 ;
     RECT  15.433 32.592 15.865 92.856 ;
     RECT  14.717 2.064 15.908 31.464 ;
     RECT  15.865 32.496 15.908 92.856 ;
     RECT  15.908 2.064 16.012 92.892 ;
     RECT  16.012 2.064 16.204 92.622 ;
     RECT  16.204 2.064 16.697 92.232 ;
     RECT  16.697 2.064 16.769 91.368 ;
     RECT  16.769 2.064 17.417 91.08 ;
     RECT  17.417 2.064 17.561 45.528 ;
     RECT  18.14 92.112 18.181 92.136 ;
     RECT  17.417 46.512 18.277 91.08 ;
     RECT  18.181 92.112 18.277 92.424 ;
     RECT  17.561 34.752 18.529 45.528 ;
     RECT  18.277 46.512 18.529 92.424 ;
     RECT  17.561 2.064 18.608 33.672 ;
     RECT  18.529 34.752 18.608 92.424 ;
     RECT  18.608 2.064 18.712 92.892 ;
     RECT  18.712 2.064 18.904 92.622 ;
     RECT  18.904 49.824 19.181 91.704 ;
     RECT  18.904 2.064 19.433 13.176 ;
     RECT  19.181 49.824 19.505 91.176 ;
     RECT  18.904 46.032 19.957 48.792 ;
     RECT  19.505 49.824 19.957 91.08 ;
     RECT  18.904 19.008 20.041 45 ;
     RECT  19.957 46.032 20.041 91.08 ;
     RECT  18.904 14.448 20.401 17.928 ;
     RECT  19.433 3.888 20.437 13.176 ;
     RECT  20.401 14.4 20.437 17.928 ;
     RECT  20.041 19.008 20.437 91.08 ;
     RECT  20.437 3.888 20.545 91.08 ;
     RECT  20.437 92.4 20.545 92.424 ;
     RECT  19.433 2.064 20.873 2.856 ;
     RECT  20.873 2.148 21.308 2.856 ;
     RECT  20.545 3.888 21.308 92.424 ;
     RECT  21.308 2.148 21.412 92.892 ;
     RECT  21.412 2.208 21.604 92.622 ;
     RECT  21.604 2.208 22.067 59.016 ;
     RECT  22.067 2.208 22.097 39.864 ;
     RECT  22.097 2.208 22.643 33.096 ;
     RECT  22.067 40.896 22.777 59.016 ;
     RECT  21.604 60 22.777 63.864 ;
     RECT  22.777 40.896 22.849 63.864 ;
     RECT  21.604 64.896 22.849 92.424 ;
     RECT  22.849 40.896 22.853 92.424 ;
     RECT  22.853 86.592 22.997 92.424 ;
     RECT  22.097 34.464 23.029 39.864 ;
     RECT  22.853 40.896 23.029 85.512 ;
     RECT  22.643 2.256 23.317 33.096 ;
     RECT  23.317 2.256 23.389 33.288 ;
     RECT  23.029 34.464 23.389 85.512 ;
     RECT  22.997 86.592 23.965 90.072 ;
     RECT  23.965 86.592 24.001 90.264 ;
     RECT  23.389 2.256 24.008 85.512 ;
     RECT  24.001 86.592 24.008 90.36 ;
     RECT  22.997 91.392 24.008 92.424 ;
     RECT  24.008 2.148 24.112 92.892 ;
     RECT  24.112 2.304 24.304 92.622 ;
     RECT  24.304 2.304 25.661 92.328 ;
     RECT  25.661 2.304 25.82 18.168 ;
     RECT  25.661 19.248 26.341 92.328 ;
     RECT  25.82 2.256 26.708 18.168 ;
     RECT  26.341 19.248 26.708 92.424 ;
     RECT  26.708 2.148 26.812 92.892 ;
     RECT  26.812 2.304 27.004 92.622 ;
     RECT  27.004 14.64 27.245 92.424 ;
     RECT  27.245 14.64 27.395 89.304 ;
     RECT  27.395 30.576 27.425 89.304 ;
     RECT  27.245 90.528 27.713 92.424 ;
     RECT  27.004 7.152 27.929 11.784 ;
     RECT  27.425 30.672 28.115 89.304 ;
     RECT  28.115 40.896 28.145 89.304 ;
     RECT  27.004 12.816 28.249 13.176 ;
     RECT  27.395 14.64 28.249 29.592 ;
     RECT  28.145 40.896 28.259 59.736 ;
     RECT  28.249 12.816 28.285 29.592 ;
     RECT  28.145 60.768 28.357 89.304 ;
     RECT  27.713 90.528 28.357 92.328 ;
     RECT  28.285 12.768 28.393 29.592 ;
     RECT  28.115 30.672 28.393 39.864 ;
     RECT  27.929 7.2 28.753 11.784 ;
     RECT  28.393 12.768 28.753 39.864 ;
     RECT  27.004 2.304 29.041 6.12 ;
     RECT  29.041 2.208 29.149 6.12 ;
     RECT  28.753 7.2 29.149 39.864 ;
     RECT  29.149 2.208 29.408 39.864 ;
     RECT  28.259 40.896 29.408 41.496 ;
     RECT  28.259 42.528 29.408 59.736 ;
     RECT  28.357 60.768 29.408 92.328 ;
     RECT  29.408 2.148 29.512 92.892 ;
     RECT  29.512 2.352 29.704 92.622 ;
     RECT  29.704 65.136 30.449 92.232 ;
     RECT  30.449 65.136 30.485 90.264 ;
     RECT  29.704 2.352 31.025 64.104 ;
     RECT  31.025 54.624 31.093 64.104 ;
     RECT  30.485 65.136 31.093 89.832 ;
     RECT  31.093 54.624 31.633 89.832 ;
     RECT  30.449 91.248 31.633 92.232 ;
     RECT  31.025 2.352 32.108 53.592 ;
     RECT  31.633 54.624 32.108 92.232 ;
     RECT  32.108 2.148 32.212 92.892 ;
     RECT  32.212 2.256 32.404 92.622 ;
     RECT  32.404 2.256 32.531 92.328 ;
     RECT  32.531 2.256 32.915 92.232 ;
     RECT  32.915 2.544 32.969 92.232 ;
     RECT  32.969 2.544 33.041 64.248 ;
     RECT  33.041 19.248 33.059 64.248 ;
     RECT  32.969 65.232 33.113 92.232 ;
     RECT  33.059 19.248 33.149 63.816 ;
     RECT  33.149 19.536 33.168 63.816 ;
     RECT  33.113 65.232 33.185 91.128 ;
     RECT  33.041 2.544 33.293 17.688 ;
     RECT  33.168 55.68 33.293 63.816 ;
     RECT  33.185 65.232 33.509 90.648 ;
     RECT  33.293 55.68 33.581 63.528 ;
     RECT  33.509 65.232 33.587 68.28 ;
     RECT  33.587 65.232 33.973 68.232 ;
     RECT  33.581 55.968 34.405 63.528 ;
     RECT  34.405 55.968 34.441 63.576 ;
     RECT  33.293 2.544 34.808 17.64 ;
     RECT  33.168 19.536 34.808 54.696 ;
     RECT  34.441 55.968 34.808 63.624 ;
     RECT  33.973 65.136 34.808 68.232 ;
     RECT  33.509 69.312 34.808 90.648 ;
     RECT  33.113 92.208 34.808 92.232 ;
     RECT  34.808 2.148 34.912 92.892 ;
     RECT  34.912 2.418 35.104 92.622 ;
     RECT  35.104 2.832 35.165 16.632 ;
     RECT  35.104 19.44 35.201 24.168 ;
     RECT  35.104 46.272 35.219 54.696 ;
     RECT  35.104 55.968 35.219 63.816 ;
     RECT  35.219 51.12 35.273 54.696 ;
     RECT  35.104 30.576 35.363 39.864 ;
     RECT  35.104 40.896 35.417 45 ;
     RECT  35.219 46.272 35.417 49.896 ;
     RECT  35.273 53.376 35.417 54.696 ;
     RECT  35.104 64.896 35.453 89.832 ;
     RECT  35.363 30.576 35.489 33.96 ;
     RECT  35.219 60.672 35.489 63.816 ;
     RECT  35.453 69.264 35.489 89.832 ;
     RECT  35.219 55.968 35.525 59.544 ;
     RECT  35.417 40.896 35.561 41.736 ;
     RECT  35.489 69.264 35.597 70.008 ;
     RECT  35.489 71.424 35.597 89.832 ;
     RECT  35.489 30.672 35.633 33.96 ;
     RECT  35.453 64.896 35.633 68.232 ;
     RECT  35.597 82.8 35.705 89.832 ;
     RECT  35.597 71.424 35.741 81.48 ;
     RECT  35.633 66.24 35.777 68.232 ;
     RECT  35.104 25.2 35.849 29.352 ;
     RECT  35.561 40.896 35.849 41.4 ;
     RECT  35.525 55.968 35.849 59.208 ;
     RECT  35.849 55.968 35.885 59.064 ;
     RECT  35.741 71.424 35.885 79.032 ;
     RECT  35.633 64.896 35.921 65.256 ;
     RECT  35.741 80.064 35.921 81.48 ;
     RECT  35.417 53.376 35.939 53.544 ;
     RECT  35.849 25.2 35.957 27.432 ;
     RECT  35.489 60.864 35.957 63.816 ;
     RECT  35.921 80.112 35.957 81.48 ;
     RECT  35.957 61.728 36.101 63.816 ;
     RECT  35.705 82.8 36.173 85.224 ;
     RECT  35.165 7.2 36.245 16.632 ;
     RECT  36.245 7.968 36.493 16.632 ;
     RECT  35.417 49.824 36.493 49.896 ;
     RECT  35.273 51.12 36.493 52.248 ;
     RECT  35.939 53.52 36.493 53.544 ;
     RECT  35.417 54.672 36.493 54.696 ;
     RECT  35.849 28.608 36.565 29.352 ;
     RECT  35.633 30.672 36.565 33.624 ;
     RECT  35.921 65.232 36.961 65.256 ;
     RECT  36.173 82.992 36.961 85.224 ;
     RECT  35.165 2.832 36.997 6.12 ;
     RECT  36.493 7.968 36.997 16.968 ;
     RECT  35.201 19.44 36.997 23.928 ;
     RECT  35.957 25.2 36.997 26.664 ;
     RECT  36.565 28.608 36.997 33.624 ;
     RECT  35.417 42.768 36.997 45 ;
     RECT  35.417 46.272 36.997 48.504 ;
     RECT  36.493 53.52 36.997 54.696 ;
     RECT  35.885 55.968 36.997 55.992 ;
     RECT  35.885 57.12 36.997 59.064 ;
     RECT  36.493 60.144 36.997 60.168 ;
     RECT  36.101 61.728 37.033 63.336 ;
     RECT  36.997 28.224 37.357 33.624 ;
     RECT  35.363 34.992 37.357 39.864 ;
     RECT  36.997 53.52 37.357 55.992 ;
     RECT  35.597 69.312 37.357 70.008 ;
     RECT  35.885 71.424 37.357 78.696 ;
     RECT  37.357 28.224 37.465 39.864 ;
     RECT  35.849 40.896 37.465 41.208 ;
     RECT  37.033 61.536 37.501 63.336 ;
     RECT  36.961 64.896 37.501 65.256 ;
     RECT  35.777 67.104 37.501 68.232 ;
     RECT  35.957 80.112 37.501 80.136 ;
     RECT  35.957 81.456 37.501 81.48 ;
     RECT  36.961 82.992 37.501 85.368 ;
     RECT  36.997 2.832 37.537 6.552 ;
     RECT  37.501 66.48 37.537 68.232 ;
     RECT  37.357 69.312 37.537 78.696 ;
     RECT  37.501 80.112 37.537 81.48 ;
     RECT  25.405 1.056 37.573 1.08 ;
     RECT  37.537 2.112 37.573 6.552 ;
     RECT  36.997 7.968 37.573 17.496 ;
     RECT  37.465 28.224 37.573 41.208 ;
     RECT  36.997 42.768 37.573 48.504 ;
     RECT  36.493 49.824 37.573 52.248 ;
     RECT  37.357 53.424 37.573 55.992 ;
     RECT  37.537 66.48 37.573 81.48 ;
     RECT  37.501 82.992 37.573 85.512 ;
     RECT  37.573 1.056 37.609 17.496 ;
     RECT  37.573 27.696 37.609 55.992 ;
     RECT  36.997 57.12 37.609 60.168 ;
     RECT  37.501 61.536 37.609 65.256 ;
     RECT  37.573 66.48 37.609 85.512 ;
     RECT  37.609 61.536 38.113 85.512 ;
     RECT  35.705 86.592 38.113 89.832 ;
     RECT  37.609 1.056 38.185 17.688 ;
     RECT  36.997 19.44 38.185 26.664 ;
     RECT  37.609 27.696 38.185 60.168 ;
     RECT  38.113 61.536 38.185 89.832 ;
     RECT  36.997 90.96 38.185 90.984 ;
     RECT  38.185 1.056 38.221 90.984 ;
     RECT  38.221 1.056 38.761 91.176 ;
     RECT  35.104 92.208 38.761 92.232 ;
     RECT  38.761 1.056 38.796 1.08 ;
     RECT  38.761 1.08 38.801 1.248 ;
     RECT  38.761 1.248 38.796 1.272 ;
     RECT  38.761 1.272 38.801 1.44 ;
     RECT  38.761 1.44 38.796 1.464 ;
     RECT  38.761 1.464 38.801 1.584 ;
     RECT  38.761 1.584 38.796 1.608 ;
     RECT  38.761 1.608 38.801 1.776 ;
     RECT  38.761 1.776 38.796 1.8 ;
     RECT  38.761 1.8 38.801 1.968 ;
     RECT  38.761 1.968 38.796 1.992 ;
     RECT  38.761 1.992 38.801 2.112 ;
     RECT  38.761 2.112 38.796 2.136 ;
     RECT  38.761 2.136 38.801 2.304 ;
     RECT  38.761 2.304 38.796 2.328 ;
     RECT  38.761 2.328 38.801 2.496 ;
     RECT  38.761 2.496 38.796 2.52 ;
     RECT  38.761 2.52 38.801 2.64 ;
     RECT  38.761 2.64 38.796 2.664 ;
     RECT  38.761 2.664 38.801 2.832 ;
     RECT  38.761 2.832 38.796 2.856 ;
     RECT  38.761 2.856 38.801 3.024 ;
     RECT  38.761 3.024 38.796 3.048 ;
     RECT  38.761 3.048 38.801 3.168 ;
     RECT  38.761 3.168 38.796 3.192 ;
     RECT  38.761 3.192 38.801 3.36 ;
     RECT  38.761 3.36 38.796 3.384 ;
     RECT  38.761 3.384 38.801 3.552 ;
     RECT  38.761 3.552 38.796 3.576 ;
     RECT  38.761 3.576 38.801 3.744 ;
     RECT  38.761 3.744 38.796 3.768 ;
     RECT  38.761 3.768 38.801 3.888 ;
     RECT  38.761 3.888 38.796 3.912 ;
     RECT  38.761 3.912 38.801 4.08 ;
     RECT  38.761 4.08 38.796 4.104 ;
     RECT  38.761 4.104 38.801 4.272 ;
     RECT  38.761 4.272 38.796 4.296 ;
     RECT  38.761 4.296 38.801 4.416 ;
     RECT  38.761 4.416 38.796 4.44 ;
     RECT  38.761 4.44 38.801 4.608 ;
     RECT  38.761 4.608 38.796 4.632 ;
     RECT  38.761 4.632 38.801 4.8 ;
     RECT  38.761 4.8 38.796 4.824 ;
     RECT  38.761 4.824 38.801 4.944 ;
     RECT  38.761 4.944 38.796 4.968 ;
     RECT  38.761 4.968 38.801 5.136 ;
     RECT  38.761 5.136 38.796 5.16 ;
     RECT  38.761 5.16 38.801 5.328 ;
     RECT  38.761 5.328 38.796 5.352 ;
     RECT  38.761 5.352 38.801 5.472 ;
     RECT  38.761 5.472 38.796 5.496 ;
     RECT  38.761 5.496 38.801 5.664 ;
     RECT  38.761 5.664 38.796 5.688 ;
     RECT  38.761 5.688 38.801 5.856 ;
     RECT  38.761 5.856 38.796 5.88 ;
     RECT  38.761 5.88 38.801 6 ;
     RECT  38.761 6 38.796 6.024 ;
     RECT  38.761 6.024 38.801 6.192 ;
     RECT  38.761 6.192 38.796 6.216 ;
     RECT  38.761 6.216 38.801 6.384 ;
     RECT  38.761 6.384 38.796 6.408 ;
     RECT  38.761 6.408 38.801 6.528 ;
     RECT  38.761 6.528 38.796 6.552 ;
     RECT  38.761 6.552 38.801 6.72 ;
     RECT  38.761 6.72 38.796 6.744 ;
     RECT  38.761 6.744 38.801 6.912 ;
     RECT  38.761 6.912 38.796 6.936 ;
     RECT  38.761 6.936 38.801 7.056 ;
     RECT  38.761 7.056 38.796 7.08 ;
     RECT  38.761 7.08 38.801 7.248 ;
     RECT  38.761 7.248 38.796 7.272 ;
     RECT  38.761 7.272 38.801 7.44 ;
     RECT  38.761 7.44 38.796 7.464 ;
     RECT  38.761 7.464 38.801 7.584 ;
     RECT  38.761 7.584 38.796 7.608 ;
     RECT  38.761 7.608 38.801 7.776 ;
     RECT  38.761 7.776 38.796 7.8 ;
     RECT  38.761 7.8 38.801 7.968 ;
     RECT  38.761 7.968 38.796 7.992 ;
     RECT  38.761 7.992 38.801 8.112 ;
     RECT  38.761 8.112 38.796 8.136 ;
     RECT  38.761 8.136 38.801 8.304 ;
     RECT  38.761 8.304 38.796 8.328 ;
     RECT  38.761 8.328 38.801 8.496 ;
     RECT  38.761 8.496 38.796 8.52 ;
     RECT  38.761 8.52 38.801 8.64 ;
     RECT  38.761 8.64 38.796 8.664 ;
     RECT  38.761 8.664 38.801 8.832 ;
     RECT  38.761 8.832 38.796 8.856 ;
     RECT  38.761 8.856 38.801 9.024 ;
     RECT  38.761 9.024 38.796 9.048 ;
     RECT  38.761 9.048 38.801 9.168 ;
     RECT  38.761 9.168 38.796 9.192 ;
     RECT  38.761 9.192 38.801 9.36 ;
     RECT  38.761 9.36 38.796 9.384 ;
     RECT  38.761 9.384 38.801 9.552 ;
     RECT  38.761 9.552 38.796 9.576 ;
     RECT  38.761 9.576 38.801 9.696 ;
     RECT  38.761 9.696 38.796 9.72 ;
     RECT  38.761 9.72 38.801 9.888 ;
     RECT  38.761 9.888 38.796 9.912 ;
     RECT  38.761 9.912 38.801 10.08 ;
     RECT  38.761 10.08 38.796 10.104 ;
     RECT  38.761 10.104 38.801 10.224 ;
     RECT  38.761 10.224 38.796 10.248 ;
     RECT  38.761 10.248 38.801 10.416 ;
     RECT  38.761 10.416 38.796 10.44 ;
     RECT  38.761 10.44 38.801 10.608 ;
     RECT  38.761 10.608 38.796 10.632 ;
     RECT  38.761 10.632 38.801 10.752 ;
     RECT  38.761 10.752 38.796 10.776 ;
     RECT  38.761 10.776 38.801 10.944 ;
     RECT  38.761 10.944 38.796 10.968 ;
     RECT  38.761 10.968 38.801 11.136 ;
     RECT  38.761 11.136 38.796 11.16 ;
     RECT  38.761 11.16 38.801 11.28 ;
     RECT  38.761 11.28 38.796 11.304 ;
     RECT  38.761 11.304 38.801 11.472 ;
     RECT  38.761 11.472 38.796 11.496 ;
     RECT  38.761 11.496 38.801 11.664 ;
     RECT  38.761 11.664 38.796 11.688 ;
     RECT  38.761 11.688 38.801 11.808 ;
     RECT  38.761 11.808 38.796 11.832 ;
     RECT  38.761 11.832 38.801 12 ;
     RECT  38.761 12 38.796 12.024 ;
     RECT  38.761 12.024 38.801 12.192 ;
     RECT  38.761 12.192 38.796 12.216 ;
     RECT  38.761 12.216 38.801 12.336 ;
     RECT  38.761 12.336 38.796 12.36 ;
     RECT  38.761 12.36 38.801 12.528 ;
     RECT  38.761 12.528 38.796 12.552 ;
     RECT  38.761 12.552 38.801 12.72 ;
     RECT  38.761 12.72 38.796 12.744 ;
     RECT  38.761 12.744 38.801 12.864 ;
     RECT  38.761 12.864 38.796 12.888 ;
     RECT  38.761 12.888 38.801 13.056 ;
     RECT  38.761 13.056 38.796 13.08 ;
     RECT  38.761 13.08 38.801 13.248 ;
     RECT  38.761 13.248 38.796 13.272 ;
     RECT  38.761 13.272 38.801 13.392 ;
     RECT  38.761 13.392 38.796 13.416 ;
     RECT  38.761 13.416 38.801 13.584 ;
     RECT  38.761 13.584 38.796 13.608 ;
     RECT  38.761 13.608 38.801 13.776 ;
     RECT  38.761 13.776 38.796 13.8 ;
     RECT  38.761 13.8 38.801 13.92 ;
     RECT  38.761 13.92 38.796 13.944 ;
     RECT  38.761 13.944 38.801 14.112 ;
     RECT  38.761 14.112 38.796 14.136 ;
     RECT  38.761 14.136 38.801 14.304 ;
     RECT  38.761 14.304 38.796 14.328 ;
     RECT  38.761 14.328 38.801 14.448 ;
     RECT  38.761 14.448 38.796 14.472 ;
     RECT  38.761 14.472 38.801 14.64 ;
     RECT  38.761 14.64 38.796 14.664 ;
     RECT  38.761 14.664 38.801 14.832 ;
     RECT  38.761 14.832 38.796 14.856 ;
     RECT  38.761 14.856 38.801 15.024 ;
     RECT  38.761 15.024 38.796 15.048 ;
     RECT  38.761 15.048 38.801 15.168 ;
     RECT  38.761 15.168 38.796 15.192 ;
     RECT  38.761 15.192 38.801 15.36 ;
     RECT  38.761 15.36 38.796 15.384 ;
     RECT  38.761 15.384 38.801 15.552 ;
     RECT  38.761 15.552 38.796 15.576 ;
     RECT  38.761 15.576 38.801 15.696 ;
     RECT  38.761 15.696 38.796 15.72 ;
     RECT  38.761 15.72 38.801 15.888 ;
     RECT  38.761 15.888 38.796 15.912 ;
     RECT  38.761 15.912 38.801 16.08 ;
     RECT  38.761 16.08 38.796 16.104 ;
     RECT  38.761 16.104 38.801 16.224 ;
     RECT  38.761 16.224 38.796 16.248 ;
     RECT  38.761 16.248 38.801 16.416 ;
     RECT  38.761 16.416 38.796 16.44 ;
     RECT  38.761 16.44 38.801 16.608 ;
     RECT  38.761 16.608 38.796 16.632 ;
     RECT  38.761 16.632 38.801 16.752 ;
     RECT  38.761 16.752 38.796 16.776 ;
     RECT  38.761 16.776 38.801 16.944 ;
     RECT  38.761 16.944 38.796 16.968 ;
     RECT  38.761 16.968 38.801 17.136 ;
     RECT  38.761 17.136 38.796 17.16 ;
     RECT  38.761 17.16 38.801 17.28 ;
     RECT  38.761 17.28 38.796 17.304 ;
     RECT  38.761 17.304 38.801 17.472 ;
     RECT  38.761 17.472 38.796 17.496 ;
     RECT  38.761 17.496 38.801 17.664 ;
     RECT  38.761 17.664 38.796 17.688 ;
     RECT  38.761 17.688 38.801 17.808 ;
     RECT  38.761 17.808 38.796 17.832 ;
     RECT  38.761 17.832 38.801 18 ;
     RECT  38.761 18 38.796 18.024 ;
     RECT  38.761 18.024 38.801 18.192 ;
     RECT  38.761 18.192 38.796 18.216 ;
     RECT  38.761 18.216 38.801 18.336 ;
     RECT  38.761 18.336 38.796 18.36 ;
     RECT  38.761 18.36 38.801 18.528 ;
     RECT  38.761 18.528 38.796 18.552 ;
     RECT  38.761 18.552 38.801 18.72 ;
     RECT  38.761 18.72 38.796 18.744 ;
     RECT  38.761 18.744 38.801 18.864 ;
     RECT  38.761 18.864 38.796 18.888 ;
     RECT  38.761 18.888 38.801 19.056 ;
     RECT  38.761 19.056 38.796 19.08 ;
     RECT  38.761 19.08 38.801 19.248 ;
     RECT  38.761 19.248 38.796 19.272 ;
     RECT  38.761 19.272 38.801 19.392 ;
     RECT  38.761 19.392 38.796 19.416 ;
     RECT  38.761 19.416 38.801 19.584 ;
     RECT  38.761 19.584 38.796 19.608 ;
     RECT  38.761 19.608 38.801 19.776 ;
     RECT  38.761 19.776 38.796 19.8 ;
     RECT  38.761 19.8 38.801 19.92 ;
     RECT  38.761 19.92 38.796 19.944 ;
     RECT  38.761 19.944 38.801 20.112 ;
     RECT  38.761 20.112 38.796 20.136 ;
     RECT  38.761 20.136 38.801 20.304 ;
     RECT  38.761 20.304 38.796 20.328 ;
     RECT  38.761 20.328 38.801 20.448 ;
     RECT  38.761 20.448 38.796 20.472 ;
     RECT  38.761 20.472 38.801 20.64 ;
     RECT  38.761 20.64 38.796 20.664 ;
     RECT  38.761 20.664 38.801 20.832 ;
     RECT  38.761 20.832 38.796 20.856 ;
     RECT  38.761 20.856 38.801 20.976 ;
     RECT  38.761 20.976 38.796 21 ;
     RECT  38.761 21 38.801 21.168 ;
     RECT  38.761 21.168 38.796 21.192 ;
     RECT  38.761 21.192 38.801 21.36 ;
     RECT  38.761 21.36 38.796 21.384 ;
     RECT  38.761 21.384 38.801 21.504 ;
     RECT  38.761 21.504 38.796 21.528 ;
     RECT  38.761 21.528 38.801 21.696 ;
     RECT  38.761 21.696 38.796 21.72 ;
     RECT  38.761 21.72 38.801 21.888 ;
     RECT  38.761 21.888 38.796 21.912 ;
     RECT  38.761 21.912 38.801 22.032 ;
     RECT  38.761 22.032 38.796 22.056 ;
     RECT  38.761 22.056 38.801 22.224 ;
     RECT  38.761 22.224 38.796 22.248 ;
     RECT  38.761 22.248 38.801 22.416 ;
     RECT  38.761 22.416 38.796 22.44 ;
     RECT  38.761 22.44 38.801 22.56 ;
     RECT  38.761 22.56 38.796 22.584 ;
     RECT  38.761 22.584 38.801 22.752 ;
     RECT  38.761 22.752 38.796 22.776 ;
     RECT  38.761 22.776 38.801 22.944 ;
     RECT  38.761 22.944 38.796 22.968 ;
     RECT  38.761 22.968 38.801 23.088 ;
     RECT  38.761 23.088 38.796 23.112 ;
     RECT  38.761 23.112 38.801 23.28 ;
     RECT  38.761 23.28 38.796 23.304 ;
     RECT  38.761 23.304 38.801 23.472 ;
     RECT  38.761 23.472 38.796 23.496 ;
     RECT  38.761 23.496 38.801 23.616 ;
     RECT  38.761 23.616 38.796 23.64 ;
     RECT  38.761 23.64 38.801 23.808 ;
     RECT  38.761 23.808 38.796 23.832 ;
     RECT  38.761 23.832 38.801 24 ;
     RECT  38.761 24 38.796 24.024 ;
     RECT  38.761 24.024 38.801 24.144 ;
     RECT  38.761 24.144 38.796 24.168 ;
     RECT  38.761 24.168 38.801 24.336 ;
     RECT  38.761 24.336 38.796 24.36 ;
     RECT  38.761 24.36 38.801 24.528 ;
     RECT  38.761 24.528 38.796 24.552 ;
     RECT  38.761 24.552 38.801 24.672 ;
     RECT  38.761 24.672 38.796 24.696 ;
     RECT  38.761 24.696 38.801 24.864 ;
     RECT  38.761 24.864 38.796 24.888 ;
     RECT  38.761 24.888 38.801 25.056 ;
     RECT  38.761 25.056 38.796 25.08 ;
     RECT  38.761 25.08 38.801 25.2 ;
     RECT  38.761 25.2 38.796 25.224 ;
     RECT  38.761 25.224 38.801 25.392 ;
     RECT  38.761 25.392 38.796 25.416 ;
     RECT  38.761 25.416 38.801 25.584 ;
     RECT  38.761 25.584 38.796 25.608 ;
     RECT  38.761 25.608 38.801 25.728 ;
     RECT  38.761 25.728 38.796 25.752 ;
     RECT  38.761 25.752 38.801 25.92 ;
     RECT  38.761 25.92 38.796 25.944 ;
     RECT  38.761 25.944 38.801 26.112 ;
     RECT  38.761 26.112 38.796 26.136 ;
     RECT  38.761 26.136 38.801 26.304 ;
     RECT  38.761 26.304 38.796 26.328 ;
     RECT  38.761 26.328 38.801 26.448 ;
     RECT  38.761 26.448 38.796 26.472 ;
     RECT  38.761 26.472 38.801 26.64 ;
     RECT  38.761 26.64 38.796 26.664 ;
     RECT  38.761 26.664 38.801 26.832 ;
     RECT  38.761 26.832 38.796 26.856 ;
     RECT  38.761 26.856 38.801 26.976 ;
     RECT  38.761 26.976 38.796 27 ;
     RECT  38.761 27 38.801 27.168 ;
     RECT  38.761 27.168 38.796 27.192 ;
     RECT  38.761 27.192 38.801 27.36 ;
     RECT  38.761 27.36 38.796 27.384 ;
     RECT  38.761 27.384 38.801 27.504 ;
     RECT  38.761 27.504 38.796 27.528 ;
     RECT  38.761 27.528 38.801 27.696 ;
     RECT  38.761 27.696 38.796 27.72 ;
     RECT  38.761 27.72 38.801 27.888 ;
     RECT  38.761 27.888 38.796 27.912 ;
     RECT  38.761 27.912 38.801 28.032 ;
     RECT  38.761 28.032 38.796 28.056 ;
     RECT  38.761 28.056 38.801 28.224 ;
     RECT  38.761 28.224 38.796 28.248 ;
     RECT  38.761 28.248 38.801 28.416 ;
     RECT  38.761 28.416 38.796 28.44 ;
     RECT  38.761 28.44 38.801 28.56 ;
     RECT  38.761 28.56 38.796 28.584 ;
     RECT  38.761 28.584 38.801 28.752 ;
     RECT  38.761 28.752 38.796 28.776 ;
     RECT  38.761 28.776 38.801 28.944 ;
     RECT  38.761 28.944 38.796 28.968 ;
     RECT  38.761 28.968 38.801 29.088 ;
     RECT  38.761 29.088 38.796 29.112 ;
     RECT  38.761 29.112 38.801 29.28 ;
     RECT  38.761 29.28 38.796 29.304 ;
     RECT  38.761 29.304 38.801 29.472 ;
     RECT  38.761 29.472 38.796 29.496 ;
     RECT  38.761 29.496 38.801 29.616 ;
     RECT  38.761 29.616 38.796 29.64 ;
     RECT  38.761 29.64 38.801 29.808 ;
     RECT  38.761 29.808 38.796 29.832 ;
     RECT  38.761 29.832 38.801 30 ;
     RECT  38.761 30 38.796 30.024 ;
     RECT  38.761 30.024 38.801 30.144 ;
     RECT  38.761 30.144 38.796 30.168 ;
     RECT  38.761 30.168 38.801 30.336 ;
     RECT  38.761 30.336 38.796 30.36 ;
     RECT  38.761 30.36 38.801 30.528 ;
     RECT  38.761 30.528 38.796 30.552 ;
     RECT  38.761 30.552 38.801 30.672 ;
     RECT  38.761 30.672 38.796 30.696 ;
     RECT  38.761 30.696 38.801 30.864 ;
     RECT  38.761 30.864 38.796 30.888 ;
     RECT  38.761 30.888 38.801 31.056 ;
     RECT  38.761 31.056 38.796 31.08 ;
     RECT  38.761 31.08 38.801 31.2 ;
     RECT  38.761 31.2 38.796 31.224 ;
     RECT  38.761 31.224 38.801 31.392 ;
     RECT  38.761 31.392 38.796 31.416 ;
     RECT  38.761 31.416 38.801 31.584 ;
     RECT  38.761 31.584 38.796 31.608 ;
     RECT  38.761 31.608 38.801 31.728 ;
     RECT  38.761 31.728 38.796 31.752 ;
     RECT  38.761 31.752 38.801 31.92 ;
     RECT  38.761 31.92 38.796 31.944 ;
     RECT  38.761 31.944 38.801 32.112 ;
     RECT  38.761 32.112 38.796 32.136 ;
     RECT  38.761 32.136 38.801 32.256 ;
     RECT  38.761 32.256 38.796 32.28 ;
     RECT  38.761 32.28 38.801 32.448 ;
     RECT  38.761 32.448 38.796 32.472 ;
     RECT  38.761 32.472 38.801 32.64 ;
     RECT  38.761 32.64 38.796 32.664 ;
     RECT  38.761 32.664 38.801 32.784 ;
     RECT  38.761 32.784 38.796 32.808 ;
     RECT  38.761 32.808 38.801 32.976 ;
     RECT  38.761 32.976 38.796 33 ;
     RECT  38.761 33 38.801 33.168 ;
     RECT  38.761 33.168 38.796 33.192 ;
     RECT  38.761 33.192 38.801 33.312 ;
     RECT  38.761 33.312 38.796 33.336 ;
     RECT  38.761 33.336 38.801 33.504 ;
     RECT  38.761 33.504 38.796 33.528 ;
     RECT  38.761 33.528 38.801 33.696 ;
     RECT  38.761 33.696 38.796 33.72 ;
     RECT  38.761 33.72 38.801 33.84 ;
     RECT  38.761 33.84 38.796 33.864 ;
     RECT  38.761 33.864 38.801 34.032 ;
     RECT  38.761 34.032 38.796 34.056 ;
     RECT  38.761 34.056 38.801 34.224 ;
     RECT  38.761 34.224 38.796 34.248 ;
     RECT  38.761 34.248 38.801 34.368 ;
     RECT  38.761 34.368 38.796 34.392 ;
     RECT  38.761 34.392 38.801 34.56 ;
     RECT  38.761 34.56 38.796 34.584 ;
     RECT  38.761 34.584 38.801 34.752 ;
     RECT  38.761 34.752 38.796 34.776 ;
     RECT  38.761 34.776 38.801 34.896 ;
     RECT  38.761 34.896 38.796 34.92 ;
     RECT  38.761 34.92 38.801 35.088 ;
     RECT  38.761 35.088 38.796 35.112 ;
     RECT  38.761 35.112 38.801 35.28 ;
     RECT  38.761 35.28 38.796 35.304 ;
     RECT  38.761 35.304 38.801 35.424 ;
     RECT  38.761 35.424 38.796 35.448 ;
     RECT  38.761 35.448 38.801 35.616 ;
     RECT  38.761 35.616 38.796 35.64 ;
     RECT  38.761 35.64 38.801 35.808 ;
     RECT  38.761 35.808 38.796 35.832 ;
     RECT  38.761 35.832 38.801 35.952 ;
     RECT  38.761 35.952 38.796 35.976 ;
     RECT  38.761 35.976 38.801 36.144 ;
     RECT  38.761 36.144 38.796 36.168 ;
     RECT  38.761 36.168 38.801 36.336 ;
     RECT  38.761 36.336 38.796 36.36 ;
     RECT  38.761 36.36 38.801 36.48 ;
     RECT  38.761 36.48 38.796 36.504 ;
     RECT  38.761 36.504 38.801 36.672 ;
     RECT  38.761 36.672 38.796 36.696 ;
     RECT  38.761 36.696 38.801 36.864 ;
     RECT  38.761 36.864 38.796 36.888 ;
     RECT  38.761 36.888 38.801 37.008 ;
     RECT  38.761 37.008 38.796 37.032 ;
     RECT  38.761 37.032 38.801 37.2 ;
     RECT  38.761 37.2 38.796 37.224 ;
     RECT  38.761 37.224 38.801 37.392 ;
     RECT  38.761 37.392 38.796 37.416 ;
     RECT  38.761 37.416 38.801 37.584 ;
     RECT  38.761 37.584 38.796 37.608 ;
     RECT  38.761 37.608 38.801 37.728 ;
     RECT  38.761 37.728 38.796 37.752 ;
     RECT  38.761 37.752 38.801 37.92 ;
     RECT  38.761 37.92 38.796 37.944 ;
     RECT  38.761 37.944 38.801 38.112 ;
     RECT  38.761 38.112 38.796 38.136 ;
     RECT  38.761 38.136 38.801 38.256 ;
     RECT  38.761 38.256 38.796 38.28 ;
     RECT  38.761 38.28 38.801 38.448 ;
     RECT  38.761 38.448 38.796 38.472 ;
     RECT  38.761 38.472 38.801 38.64 ;
     RECT  38.761 38.64 38.796 38.664 ;
     RECT  38.761 38.664 38.801 38.784 ;
     RECT  38.761 38.784 38.796 38.808 ;
     RECT  38.761 38.808 38.801 38.976 ;
     RECT  38.761 38.976 38.796 39 ;
     RECT  38.761 39 38.801 39.168 ;
     RECT  38.761 39.168 38.796 39.192 ;
     RECT  38.761 39.192 38.801 39.312 ;
     RECT  38.761 39.312 38.796 39.336 ;
     RECT  38.761 39.336 38.801 39.504 ;
     RECT  38.761 39.504 38.796 39.528 ;
     RECT  38.761 39.528 38.801 39.696 ;
     RECT  38.761 39.696 38.796 39.72 ;
     RECT  38.761 39.72 38.801 39.84 ;
     RECT  38.761 39.84 38.796 39.864 ;
     RECT  38.761 39.864 38.801 40.032 ;
     RECT  38.761 40.032 38.796 40.056 ;
     RECT  38.761 40.056 38.801 40.224 ;
     RECT  38.761 40.224 38.796 40.248 ;
     RECT  38.761 40.248 38.801 40.368 ;
     RECT  38.761 40.368 38.796 40.392 ;
     RECT  38.761 40.392 38.801 40.56 ;
     RECT  38.761 40.56 38.796 40.584 ;
     RECT  38.761 40.584 38.801 40.752 ;
     RECT  38.761 40.752 38.796 40.776 ;
     RECT  38.761 40.776 38.801 40.896 ;
     RECT  38.761 40.896 38.796 40.92 ;
     RECT  38.761 40.92 38.801 41.088 ;
     RECT  38.761 41.088 38.796 41.112 ;
     RECT  38.761 41.112 38.801 41.28 ;
     RECT  38.761 41.28 38.796 41.304 ;
     RECT  38.761 41.304 38.801 41.424 ;
     RECT  38.761 41.424 38.796 41.448 ;
     RECT  38.761 41.448 38.801 41.616 ;
     RECT  38.761 41.616 38.796 41.64 ;
     RECT  38.761 41.64 38.801 41.808 ;
     RECT  38.761 41.808 38.796 41.832 ;
     RECT  38.761 41.832 38.801 41.952 ;
     RECT  38.761 41.952 38.796 41.976 ;
     RECT  38.761 41.976 38.801 42.144 ;
     RECT  38.761 42.144 38.796 42.168 ;
     RECT  38.761 42.168 38.801 42.336 ;
     RECT  38.761 42.336 38.796 42.36 ;
     RECT  38.761 42.36 38.801 42.48 ;
     RECT  38.761 42.48 38.796 42.504 ;
     RECT  38.761 42.504 38.801 42.672 ;
     RECT  38.761 42.672 38.796 42.696 ;
     RECT  38.761 42.696 38.801 42.864 ;
     RECT  38.761 42.864 38.796 42.888 ;
     RECT  38.761 42.888 38.801 43.008 ;
     RECT  38.761 43.008 38.796 43.032 ;
     RECT  38.761 43.032 38.801 43.2 ;
     RECT  38.761 43.2 38.796 43.224 ;
     RECT  38.761 43.224 38.801 43.392 ;
     RECT  38.761 43.392 38.796 43.416 ;
     RECT  38.761 43.416 38.801 43.536 ;
     RECT  38.761 43.536 38.796 43.56 ;
     RECT  38.761 43.56 38.801 43.728 ;
     RECT  38.761 43.728 38.796 43.752 ;
     RECT  38.761 43.752 38.801 43.92 ;
     RECT  38.761 43.92 38.796 43.944 ;
     RECT  38.761 43.944 38.801 44.064 ;
     RECT  38.761 44.064 38.796 44.088 ;
     RECT  38.761 44.088 38.801 44.256 ;
     RECT  38.761 44.256 38.796 44.28 ;
     RECT  38.761 44.28 38.801 44.448 ;
     RECT  38.761 44.448 38.796 44.472 ;
     RECT  38.761 44.472 38.801 44.592 ;
     RECT  38.761 44.592 38.796 44.616 ;
     RECT  38.761 44.616 38.801 44.784 ;
     RECT  38.761 44.784 38.796 44.808 ;
     RECT  38.761 44.808 38.801 44.976 ;
     RECT  38.761 44.976 38.796 45 ;
     RECT  38.761 45 38.801 45.12 ;
     RECT  38.761 45.12 38.796 45.144 ;
     RECT  38.761 45.144 38.801 45.312 ;
     RECT  38.761 45.312 38.796 45.336 ;
     RECT  38.761 45.336 38.801 45.504 ;
     RECT  38.761 45.504 38.796 45.528 ;
     RECT  38.761 45.528 38.801 45.648 ;
     RECT  38.761 45.648 38.796 45.672 ;
     RECT  38.761 45.672 38.801 45.84 ;
     RECT  38.761 45.84 38.796 45.864 ;
     RECT  38.761 45.864 38.801 46.032 ;
     RECT  38.761 46.032 38.796 46.056 ;
     RECT  38.761 46.056 38.801 46.176 ;
     RECT  38.761 46.176 38.796 46.2 ;
     RECT  38.761 46.2 38.801 46.368 ;
     RECT  38.761 46.368 38.796 46.392 ;
     RECT  38.761 46.392 38.801 46.56 ;
     RECT  38.761 46.56 38.796 46.584 ;
     RECT  38.761 46.584 38.801 46.704 ;
     RECT  38.761 46.704 38.796 46.728 ;
     RECT  38.761 46.728 38.801 46.896 ;
     RECT  38.761 46.896 38.796 46.92 ;
     RECT  38.761 46.92 38.801 47.088 ;
     RECT  38.761 47.088 38.796 47.112 ;
     RECT  38.761 47.112 38.801 47.232 ;
     RECT  38.761 47.232 38.796 47.256 ;
     RECT  38.761 47.256 38.801 47.424 ;
     RECT  38.761 47.424 38.796 47.448 ;
     RECT  38.761 47.448 38.801 47.616 ;
     RECT  38.761 47.616 38.796 47.64 ;
     RECT  38.761 47.64 38.801 47.76 ;
     RECT  38.761 47.76 38.796 47.784 ;
     RECT  38.761 47.784 38.801 47.952 ;
     RECT  38.761 47.952 38.796 47.976 ;
     RECT  38.761 47.976 38.801 48.144 ;
     RECT  38.761 48.144 38.796 48.168 ;
     RECT  38.761 48.168 38.801 48.288 ;
     RECT  38.761 48.288 38.796 48.312 ;
     RECT  38.761 48.312 38.801 48.48 ;
     RECT  38.761 48.48 38.796 48.504 ;
     RECT  38.761 48.504 38.801 48.672 ;
     RECT  38.761 48.672 38.796 48.696 ;
     RECT  38.761 48.696 38.801 48.864 ;
     RECT  38.761 48.864 38.796 48.888 ;
     RECT  38.761 48.888 38.801 49.008 ;
     RECT  38.761 49.008 38.796 49.032 ;
     RECT  38.761 49.032 38.801 49.2 ;
     RECT  38.761 49.2 38.796 49.224 ;
     RECT  38.761 49.224 38.801 49.392 ;
     RECT  38.761 49.392 38.796 49.416 ;
     RECT  38.761 49.416 38.801 49.536 ;
     RECT  38.761 49.536 38.796 49.56 ;
     RECT  38.761 49.56 38.801 49.728 ;
     RECT  38.761 49.728 38.796 49.752 ;
     RECT  38.761 49.752 38.801 49.92 ;
     RECT  38.761 49.92 38.796 49.944 ;
     RECT  38.761 49.944 38.801 50.064 ;
     RECT  38.761 50.064 38.796 50.088 ;
     RECT  38.761 50.088 38.801 50.256 ;
     RECT  38.761 50.256 38.796 50.28 ;
     RECT  38.761 50.28 38.801 50.448 ;
     RECT  38.761 50.448 38.796 50.472 ;
     RECT  38.761 50.472 38.801 50.592 ;
     RECT  38.761 50.592 38.796 50.616 ;
     RECT  38.761 50.616 38.801 50.784 ;
     RECT  38.761 50.784 38.796 50.808 ;
     RECT  38.761 50.808 38.801 50.976 ;
     RECT  38.761 50.976 38.796 51 ;
     RECT  38.761 51 38.801 51.12 ;
     RECT  38.761 51.12 38.796 51.144 ;
     RECT  38.761 51.144 38.801 51.312 ;
     RECT  38.761 51.312 38.796 51.336 ;
     RECT  38.761 51.336 38.801 51.504 ;
     RECT  38.761 51.504 38.796 51.528 ;
     RECT  38.761 51.528 38.801 51.648 ;
     RECT  38.761 51.648 38.796 51.672 ;
     RECT  38.761 51.672 38.801 51.84 ;
     RECT  38.761 51.84 38.796 51.864 ;
     RECT  38.761 51.864 38.801 52.032 ;
     RECT  38.761 52.032 38.796 52.056 ;
     RECT  38.761 52.056 38.801 52.176 ;
     RECT  38.761 52.176 38.796 52.2 ;
     RECT  38.761 52.2 38.801 52.368 ;
     RECT  38.761 52.368 38.796 52.392 ;
     RECT  38.761 52.392 38.801 52.56 ;
     RECT  38.761 52.56 38.796 52.584 ;
     RECT  38.761 52.584 38.801 52.704 ;
     RECT  38.761 52.704 38.796 52.728 ;
     RECT  38.761 52.728 38.801 52.896 ;
     RECT  38.761 52.896 38.796 52.92 ;
     RECT  38.761 52.92 38.801 53.088 ;
     RECT  38.761 53.088 38.796 53.112 ;
     RECT  38.761 53.112 38.801 53.232 ;
     RECT  38.761 53.232 38.796 53.256 ;
     RECT  38.761 53.256 38.801 53.424 ;
     RECT  38.761 53.424 38.796 53.448 ;
     RECT  38.761 53.448 38.801 53.616 ;
     RECT  38.761 53.616 38.796 53.64 ;
     RECT  38.761 53.64 38.801 53.76 ;
     RECT  38.761 53.76 38.796 53.784 ;
     RECT  38.761 53.784 38.801 53.952 ;
     RECT  38.761 53.952 38.796 53.976 ;
     RECT  38.761 53.976 38.801 54.144 ;
     RECT  38.761 54.144 38.796 54.168 ;
     RECT  38.761 54.168 38.801 54.288 ;
     RECT  38.761 54.288 38.796 54.312 ;
     RECT  38.761 54.312 38.801 54.48 ;
     RECT  38.761 54.48 38.796 54.504 ;
     RECT  38.761 54.504 38.801 54.672 ;
     RECT  38.761 54.672 38.796 54.696 ;
     RECT  38.761 54.696 38.801 54.816 ;
     RECT  38.761 54.816 38.796 54.84 ;
     RECT  38.761 54.84 38.801 55.008 ;
     RECT  38.761 55.008 38.796 55.032 ;
     RECT  38.761 55.032 38.801 55.2 ;
     RECT  38.761 55.2 38.796 55.224 ;
     RECT  38.761 55.224 38.801 55.344 ;
     RECT  38.761 55.344 38.796 55.368 ;
     RECT  38.761 55.368 38.801 55.536 ;
     RECT  38.761 55.536 38.796 55.56 ;
     RECT  38.761 55.56 38.801 55.728 ;
     RECT  38.761 55.728 38.796 55.752 ;
     RECT  38.761 55.752 38.801 55.872 ;
     RECT  38.761 55.872 38.796 55.896 ;
     RECT  38.761 55.896 38.801 56.064 ;
     RECT  38.761 56.064 38.796 56.088 ;
     RECT  38.761 56.088 38.801 56.256 ;
     RECT  38.761 56.256 38.796 56.28 ;
     RECT  38.761 56.28 38.801 56.4 ;
     RECT  38.761 56.4 38.796 56.424 ;
     RECT  38.761 56.424 38.801 56.592 ;
     RECT  38.761 56.592 38.796 56.616 ;
     RECT  38.761 56.616 38.801 56.784 ;
     RECT  38.761 56.784 38.796 56.808 ;
     RECT  38.761 56.808 38.801 56.928 ;
     RECT  38.761 56.928 38.796 56.952 ;
     RECT  38.761 56.952 38.801 57.12 ;
     RECT  38.761 57.12 38.796 57.144 ;
     RECT  38.761 57.144 38.801 57.312 ;
     RECT  38.761 57.312 38.796 57.336 ;
     RECT  38.761 57.336 38.801 57.456 ;
     RECT  38.761 57.456 38.796 57.48 ;
     RECT  38.761 57.48 38.801 57.648 ;
     RECT  38.761 57.648 38.796 57.672 ;
     RECT  38.761 57.672 38.801 57.84 ;
     RECT  38.761 57.84 38.796 57.864 ;
     RECT  38.761 57.864 38.801 57.984 ;
     RECT  38.761 57.984 38.796 58.008 ;
     RECT  38.761 58.008 38.801 58.176 ;
     RECT  38.761 58.176 38.796 58.2 ;
     RECT  38.761 58.2 38.801 58.368 ;
     RECT  38.761 58.368 38.796 58.392 ;
     RECT  38.761 58.392 38.801 58.512 ;
     RECT  38.761 58.512 38.796 58.536 ;
     RECT  38.761 58.536 38.801 58.704 ;
     RECT  38.761 58.704 38.796 58.728 ;
     RECT  38.761 58.728 38.801 58.896 ;
     RECT  38.761 58.896 38.796 58.92 ;
     RECT  38.761 58.92 38.801 59.04 ;
     RECT  38.761 59.04 38.796 59.064 ;
     RECT  38.761 59.064 38.801 59.232 ;
     RECT  38.761 59.232 38.796 59.256 ;
     RECT  38.761 59.256 38.801 59.424 ;
     RECT  38.761 59.424 38.796 59.448 ;
     RECT  38.761 59.448 38.801 59.568 ;
     RECT  38.761 59.568 38.796 59.592 ;
     RECT  38.761 59.592 38.801 59.76 ;
     RECT  38.761 59.76 38.796 59.784 ;
     RECT  38.761 59.784 38.801 59.952 ;
     RECT  38.761 59.952 38.796 59.976 ;
     RECT  38.761 59.976 38.801 60.144 ;
     RECT  38.761 60.144 38.796 60.168 ;
     RECT  38.761 60.168 38.801 60.288 ;
     RECT  38.761 60.288 38.796 60.312 ;
     RECT  38.761 60.312 38.801 60.48 ;
     RECT  38.761 60.48 38.796 60.504 ;
     RECT  38.761 60.504 38.801 60.672 ;
     RECT  38.761 60.672 38.796 60.696 ;
     RECT  38.761 60.696 38.801 60.816 ;
     RECT  38.761 60.816 38.796 60.84 ;
     RECT  38.761 60.84 38.801 61.008 ;
     RECT  38.761 61.008 38.796 61.032 ;
     RECT  38.761 61.032 38.801 61.2 ;
     RECT  38.761 61.2 38.796 61.224 ;
     RECT  38.761 61.224 38.801 61.344 ;
     RECT  38.761 61.344 38.796 61.368 ;
     RECT  38.761 61.368 38.801 61.536 ;
     RECT  38.761 61.536 38.796 61.56 ;
     RECT  38.761 61.56 38.801 61.728 ;
     RECT  38.761 61.728 38.796 61.752 ;
     RECT  38.761 61.752 38.801 61.872 ;
     RECT  38.761 61.872 38.796 61.896 ;
     RECT  38.761 61.896 38.801 62.064 ;
     RECT  38.761 62.064 38.796 62.088 ;
     RECT  38.761 62.088 38.801 62.256 ;
     RECT  38.761 62.256 38.796 62.28 ;
     RECT  38.761 62.28 38.801 62.4 ;
     RECT  38.761 62.4 38.796 62.424 ;
     RECT  38.761 62.424 38.801 62.592 ;
     RECT  38.761 62.592 38.796 62.616 ;
     RECT  38.761 62.616 38.801 62.784 ;
     RECT  38.761 62.784 38.796 62.808 ;
     RECT  38.761 62.808 38.801 62.928 ;
     RECT  38.761 62.928 38.796 62.952 ;
     RECT  38.761 62.952 38.801 63.12 ;
     RECT  38.761 63.12 38.796 63.144 ;
     RECT  38.761 63.144 38.801 63.312 ;
     RECT  38.761 63.312 38.796 63.336 ;
     RECT  38.761 63.336 38.801 63.456 ;
     RECT  38.761 63.456 38.796 63.48 ;
     RECT  38.761 63.48 38.801 63.648 ;
     RECT  38.761 63.648 38.796 63.672 ;
     RECT  38.761 63.672 38.801 63.84 ;
     RECT  38.761 63.84 38.796 63.864 ;
     RECT  38.761 63.864 38.801 63.984 ;
     RECT  38.761 63.984 38.796 64.008 ;
     RECT  38.761 64.008 38.801 64.176 ;
     RECT  38.761 64.176 38.796 64.2 ;
     RECT  38.761 64.2 38.801 64.368 ;
     RECT  38.761 64.368 38.796 64.392 ;
     RECT  38.761 64.392 38.801 64.512 ;
     RECT  38.761 64.512 38.796 64.536 ;
     RECT  38.761 64.536 38.801 64.704 ;
     RECT  38.761 64.704 38.796 64.728 ;
     RECT  38.761 64.728 38.801 64.896 ;
     RECT  38.761 64.896 38.796 64.92 ;
     RECT  38.761 64.92 38.801 65.04 ;
     RECT  38.761 65.04 38.796 65.064 ;
     RECT  38.761 65.064 38.801 65.232 ;
     RECT  38.761 65.232 38.796 65.256 ;
     RECT  38.761 65.256 38.801 65.424 ;
     RECT  38.761 65.424 38.796 65.448 ;
     RECT  38.761 65.448 38.801 65.568 ;
     RECT  38.761 65.568 38.796 65.592 ;
     RECT  38.761 65.592 38.801 65.76 ;
     RECT  38.761 65.76 38.796 65.784 ;
     RECT  38.761 65.784 38.801 65.952 ;
     RECT  38.761 65.952 38.796 65.976 ;
     RECT  38.761 65.976 38.801 66.096 ;
     RECT  38.761 66.096 38.796 66.12 ;
     RECT  38.761 66.12 38.801 66.288 ;
     RECT  38.761 66.288 38.796 66.312 ;
     RECT  38.761 66.312 38.801 66.48 ;
     RECT  38.761 66.48 38.796 66.504 ;
     RECT  38.761 66.504 38.801 66.624 ;
     RECT  38.761 66.624 38.796 66.648 ;
     RECT  38.761 66.648 38.801 66.816 ;
     RECT  38.761 66.816 38.796 66.84 ;
     RECT  38.761 66.84 38.801 67.008 ;
     RECT  38.761 67.008 38.796 67.032 ;
     RECT  38.761 67.032 38.801 67.152 ;
     RECT  38.761 67.152 38.796 67.176 ;
     RECT  38.761 67.176 38.801 67.344 ;
     RECT  38.761 67.344 38.796 67.368 ;
     RECT  38.761 67.368 38.801 67.536 ;
     RECT  38.761 67.536 38.796 67.56 ;
     RECT  38.761 67.56 38.801 67.68 ;
     RECT  38.761 67.68 38.796 67.704 ;
     RECT  38.761 67.704 38.801 67.872 ;
     RECT  38.761 67.872 38.796 67.896 ;
     RECT  38.761 67.896 38.801 68.064 ;
     RECT  38.761 68.064 38.796 68.088 ;
     RECT  38.761 68.088 38.801 68.208 ;
     RECT  38.761 68.208 38.796 68.232 ;
     RECT  38.761 68.232 38.801 68.4 ;
     RECT  38.761 68.4 38.796 68.424 ;
     RECT  38.761 68.424 38.801 68.592 ;
     RECT  38.761 68.592 38.796 68.616 ;
     RECT  38.761 68.616 38.801 68.736 ;
     RECT  38.761 68.736 38.796 68.76 ;
     RECT  38.761 68.76 38.801 68.928 ;
     RECT  38.761 68.928 38.796 68.952 ;
     RECT  38.761 68.952 38.801 69.12 ;
     RECT  38.761 69.12 38.796 69.144 ;
     RECT  38.761 69.144 38.801 69.264 ;
     RECT  38.761 69.264 38.796 69.288 ;
     RECT  38.761 69.288 38.801 69.456 ;
     RECT  38.761 69.456 38.796 69.48 ;
     RECT  38.761 69.48 38.801 69.648 ;
     RECT  38.761 69.648 38.796 69.672 ;
     RECT  38.761 69.672 38.801 69.792 ;
     RECT  38.761 69.792 38.796 69.816 ;
     RECT  38.761 69.816 38.801 69.984 ;
     RECT  38.761 69.984 38.796 70.008 ;
     RECT  38.761 70.008 38.801 70.176 ;
     RECT  38.761 70.176 38.796 70.2 ;
     RECT  38.761 70.2 38.801 70.32 ;
     RECT  38.761 70.32 38.796 70.344 ;
     RECT  38.761 70.344 38.801 70.512 ;
     RECT  38.761 70.512 38.796 70.536 ;
     RECT  38.761 70.536 38.801 70.704 ;
     RECT  38.761 70.704 38.796 70.728 ;
     RECT  38.761 70.728 38.801 70.848 ;
     RECT  38.761 70.848 38.796 70.872 ;
     RECT  38.761 70.872 38.801 71.04 ;
     RECT  38.761 71.04 38.796 71.064 ;
     RECT  38.761 71.064 38.801 71.232 ;
     RECT  38.761 71.232 38.796 71.256 ;
     RECT  38.761 71.256 38.801 71.424 ;
     RECT  38.761 71.424 38.796 71.448 ;
     RECT  38.761 71.448 38.801 71.568 ;
     RECT  38.761 71.568 38.796 71.592 ;
     RECT  38.761 71.592 38.801 71.76 ;
     RECT  38.761 71.76 38.796 71.784 ;
     RECT  38.761 71.784 38.801 71.952 ;
     RECT  38.761 71.952 38.796 71.976 ;
     RECT  38.761 71.976 38.801 72.096 ;
     RECT  38.761 72.096 38.796 72.12 ;
     RECT  38.761 72.12 38.801 72.288 ;
     RECT  38.761 72.288 38.796 72.312 ;
     RECT  38.761 72.312 38.801 72.48 ;
     RECT  38.761 72.48 38.796 72.504 ;
     RECT  38.761 72.504 38.801 72.624 ;
     RECT  38.761 72.624 38.796 72.648 ;
     RECT  38.761 72.648 38.801 72.816 ;
     RECT  38.761 72.816 38.796 72.84 ;
     RECT  38.761 72.84 38.801 73.008 ;
     RECT  38.761 73.008 38.796 73.032 ;
     RECT  38.761 73.032 38.801 73.152 ;
     RECT  38.761 73.152 38.796 73.176 ;
     RECT  38.761 73.176 38.801 73.344 ;
     RECT  38.761 73.344 38.796 73.368 ;
     RECT  38.761 73.368 38.801 73.536 ;
     RECT  38.761 73.536 38.796 73.56 ;
     RECT  38.761 73.56 38.801 73.68 ;
     RECT  38.761 73.68 38.796 73.704 ;
     RECT  38.761 73.704 38.801 73.872 ;
     RECT  38.761 73.872 38.796 73.896 ;
     RECT  38.761 73.896 38.801 74.064 ;
     RECT  38.761 74.064 38.796 74.088 ;
     RECT  38.761 74.088 38.801 74.208 ;
     RECT  38.761 74.208 38.796 74.232 ;
     RECT  38.761 74.232 38.801 74.4 ;
     RECT  38.761 74.4 38.796 74.424 ;
     RECT  38.761 74.424 38.801 74.592 ;
     RECT  38.761 74.592 38.796 74.616 ;
     RECT  38.761 74.616 38.801 74.736 ;
     RECT  38.761 74.736 38.796 74.76 ;
     RECT  38.761 74.76 38.801 74.928 ;
     RECT  38.761 74.928 38.796 74.952 ;
     RECT  38.761 74.952 38.801 75.12 ;
     RECT  38.761 75.12 38.796 75.144 ;
     RECT  38.761 75.144 38.801 75.264 ;
     RECT  38.761 75.264 38.796 75.288 ;
     RECT  38.761 75.288 38.801 75.456 ;
     RECT  38.761 75.456 38.796 75.48 ;
     RECT  38.761 75.48 38.801 75.648 ;
     RECT  38.761 75.648 38.796 75.672 ;
     RECT  38.761 75.672 38.801 75.792 ;
     RECT  38.761 75.792 38.796 75.816 ;
     RECT  38.761 75.816 38.801 75.984 ;
     RECT  38.761 75.984 38.796 76.008 ;
     RECT  38.761 76.008 38.801 76.176 ;
     RECT  38.761 76.176 38.796 76.2 ;
     RECT  38.761 76.2 38.801 76.32 ;
     RECT  38.761 76.32 38.796 76.344 ;
     RECT  38.761 76.344 38.801 76.512 ;
     RECT  38.761 76.512 38.796 76.536 ;
     RECT  38.761 76.536 38.801 76.704 ;
     RECT  38.761 76.704 38.796 76.728 ;
     RECT  38.761 76.728 38.801 76.848 ;
     RECT  38.761 76.848 38.796 76.872 ;
     RECT  38.761 76.872 38.801 77.04 ;
     RECT  38.761 77.04 38.796 77.064 ;
     RECT  38.761 77.064 38.801 77.232 ;
     RECT  38.761 77.232 38.796 77.256 ;
     RECT  38.761 77.256 38.801 77.376 ;
     RECT  38.761 77.376 38.796 77.4 ;
     RECT  38.761 77.4 38.801 77.568 ;
     RECT  38.761 77.568 38.796 77.592 ;
     RECT  38.761 77.592 38.801 77.76 ;
     RECT  38.761 77.76 38.796 77.784 ;
     RECT  38.761 77.784 38.801 77.904 ;
     RECT  38.761 77.904 38.796 77.928 ;
     RECT  38.761 77.928 38.801 78.096 ;
     RECT  38.761 78.096 38.796 78.12 ;
     RECT  38.761 78.12 38.801 78.288 ;
     RECT  38.761 78.288 38.796 78.312 ;
     RECT  38.761 78.312 38.801 78.432 ;
     RECT  38.761 78.432 38.796 78.456 ;
     RECT  38.761 78.456 38.801 78.624 ;
     RECT  38.761 78.624 38.796 78.648 ;
     RECT  38.761 78.648 38.801 78.816 ;
     RECT  38.761 78.816 38.796 78.84 ;
     RECT  38.761 78.84 38.801 78.96 ;
     RECT  38.761 78.96 38.796 78.984 ;
     RECT  38.761 78.984 38.801 79.152 ;
     RECT  38.761 79.152 38.796 79.176 ;
     RECT  38.761 79.176 38.801 79.344 ;
     RECT  38.761 79.344 38.796 79.368 ;
     RECT  38.761 79.368 38.801 79.488 ;
     RECT  38.761 79.488 38.796 79.512 ;
     RECT  38.761 79.512 38.801 79.68 ;
     RECT  38.761 79.68 38.796 79.704 ;
     RECT  38.761 79.704 38.801 79.872 ;
     RECT  38.761 79.872 38.796 79.896 ;
     RECT  38.761 79.896 38.801 80.016 ;
     RECT  38.761 80.016 38.796 80.04 ;
     RECT  38.761 80.04 38.801 80.208 ;
     RECT  38.761 80.208 38.796 80.232 ;
     RECT  38.761 80.232 38.801 80.4 ;
     RECT  38.761 80.4 38.796 80.424 ;
     RECT  38.761 80.424 38.801 80.544 ;
     RECT  38.761 80.544 38.796 80.568 ;
     RECT  38.761 80.568 38.801 80.736 ;
     RECT  38.761 80.736 38.796 80.76 ;
     RECT  38.761 80.76 38.801 80.928 ;
     RECT  38.761 80.928 38.796 80.952 ;
     RECT  38.761 80.952 38.801 81.072 ;
     RECT  38.761 81.072 38.796 81.096 ;
     RECT  38.761 81.096 38.801 81.264 ;
     RECT  38.761 81.264 38.796 81.288 ;
     RECT  38.761 81.288 38.801 81.456 ;
     RECT  38.761 81.456 38.796 81.48 ;
     RECT  38.761 81.48 38.801 81.6 ;
     RECT  38.761 81.6 38.796 81.624 ;
     RECT  38.761 81.624 38.801 81.792 ;
     RECT  38.761 81.792 38.796 81.816 ;
     RECT  38.761 81.816 38.801 81.984 ;
     RECT  38.761 81.984 38.796 82.008 ;
     RECT  38.761 82.008 38.801 82.128 ;
     RECT  38.761 82.128 38.796 82.152 ;
     RECT  38.761 82.152 38.801 82.32 ;
     RECT  38.761 82.32 38.796 82.344 ;
     RECT  38.761 82.344 38.801 82.512 ;
     RECT  38.761 82.512 38.796 82.536 ;
     RECT  38.761 82.536 38.801 82.704 ;
     RECT  38.761 82.704 38.796 82.728 ;
     RECT  38.761 82.728 38.801 82.848 ;
     RECT  38.761 82.848 38.796 82.872 ;
     RECT  38.761 82.872 38.801 83.04 ;
     RECT  38.761 83.04 38.796 83.064 ;
     RECT  38.761 83.064 38.801 83.232 ;
     RECT  38.761 83.232 38.796 83.256 ;
     RECT  38.761 83.256 38.801 83.376 ;
     RECT  38.761 83.376 38.796 83.4 ;
     RECT  38.761 83.4 38.801 83.568 ;
     RECT  38.761 83.568 38.796 83.592 ;
     RECT  38.761 83.592 38.801 83.76 ;
     RECT  38.761 83.76 38.796 83.784 ;
     RECT  38.761 83.784 38.801 83.904 ;
     RECT  38.761 83.904 38.796 83.928 ;
     RECT  38.761 83.928 38.801 84.096 ;
     RECT  38.761 84.096 38.796 84.12 ;
     RECT  38.761 84.12 38.801 84.288 ;
     RECT  38.761 84.288 38.796 84.312 ;
     RECT  38.761 84.312 38.801 84.432 ;
     RECT  38.761 84.432 38.796 84.456 ;
     RECT  38.761 84.456 38.801 84.624 ;
     RECT  38.761 84.624 38.796 84.648 ;
     RECT  38.761 84.648 38.801 84.816 ;
     RECT  38.761 84.816 38.796 84.84 ;
     RECT  38.761 84.84 38.801 84.96 ;
     RECT  38.761 84.96 38.796 84.984 ;
     RECT  38.761 84.984 38.801 85.152 ;
     RECT  38.761 85.152 38.796 85.176 ;
     RECT  38.761 85.176 38.801 85.344 ;
     RECT  38.761 85.344 38.796 85.368 ;
     RECT  38.761 85.368 38.801 85.488 ;
     RECT  38.761 85.488 38.796 85.512 ;
     RECT  38.761 85.512 38.801 85.68 ;
     RECT  38.761 85.68 38.796 85.704 ;
     RECT  38.761 85.704 38.801 85.872 ;
     RECT  38.761 85.872 38.796 85.896 ;
     RECT  38.761 85.896 38.801 86.016 ;
     RECT  38.761 86.016 38.796 86.04 ;
     RECT  38.761 86.04 38.801 86.208 ;
     RECT  38.761 86.208 38.796 86.232 ;
     RECT  38.761 86.232 38.801 86.4 ;
     RECT  38.761 86.4 38.796 86.424 ;
     RECT  38.761 86.424 38.801 86.544 ;
     RECT  38.761 86.544 38.796 86.568 ;
     RECT  38.761 86.568 38.801 86.736 ;
     RECT  38.761 86.736 38.796 86.76 ;
     RECT  38.761 86.76 38.801 86.928 ;
     RECT  38.761 86.928 38.796 86.952 ;
     RECT  38.761 86.952 38.801 87.072 ;
     RECT  38.761 87.072 38.796 87.096 ;
     RECT  38.761 87.096 38.801 87.264 ;
     RECT  38.761 87.264 38.796 87.288 ;
     RECT  38.761 87.288 38.801 87.456 ;
     RECT  38.761 87.456 38.796 87.48 ;
     RECT  38.761 87.48 38.801 87.6 ;
     RECT  38.761 87.6 38.796 87.624 ;
     RECT  38.761 87.624 38.801 87.792 ;
     RECT  38.761 87.792 38.796 87.816 ;
     RECT  38.761 87.816 38.801 87.984 ;
     RECT  38.761 87.984 38.796 88.008 ;
     RECT  38.761 88.008 38.801 88.128 ;
     RECT  38.761 88.128 38.796 88.152 ;
     RECT  38.761 88.152 38.801 88.32 ;
     RECT  38.761 88.32 38.796 88.344 ;
     RECT  38.761 88.344 38.801 88.512 ;
     RECT  38.761 88.512 38.796 88.536 ;
     RECT  38.761 88.536 38.801 88.656 ;
     RECT  38.761 88.656 38.796 88.68 ;
     RECT  38.761 88.68 38.801 88.848 ;
     RECT  38.761 88.848 38.796 88.872 ;
     RECT  38.761 88.872 38.801 89.04 ;
     RECT  38.761 89.04 38.796 89.064 ;
     RECT  38.761 89.064 38.801 89.184 ;
     RECT  38.761 89.184 38.796 89.208 ;
     RECT  38.761 89.208 38.801 89.376 ;
     RECT  38.761 89.376 38.796 89.4 ;
     RECT  38.761 89.4 38.801 89.568 ;
     RECT  38.761 89.568 38.796 89.592 ;
     RECT  38.761 89.592 38.801 89.712 ;
     RECT  38.761 89.712 38.796 89.736 ;
     RECT  38.761 89.736 38.801 89.904 ;
     RECT  38.761 89.904 38.796 89.928 ;
     RECT  38.761 89.928 38.801 90.096 ;
     RECT  38.761 90.096 38.796 90.12 ;
     RECT  38.761 90.12 38.801 90.24 ;
     RECT  38.761 90.24 38.796 90.264 ;
     RECT  38.761 90.264 38.801 90.432 ;
     RECT  38.761 90.432 38.796 90.456 ;
     RECT  38.761 90.456 38.801 90.624 ;
     RECT  38.761 90.624 38.796 90.648 ;
     RECT  38.761 90.648 38.801 90.768 ;
     RECT  38.761 90.768 38.796 90.792 ;
     RECT  38.761 90.792 38.801 90.96 ;
     RECT  38.761 90.96 38.796 90.984 ;
     RECT  38.761 90.984 38.801 91.152 ;
     RECT  38.761 91.152 38.796 91.176 ;
     RECT  38.761 91.176 38.801 92.112 ;
     RECT  38.761 92.112 38.796 92.136 ;
     RECT  38.761 92.136 38.801 92.232 ;
     RECT  38.801 1.08 38.844 1.248 ;
     RECT  38.801 1.272 38.844 1.44 ;
     RECT  38.801 1.464 38.844 1.584 ;
     RECT  38.801 1.608 38.844 1.776 ;
     RECT  38.801 1.8 38.844 1.968 ;
     RECT  38.801 1.992 38.844 2.112 ;
     RECT  38.801 2.136 38.844 2.304 ;
     RECT  38.801 2.328 38.844 2.496 ;
     RECT  38.801 2.52 38.844 2.64 ;
     RECT  38.801 2.664 38.844 2.832 ;
     RECT  38.801 2.856 38.844 3.024 ;
     RECT  38.801 3.048 38.844 3.168 ;
     RECT  38.801 3.192 38.844 3.36 ;
     RECT  38.801 3.384 38.844 3.552 ;
     RECT  38.801 3.576 38.844 3.744 ;
     RECT  38.801 3.768 38.844 3.888 ;
     RECT  38.801 3.912 38.844 4.08 ;
     RECT  38.801 4.104 38.844 4.272 ;
     RECT  38.801 4.296 38.844 4.416 ;
     RECT  38.801 4.44 38.844 4.608 ;
     RECT  38.801 4.632 38.844 4.8 ;
     RECT  38.801 4.824 38.844 4.944 ;
     RECT  38.801 4.968 38.844 5.136 ;
     RECT  38.801 5.16 38.844 5.328 ;
     RECT  38.801 5.352 38.844 5.472 ;
     RECT  38.801 5.496 38.844 5.664 ;
     RECT  38.801 5.688 38.844 5.856 ;
     RECT  38.801 5.88 38.844 6 ;
     RECT  38.801 6.024 38.844 6.192 ;
     RECT  38.801 6.216 38.844 6.384 ;
     RECT  38.801 6.408 38.844 6.528 ;
     RECT  38.801 6.552 38.844 6.72 ;
     RECT  38.801 6.744 38.844 6.912 ;
     RECT  38.801 6.936 38.844 7.056 ;
     RECT  38.801 7.08 38.844 7.248 ;
     RECT  38.801 7.272 38.844 7.44 ;
     RECT  38.801 7.464 38.844 7.584 ;
     RECT  38.801 7.608 38.844 7.776 ;
     RECT  38.801 7.8 38.844 7.968 ;
     RECT  38.801 7.992 38.844 8.112 ;
     RECT  38.801 8.136 38.844 8.304 ;
     RECT  38.801 8.328 38.844 8.496 ;
     RECT  38.801 8.52 38.844 8.64 ;
     RECT  38.801 8.664 38.844 8.832 ;
     RECT  38.801 8.856 38.844 9.024 ;
     RECT  38.801 9.048 38.844 9.168 ;
     RECT  38.801 9.192 38.844 9.36 ;
     RECT  38.801 9.384 38.844 9.552 ;
     RECT  38.801 9.576 38.844 9.696 ;
     RECT  38.801 9.72 38.844 9.888 ;
     RECT  38.801 9.912 38.844 10.08 ;
     RECT  38.801 10.104 38.844 10.224 ;
     RECT  38.801 10.248 38.844 10.416 ;
     RECT  38.801 10.44 38.844 10.608 ;
     RECT  38.801 10.632 38.844 10.752 ;
     RECT  38.801 10.776 38.844 10.944 ;
     RECT  38.801 10.968 38.844 11.136 ;
     RECT  38.801 11.16 38.844 11.28 ;
     RECT  38.801 11.304 38.844 11.472 ;
     RECT  38.801 11.496 38.844 11.664 ;
     RECT  38.801 11.688 38.844 11.808 ;
     RECT  38.801 11.832 38.844 12 ;
     RECT  38.801 12.024 38.844 12.192 ;
     RECT  38.801 12.216 38.844 12.336 ;
     RECT  38.801 12.36 38.844 12.528 ;
     RECT  38.801 12.552 38.844 12.72 ;
     RECT  38.801 12.744 38.844 12.864 ;
     RECT  38.801 12.888 38.844 13.056 ;
     RECT  38.801 13.08 38.844 13.248 ;
     RECT  38.801 13.272 38.844 13.392 ;
     RECT  38.801 13.416 38.844 13.584 ;
     RECT  38.801 13.608 38.844 13.776 ;
     RECT  38.801 13.8 38.844 13.92 ;
     RECT  38.801 13.944 38.844 14.112 ;
     RECT  38.801 14.136 38.844 14.304 ;
     RECT  38.801 14.328 38.844 14.448 ;
     RECT  38.801 14.472 38.844 14.64 ;
     RECT  38.801 14.664 38.844 14.832 ;
     RECT  38.801 14.856 38.844 15.024 ;
     RECT  38.801 15.048 38.844 15.168 ;
     RECT  38.801 15.192 38.844 15.36 ;
     RECT  38.801 15.384 38.844 15.552 ;
     RECT  38.801 15.576 38.844 15.696 ;
     RECT  38.801 15.72 38.844 15.888 ;
     RECT  38.801 15.912 38.844 16.08 ;
     RECT  38.801 16.104 38.844 16.224 ;
     RECT  38.801 16.248 38.844 16.416 ;
     RECT  38.801 16.44 38.844 16.608 ;
     RECT  38.801 16.632 38.844 16.752 ;
     RECT  38.801 16.776 38.844 16.944 ;
     RECT  38.801 16.968 38.844 17.136 ;
     RECT  38.801 17.16 38.844 17.28 ;
     RECT  38.801 17.304 38.844 17.472 ;
     RECT  38.801 17.496 38.844 17.664 ;
     RECT  38.801 17.688 38.844 17.808 ;
     RECT  38.801 17.832 38.844 18 ;
     RECT  38.801 18.024 38.844 18.192 ;
     RECT  38.801 18.216 38.844 18.336 ;
     RECT  38.801 18.36 38.844 18.528 ;
     RECT  38.801 18.552 38.844 18.72 ;
     RECT  38.801 18.744 38.844 18.864 ;
     RECT  38.801 18.888 38.844 19.056 ;
     RECT  38.801 19.08 38.844 19.248 ;
     RECT  38.801 19.272 38.844 19.392 ;
     RECT  38.801 19.416 38.844 19.584 ;
     RECT  38.801 19.608 38.844 19.776 ;
     RECT  38.801 19.8 38.844 19.92 ;
     RECT  38.801 19.944 38.844 20.112 ;
     RECT  38.801 20.136 38.844 20.304 ;
     RECT  38.801 20.328 38.844 20.448 ;
     RECT  38.801 20.472 38.844 20.64 ;
     RECT  38.801 20.664 38.844 20.832 ;
     RECT  38.801 20.856 38.844 20.976 ;
     RECT  38.801 21 38.844 21.168 ;
     RECT  38.801 21.192 38.844 21.36 ;
     RECT  38.801 21.384 38.844 21.504 ;
     RECT  38.801 21.528 38.844 21.696 ;
     RECT  38.801 21.72 38.844 21.888 ;
     RECT  38.801 21.912 38.844 22.032 ;
     RECT  38.801 22.056 38.844 22.224 ;
     RECT  38.801 22.248 38.844 22.416 ;
     RECT  38.801 22.44 38.844 22.56 ;
     RECT  38.801 22.584 38.844 22.752 ;
     RECT  38.801 22.776 38.844 22.944 ;
     RECT  38.801 22.968 38.844 23.088 ;
     RECT  38.801 23.112 38.844 23.28 ;
     RECT  38.801 23.304 38.844 23.472 ;
     RECT  38.801 23.496 38.844 23.616 ;
     RECT  38.801 23.64 38.844 23.808 ;
     RECT  38.801 23.832 38.844 24 ;
     RECT  38.801 24.024 38.844 24.144 ;
     RECT  38.801 24.168 38.844 24.336 ;
     RECT  38.801 24.36 38.844 24.528 ;
     RECT  38.801 24.552 38.844 24.672 ;
     RECT  38.801 24.696 38.844 24.864 ;
     RECT  38.801 24.888 38.844 25.056 ;
     RECT  38.801 25.08 38.844 25.2 ;
     RECT  38.801 25.224 38.844 25.392 ;
     RECT  38.801 25.416 38.844 25.584 ;
     RECT  38.801 25.608 38.844 25.728 ;
     RECT  38.801 25.752 38.844 25.92 ;
     RECT  38.801 25.944 38.844 26.112 ;
     RECT  38.801 26.136 38.844 26.304 ;
     RECT  38.801 26.328 38.844 26.448 ;
     RECT  38.801 26.472 38.844 26.64 ;
     RECT  38.801 26.664 38.844 26.832 ;
     RECT  38.801 26.856 38.844 26.976 ;
     RECT  38.801 27 38.844 27.168 ;
     RECT  38.801 27.192 38.844 27.36 ;
     RECT  38.801 27.384 38.844 27.504 ;
     RECT  38.801 27.528 38.844 27.696 ;
     RECT  38.801 27.72 38.844 27.888 ;
     RECT  38.801 27.912 38.844 28.032 ;
     RECT  38.801 28.056 38.844 28.224 ;
     RECT  38.801 28.248 38.844 28.416 ;
     RECT  38.801 28.44 38.844 28.56 ;
     RECT  38.801 28.584 38.844 28.752 ;
     RECT  38.801 28.776 38.844 28.944 ;
     RECT  38.801 28.968 38.844 29.088 ;
     RECT  38.801 29.112 38.844 29.28 ;
     RECT  38.801 29.304 38.844 29.472 ;
     RECT  38.801 29.496 38.844 29.616 ;
     RECT  38.801 29.64 38.844 29.808 ;
     RECT  38.801 29.832 38.844 30 ;
     RECT  38.801 30.024 38.844 30.144 ;
     RECT  38.801 30.168 38.844 30.336 ;
     RECT  38.801 30.36 38.844 30.528 ;
     RECT  38.801 30.552 38.844 30.672 ;
     RECT  38.801 30.696 38.844 30.864 ;
     RECT  38.801 30.888 38.844 31.056 ;
     RECT  38.801 31.08 38.844 31.2 ;
     RECT  38.801 31.224 38.844 31.392 ;
     RECT  38.801 31.416 38.844 31.584 ;
     RECT  38.801 31.608 38.844 31.728 ;
     RECT  38.801 31.752 38.844 31.92 ;
     RECT  38.801 31.944 38.844 32.112 ;
     RECT  38.801 32.136 38.844 32.256 ;
     RECT  38.801 32.28 38.844 32.448 ;
     RECT  38.801 32.472 38.844 32.64 ;
     RECT  38.801 32.664 38.844 32.784 ;
     RECT  38.801 32.808 38.844 32.976 ;
     RECT  38.801 33 38.844 33.168 ;
     RECT  38.801 33.192 38.844 33.312 ;
     RECT  38.801 33.336 38.844 33.504 ;
     RECT  38.801 33.528 38.844 33.696 ;
     RECT  38.801 33.72 38.844 33.84 ;
     RECT  38.801 33.864 38.844 34.032 ;
     RECT  38.801 34.056 38.844 34.224 ;
     RECT  38.801 34.248 38.844 34.368 ;
     RECT  38.801 34.392 38.844 34.56 ;
     RECT  38.801 34.584 38.844 34.752 ;
     RECT  38.801 34.776 38.844 34.896 ;
     RECT  38.801 34.92 38.844 35.088 ;
     RECT  38.801 35.112 38.844 35.28 ;
     RECT  38.801 35.304 38.844 35.424 ;
     RECT  38.801 35.448 38.844 35.616 ;
     RECT  38.801 35.64 38.844 35.808 ;
     RECT  38.801 35.832 38.844 35.952 ;
     RECT  38.801 35.976 38.844 36.144 ;
     RECT  38.801 36.168 38.844 36.336 ;
     RECT  38.801 36.36 38.844 36.48 ;
     RECT  38.801 36.504 38.844 36.672 ;
     RECT  38.801 36.696 38.844 36.864 ;
     RECT  38.801 36.888 38.844 37.008 ;
     RECT  38.801 37.032 38.844 37.2 ;
     RECT  38.801 37.224 38.844 37.392 ;
     RECT  38.801 37.416 38.844 37.584 ;
     RECT  38.801 37.608 38.844 37.728 ;
     RECT  38.801 37.752 38.844 37.92 ;
     RECT  38.801 37.944 38.844 38.112 ;
     RECT  38.801 38.136 38.844 38.256 ;
     RECT  38.801 38.28 38.844 38.448 ;
     RECT  38.801 38.472 38.844 38.64 ;
     RECT  38.801 38.664 38.844 38.784 ;
     RECT  38.801 38.808 38.844 38.976 ;
     RECT  38.801 39 38.844 39.168 ;
     RECT  38.801 39.192 38.844 39.312 ;
     RECT  38.801 39.336 38.844 39.504 ;
     RECT  38.801 39.528 38.844 39.696 ;
     RECT  38.801 39.72 38.844 39.84 ;
     RECT  38.801 39.864 38.844 40.032 ;
     RECT  38.801 40.056 38.844 40.224 ;
     RECT  38.801 40.248 38.844 40.368 ;
     RECT  38.801 40.392 38.844 40.56 ;
     RECT  38.801 40.584 38.844 40.752 ;
     RECT  38.801 40.776 38.844 40.896 ;
     RECT  38.801 40.92 38.844 41.088 ;
     RECT  38.801 41.112 38.844 41.28 ;
     RECT  38.801 41.304 38.844 41.424 ;
     RECT  38.801 41.448 38.844 41.616 ;
     RECT  38.801 41.64 38.844 41.808 ;
     RECT  38.801 41.832 38.844 41.952 ;
     RECT  38.801 41.976 38.844 42.144 ;
     RECT  38.801 42.168 38.844 42.336 ;
     RECT  38.801 42.36 38.844 42.48 ;
     RECT  38.801 42.504 38.844 42.672 ;
     RECT  38.801 42.696 38.844 42.864 ;
     RECT  38.801 42.888 38.844 43.008 ;
     RECT  38.801 43.032 38.844 43.2 ;
     RECT  38.801 43.224 38.844 43.392 ;
     RECT  38.801 43.416 38.844 43.536 ;
     RECT  38.801 43.56 38.844 43.728 ;
     RECT  38.801 43.752 38.844 43.92 ;
     RECT  38.801 43.944 38.844 44.064 ;
     RECT  38.801 44.088 38.844 44.256 ;
     RECT  38.801 44.28 38.844 44.448 ;
     RECT  38.801 44.472 38.844 44.592 ;
     RECT  38.801 44.616 38.844 44.784 ;
     RECT  38.801 44.808 38.844 44.976 ;
     RECT  38.801 45 38.844 45.12 ;
     RECT  38.801 45.144 38.844 45.312 ;
     RECT  38.801 45.336 38.844 45.504 ;
     RECT  38.801 45.528 38.844 45.648 ;
     RECT  38.801 45.672 38.844 45.84 ;
     RECT  38.801 45.864 38.844 46.032 ;
     RECT  38.801 46.056 38.844 46.176 ;
     RECT  38.801 46.2 38.844 46.368 ;
     RECT  38.801 46.392 38.844 46.56 ;
     RECT  38.801 46.584 38.844 46.704 ;
     RECT  38.801 46.728 38.844 46.896 ;
     RECT  38.801 46.92 38.844 47.088 ;
     RECT  38.801 47.112 38.844 47.232 ;
     RECT  38.801 47.256 38.844 47.424 ;
     RECT  38.801 47.448 38.844 47.616 ;
     RECT  38.801 47.64 38.844 47.76 ;
     RECT  38.801 47.784 38.844 47.952 ;
     RECT  38.801 47.976 38.844 48.144 ;
     RECT  38.801 48.168 38.844 48.288 ;
     RECT  38.801 48.312 38.844 48.48 ;
     RECT  38.801 48.504 38.844 48.672 ;
     RECT  38.801 48.696 38.844 48.864 ;
     RECT  38.801 48.888 38.844 49.008 ;
     RECT  38.801 49.032 38.844 49.2 ;
     RECT  38.801 49.224 38.844 49.392 ;
     RECT  38.801 49.416 38.844 49.536 ;
     RECT  38.801 49.56 38.844 49.728 ;
     RECT  38.801 49.752 38.844 49.92 ;
     RECT  38.801 49.944 38.844 50.064 ;
     RECT  38.801 50.088 38.844 50.256 ;
     RECT  38.801 50.28 38.844 50.448 ;
     RECT  38.801 50.472 38.844 50.592 ;
     RECT  38.801 50.616 38.844 50.784 ;
     RECT  38.801 50.808 38.844 50.976 ;
     RECT  38.801 51 38.844 51.12 ;
     RECT  38.801 51.144 38.844 51.312 ;
     RECT  38.801 51.336 38.844 51.504 ;
     RECT  38.801 51.528 38.844 51.648 ;
     RECT  38.801 51.672 38.844 51.84 ;
     RECT  38.801 51.864 38.844 52.032 ;
     RECT  38.801 52.056 38.844 52.176 ;
     RECT  38.801 52.2 38.844 52.368 ;
     RECT  38.801 52.392 38.844 52.56 ;
     RECT  38.801 52.584 38.844 52.704 ;
     RECT  38.801 52.728 38.844 52.896 ;
     RECT  38.801 52.92 38.844 53.088 ;
     RECT  38.801 53.112 38.844 53.232 ;
     RECT  38.801 53.256 38.844 53.424 ;
     RECT  38.801 53.448 38.844 53.616 ;
     RECT  38.801 53.64 38.844 53.76 ;
     RECT  38.801 53.784 38.844 53.952 ;
     RECT  38.801 53.976 38.844 54.144 ;
     RECT  38.801 54.168 38.844 54.288 ;
     RECT  38.801 54.312 38.844 54.48 ;
     RECT  38.801 54.504 38.844 54.672 ;
     RECT  38.801 54.696 38.844 54.816 ;
     RECT  38.801 54.84 38.844 55.008 ;
     RECT  38.801 55.032 38.844 55.2 ;
     RECT  38.801 55.224 38.844 55.344 ;
     RECT  38.801 55.368 38.844 55.536 ;
     RECT  38.801 55.56 38.844 55.728 ;
     RECT  38.801 55.752 38.844 55.872 ;
     RECT  38.801 55.896 38.844 56.064 ;
     RECT  38.801 56.088 38.844 56.256 ;
     RECT  38.801 56.28 38.844 56.4 ;
     RECT  38.801 56.424 38.844 56.592 ;
     RECT  38.801 56.616 38.844 56.784 ;
     RECT  38.801 56.808 38.844 56.928 ;
     RECT  38.801 56.952 38.844 57.12 ;
     RECT  38.801 57.144 38.844 57.312 ;
     RECT  38.801 57.336 38.844 57.456 ;
     RECT  38.801 57.48 38.844 57.648 ;
     RECT  38.801 57.672 38.844 57.84 ;
     RECT  38.801 57.864 38.844 57.984 ;
     RECT  38.801 58.008 38.844 58.176 ;
     RECT  38.801 58.2 38.844 58.368 ;
     RECT  38.801 58.392 38.844 58.512 ;
     RECT  38.801 58.536 38.844 58.704 ;
     RECT  38.801 58.728 38.844 58.896 ;
     RECT  38.801 58.92 38.844 59.04 ;
     RECT  38.801 59.064 38.844 59.232 ;
     RECT  38.801 59.256 38.844 59.424 ;
     RECT  38.801 59.448 38.844 59.568 ;
     RECT  38.801 59.592 38.844 59.76 ;
     RECT  38.801 59.784 38.844 59.952 ;
     RECT  38.801 59.976 38.844 60.144 ;
     RECT  38.801 60.168 38.844 60.288 ;
     RECT  38.801 60.312 38.844 60.48 ;
     RECT  38.801 60.504 38.844 60.672 ;
     RECT  38.801 60.696 38.844 60.816 ;
     RECT  38.801 60.84 38.844 61.008 ;
     RECT  38.801 61.032 38.844 61.2 ;
     RECT  38.801 61.224 38.844 61.344 ;
     RECT  38.801 61.368 38.844 61.536 ;
     RECT  38.801 61.56 38.844 61.728 ;
     RECT  38.801 61.752 38.844 61.872 ;
     RECT  38.801 61.896 38.844 62.064 ;
     RECT  38.801 62.088 38.844 62.256 ;
     RECT  38.801 62.28 38.844 62.4 ;
     RECT  38.801 62.424 38.844 62.592 ;
     RECT  38.801 62.616 38.844 62.784 ;
     RECT  38.801 62.808 38.844 62.928 ;
     RECT  38.801 62.952 38.844 63.12 ;
     RECT  38.801 63.144 38.844 63.312 ;
     RECT  38.801 63.336 38.844 63.456 ;
     RECT  38.801 63.48 38.844 63.648 ;
     RECT  38.801 63.672 38.844 63.84 ;
     RECT  38.801 63.864 38.844 63.984 ;
     RECT  38.801 64.008 38.844 64.176 ;
     RECT  38.801 64.2 38.844 64.368 ;
     RECT  38.801 64.392 38.844 64.512 ;
     RECT  38.801 64.536 38.844 64.704 ;
     RECT  38.801 64.728 38.844 64.896 ;
     RECT  38.801 64.92 38.844 65.04 ;
     RECT  38.801 65.064 38.844 65.232 ;
     RECT  38.801 65.256 38.844 65.424 ;
     RECT  38.801 65.448 38.844 65.568 ;
     RECT  38.801 65.592 38.844 65.76 ;
     RECT  38.801 65.784 38.844 65.952 ;
     RECT  38.801 65.976 38.844 66.096 ;
     RECT  38.801 66.12 38.844 66.288 ;
     RECT  38.801 66.312 38.844 66.48 ;
     RECT  38.801 66.504 38.844 66.624 ;
     RECT  38.801 66.648 38.844 66.816 ;
     RECT  38.801 66.84 38.844 67.008 ;
     RECT  38.801 67.032 38.844 67.152 ;
     RECT  38.801 67.176 38.844 67.344 ;
     RECT  38.801 67.368 38.844 67.536 ;
     RECT  38.801 67.56 38.844 67.68 ;
     RECT  38.801 67.704 38.844 67.872 ;
     RECT  38.801 67.896 38.844 68.064 ;
     RECT  38.801 68.088 38.844 68.208 ;
     RECT  38.801 68.232 38.844 68.4 ;
     RECT  38.801 68.424 38.844 68.592 ;
     RECT  38.801 68.616 38.844 68.736 ;
     RECT  38.801 68.76 38.844 68.928 ;
     RECT  38.801 68.952 38.844 69.12 ;
     RECT  38.801 69.144 38.844 69.264 ;
     RECT  38.801 69.288 38.844 69.456 ;
     RECT  38.801 69.48 38.844 69.648 ;
     RECT  38.801 69.672 38.844 69.792 ;
     RECT  38.801 69.816 38.844 69.984 ;
     RECT  38.801 70.008 38.844 70.176 ;
     RECT  38.801 70.2 38.844 70.32 ;
     RECT  38.801 70.344 38.844 70.512 ;
     RECT  38.801 70.536 38.844 70.704 ;
     RECT  38.801 70.728 38.844 70.848 ;
     RECT  38.801 70.872 38.844 71.04 ;
     RECT  38.801 71.064 38.844 71.232 ;
     RECT  38.801 71.256 38.844 71.424 ;
     RECT  38.801 71.448 38.844 71.568 ;
     RECT  38.801 71.592 38.844 71.76 ;
     RECT  38.801 71.784 38.844 71.952 ;
     RECT  38.801 71.976 38.844 72.096 ;
     RECT  38.801 72.12 38.844 72.288 ;
     RECT  38.801 72.312 38.844 72.48 ;
     RECT  38.801 72.504 38.844 72.624 ;
     RECT  38.801 72.648 38.844 72.816 ;
     RECT  38.801 72.84 38.844 73.008 ;
     RECT  38.801 73.032 38.844 73.152 ;
     RECT  38.801 73.176 38.844 73.344 ;
     RECT  38.801 73.368 38.844 73.536 ;
     RECT  38.801 73.56 38.844 73.68 ;
     RECT  38.801 73.704 38.844 73.872 ;
     RECT  38.801 73.896 38.844 74.064 ;
     RECT  38.801 74.088 38.844 74.208 ;
     RECT  38.801 74.232 38.844 74.4 ;
     RECT  38.801 74.424 38.844 74.592 ;
     RECT  38.801 74.616 38.844 74.736 ;
     RECT  38.801 74.76 38.844 74.928 ;
     RECT  38.801 74.952 38.844 75.12 ;
     RECT  38.801 75.144 38.844 75.264 ;
     RECT  38.801 75.288 38.844 75.456 ;
     RECT  38.801 75.48 38.844 75.648 ;
     RECT  38.801 75.672 38.844 75.792 ;
     RECT  38.801 75.816 38.844 75.984 ;
     RECT  38.801 76.008 38.844 76.176 ;
     RECT  38.801 76.2 38.844 76.32 ;
     RECT  38.801 76.344 38.844 76.512 ;
     RECT  38.801 76.536 38.844 76.704 ;
     RECT  38.801 76.728 38.844 76.848 ;
     RECT  38.801 76.872 38.844 77.04 ;
     RECT  38.801 77.064 38.844 77.232 ;
     RECT  38.801 77.256 38.844 77.376 ;
     RECT  38.801 77.4 38.844 77.568 ;
     RECT  38.801 77.592 38.844 77.76 ;
     RECT  38.801 77.784 38.844 77.904 ;
     RECT  38.801 77.928 38.844 78.096 ;
     RECT  38.801 78.12 38.844 78.288 ;
     RECT  38.801 78.312 38.844 78.432 ;
     RECT  38.801 78.456 38.844 78.624 ;
     RECT  38.801 78.648 38.844 78.816 ;
     RECT  38.801 78.84 38.844 78.96 ;
     RECT  38.801 78.984 38.844 79.152 ;
     RECT  38.801 79.176 38.844 79.344 ;
     RECT  38.801 79.368 38.844 79.488 ;
     RECT  38.801 79.512 38.844 79.68 ;
     RECT  38.801 79.704 38.844 79.872 ;
     RECT  38.801 79.896 38.844 80.016 ;
     RECT  38.801 80.04 38.844 80.208 ;
     RECT  38.801 80.232 38.844 80.4 ;
     RECT  38.801 80.424 38.844 80.544 ;
     RECT  38.801 80.568 38.844 80.736 ;
     RECT  38.801 80.76 38.844 80.928 ;
     RECT  38.801 80.952 38.844 81.072 ;
     RECT  38.801 81.096 38.844 81.264 ;
     RECT  38.801 81.288 38.844 81.456 ;
     RECT  38.801 81.48 38.844 81.6 ;
     RECT  38.801 81.624 38.844 81.792 ;
     RECT  38.801 81.816 38.844 81.984 ;
     RECT  38.801 82.008 38.844 82.128 ;
     RECT  38.801 82.152 38.844 82.32 ;
     RECT  38.801 82.344 38.844 82.512 ;
     RECT  38.801 82.536 38.844 82.704 ;
     RECT  38.801 82.728 38.844 82.848 ;
     RECT  38.801 82.872 38.844 83.04 ;
     RECT  38.801 83.064 38.844 83.232 ;
     RECT  38.801 83.256 38.844 83.376 ;
     RECT  38.801 83.4 38.844 83.568 ;
     RECT  38.801 83.592 38.844 83.76 ;
     RECT  38.801 83.784 38.844 83.904 ;
     RECT  38.801 83.928 38.844 84.096 ;
     RECT  38.801 84.12 38.844 84.288 ;
     RECT  38.801 84.312 38.844 84.432 ;
     RECT  38.801 84.456 38.844 84.624 ;
     RECT  38.801 84.648 38.844 84.816 ;
     RECT  38.801 84.84 38.844 84.96 ;
     RECT  38.801 84.984 38.844 85.152 ;
     RECT  38.801 85.176 38.844 85.344 ;
     RECT  38.801 85.368 38.844 85.488 ;
     RECT  38.801 85.512 38.844 85.68 ;
     RECT  38.801 85.704 38.844 85.872 ;
     RECT  38.801 85.896 38.844 86.016 ;
     RECT  38.801 86.04 38.844 86.208 ;
     RECT  38.801 86.232 38.844 86.4 ;
     RECT  38.801 86.424 38.844 86.544 ;
     RECT  38.801 86.568 38.844 86.736 ;
     RECT  38.801 86.76 38.844 86.928 ;
     RECT  38.801 86.952 38.844 87.072 ;
     RECT  38.801 87.096 38.844 87.264 ;
     RECT  38.801 87.288 38.844 87.456 ;
     RECT  38.801 87.48 38.844 87.6 ;
     RECT  38.801 87.624 38.844 87.792 ;
     RECT  38.801 87.816 38.844 87.984 ;
     RECT  38.801 88.008 38.844 88.128 ;
     RECT  38.801 88.152 38.844 88.32 ;
     RECT  38.801 88.344 38.844 88.512 ;
     RECT  38.801 88.536 38.844 88.656 ;
     RECT  38.801 88.68 38.844 88.848 ;
     RECT  38.801 88.872 38.844 89.04 ;
     RECT  38.801 89.064 38.844 89.184 ;
     RECT  38.801 89.208 38.844 89.376 ;
     RECT  38.801 89.4 38.844 89.568 ;
     RECT  38.801 89.592 38.844 89.712 ;
     RECT  38.801 89.736 38.844 89.904 ;
     RECT  38.801 89.928 38.844 90.096 ;
     RECT  38.801 90.12 38.844 90.24 ;
     RECT  38.801 90.264 38.844 90.432 ;
     RECT  38.801 90.456 38.844 90.624 ;
     RECT  38.801 90.648 38.844 90.768 ;
     RECT  38.801 90.792 38.844 90.96 ;
     RECT  38.801 90.984 38.844 91.152 ;
     RECT  38.801 91.176 38.844 92.112 ;
     RECT  38.844 26.544 38.873 26.568 ;
    LAYER M5 ;
     RECT  2.4 2.137 2.52 2.151 ;
     RECT  5.1 2.137 5.22 2.151 ;
     RECT  7.8 2.137 7.92 2.151 ;
     RECT  10.5 2.137 10.62 2.151 ;
     RECT  13.2 2.137 13.32 2.151 ;
     RECT  15.9 2.137 16.02 2.151 ;
     RECT  18.6 2.137 18.72 2.151 ;
     RECT  21.3 2.137 21.42 2.151 ;
     RECT  24 2.137 24.12 2.151 ;
     RECT  26.7 2.137 26.82 2.151 ;
     RECT  29.4 2.137 29.52 2.151 ;
     RECT  32.1 2.137 32.22 2.151 ;
     RECT  34.8 2.137 34.92 2.151 ;
     RECT  14.784 2.197 14.808 2.245 ;
     RECT  21.3 2.151 21.612 2.245 ;
     RECT  22.608 2.197 22.632 2.245 ;
     RECT  24 2.151 24.312 2.245 ;
     RECT  26.7 2.151 27.012 2.245 ;
     RECT  32.1 2.151 32.412 2.245 ;
     RECT  18.6 2.151 18.912 2.725 ;
     RECT  32.1 2.245 32.904 2.821 ;
     RECT  10.5 2.151 10.812 2.869 ;
     RECT  14.688 2.245 14.808 2.915 ;
     RECT  31.968 2.821 32.904 3.299 ;
     RECT  7.8 2.151 8.112 3.301 ;
     RECT  29.4 2.151 29.712 3.301 ;
     RECT  30.768 2.629 30.792 3.301 ;
     RECT  38.688 3.253 38.712 3.395 ;
     RECT  15.9 2.151 16.212 3.397 ;
     RECT  14.784 2.915 14.808 3.443 ;
     RECT  25.872 2.245 27.012 3.443 ;
     RECT  18.6 2.725 19.032 3.539 ;
     RECT  7.8 3.301 8.616 3.541 ;
     RECT  6.624 2.245 6.648 3.587 ;
     RECT  2.4 2.151 2.712 3.685 ;
     RECT  15.792 3.397 16.212 3.829 ;
     RECT  7.8 3.541 9.048 3.877 ;
     RECT  13.2 2.151 13.512 3.877 ;
     RECT  21.3 2.245 24.312 3.973 ;
     RECT  31.968 3.299 32.412 4.019 ;
     RECT  21.3 3.973 24.408 4.211 ;
     RECT  7.8 3.877 9.384 4.355 ;
     RECT  14.88 3.829 16.212 4.453 ;
     RECT  14.784 4.453 16.212 4.501 ;
     RECT  21.3 4.211 24.312 4.501 ;
     RECT  34.8 2.151 35.112 4.501 ;
     RECT  2.4 3.685 3.432 4.595 ;
     RECT  29.4 3.301 30.792 4.643 ;
     RECT  33.648 3.925 33.672 4.645 ;
     RECT  13.056 3.877 13.512 4.691 ;
     RECT  34.8 4.501 35.928 4.691 ;
     RECT  33.648 4.645 33.768 4.787 ;
     RECT  20.448 4.501 24.312 4.931 ;
     RECT  33.648 4.787 33.672 5.123 ;
     RECT  14.784 4.501 16.344 5.171 ;
     RECT  18.6 3.539 18.912 5.173 ;
     RECT  20.448 4.931 22.296 5.173 ;
     RECT  15.264 5.171 16.344 5.221 ;
     RECT  18.6 5.173 22.296 5.315 ;
     RECT  7.8 4.355 8.904 5.365 ;
     RECT  5.1 2.151 5.412 5.557 ;
     RECT  15.264 5.221 16.44 5.603 ;
     RECT  7.8 5.365 9 5.747 ;
     RECT  15.264 5.603 16.212 5.747 ;
     RECT  18.6 5.315 18.912 5.989 ;
     RECT  10.368 2.869 10.812 6.229 ;
     RECT  26.7 3.443 27.012 6.229 ;
     RECT  20.448 5.315 22.296 6.373 ;
     RECT  23.28 4.931 24.312 6.373 ;
     RECT  15.36 5.747 16.212 6.757 ;
     RECT  3.696 5.605 3.72 6.899 ;
     RECT  5.1 5.557 6.36 6.997 ;
     RECT  7.8 5.747 8.112 6.997 ;
     RECT  5.1 6.997 8.112 7.141 ;
     RECT  10.368 6.229 11.448 7.189 ;
     RECT  10.368 7.189 11.928 7.235 ;
     RECT  9.12 7.093 9.144 7.283 ;
     RECT  18.24 5.989 18.912 7.331 ;
     RECT  15.36 6.757 16.344 7.477 ;
     RECT  29.4 4.643 30.504 7.525 ;
     RECT  10.368 7.235 10.92 7.619 ;
     RECT  26.064 6.229 27.012 7.621 ;
     RECT  13.2 4.691 13.512 7.909 ;
     RECT  34.8 4.691 35.112 7.957 ;
     RECT  29.088 7.525 30.504 8.099 ;
     RECT  15.36 7.477 17.016 8.149 ;
     RECT  33.984 7.957 35.112 8.339 ;
     RECT  25.632 7.621 27.012 8.437 ;
     RECT  27.984 7.861 28.008 8.437 ;
     RECT  4.992 7.141 8.112 8.531 ;
     RECT  29.136 8.099 30.504 8.531 ;
     RECT  25.632 8.437 28.008 8.579 ;
     RECT  10.5 7.619 10.92 8.629 ;
     RECT  11.904 7.235 11.928 8.629 ;
     RECT  10.5 8.629 11.928 8.677 ;
     RECT  12.912 7.909 13.512 8.677 ;
     RECT  18.6 7.331 18.912 8.677 ;
     RECT  7.152 8.531 8.112 8.869 ;
     RECT  25.632 8.579 27.384 8.963 ;
     RECT  14.832 8.149 17.016 9.013 ;
     RECT  32.1 4.019 32.412 9.109 ;
     RECT  14.832 9.013 17.112 9.155 ;
     RECT  7.152 8.869 8.232 9.349 ;
     RECT  20.448 6.373 24.312 9.445 ;
     RECT  4.992 8.531 6.024 9.589 ;
     RECT  7.152 9.349 8.376 9.589 ;
     RECT  4.992 9.589 8.376 9.637 ;
     RECT  31.92 9.109 32.412 9.683 ;
     RECT  4.992 9.637 9.096 9.829 ;
     RECT  2.4 4.595 2.712 9.925 ;
     RECT  14.832 9.155 16.536 10.019 ;
     RECT  20.448 9.445 24.456 10.069 ;
     RECT  10.5 8.677 13.512 10.165 ;
     RECT  14.832 10.019 16.212 10.165 ;
     RECT  18.6 8.677 19.416 10.259 ;
     RECT  10.5 10.165 16.212 10.307 ;
     RECT  4.992 9.829 9.144 10.405 ;
     RECT  29.232 8.531 30.504 10.405 ;
     RECT  20.448 10.069 24.504 10.595 ;
     RECT  29.088 10.405 30.504 10.595 ;
     RECT  4.992 10.405 9.336 10.883 ;
     RECT  24 10.595 24.504 10.883 ;
     RECT  12.912 10.307 16.212 11.027 ;
     RECT  13.2 11.027 16.212 11.123 ;
     RECT  5.1 10.883 9.336 11.315 ;
     RECT  26.592 8.963 27.384 11.317 ;
     RECT  26.208 11.317 27.384 11.459 ;
     RECT  14.784 11.123 16.212 11.461 ;
     RECT  10.5 10.307 11.352 11.509 ;
     RECT  20.448 10.595 22.872 11.699 ;
     RECT  14.784 11.461 16.44 11.747 ;
     RECT  29.088 10.595 29.712 11.941 ;
     RECT  32.1 9.683 32.412 11.941 ;
     RECT  34.8 8.339 35.112 11.941 ;
     RECT  5.1 11.315 8.28 11.987 ;
     RECT  14.784 11.747 16.212 12.035 ;
     RECT  7.44 11.987 8.28 12.325 ;
     RECT  9.408 11.509 11.352 12.325 ;
     RECT  31.776 11.941 32.412 12.467 ;
     RECT  7.44 12.325 11.352 12.563 ;
     RECT  17.52 11.605 17.544 12.563 ;
     RECT  34.176 11.941 35.112 12.755 ;
     RECT  20.448 11.699 22.824 12.853 ;
     RECT  24 10.883 24.312 12.853 ;
     RECT  15.168 12.035 16.212 13.045 ;
     RECT  29.088 11.941 29.832 13.093 ;
     RECT  20.352 12.853 22.824 13.139 ;
     RECT  5.1 11.987 6.024 13.333 ;
     RECT  29.088 13.093 30.744 13.427 ;
     RECT  7.44 12.563 9.48 13.571 ;
     RECT  29.088 13.427 29.88 13.861 ;
     RECT  15.024 13.045 16.212 13.909 ;
     RECT  7.44 13.571 8.28 13.955 ;
     RECT  7.44 13.955 8.232 14.147 ;
     RECT  9.456 13.571 9.48 14.149 ;
     RECT  10.5 12.563 11.352 14.149 ;
     RECT  15.024 13.909 16.344 14.339 ;
     RECT  17.376 13.045 17.4 14.339 ;
     RECT  2.4 9.925 3.432 14.341 ;
     RECT  4.8 13.333 6.024 14.341 ;
     RECT  2.4 14.341 6.024 14.389 ;
     RECT  2.4 14.389 6.12 14.629 ;
     RECT  7.44 14.147 8.112 14.629 ;
     RECT  28.992 13.861 29.88 14.723 ;
     RECT  2.4 14.629 8.112 14.867 ;
     RECT  26.208 11.459 27.012 14.915 ;
     RECT  28.992 14.723 29.832 14.915 ;
     RECT  13.2 11.123 13.512 14.917 ;
     RECT  21.3 13.139 22.824 15.157 ;
     RECT  4.128 14.867 8.112 15.395 ;
     RECT  15.792 14.339 16.344 15.493 ;
     RECT  13.2 14.917 14.376 15.733 ;
     RECT  32.1 12.467 32.412 15.781 ;
     RECT  13.2 15.733 14.472 15.829 ;
     RECT  15.792 15.493 16.392 15.829 ;
     RECT  21.12 15.157 22.824 15.829 ;
     RECT  24 12.853 24.504 15.829 ;
     RECT  29.04 14.915 29.832 15.829 ;
     RECT  9.456 14.149 11.352 15.875 ;
     RECT  21.12 15.829 24.504 15.877 ;
     RECT  18.6 10.259 18.912 15.973 ;
     RECT  21.072 15.877 24.504 16.019 ;
     RECT  13.2 15.829 16.392 16.165 ;
     RECT  21.3 16.019 24.504 16.259 ;
     RECT  29.04 15.829 30.216 16.261 ;
     RECT  4.224 15.395 8.112 16.357 ;
     RECT  13.2 16.165 16.44 16.739 ;
     RECT  13.2 16.739 16.392 16.789 ;
     RECT  4.224 16.357 8.376 16.979 ;
     RECT  13.104 16.789 16.392 17.123 ;
     RECT  32.1 15.781 33.096 17.123 ;
     RECT  13.2 17.123 16.344 17.171 ;
     RECT  18.24 15.973 18.912 17.171 ;
     RECT  28.944 16.261 30.216 17.411 ;
     RECT  26.448 14.915 27.012 17.461 ;
     RECT  4.224 16.979 8.112 17.651 ;
     RECT  29.088 17.411 30.216 17.651 ;
     RECT  9.456 15.875 9.48 17.699 ;
     RECT  14.832 17.171 16.344 18.131 ;
     RECT  14.928 18.131 16.344 18.179 ;
     RECT  15.648 18.179 16.344 18.421 ;
     RECT  21.3 16.259 24.312 18.421 ;
     RECT  4.992 17.651 8.112 18.709 ;
     RECT  21.168 18.421 24.312 19.045 ;
     RECT  26.448 17.461 27.336 19.045 ;
     RECT  29.088 17.651 29.88 19.045 ;
     RECT  20.496 19.045 24.312 19.283 ;
     RECT  13.2 17.171 13.512 19.333 ;
     RECT  26.448 19.045 29.88 19.427 ;
     RECT  34.8 12.755 35.112 19.429 ;
     RECT  28.224 19.427 29.88 19.523 ;
     RECT  34.8 19.429 35.928 19.571 ;
     RECT  2.4 14.867 2.712 19.717 ;
     RECT  4.224 18.709 8.112 19.717 ;
     RECT  32.1 17.123 32.412 19.717 ;
     RECT  2.4 19.717 8.112 19.763 ;
     RECT  28.224 19.523 29.832 19.955 ;
     RECT  4.992 19.763 8.112 20.051 ;
     RECT  18.6 17.171 18.912 20.149 ;
     RECT  23.328 19.283 24.312 20.581 ;
     RECT  10.5 15.875 11.352 20.723 ;
     RECT  15.648 18.421 17.16 20.723 ;
     RECT  34.8 19.571 35.112 20.725 ;
     RECT  34.8 20.725 35.928 20.915 ;
     RECT  28.368 19.955 29.832 20.965 ;
     RECT  26.448 19.427 27.012 21.011 ;
     RECT  10.5 20.723 10.968 21.061 ;
     RECT  5.1 20.051 8.112 21.107 ;
     RECT  31.536 19.717 32.412 21.155 ;
     RECT  15.648 20.723 16.968 21.203 ;
     RECT  28.272 20.965 29.832 21.397 ;
     RECT  15.9 21.203 16.968 21.443 ;
     RECT  26.592 21.011 27.012 21.493 ;
     RECT  28.272 21.397 30.12 21.493 ;
     RECT  18.6 20.149 19.416 21.637 ;
     RECT  10.176 21.061 10.968 21.683 ;
     RECT  5.1 21.107 6.504 21.685 ;
     RECT  10.176 21.683 10.812 21.685 ;
     RECT  4.896 21.685 6.504 21.779 ;
     RECT  38.16 21.589 38.184 21.779 ;
     RECT  15.9 21.443 16.632 21.827 ;
     RECT  26.592 21.493 30.12 21.923 ;
     RECT  26.592 21.923 29.712 22.021 ;
     RECT  7.68 21.107 8.112 22.165 ;
     RECT  18.192 21.637 19.416 22.165 ;
     RECT  20.496 19.283 22.296 22.165 ;
     RECT  34.8 20.915 35.112 22.213 ;
     RECT  34.08 22.213 35.112 22.309 ;
     RECT  34.08 22.309 35.928 22.355 ;
     RECT  4.896 21.779 6.12 22.405 ;
     RECT  2.4 19.763 3.288 22.451 ;
     RECT  34.8 22.355 35.928 22.499 ;
     RECT  18.192 22.165 22.296 22.693 ;
     RECT  23.28 20.581 24.312 22.693 ;
     RECT  26.4 22.021 29.712 22.787 ;
     RECT  9.216 21.685 10.812 22.931 ;
     RECT  15.9 21.827 16.536 23.125 ;
     RECT  18.192 22.693 24.312 23.125 ;
     RECT  10.176 22.931 10.812 23.315 ;
     RECT  4.272 22.405 6.12 23.317 ;
     RECT  7.392 22.165 8.112 23.317 ;
     RECT  32.1 21.155 32.412 23.317 ;
     RECT  13.2 19.333 14.472 23.413 ;
     RECT  15.9 23.125 24.312 23.555 ;
     RECT  26.4 22.787 28.296 23.555 ;
     RECT  4.272 23.317 8.112 23.605 ;
     RECT  12.24 23.413 14.472 23.987 ;
     RECT  4.272 23.605 8.952 24.131 ;
     RECT  4.56 24.131 8.952 24.421 ;
     RECT  26.4 23.555 28.248 24.469 ;
     RECT  15.9 23.555 22.584 24.515 ;
     RECT  26.208 24.469 28.248 24.517 ;
     RECT  31.92 23.317 32.412 24.563 ;
     RECT  4.56 24.421 9.144 24.707 ;
     RECT  10.272 23.315 10.812 24.755 ;
     RECT  4.56 24.707 8.952 25.139 ;
     RECT  15.9 24.515 22.296 25.139 ;
     RECT  29.28 22.787 29.712 25.139 ;
     RECT  15.9 25.139 18.912 25.187 ;
     RECT  4.56 25.139 6.12 25.427 ;
     RECT  25.632 24.517 28.248 25.619 ;
     RECT  30.96 25.477 30.984 25.621 ;
     RECT  24 23.555 24.312 25.717 ;
     RECT  10.368 24.755 10.812 26.101 ;
     RECT  13.2 23.987 14.472 26.101 ;
     RECT  13.104 26.101 14.472 26.149 ;
     RECT  20.496 25.139 22.296 26.197 ;
     RECT  24 25.717 24.504 26.197 ;
     RECT  15.9 25.187 17.544 26.243 ;
     RECT  30.768 25.621 30.984 26.245 ;
     RECT  20.496 26.197 24.504 26.291 ;
     RECT  10.368 26.101 11.4 26.293 ;
     RECT  26.208 25.619 28.248 26.293 ;
     RECT  29.4 25.139 29.712 26.293 ;
     RECT  20.496 26.291 24.312 26.341 ;
     RECT  4.608 25.427 6.12 26.389 ;
     RECT  33.6 26.389 33.624 26.485 ;
     RECT  30.768 26.245 31.032 26.533 ;
     RECT  32.1 24.563 32.412 26.533 ;
     RECT  26.208 26.293 29.712 26.629 ;
     RECT  30.768 26.533 32.412 26.629 ;
     RECT  4.608 26.389 6.168 26.677 ;
     RECT  18.6 25.187 18.912 26.677 ;
     RECT  19.92 26.341 24.312 26.677 ;
     RECT  18.6 26.677 24.312 26.771 ;
     RECT  21.12 26.771 24.312 26.819 ;
     RECT  4.128 26.677 6.168 27.205 ;
     RECT  7.8 25.139 8.952 27.205 ;
     RECT  13.104 26.149 14.856 27.205 ;
     RECT  26.208 26.629 32.412 27.349 ;
     RECT  33.456 26.485 33.624 27.349 ;
     RECT  4.128 27.205 8.952 27.395 ;
     RECT  23.424 26.819 24.312 27.397 ;
     RECT  23.424 27.397 24.456 27.493 ;
     RECT  18.6 26.771 19.944 27.733 ;
     RECT  21.12 26.819 22.344 27.733 ;
     RECT  12.528 27.205 14.856 27.781 ;
     RECT  15.9 26.243 17.016 27.781 ;
     RECT  26.208 27.349 33.624 27.875 ;
     RECT  10.08 26.293 11.4 27.877 ;
     RECT  9.984 27.877 11.4 27.923 ;
     RECT  18.6 27.733 22.344 27.925 ;
     RECT  12.528 27.781 17.016 27.971 ;
     RECT  18.336 27.925 22.344 27.971 ;
     RECT  14.832 27.971 17.016 28.451 ;
     RECT  26.4 27.875 33.624 28.499 ;
     RECT  32.1 28.499 33.624 28.547 ;
     RECT  15.024 28.451 17.016 28.643 ;
     RECT  19.92 27.971 22.344 28.835 ;
     RECT  26.4 28.499 30.888 28.835 ;
     RECT  28.128 28.835 30.888 29.075 ;
     RECT  4.128 27.395 8.112 29.123 ;
     RECT  18.336 27.971 18.912 29.123 ;
     RECT  23.424 27.493 24.504 29.123 ;
     RECT  21.072 28.835 22.344 29.171 ;
     RECT  23.52 29.123 24.504 29.267 ;
     RECT  2.4 22.451 2.712 29.605 ;
     RECT  4.128 29.123 6.168 29.605 ;
     RECT  32.1 28.547 33.48 29.605 ;
     RECT  34.8 22.499 35.112 29.605 ;
     RECT  7.8 29.123 8.112 30.181 ;
     RECT  26.4 28.835 27.012 30.181 ;
     RECT  28.272 29.075 30.888 30.181 ;
     RECT  2.4 29.605 6.168 30.325 ;
     RECT  7.152 30.181 8.112 30.325 ;
     RECT  26.4 30.181 30.888 30.613 ;
     RECT  18.6 29.123 18.912 30.709 ;
     RECT  19.92 28.835 19.944 30.709 ;
     RECT  32.1 29.605 35.112 30.755 ;
     RECT  23.52 29.267 24.312 30.757 ;
     RECT  23.52 30.757 24.408 30.997 ;
     RECT  9.984 27.923 10.812 31.045 ;
     RECT  12.528 27.971 13.656 31.091 ;
     RECT  2.4 30.325 8.112 31.237 ;
     RECT  32.1 30.755 33.432 31.237 ;
     RECT  2.4 31.237 8.232 31.331 ;
     RECT  26.256 30.613 30.888 31.333 ;
     RECT  31.968 31.237 33.432 31.381 ;
     RECT  26.208 31.333 30.888 31.427 ;
     RECT  36.096 31.381 36.12 31.571 ;
     RECT  23.52 30.997 24.504 31.765 ;
     RECT  26.208 31.427 28.296 31.765 ;
     RECT  9.696 31.045 10.812 31.955 ;
     RECT  31.92 31.381 33.432 32.291 ;
     RECT  23.52 31.765 28.296 32.387 ;
     RECT  9.984 31.955 10.812 32.437 ;
     RECT  3.84 31.331 8.232 32.485 ;
     RECT  31.968 32.291 33.432 32.485 ;
     RECT  3.84 32.485 8.52 32.531 ;
     RECT  29.4 31.427 30.888 32.821 ;
     RECT  18.6 30.709 19.944 33.011 ;
     RECT  15.9 28.643 17.016 33.013 ;
     RECT  18.6 33.011 19.8 33.013 ;
     RECT  9.984 32.437 11.688 33.059 ;
     RECT  29.04 32.821 30.888 33.395 ;
     RECT  15.36 33.013 17.016 33.445 ;
     RECT  18.192 33.013 19.8 33.445 ;
     RECT  31.968 32.485 33.624 33.541 ;
     RECT  34.8 30.755 35.112 33.541 ;
     RECT  31.968 33.541 35.112 33.925 ;
     RECT  31.968 33.925 35.352 34.259 ;
     RECT  5.1 32.531 8.52 34.643 ;
     RECT  23.52 32.387 27.96 34.691 ;
     RECT  23.52 34.691 27.48 34.739 ;
     RECT  9.984 33.059 10.812 34.741 ;
     RECT  15.36 33.445 19.8 34.741 ;
     RECT  15.36 34.741 19.848 34.787 ;
     RECT  32.1 34.259 35.352 34.787 ;
     RECT  18.6 34.787 19.848 34.789 ;
     RECT  21.12 29.171 22.344 34.789 ;
     RECT  3.84 32.531 3.864 34.835 ;
     RECT  15.36 34.787 17.016 34.931 ;
     RECT  29.04 33.395 30.792 35.029 ;
     RECT  5.1 34.643 8.232 35.269 ;
     RECT  13.008 31.091 13.656 35.507 ;
     RECT  23.76 34.739 27.48 35.701 ;
     RECT  28.464 35.029 30.792 35.701 ;
     RECT  13.008 35.507 13.608 35.797 ;
     RECT  23.424 35.701 30.792 35.845 ;
     RECT  34.8 34.787 35.352 35.939 ;
     RECT  18.6 34.789 22.344 35.941 ;
     RECT  4.656 35.269 8.232 36.035 ;
     RECT  23.424 35.845 31.032 36.227 ;
     RECT  32.1 34.787 33.672 36.421 ;
     RECT  12.672 35.797 13.608 36.565 ;
     RECT  9.648 34.741 10.812 36.613 ;
     RECT  12.576 36.565 13.608 36.613 ;
     RECT  6.576 36.035 8.112 36.997 ;
     RECT  15.9 34.931 17.016 36.997 ;
     RECT  18 35.941 22.344 36.997 ;
     RECT  9.648 36.613 13.608 37.091 ;
     RECT  25.92 36.227 31.032 37.141 ;
     RECT  32.1 36.421 33.816 37.141 ;
     RECT  6.576 36.997 8.232 37.189 ;
     RECT  6.576 37.189 8.808 37.523 ;
     RECT  15.9 36.997 22.344 37.667 ;
     RECT  23.424 36.227 24.504 37.861 ;
     RECT  9.984 37.091 13.608 37.957 ;
     RECT  4.656 36.035 5.544 38.005 ;
     RECT  6.576 37.523 8.28 38.005 ;
     RECT  18 37.667 22.344 38.147 ;
     RECT  18.6 38.147 22.344 38.149 ;
     RECT  23.328 37.861 24.504 38.149 ;
     RECT  25.92 37.141 33.816 38.197 ;
     RECT  34.8 35.939 35.112 38.197 ;
     RECT  4.656 38.005 8.28 38.243 ;
     RECT  5.1 38.243 8.28 38.677 ;
     RECT  2.4 31.331 2.712 38.725 ;
     RECT  9.984 37.957 13.992 38.725 ;
     RECT  9.984 38.725 14.232 38.771 ;
     RECT  5.1 38.677 8.856 38.819 ;
     RECT  25.92 38.197 35.112 38.819 ;
     RECT  6.576 38.819 8.856 39.251 ;
     RECT  12.576 38.771 14.232 39.301 ;
     RECT  15.9 37.667 17.016 39.301 ;
     RECT  12.576 39.301 17.016 39.443 ;
     RECT  18.6 38.149 24.504 39.587 ;
     RECT  2.4 38.725 3.192 39.635 ;
     RECT  25.92 38.819 33.816 39.779 ;
     RECT  6.576 39.251 8.568 39.875 ;
     RECT  12.576 39.443 13.944 39.877 ;
     RECT  20.112 39.587 24.504 40.019 ;
     RECT  25.92 39.779 33.528 40.453 ;
     RECT  20.352 40.019 24.504 40.499 ;
     RECT  34.8 38.819 35.112 40.933 ;
     RECT  6.576 39.875 8.112 40.981 ;
     RECT  9.984 38.771 10.812 40.981 ;
     RECT  15.168 39.443 17.016 40.981 ;
     RECT  15.168 40.981 17.112 41.077 ;
     RECT  15.168 41.077 17.208 41.219 ;
     RECT  2.4 39.635 2.712 41.221 ;
     RECT  20.352 40.499 24.408 41.315 ;
     RECT  25.584 40.453 33.528 41.363 ;
     RECT  25.584 41.363 33.336 41.411 ;
     RECT  6.576 40.981 8.232 41.651 ;
     RECT  20.352 41.315 23.016 41.699 ;
     RECT  24 41.315 24.408 41.699 ;
     RECT  15.168 41.219 17.016 41.747 ;
     RECT  11.808 39.877 13.944 41.939 ;
     RECT  9.408 40.981 10.812 42.181 ;
     RECT  9.408 42.181 11.304 42.323 ;
     RECT  18.6 39.587 18.912 42.517 ;
     RECT  20.544 41.699 23.016 42.563 ;
     RECT  15.9 41.747 17.016 42.709 ;
     RECT  9.408 42.323 10.812 42.755 ;
     RECT  12.288 41.939 13.944 42.755 ;
     RECT  18.6 42.517 19.032 42.757 ;
     RECT  26.7 41.411 33.336 42.851 ;
     RECT  31.584 42.851 33.336 43.379 ;
     RECT  26.7 42.851 30.504 43.571 ;
     RECT  14.928 42.709 17.016 43.717 ;
     RECT  6.576 41.651 8.112 43.813 ;
     RECT  29.28 43.571 30.504 43.861 ;
     RECT  31.584 43.379 33.192 43.861 ;
     RECT  20.976 42.563 23.016 43.955 ;
     RECT  24 41.699 24.312 44.197 ;
     RECT  20.976 43.955 22.824 44.243 ;
     RECT  24 44.197 24.408 44.293 ;
     RECT  25.584 41.411 25.608 44.293 ;
     RECT  34.8 40.933 35.208 44.483 ;
     RECT  6.576 43.813 8.376 44.725 ;
     RECT  29.28 43.861 33.192 44.771 ;
     RECT  20.976 44.243 22.344 44.869 ;
     RECT  12.288 42.755 13.608 44.917 ;
     RECT  12 44.917 13.608 44.963 ;
     RECT  14.736 43.717 17.016 44.965 ;
     RECT  18.384 42.757 19.032 44.965 ;
     RECT  20.544 44.869 22.344 44.965 ;
     RECT  2.4 41.221 3 45.155 ;
     RECT  29.4 44.771 33.192 45.251 ;
     RECT  5.1 38.819 5.544 45.541 ;
     RECT  6.576 44.725 8.568 45.541 ;
     RECT  24 44.293 25.608 45.541 ;
     RECT  26.7 43.571 28.296 45.541 ;
     RECT  24 45.541 28.296 45.781 ;
     RECT  14.736 44.965 19.032 46.115 ;
     RECT  29.4 45.251 33.144 46.115 ;
     RECT  23.856 45.781 28.296 46.163 ;
     RECT  12 44.963 13.512 46.211 ;
     RECT  14.976 46.115 19.032 46.259 ;
     RECT  25.392 46.163 28.296 46.259 ;
     RECT  5.1 45.541 8.568 46.307 ;
     RECT  25.392 46.259 28.152 46.547 ;
     RECT  14.976 46.259 18.912 46.787 ;
     RECT  14.976 46.787 17.016 46.835 ;
     RECT  23.856 46.163 24.408 46.837 ;
     RECT  23.328 46.837 24.408 46.883 ;
     RECT  20.4 44.965 22.344 46.933 ;
     RECT  34.8 44.483 35.112 47.029 ;
     RECT  25.392 46.547 27.768 47.075 ;
     RECT  0.192 46.981 0.312 47.123 ;
     RECT  34.8 47.029 35.208 47.845 ;
     RECT  34.8 47.845 35.304 48.085 ;
     RECT  14.88 47.845 14.904 48.131 ;
     RECT  15.9 46.835 17.016 48.133 ;
     RECT  18.24 46.787 18.912 48.133 ;
     RECT  34.704 48.085 35.304 48.227 ;
     RECT  29.4 46.115 32.412 48.277 ;
     RECT  20.16 46.933 22.344 48.421 ;
     RECT  23.328 46.883 24.312 48.421 ;
     RECT  34.8 48.227 35.304 48.947 ;
     RECT  14.832 48.229 14.856 49.091 ;
     RECT  15.9 48.133 18.912 49.091 ;
     RECT  25.488 47.075 27.768 49.091 ;
     RECT  28.992 48.277 32.412 49.379 ;
     RECT  5.1 46.307 8.112 49.523 ;
     RECT  15.9 49.091 17.016 49.523 ;
     RECT  9.984 42.755 10.812 49.525 ;
     RECT  12.288 46.211 13.512 49.525 ;
     RECT  20.16 48.421 24.312 49.525 ;
     RECT  9.984 49.525 13.512 49.619 ;
     RECT  2.4 45.155 2.712 49.909 ;
     RECT  25.536 49.091 25.608 50.149 ;
     RECT  19.968 49.525 24.312 50.629 ;
     RECT  25.44 50.149 25.608 50.629 ;
     RECT  15.9 49.523 16.872 50.677 ;
     RECT  34.8 48.947 35.208 50.677 ;
     RECT  10.08 49.619 13.512 50.771 ;
     RECT  10.08 50.771 11.016 50.819 ;
     RECT  19.968 50.629 25.608 50.819 ;
     RECT  20.16 50.819 25.608 50.869 ;
     RECT  26.592 49.091 27.768 50.869 ;
     RECT  34.224 50.677 35.208 51.347 ;
     RECT  29.136 49.379 32.412 51.445 ;
     RECT  29.136 51.445 32.808 51.731 ;
     RECT  12.24 50.771 13.512 51.925 ;
     RECT  15.696 50.677 16.872 51.971 ;
     RECT  12.24 51.925 13.8 51.973 ;
     RECT  12.24 51.973 14.232 52.499 ;
     RECT  29.136 51.731 32.412 52.499 ;
     RECT  18.24 49.091 18.912 52.645 ;
     RECT  18.192 52.645 18.912 52.741 ;
     RECT  15.696 51.971 16.392 52.933 ;
     RECT  18.192 52.741 19.032 52.933 ;
     RECT  17.568 52.933 19.032 53.075 ;
     RECT  15.552 52.933 16.392 53.077 ;
     RECT  12.24 52.499 13.8 53.219 ;
     RECT  10.5 50.819 11.016 53.365 ;
     RECT  12.24 53.219 13.512 53.365 ;
     RECT  34.8 51.347 35.208 53.365 ;
     RECT  15.552 53.077 16.536 53.509 ;
     RECT  17.568 53.075 18.912 53.509 ;
     RECT  34.8 53.365 35.928 53.555 ;
     RECT  5.1 49.523 5.412 53.557 ;
     RECT  20.16 50.869 27.768 53.603 ;
     RECT  2.4 49.909 3.288 53.795 ;
     RECT  29.184 52.499 32.412 54.037 ;
     RECT  6.624 49.523 8.112 54.085 ;
     RECT  15.552 53.509 18.912 54.085 ;
     RECT  20.16 53.603 22.824 54.085 ;
     RECT  24 53.603 27.768 54.227 ;
     RECT  15.552 54.085 22.824 54.371 ;
     RECT  29.184 54.037 33.096 54.613 ;
     RECT  6.624 54.085 8.232 54.661 ;
     RECT  17.568 54.371 22.824 54.755 ;
     RECT  6.528 54.661 8.232 55.237 ;
     RECT  9.408 50.965 9.432 55.237 ;
     RECT  29.088 54.613 33.096 55.523 ;
     RECT  24 54.227 24.312 55.861 ;
     RECT  29.088 55.523 32.664 55.955 ;
     RECT  15.552 54.371 16.584 56.003 ;
     RECT  10.5 53.365 13.512 56.243 ;
     RECT  6.528 55.237 9.432 56.293 ;
     RECT  10.5 56.243 11.016 56.293 ;
     RECT  15.6 56.003 16.584 56.387 ;
     RECT  24 55.861 24.408 56.531 ;
     RECT  6.528 56.293 11.016 56.771 ;
     RECT  15.792 56.387 16.584 56.915 ;
     RECT  2.4 53.795 2.712 57.205 ;
     RECT  12.24 56.243 13.512 57.445 ;
     RECT  17.568 54.755 18.912 57.589 ;
     RECT  25.44 54.227 27.768 57.875 ;
     RECT  12.24 57.445 14.184 57.923 ;
     RECT  34.8 53.555 35.208 57.923 ;
     RECT  34.8 57.923 35.112 57.973 ;
     RECT  2.4 57.205 3.432 58.117 ;
     RECT  2.4 58.117 3.72 58.163 ;
     RECT  29.088 55.955 32.412 58.163 ;
     RECT  5.1 53.557 5.544 58.309 ;
     RECT  6.624 56.771 11.016 58.309 ;
     RECT  20.16 54.755 22.824 58.499 ;
     RECT  25.44 57.875 27.012 58.549 ;
     RECT  15.792 56.915 16.44 58.645 ;
     RECT  5.1 58.309 11.016 58.691 ;
     RECT  24 56.531 24.312 59.029 ;
     RECT  25.296 58.549 27.012 59.029 ;
     RECT  29.4 58.163 32.412 59.029 ;
     RECT  5.1 58.691 9.432 59.221 ;
     RECT  34.416 57.973 35.112 59.317 ;
     RECT  14.832 58.645 16.44 59.459 ;
     RECT  20.496 58.499 22.824 59.507 ;
     RECT  10.5 58.691 11.016 59.603 ;
     RECT  29.4 59.029 33.096 59.701 ;
     RECT  34.416 59.317 35.208 59.795 ;
     RECT  4.992 59.221 9.432 59.891 ;
     RECT  12.24 57.923 13.512 59.989 ;
     RECT  24 59.029 27.012 60.131 ;
     RECT  17.568 57.589 19.032 60.277 ;
     RECT  5.1 59.891 9.432 60.373 ;
     RECT  10.5 59.603 10.812 60.373 ;
     RECT  5.1 60.373 10.812 60.467 ;
     RECT  12.24 59.989 14.232 60.467 ;
     RECT  28.944 59.701 33.096 60.467 ;
     RECT  3.696 58.163 3.72 60.803 ;
     RECT  15.792 59.459 16.44 60.805 ;
     RECT  17.568 60.277 19.08 60.805 ;
     RECT  20.496 59.507 22.344 60.949 ;
     RECT  24 60.131 24.456 60.949 ;
     RECT  20.496 60.949 24.456 61.381 ;
     RECT  25.44 60.131 27.012 61.381 ;
     RECT  5.1 60.467 5.412 61.525 ;
     RECT  6.432 60.467 10.812 62.101 ;
     RECT  12.24 60.467 13.512 62.101 ;
     RECT  28.944 60.467 32.412 62.195 ;
     RECT  15.792 60.805 19.08 62.533 ;
     RECT  20.496 61.381 27.012 62.533 ;
     RECT  2.4 58.163 2.712 62.581 ;
     RECT  6.432 62.101 13.512 62.723 ;
     RECT  38.208 62.533 38.232 62.723 ;
     RECT  29.4 62.195 32.412 63.061 ;
     RECT  15.792 62.533 27.012 63.203 ;
     RECT  4.56 61.525 5.412 63.251 ;
     RECT  15.792 63.203 22.344 63.395 ;
     RECT  29.4 63.061 33.048 63.781 ;
     RECT  15.792 63.395 17.592 63.827 ;
     RECT  17.472 63.827 17.592 63.923 ;
     RECT  18.6 63.395 22.344 64.019 ;
     RECT  15.792 63.827 16.488 64.165 ;
     RECT  6.432 62.723 9.432 64.211 ;
     RECT  24 63.203 27.012 64.309 ;
     RECT  6.432 64.211 9.096 64.355 ;
     RECT  10.5 62.723 13.512 64.357 ;
     RECT  23.52 64.309 27.012 64.357 ;
     RECT  28.512 63.781 33.048 64.451 ;
     RECT  6.432 64.355 8.376 64.547 ;
     RECT  10.5 64.357 14.088 64.595 ;
     RECT  28.8 64.451 33.048 64.595 ;
     RECT  17.568 63.923 17.592 64.693 ;
     RECT  18.6 64.019 19.56 64.693 ;
     RECT  15.168 64.165 16.488 64.885 ;
     RECT  17.568 64.693 19.56 64.885 ;
     RECT  5.1 63.251 5.412 64.933 ;
     RECT  15.168 64.885 19.56 65.027 ;
     RECT  28.8 64.595 30.312 65.027 ;
     RECT  23.52 64.357 27.144 65.075 ;
     RECT  15.36 65.027 19.56 65.171 ;
     RECT  34.416 59.795 35.112 65.269 ;
     RECT  34.416 65.269 35.208 65.365 ;
     RECT  15.9 65.171 19.56 65.461 ;
     RECT  20.592 64.019 22.344 65.461 ;
     RECT  31.824 64.595 33.048 65.509 ;
     RECT  34.176 65.365 35.208 65.509 ;
     RECT  23.52 65.075 27.012 65.651 ;
     RECT  26.448 65.651 27.012 65.699 ;
     RECT  31.824 65.509 35.208 65.987 ;
     RECT  4.608 64.933 5.412 66.131 ;
     RECT  15.9 65.461 22.344 66.277 ;
     RECT  23.52 65.651 25.032 66.277 ;
     RECT  15.9 66.277 25.032 66.323 ;
     RECT  2.4 62.581 3.288 66.515 ;
     RECT  15.9 66.323 21.72 66.563 ;
     RECT  28.896 65.027 30.312 66.565 ;
     RECT  10.5 64.595 10.968 66.611 ;
     RECT  17.568 66.563 21.72 66.611 ;
     RECT  22.752 66.323 25.032 66.611 ;
     RECT  23.424 66.611 25.032 66.709 ;
     RECT  6.816 64.547 8.376 66.755 ;
     RECT  12.24 64.595 14.088 67.187 ;
     RECT  20.784 66.611 21.72 67.283 ;
     RECT  31.824 65.987 35.112 67.283 ;
     RECT  28.176 66.565 30.312 67.285 ;
     RECT  26.7 65.699 27.012 67.381 ;
     RECT  28.176 67.285 30.792 67.381 ;
     RECT  10.5 66.611 10.812 67.525 ;
     RECT  31.824 67.283 33.576 67.571 ;
     RECT  12.288 67.187 14.088 67.621 ;
     RECT  23.424 66.709 25.128 67.669 ;
     RECT  17.568 66.611 19.56 67.717 ;
     RECT  20.784 67.283 21.612 67.717 ;
     RECT  26.7 67.381 30.792 67.765 ;
     RECT  31.968 67.571 33.576 68.099 ;
     RECT  26.7 67.765 30.84 68.341 ;
     RECT  12.288 67.621 14.232 68.435 ;
     RECT  23.376 67.669 25.128 68.677 ;
     RECT  15.9 66.563 16.44 68.869 ;
     RECT  17.568 67.717 21.612 68.869 ;
     RECT  9.648 67.525 10.812 68.915 ;
     RECT  5.1 66.131 5.412 68.917 ;
     RECT  6.816 66.755 8.232 68.917 ;
     RECT  5.1 68.917 8.232 68.963 ;
     RECT  23.232 68.677 25.128 68.963 ;
     RECT  26.112 68.341 30.84 69.349 ;
     RECT  23.232 68.963 24.312 69.445 ;
     RECT  14.784 69.253 14.808 69.493 ;
     RECT  15.9 68.869 21.612 69.493 ;
     RECT  32.1 68.099 33.576 69.587 ;
     RECT  5.1 68.963 6.216 69.637 ;
     RECT  2.4 66.515 3.096 69.731 ;
     RECT  7.8 68.963 8.232 69.781 ;
     RECT  26.112 69.349 31.128 70.115 ;
     RECT  14.784 69.493 21.612 70.163 ;
     RECT  26.112 70.115 30.312 70.403 ;
     RECT  34.8 67.283 35.112 70.597 ;
     RECT  34.704 70.597 35.112 70.645 ;
     RECT  7.8 69.781 8.712 70.933 ;
     RECT  15.744 70.163 21.612 71.125 ;
     RECT  33.648 70.789 33.672 71.269 ;
     RECT  34.704 70.645 35.304 71.269 ;
     RECT  4.512 69.637 6.216 71.315 ;
     RECT  26.208 70.403 30.312 71.317 ;
     RECT  5.1 71.315 6.216 71.461 ;
     RECT  7.68 70.933 8.712 71.461 ;
     RECT  26.208 71.317 30.984 71.555 ;
     RECT  5.1 71.461 8.712 71.651 ;
     RECT  12.288 68.435 13.656 71.749 ;
     RECT  33.648 71.269 35.304 71.795 ;
     RECT  26.208 71.555 30.312 71.843 ;
     RECT  33.648 71.795 35.208 71.891 ;
     RECT  9.264 71.749 9.288 71.939 ;
     RECT  32.1 69.587 32.616 72.373 ;
     RECT  26.7 71.843 30.312 72.805 ;
     RECT  12.288 71.749 14.568 72.901 ;
     RECT  26.7 72.805 30.408 73.045 ;
     RECT  15.696 71.125 21.612 73.283 ;
     RECT  25.776 73.045 30.408 73.283 ;
     RECT  34.608 71.891 35.112 73.381 ;
     RECT  5.1 71.651 8.28 73.477 ;
     RECT  12.288 72.901 14.616 73.523 ;
     RECT  25.776 73.283 27.012 73.763 ;
     RECT  31.536 72.373 32.616 74.005 ;
     RECT  4.416 73.477 8.28 74.101 ;
     RECT  23.088 69.445 24.312 74.149 ;
     RECT  4.416 74.101 8.376 74.293 ;
     RECT  25.872 73.763 27.012 74.293 ;
     RECT  28.8 73.283 30.408 74.293 ;
     RECT  12.288 73.523 14.28 74.485 ;
     RECT  25.872 74.293 30.408 74.723 ;
     RECT  34.368 73.381 35.112 74.725 ;
     RECT  27.984 74.723 30.408 74.867 ;
     RECT  15.9 73.283 21.612 74.965 ;
     RECT  11.856 74.485 14.28 75.011 ;
     RECT  29.28 74.867 30.408 75.157 ;
     RECT  31.392 74.005 32.616 75.157 ;
     RECT  29.28 75.157 32.616 75.203 ;
     RECT  11.856 75.011 13.512 75.251 ;
     RECT  23.088 74.149 24.408 75.443 ;
     RECT  2.4 69.731 2.712 75.541 ;
     RECT  10.5 68.915 10.812 75.541 ;
     RECT  32.1 75.203 32.616 75.781 ;
     RECT  34.368 74.725 35.592 75.781 ;
     RECT  12.288 75.251 13.512 75.875 ;
     RECT  4.32 74.293 8.376 76.021 ;
     RECT  32.1 75.781 35.592 76.067 ;
     RECT  4.32 76.021 9.24 76.211 ;
     RECT  23.088 75.443 24.312 76.211 ;
     RECT  27.984 74.867 28.008 76.211 ;
     RECT  29.28 75.203 30.84 76.451 ;
     RECT  32.1 76.067 35.304 76.499 ;
     RECT  10.32 75.541 10.812 76.693 ;
     RECT  10.272 76.693 10.812 76.789 ;
     RECT  32.1 76.499 33.096 76.835 ;
     RECT  32.1 76.835 32.616 77.125 ;
     RECT  10.272 76.789 11.448 77.173 ;
     RECT  12.72 75.875 13.512 77.173 ;
     RECT  15.792 74.965 21.612 77.173 ;
     RECT  2.4 75.541 2.904 77.315 ;
     RECT  15.792 77.173 21.864 77.317 ;
     RECT  29.28 76.451 30.216 77.461 ;
     RECT  10.272 77.173 13.512 77.699 ;
     RECT  23.424 76.211 24.312 77.893 ;
     RECT  29.184 77.461 30.216 77.893 ;
     RECT  31.248 77.125 32.616 77.893 ;
     RECT  4.32 76.211 8.28 78.083 ;
     RECT  15.312 77.317 21.864 78.131 ;
     RECT  34.704 76.499 35.304 78.179 ;
     RECT  34.704 78.179 35.112 78.227 ;
     RECT  29.184 77.893 32.616 78.467 ;
     RECT  2.4 77.315 2.712 78.613 ;
     RECT  4.32 78.083 5.976 78.613 ;
     RECT  7.056 78.083 8.28 78.707 ;
     RECT  2.4 78.613 5.976 78.709 ;
     RECT  30.912 78.467 32.616 78.755 ;
     RECT  15.312 78.131 21.612 78.757 ;
     RECT  2.304 78.709 5.976 78.851 ;
     RECT  25.872 74.723 27.012 79.475 ;
     RECT  30.912 78.755 32.412 79.475 ;
     RECT  23.376 77.893 24.312 79.477 ;
     RECT  33.744 78.613 33.768 79.477 ;
     RECT  34.8 78.227 35.112 79.477 ;
     RECT  33.744 79.477 35.112 79.765 ;
     RECT  29.184 78.467 29.712 79.811 ;
     RECT  15.264 78.757 21.612 79.813 ;
     RECT  2.4 78.851 5.976 80.003 ;
     RECT  10.368 77.699 13.512 80.051 ;
     RECT  29.4 79.811 29.712 80.293 ;
     RECT  0.192 47.123 0.216 80.533 ;
     RECT  15.264 79.813 21.96 80.533 ;
     RECT  23.376 79.477 24.408 80.533 ;
     RECT  2.4 80.003 3.432 80.771 ;
     RECT  15.264 80.533 24.408 81.011 ;
     RECT  33.744 79.765 35.208 81.011 ;
     RECT  0.192 80.533 1.176 81.059 ;
     RECT  5.1 80.003 5.976 81.061 ;
     RECT  4.608 81.061 5.976 81.107 ;
     RECT  33.744 81.011 35.112 81.203 ;
     RECT  23.376 81.011 24.408 81.397 ;
     RECT  10.5 80.051 13.512 81.445 ;
     RECT  15.264 81.011 21.96 81.491 ;
     RECT  26.208 79.475 27.012 81.539 ;
     RECT  29.4 80.293 29.832 81.877 ;
     RECT  10.5 81.445 14.232 82.019 ;
     RECT  2.4 80.771 2.712 82.021 ;
     RECT  29.28 81.877 29.832 82.069 ;
     RECT  28.848 82.069 29.832 82.115 ;
     RECT  7.056 78.707 8.112 82.163 ;
     RECT  15.408 81.491 18.912 82.163 ;
     RECT  19.92 81.491 21.96 82.307 ;
     RECT  15.552 82.163 18.912 82.451 ;
     RECT  28.848 82.115 29.712 82.547 ;
     RECT  32.1 79.475 32.412 82.549 ;
     RECT  7.68 82.163 8.112 82.597 ;
     RECT  4.608 81.107 5.88 82.691 ;
     RECT  7.68 82.597 8.616 82.739 ;
     RECT  26.256 81.539 27.012 82.741 ;
     RECT  23.376 81.397 24.504 82.789 ;
     RECT  26.256 82.741 27.24 83.171 ;
     RECT  34.032 81.203 35.112 83.171 ;
     RECT  2.4 82.021 3.384 83.221 ;
     RECT  29.28 82.547 29.712 83.317 ;
     RECT  2.4 83.221 3.624 83.363 ;
     RECT  15.9 82.451 18.912 83.749 ;
     RECT  7.8 82.739 8.616 84.035 ;
     RECT  26.592 83.171 27.24 84.035 ;
     RECT  15.792 83.749 18.912 84.181 ;
     RECT  19.92 82.307 21.912 84.181 ;
     RECT  26.592 84.035 27.144 84.325 ;
     RECT  34.224 83.171 35.112 84.325 ;
     RECT  15.792 84.181 21.912 84.371 ;
     RECT  30.912 79.475 30.936 84.371 ;
     RECT  2.4 83.363 3.192 84.517 ;
     RECT  4.608 82.691 5.412 84.517 ;
     RECT  10.5 82.019 13.512 84.611 ;
     RECT  2.4 84.517 5.412 84.707 ;
     RECT  12.576 84.611 13.512 84.851 ;
     RECT  7.8 84.035 8.568 84.853 ;
     RECT  29.28 83.317 29.832 84.901 ;
     RECT  2.4 84.707 3.192 84.995 ;
     RECT  23.376 82.789 25.128 84.995 ;
     RECT  23.376 84.995 24.504 85.283 ;
     RECT  34.176 84.325 35.112 85.283 ;
     RECT  31.968 82.549 32.412 85.381 ;
     RECT  15.9 84.371 21.912 85.523 ;
     RECT  28.944 84.901 29.832 85.523 ;
     RECT  7.056 84.853 8.568 85.573 ;
     RECT  18 85.523 21.912 85.667 ;
     RECT  7.056 85.573 9.144 85.715 ;
     RECT  10.5 84.611 11.256 85.957 ;
     RECT  2.4 84.995 2.712 86.005 ;
     RECT  20.496 85.667 21.912 86.005 ;
     RECT  29.4 85.523 29.832 86.051 ;
     RECT  12.624 84.851 13.512 86.099 ;
     RECT  15.9 85.523 17.016 86.291 ;
     RECT  26.544 84.325 27.144 86.293 ;
     RECT  25.68 86.293 27.144 86.339 ;
     RECT  10.5 85.957 11.4 86.675 ;
     RECT  7.056 85.715 9.048 86.725 ;
     RECT  18 85.667 19.08 86.773 ;
     RECT  23.904 85.283 24.504 86.917 ;
     RECT  25.68 86.339 27.012 86.917 ;
     RECT  23.904 86.917 27.012 87.107 ;
     RECT  17.952 86.773 19.08 87.109 ;
     RECT  20.496 86.005 22.104 87.109 ;
     RECT  34.512 85.283 35.112 87.109 ;
     RECT  17.952 87.109 22.104 87.155 ;
     RECT  30.864 87.157 30.888 87.205 ;
     RECT  4.608 84.707 5.412 87.251 ;
     RECT  15.9 86.291 16.536 87.251 ;
     RECT  25.632 87.107 27.012 87.347 ;
     RECT  25.632 87.347 25.704 87.395 ;
     RECT  12.816 86.099 13.512 87.445 ;
     RECT  6.816 86.725 9.048 87.683 ;
     RECT  6.816 87.683 8.856 87.827 ;
     RECT  25.632 87.395 25.656 87.827 ;
     RECT  20.016 87.155 22.104 87.923 ;
     RECT  17.952 87.155 18.912 88.067 ;
     RECT  7.056 87.827 8.856 88.307 ;
     RECT  23.904 87.107 24.504 88.309 ;
     RECT  33.552 87.109 35.112 88.499 ;
     RECT  34.512 88.499 35.112 88.643 ;
     RECT  30.72 87.205 30.888 88.691 ;
     RECT  23.232 88.309 24.504 88.931 ;
     RECT  31.872 85.381 32.412 88.979 ;
     RECT  29.4 86.051 29.712 89.029 ;
     RECT  7.392 88.307 8.856 89.171 ;
     RECT  29.4 89.029 30.36 89.221 ;
     RECT  32.1 88.979 32.412 89.317 ;
     RECT  15.9 87.251 16.44 89.363 ;
     RECT  5.1 87.251 5.412 89.461 ;
     RECT  18.6 88.067 18.912 89.461 ;
     RECT  12.816 87.445 14.712 89.555 ;
     RECT  20.016 87.923 21.612 89.555 ;
     RECT  34.656 88.643 35.112 89.845 ;
     RECT  15.9 89.363 16.344 89.941 ;
     RECT  29.04 89.221 30.36 89.989 ;
     RECT  12.912 89.555 14.712 90.037 ;
     RECT  15.792 89.941 16.344 90.037 ;
     RECT  23.904 88.931 24.504 90.083 ;
     RECT  5.1 89.461 5.736 90.275 ;
     RECT  24 90.083 24.504 90.275 ;
     RECT  12.912 90.037 16.344 90.371 ;
     RECT  12.912 90.371 13.944 90.517 ;
     RECT  32.1 89.317 32.568 90.611 ;
     RECT  2.4 86.005 3.48 90.659 ;
     RECT  34.128 89.845 35.112 90.659 ;
     RECT  15.6 90.371 16.344 90.851 ;
     RECT  7.8 89.171 8.856 91.091 ;
     RECT  17.952 89.461 18.912 91.091 ;
     RECT  5.1 90.275 5.412 91.141 ;
     RECT  26.7 87.347 27.012 91.189 ;
     RECT  7.8 91.091 8.568 91.331 ;
     RECT  28.464 89.989 30.36 91.427 ;
     RECT  10.5 86.675 11.256 91.859 ;
     RECT  32.1 90.611 32.412 91.861 ;
     RECT  20.784 89.555 21.612 92.003 ;
     RECT  12.672 90.517 13.944 92.099 ;
     RECT  0.192 81.059 0.216 92.147 ;
     RECT  26.256 91.189 27.012 92.339 ;
     RECT  28.464 91.427 29.712 92.339 ;
     RECT  32.1 91.861 32.52 92.339 ;
     RECT  4.368 91.141 5.412 92.387 ;
     RECT  18.192 91.091 18.912 92.435 ;
     RECT  22.896 91.717 22.92 92.435 ;
     RECT  13.2 92.099 13.944 92.675 ;
     RECT  15.6 90.851 16.212 92.821 ;
     RECT  2.4 90.659 2.712 92.889 ;
     RECT  5.1 92.387 5.412 92.889 ;
     RECT  7.8 91.331 8.112 92.889 ;
     RECT  10.5 91.859 10.812 92.889 ;
     RECT  13.2 92.675 13.512 92.889 ;
     RECT  15.216 92.821 16.212 92.889 ;
     RECT  18.6 92.435 18.912 92.889 ;
     RECT  21.3 92.003 21.612 92.889 ;
     RECT  24 90.275 24.312 92.889 ;
     RECT  26.7 92.339 27.012 92.889 ;
     RECT  29.4 92.339 29.712 92.889 ;
     RECT  32.1 92.339 32.412 92.889 ;
     RECT  34.8 90.659 35.112 92.889 ;
     RECT  2.4 92.889 2.52 92.903 ;
     RECT  5.1 92.889 5.22 92.903 ;
     RECT  7.8 92.889 7.92 92.903 ;
     RECT  10.5 92.889 10.62 92.903 ;
     RECT  13.2 92.889 13.32 92.903 ;
     RECT  15.216 92.889 16.02 92.903 ;
     RECT  18.6 92.889 18.72 92.903 ;
     RECT  21.3 92.889 21.42 92.903 ;
     RECT  24 92.889 24.12 92.903 ;
     RECT  26.7 92.889 26.82 92.903 ;
     RECT  29.4 92.889 29.52 92.903 ;
     RECT  32.1 92.889 32.22 92.903 ;
     RECT  34.8 92.889 34.92 92.903 ;
     RECT  13.512 2.197 14.784 2.245 ;
     RECT  14.808 2.197 15.9 3.397 ;
     RECT  21.612 2.197 22.608 2.245 ;
     RECT  22.632 2.197 24 2.245 ;
     RECT  5.412 2.245 6.624 3.587 ;
     RECT  6.648 2.245 7.8 3.587 ;
     RECT  13.512 2.245 14.688 2.915 ;
     RECT  29.712 2.629 30.768 3.301 ;
     RECT  30.792 2.629 32.1 2.821 ;
     RECT  30.792 2.821 31.968 4.019 ;
     RECT  13.512 2.915 14.784 3.443 ;
     RECT  32.412 3.299 32.904 3.925 ;
     RECT  14.808 3.397 15.792 3.443 ;
     RECT  13.512 3.443 15.792 3.829 ;
     RECT  9.048 3.541 10.368 3.877 ;
     RECT  13.512 3.829 14.88 4.453 ;
     RECT  9.384 3.877 10.368 4.355 ;
     RECT  32.412 3.925 33.648 5.123 ;
     RECT  33.672 3.925 34.8 4.645 ;
     RECT  30.792 4.019 32.1 4.643 ;
     RECT  8.904 4.355 10.368 5.365 ;
     RECT  13.512 4.453 14.784 5.171 ;
     RECT  2.712 4.595 3.432 5.605 ;
     RECT  33.768 4.645 34.8 4.787 ;
     RECT  33.672 4.787 34.8 5.123 ;
     RECT  22.296 4.931 23.28 6.373 ;
     RECT  9 5.365 10.368 5.747 ;
     RECT  6.36 5.557 7.8 6.997 ;
     RECT  16.212 5.603 16.344 6.757 ;
     RECT  2.712 5.605 3.696 6.899 ;
     RECT  3.72 5.605 5.1 6.899 ;
     RECT  8.112 5.747 10.368 7.093 ;
     RECT  4.992 6.899 5.1 7.141 ;
     RECT  8.112 7.093 9.12 7.283 ;
     RECT  9.144 7.093 10.368 7.283 ;
     RECT  11.928 7.189 13.2 7.909 ;
     RECT  10.92 7.235 11.904 8.629 ;
     RECT  24.312 7.621 25.632 8.963 ;
     RECT  27.012 7.861 27.984 8.437 ;
     RECT  28.008 7.861 29.088 8.099 ;
     RECT  11.928 7.909 12.912 8.677 ;
     RECT  28.008 8.099 29.136 8.531 ;
     RECT  13.512 8.149 14.832 10.165 ;
     RECT  6.024 8.531 7.152 9.589 ;
     RECT  28.008 8.531 29.232 8.579 ;
     RECT  19.416 8.677 20.448 10.259 ;
     RECT  24.312 8.963 24.504 9.445 ;
     RECT  17.112 9.013 18.6 9.155 ;
     RECT  30.504 9.109 31.92 9.683 ;
     RECT  24.456 9.445 24.504 10.069 ;
     RECT  9.096 9.637 10.5 9.829 ;
     RECT  9.144 9.829 10.5 10.405 ;
     RECT  16.212 10.019 16.44 11.461 ;
     RECT  9.336 10.405 10.5 11.315 ;
     RECT  22.872 10.595 24 11.699 ;
     RECT  29.712 10.595 29.832 11.941 ;
     RECT  13.512 11.123 14.784 12.035 ;
     RECT  8.28 11.315 10.5 11.509 ;
     RECT  8.28 11.509 9.408 12.325 ;
     RECT  16.44 11.605 17.52 11.747 ;
     RECT  17.544 11.605 18.6 12.563 ;
     RECT  22.824 11.699 24 15.829 ;
     RECT  16.212 11.747 17.52 12.563 ;
     RECT  6.024 11.987 7.44 14.389 ;
     RECT  13.512 12.035 15.168 13.045 ;
     RECT  31.776 12.467 32.1 13.093 ;
     RECT  9.48 12.563 10.5 14.149 ;
     RECT  16.212 12.563 18.6 13.045 ;
     RECT  18.912 12.853 20.352 13.139 ;
     RECT  13.512 13.045 15.024 14.339 ;
     RECT  16.212 13.045 17.376 13.909 ;
     RECT  17.4 13.045 18.6 14.339 ;
     RECT  30.744 13.093 32.1 13.427 ;
     RECT  3.432 13.333 4.8 14.341 ;
     RECT  8.28 13.571 9.456 13.955 ;
     RECT  16.344 13.909 17.376 14.339 ;
     RECT  8.232 13.955 9.456 14.147 ;
     RECT  8.112 14.147 9.456 16.357 ;
     RECT  13.512 14.339 15.792 14.917 ;
     RECT  16.344 14.339 16.392 15.493 ;
     RECT  6.12 14.389 7.44 14.629 ;
     RECT  29.832 14.723 29.88 15.829 ;
     RECT  2.712 14.867 4.128 15.395 ;
     RECT  28.992 14.915 29.04 16.261 ;
     RECT  14.376 14.917 15.792 15.733 ;
     RECT  2.712 15.395 4.224 17.651 ;
     RECT  14.472 15.733 15.792 15.829 ;
     RECT  9.48 15.875 10.5 17.699 ;
     RECT  8.376 16.357 9.456 16.979 ;
     RECT  8.112 16.979 9.456 17.699 ;
     RECT  16.344 17.123 16.392 18.421 ;
     RECT  13.512 17.171 14.832 18.131 ;
     RECT  18.24 17.171 18.6 18.421 ;
     RECT  2.712 17.651 4.992 18.709 ;
     RECT  13.512 18.131 14.928 18.179 ;
     RECT  13.512 18.179 15.648 19.333 ;
     RECT  17.16 18.421 18.6 20.723 ;
     RECT  2.712 18.709 4.224 19.717 ;
     RECT  22.296 19.283 23.328 20.581 ;
     RECT  14.472 19.333 15.648 21.203 ;
     RECT  27.012 19.427 28.224 19.955 ;
     RECT  35.112 19.571 35.928 20.725 ;
     RECT  27.012 19.955 28.368 20.965 ;
     RECT  19.416 20.149 20.496 22.165 ;
     RECT  22.296 20.581 23.28 22.693 ;
     RECT  16.968 20.723 18.6 21.443 ;
     RECT  35.112 20.915 35.928 22.309 ;
     RECT  27.012 20.965 28.272 21.493 ;
     RECT  26.448 21.011 26.592 22.021 ;
     RECT  6.504 21.107 7.68 21.779 ;
     RECT  14.472 21.203 15.9 26.149 ;
     RECT  18.192 21.443 18.6 21.637 ;
     RECT  8.112 21.685 9.216 22.931 ;
     RECT  6.12 21.779 7.68 22.165 ;
     RECT  16.536 21.827 16.632 23.125 ;
     RECT  6.12 22.165 7.392 23.317 ;
     RECT  3.288 22.405 4.272 22.451 ;
     RECT  28.296 22.787 29.28 23.555 ;
     RECT  8.112 22.931 10.176 23.315 ;
     RECT  8.112 23.315 10.272 23.605 ;
     RECT  10.812 23.413 12.24 23.987 ;
     RECT  22.584 23.555 24 24.515 ;
     RECT  28.248 23.555 29.28 25.139 ;
     RECT  8.952 23.605 10.272 24.421 ;
     RECT  9.144 24.421 10.272 24.707 ;
     RECT  24.312 24.517 25.632 25.619 ;
     RECT  31.92 24.563 32.1 25.477 ;
     RECT  8.952 24.707 10.272 24.755 ;
     RECT  8.952 24.755 10.368 26.293 ;
     RECT  6.12 25.139 6.168 26.389 ;
     RECT  18.912 25.139 20.496 26.341 ;
     RECT  28.248 25.139 29.4 26.293 ;
     RECT  17.544 25.187 18.6 26.243 ;
     RECT  4.56 25.427 4.608 26.677 ;
     RECT  29.712 25.477 30.96 25.621 ;
     RECT  30.984 25.477 32.1 26.245 ;
     RECT  24.312 25.619 24.504 25.717 ;
     RECT  29.712 25.621 30.768 26.629 ;
     RECT  14.856 26.149 15.9 27.781 ;
     RECT  31.032 26.245 32.1 26.533 ;
     RECT  24.312 26.291 24.504 27.397 ;
     RECT  8.952 26.293 10.08 27.395 ;
     RECT  18.912 26.341 19.92 26.677 ;
     RECT  32.412 26.389 33.6 26.485 ;
     RECT  33.624 26.389 34.8 28.547 ;
     RECT  32.412 26.485 33.456 27.349 ;
     RECT  2.712 26.677 4.128 29.605 ;
     RECT  19.944 26.771 21.12 27.733 ;
     RECT  22.344 26.819 23.424 29.123 ;
     RECT  11.4 27.205 12.528 27.923 ;
     RECT  9.984 27.395 10.08 27.877 ;
     RECT  24.456 27.397 24.504 27.493 ;
     RECT  17.016 27.925 18.336 29.123 ;
     RECT  13.656 27.971 14.832 28.451 ;
     RECT  18.912 27.971 19.92 30.709 ;
     RECT  13.656 28.451 15.024 28.643 ;
     RECT  30.888 28.499 32.1 31.237 ;
     RECT  33.48 28.547 34.8 29.605 ;
     RECT  19.944 28.835 21.072 29.171 ;
     RECT  27.012 28.835 28.128 29.075 ;
     RECT  27.012 29.075 28.272 30.181 ;
     RECT  6.168 29.123 7.8 30.181 ;
     RECT  22.344 29.123 23.52 34.739 ;
     RECT  19.944 29.171 21.12 33.011 ;
     RECT  24.312 29.267 24.408 30.757 ;
     RECT  6.168 30.181 7.152 30.325 ;
     RECT  33.432 30.755 34.8 32.485 ;
     RECT  12.528 31.091 13.008 32.437 ;
     RECT  8.232 31.237 9.696 31.955 ;
     RECT  30.888 31.237 31.968 31.381 ;
     RECT  2.712 31.331 3.84 34.835 ;
     RECT  30.888 31.381 31.92 32.291 ;
     RECT  35.112 31.381 36.096 31.571 ;
     RECT  28.296 31.427 29.4 32.387 ;
     RECT  8.232 31.955 9.984 32.485 ;
     RECT  30.888 32.291 31.968 33.395 ;
     RECT  27.96 32.387 29.4 32.821 ;
     RECT  11.688 32.437 13.008 33.059 ;
     RECT  8.52 32.485 9.984 34.643 ;
     RECT  33.624 32.485 34.8 33.541 ;
     RECT  3.864 32.531 5.1 34.835 ;
     RECT  27.96 32.821 29.04 34.691 ;
     RECT  19.8 33.011 21.12 34.741 ;
     RECT  17.016 33.013 18.192 33.445 ;
     RECT  30.792 33.395 31.968 34.259 ;
     RECT  30.792 34.259 32.1 35.845 ;
     RECT  8.232 34.643 9.984 34.741 ;
     RECT  27.48 34.691 29.04 35.029 ;
     RECT  22.344 34.739 23.76 35.701 ;
     RECT  8.232 34.741 9.648 36.035 ;
     RECT  19.848 34.741 21.12 34.789 ;
     RECT  17.016 34.787 18.6 35.941 ;
     RECT  33.672 34.787 34.8 36.421 ;
     RECT  4.656 34.835 5.1 35.269 ;
     RECT  27.48 35.029 28.464 35.701 ;
     RECT  22.344 35.701 23.424 37.861 ;
     RECT  31.032 35.845 32.1 37.141 ;
     RECT  17.016 35.941 18 36.997 ;
     RECT  5.544 36.035 6.576 38.005 ;
     RECT  8.112 36.035 9.648 36.997 ;
     RECT  24.504 36.227 25.92 40.453 ;
     RECT  33.816 36.421 34.8 38.197 ;
     RECT  8.232 36.997 9.648 37.091 ;
     RECT  8.232 37.091 9.984 37.189 ;
     RECT  8.808 37.189 9.984 37.523 ;
     RECT  8.28 37.523 9.984 38.677 ;
     RECT  17.016 37.667 18 38.147 ;
     RECT  22.344 37.861 23.328 38.149 ;
     RECT  8.856 38.677 9.984 39.251 ;
     RECT  10.812 38.771 12.576 39.877 ;
     RECT  5.544 38.819 6.576 45.541 ;
     RECT  33.816 38.819 34.8 39.779 ;
     RECT  8.568 39.251 9.984 39.875 ;
     RECT  13.944 39.443 15.168 41.747 ;
     RECT  18.912 39.587 20.112 40.019 ;
     RECT  33.528 39.779 34.8 41.363 ;
     RECT  8.112 39.875 9.984 40.981 ;
     RECT  10.812 39.877 11.808 41.939 ;
     RECT  18.912 40.019 20.352 41.699 ;
     RECT  24.504 40.453 25.584 40.499 ;
     RECT  24.408 40.499 25.584 41.699 ;
     RECT  8.232 40.981 9.408 41.651 ;
     RECT  17.112 40.981 18.6 41.077 ;
     RECT  17.208 41.077 18.6 41.219 ;
     RECT  23.016 41.315 24 43.955 ;
     RECT  33.336 41.363 34.8 43.379 ;
     RECT  25.608 41.411 26.7 45.541 ;
     RECT  8.112 41.651 9.408 42.755 ;
     RECT  18.912 41.699 20.544 42.517 ;
     RECT  24.312 41.699 25.584 44.197 ;
     RECT  13.944 41.747 15.9 42.709 ;
     RECT  10.812 41.939 12.288 42.181 ;
     RECT  11.304 42.181 12.288 42.323 ;
     RECT  10.812 42.323 12.288 44.917 ;
     RECT  19.032 42.517 20.544 42.563 ;
     RECT  13.944 42.709 14.928 42.755 ;
     RECT  8.112 42.755 8.376 43.813 ;
     RECT  13.608 42.755 14.928 43.717 ;
     RECT  17.016 42.757 18.384 44.965 ;
     RECT  30.504 42.851 31.584 43.861 ;
     RECT  28.296 43.571 29.28 44.771 ;
     RECT  13.608 43.717 14.736 44.963 ;
     RECT  22.824 43.955 24 44.243 ;
     RECT  24.408 44.197 25.584 44.293 ;
     RECT  8.568 44.725 9.984 46.307 ;
     RECT  28.296 44.771 29.4 46.259 ;
     RECT  19.032 44.869 20.544 44.965 ;
     RECT  10.812 44.917 12 46.211 ;
     RECT  13.512 44.963 14.736 46.115 ;
     RECT  19.032 44.965 20.4 46.259 ;
     RECT  22.344 45.781 23.856 46.837 ;
     RECT  13.512 46.115 14.976 46.835 ;
     RECT  24.408 46.163 25.392 46.883 ;
     RECT  10.812 46.211 12.288 49.525 ;
     RECT  18.912 46.259 20.4 46.933 ;
     RECT  28.152 46.259 29.4 46.547 ;
     RECT  17.016 46.787 18.24 48.133 ;
     RECT  13.512 46.835 15.9 47.845 ;
     RECT  22.344 46.837 23.328 48.421 ;
     RECT  24.312 46.883 25.392 47.075 ;
     RECT  18.912 46.933 20.16 49.525 ;
     RECT  24.312 47.075 25.488 49.091 ;
     RECT  13.512 47.845 14.88 48.131 ;
     RECT  14.904 47.845 15.9 48.131 ;
     RECT  13.512 48.131 15.9 48.229 ;
     RECT  13.512 48.229 14.832 49.091 ;
     RECT  14.856 48.229 15.9 49.091 ;
     RECT  27.768 48.277 28.992 49.379 ;
     RECT  17.016 49.091 18.24 49.523 ;
     RECT  24.312 49.091 25.536 50.149 ;
     RECT  25.608 49.091 26.592 50.869 ;
     RECT  27.768 49.379 29.136 52.499 ;
     RECT  5.412 49.523 6.624 53.557 ;
     RECT  16.872 49.523 18.24 51.971 ;
     RECT  18.912 49.525 19.968 50.819 ;
     RECT  9.984 49.619 10.08 50.819 ;
     RECT  24.312 50.149 25.44 50.629 ;
     RECT  11.016 50.771 12.24 53.365 ;
     RECT  9.984 50.819 10.5 50.965 ;
     RECT  18.912 50.819 20.16 52.741 ;
     RECT  8.112 50.965 9.408 54.085 ;
     RECT  9.432 50.965 10.5 56.293 ;
     RECT  16.392 51.971 18.24 52.645 ;
     RECT  14.232 51.973 15.696 52.499 ;
     RECT  15.552 52.499 15.696 52.933 ;
     RECT  27.768 52.499 29.184 54.613 ;
     RECT  16.392 52.645 18.192 52.933 ;
     RECT  19.032 52.741 20.16 53.075 ;
     RECT  16.392 52.933 17.568 53.077 ;
     RECT  18.912 53.075 20.16 54.085 ;
     RECT  16.536 53.077 17.568 53.509 ;
     RECT  5.544 53.557 6.624 54.661 ;
     RECT  22.824 53.603 24 59.507 ;
     RECT  8.232 54.085 9.408 55.237 ;
     RECT  24.312 54.227 25.44 55.861 ;
     RECT  16.584 54.371 17.568 56.915 ;
     RECT  27.768 54.613 29.088 57.875 ;
     RECT  5.544 54.661 6.528 56.771 ;
     RECT  18.912 54.755 20.16 57.589 ;
     RECT  24.408 55.861 25.44 56.531 ;
     RECT  11.016 56.243 12.24 59.603 ;
     RECT  24.312 56.531 25.44 58.549 ;
     RECT  5.544 56.771 6.624 58.309 ;
     RECT  16.44 56.915 17.568 60.805 ;
     RECT  19.032 57.589 20.16 58.499 ;
     RECT  13.512 57.923 14.184 58.645 ;
     RECT  35.112 57.923 35.208 59.317 ;
     RECT  3.72 58.117 5.1 59.221 ;
     RECT  2.712 58.163 3.696 60.803 ;
     RECT  19.032 58.499 20.496 60.277 ;
     RECT  24.312 58.549 25.296 59.029 ;
     RECT  13.512 58.645 14.832 59.459 ;
     RECT  9.432 58.691 10.5 60.373 ;
     RECT  33.096 59.029 34.416 60.467 ;
     RECT  3.72 59.221 4.992 59.891 ;
     RECT  13.512 59.459 14.232 59.989 ;
     RECT  22.344 59.507 24 60.949 ;
     RECT  10.812 59.603 12.24 62.101 ;
     RECT  3.72 59.891 5.1 60.803 ;
     RECT  24.456 60.131 25.44 61.381 ;
     RECT  19.08 60.277 20.496 62.533 ;
     RECT  5.412 60.467 6.432 64.547 ;
     RECT  4.56 60.803 5.1 61.525 ;
     RECT  3.288 62.581 4.56 63.251 ;
     RECT  9.432 62.723 10.5 64.211 ;
     RECT  33.048 63.061 34.416 65.365 ;
     RECT  22.344 63.203 24 64.309 ;
     RECT  17.592 63.395 18.6 64.693 ;
     RECT  27.012 63.781 28.512 64.357 ;
     RECT  16.488 63.827 17.472 63.923 ;
     RECT  16.488 63.923 17.568 64.885 ;
     RECT  19.56 64.019 20.592 65.461 ;
     RECT  9.096 64.211 10.5 64.355 ;
     RECT  22.344 64.309 23.52 66.277 ;
     RECT  14.088 64.357 15.168 65.027 ;
     RECT  27.144 64.357 28.512 64.451 ;
     RECT  5.412 64.547 6.816 68.917 ;
     RECT  10.968 64.595 12.24 66.611 ;
     RECT  30.312 64.595 31.824 67.285 ;
     RECT  3.288 64.933 4.608 66.131 ;
     RECT  14.088 65.027 15.36 65.171 ;
     RECT  27.012 65.075 27.144 66.565 ;
     RECT  33.048 65.365 34.176 65.509 ;
     RECT  25.032 65.651 26.448 65.699 ;
     RECT  25.032 65.699 25.128 66.709 ;
     RECT  21.72 66.323 22.752 66.611 ;
     RECT  16.44 66.563 17.568 68.869 ;
     RECT  27.012 66.565 28.176 67.381 ;
     RECT  10.812 66.611 12.24 67.187 ;
     RECT  19.56 66.611 20.784 67.717 ;
     RECT  23.376 66.611 23.424 67.669 ;
     RECT  8.232 66.755 8.376 67.525 ;
     RECT  10.812 67.187 12.288 74.485 ;
     RECT  33.576 67.283 34.8 69.587 ;
     RECT  30.792 67.285 31.824 67.571 ;
     RECT  8.232 67.525 9.648 68.915 ;
     RECT  30.792 67.571 31.968 67.765 ;
     RECT  30.84 67.765 31.968 68.099 ;
     RECT  30.84 68.099 32.1 69.349 ;
     RECT  25.128 68.341 26.112 68.963 ;
     RECT  13.656 68.435 14.232 69.253 ;
     RECT  8.232 68.915 8.712 69.781 ;
     RECT  13.656 69.253 14.784 70.163 ;
     RECT  14.808 69.253 15.9 69.493 ;
     RECT  31.128 69.349 32.1 70.115 ;
     RECT  21.612 69.445 23.088 76.211 ;
     RECT  32.616 69.587 34.8 70.597 ;
     RECT  3.096 69.637 4.512 69.731 ;
     RECT  30.312 70.115 32.1 71.317 ;
     RECT  15.696 70.163 15.744 71.125 ;
     RECT  32.616 70.597 34.704 70.789 ;
     RECT  32.616 70.789 33.648 71.891 ;
     RECT  33.672 70.789 34.704 71.269 ;
     RECT  6.216 70.933 7.68 71.461 ;
     RECT  30.984 71.317 32.1 71.555 ;
     RECT  30.312 71.555 32.1 72.373 ;
     RECT  8.28 71.651 8.712 71.749 ;
     RECT  8.28 71.749 9.264 71.939 ;
     RECT  9.288 71.749 10.5 71.939 ;
     RECT  14.568 71.749 15.696 72.901 ;
     RECT  26.208 71.843 26.7 73.045 ;
     RECT  34.368 71.891 34.608 73.381 ;
     RECT  30.312 72.373 31.536 72.805 ;
     RECT  30.408 72.805 31.536 74.005 ;
     RECT  14.616 72.901 15.696 73.283 ;
     RECT  24.312 73.045 25.776 73.763 ;
     RECT  14.616 73.283 15.9 73.523 ;
     RECT  27.012 73.283 28.8 74.293 ;
     RECT  14.28 73.523 15.9 74.965 ;
     RECT  24.312 73.763 25.872 74.149 ;
     RECT  30.408 74.005 31.392 75.157 ;
     RECT  24.408 74.149 25.872 75.443 ;
     RECT  10.812 74.485 11.856 75.251 ;
     RECT  27.012 74.723 27.984 76.211 ;
     RECT  28.008 74.867 29.28 76.211 ;
     RECT  14.28 74.965 15.792 75.011 ;
     RECT  30.84 75.203 32.1 76.451 ;
     RECT  10.812 75.251 12.288 75.875 ;
     RECT  2.904 75.541 4.32 77.315 ;
     RECT  10.812 75.875 12.72 76.789 ;
     RECT  9.24 76.021 10.32 76.211 ;
     RECT  10.272 76.211 10.32 76.693 ;
     RECT  21.612 76.211 21.864 77.173 ;
     RECT  29.184 76.211 29.28 77.461 ;
     RECT  30.216 76.451 32.1 77.125 ;
     RECT  11.448 76.789 12.72 77.173 ;
     RECT  30.216 77.125 31.248 77.893 ;
     RECT  2.712 77.315 4.32 78.613 ;
     RECT  21.864 77.893 23.376 78.131 ;
     RECT  5.976 78.083 7.056 81.107 ;
     RECT  34.704 78.227 34.8 78.613 ;
     RECT  29.712 78.467 30.912 80.293 ;
     RECT  32.616 78.613 33.744 78.755 ;
     RECT  33.768 78.613 34.8 79.477 ;
     RECT  32.412 78.755 33.744 81.203 ;
     RECT  30.936 79.475 32.1 82.549 ;
     RECT  21.96 79.813 23.376 80.533 ;
     RECT  3.432 80.003 5.1 80.771 ;
     RECT  29.832 80.293 30.912 82.115 ;
     RECT  1.176 80.533 2.4 81.059 ;
     RECT  2.712 80.771 5.1 81.061 ;
     RECT  21.96 81.011 23.376 82.307 ;
     RECT  2.712 81.061 4.608 82.021 ;
     RECT  5.88 81.107 7.056 82.163 ;
     RECT  14.232 81.445 15.264 81.491 ;
     RECT  14.232 81.491 15.408 82.019 ;
     RECT  18.912 81.491 19.92 84.181 ;
     RECT  26.208 81.539 26.256 82.789 ;
     RECT  3.384 82.021 4.608 83.221 ;
     RECT  29.712 82.115 30.912 83.317 ;
     RECT  21.912 82.307 23.376 85.283 ;
     RECT  15.792 82.451 15.9 83.749 ;
     RECT  30.936 82.549 31.968 84.371 ;
     RECT  25.128 82.789 26.256 83.171 ;
     RECT  25.128 83.171 26.592 84.325 ;
     RECT  34.176 83.171 34.224 84.325 ;
     RECT  3.624 83.221 4.608 83.363 ;
     RECT  29.832 83.317 30.912 84.371 ;
     RECT  3.192 83.363 4.608 84.517 ;
     RECT  25.128 84.325 26.544 84.995 ;
     RECT  31.872 84.371 31.968 85.381 ;
     RECT  11.256 84.611 12.576 84.851 ;
     RECT  3.192 84.707 4.608 84.995 ;
     RECT  11.256 84.851 12.624 85.957 ;
     RECT  2.712 84.995 4.608 86.005 ;
     RECT  24.504 84.995 26.544 86.293 ;
     RECT  21.912 85.283 22.104 86.005 ;
     RECT  17.016 85.523 18 86.291 ;
     RECT  9.144 85.573 10.5 85.715 ;
     RECT  19.08 85.667 20.496 87.109 ;
     RECT  9.048 85.715 10.5 87.683 ;
     RECT  11.4 85.957 12.624 86.099 ;
     RECT  3.48 86.005 4.608 87.251 ;
     RECT  29.712 86.051 29.832 87.157 ;
     RECT  11.4 86.099 12.816 86.675 ;
     RECT  16.536 86.291 18 86.773 ;
     RECT  24.504 86.293 25.68 86.917 ;
     RECT  5.412 86.725 6.816 87.827 ;
     RECT  16.536 86.773 17.952 87.251 ;
     RECT  24.504 87.107 25.632 87.827 ;
     RECT  32.412 87.109 33.552 88.499 ;
     RECT  18.912 87.155 20.016 89.555 ;
     RECT  29.712 87.157 30.864 87.205 ;
     RECT  30.888 87.157 31.872 88.691 ;
     RECT  29.712 87.205 30.72 88.691 ;
     RECT  16.44 87.251 17.952 88.067 ;
     RECT  25.704 87.347 26.7 87.395 ;
     RECT  25.656 87.395 26.7 87.827 ;
     RECT  14.712 87.445 15.9 89.941 ;
     RECT  16.44 88.067 18.6 89.363 ;
     RECT  32.412 88.499 32.568 89.317 ;
     RECT  34.128 88.499 34.512 88.643 ;
     RECT  34.128 88.643 34.656 89.845 ;
     RECT  29.712 88.691 31.872 88.979 ;
     RECT  29.712 88.979 30.36 89.029 ;
     RECT  17.952 89.363 18.6 89.461 ;
     RECT  12.816 89.555 12.912 90.517 ;
     RECT  14.712 89.941 15.792 90.037 ;
     RECT  27.012 89.989 28.464 92.339 ;
     RECT  11.256 90.517 12.672 91.859 ;
     RECT  32.412 90.611 32.52 91.861 ;
     RECT  21.612 91.717 22.896 92.435 ;
     RECT  22.92 91.717 24 92.435 ;
  END
END dsfd_dvland_512
END LIBRARY
